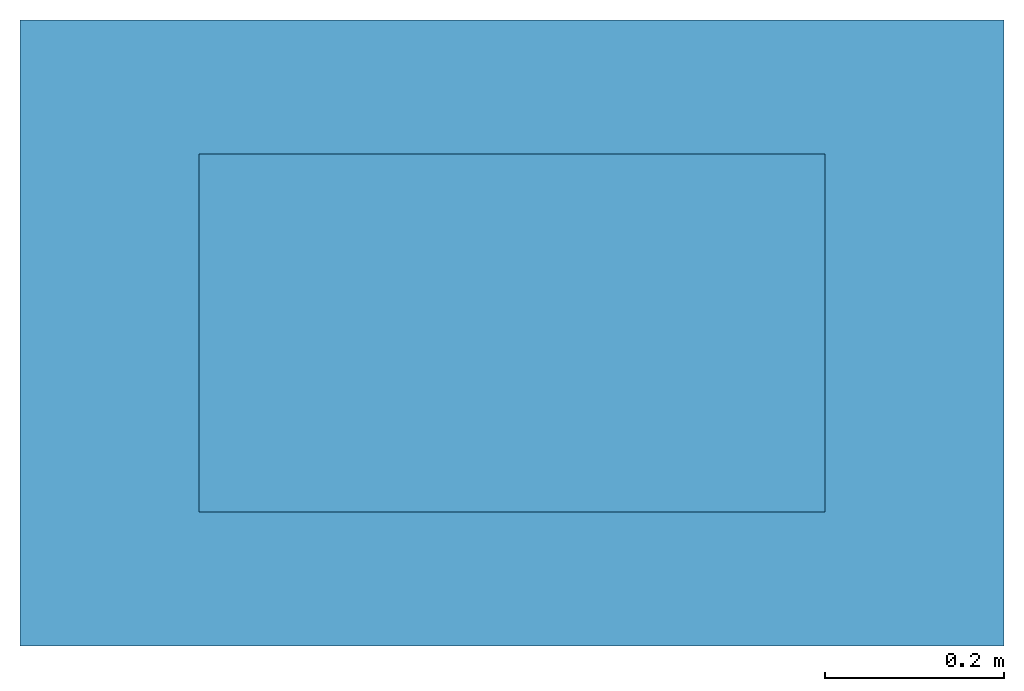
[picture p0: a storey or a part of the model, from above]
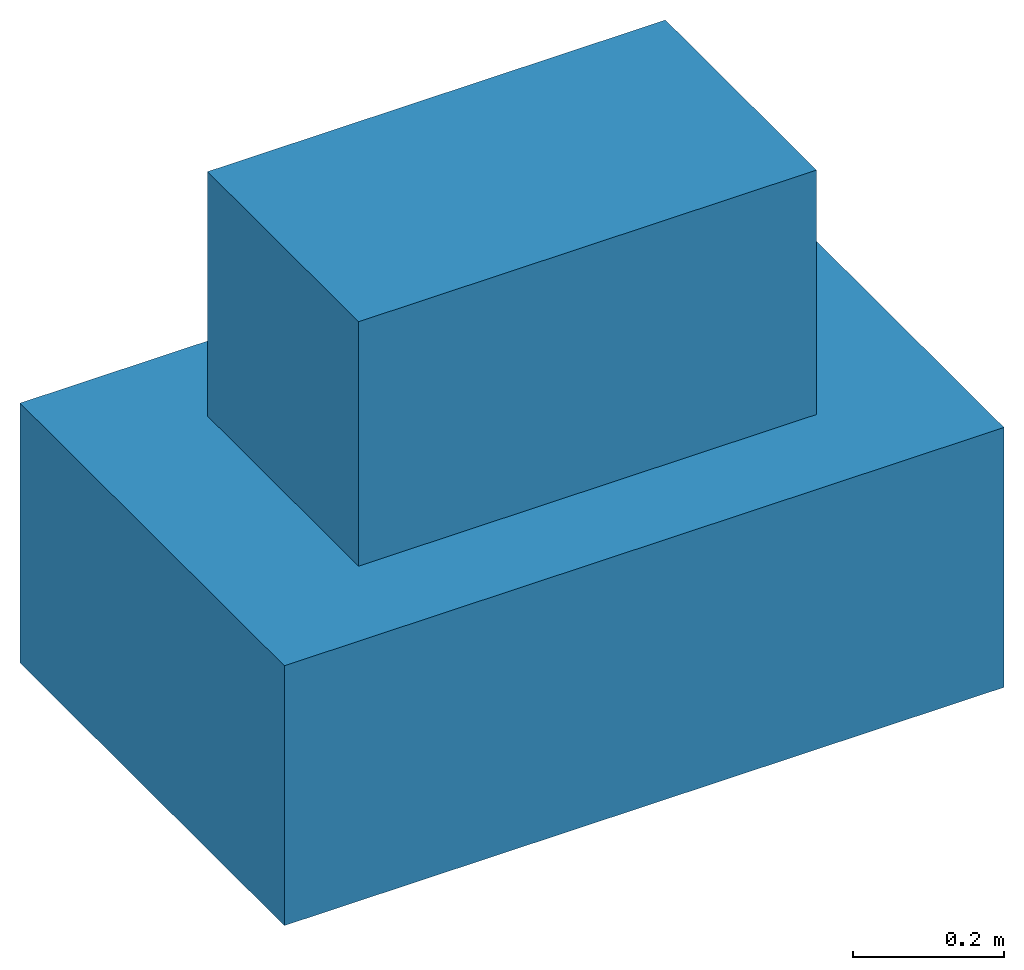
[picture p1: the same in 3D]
Properties of the parts of a building model (IFC2X3), part 1 of 5

# File
Description: ViewDefinition [CoordinationView]
File name: gmtso-a-200-1-0001.ifc (Edited by Naviate Simple BIM 2022 version 6)
Time: 2026-03-17T17:04:53+01:00
Written by: ODA SDAI 24.12
Made in: Autodesk Revit 25.4.20.11 (ENU) - IFC 25.4.0.27

# IfcProject, A181143
LongName: T2; Phase: Detaljprosjekt

# IfcSite (9)
Name | RefLatitude | RefLongitude | RefElevation (mm) | Reference latitude | Reference elevation | Reference longitude
ENGM | 33, 12, 51, 119999 | -97, -7, -51, -239999 | -4.85124e-10
 | 33, 12, 51, 119999 | -97, -7, -51, -239999 | 0
 | 33, 12, 51, 119999 | -97, -7, -51, -239999 | 0 | 33, 12, 51, 119999 | 0 | -97, -7, -51, -239999
4 x ENGM | 59, 54, 49, 759826 | 10, 44, 19, 467315 | 0 | 59, 54, 49, 759826 | 0 | 10, 44, 19, 467315 | MagiCAD Pset_Site - Name: ENGM
Gardermoen
Default | 59, 54, 49, 759826 | 10, 44, 19, 467315 | 0

# IfcBuilding (9)
Name
TS | LongName: TS; Pset_BuildingCommon - NumberOfStoreys: 16
2 x mc-building
4 x TS | MagiCAD Pset_Building - Building name: TS
TS
 | Pset_BuildingCommon - NumberOfStoreys: 13

# IfcBuildingStorey (16)
Name | In | Elevation (mm) | Name
Nivå C | mc-building | 200300
Nivå D | mc-building | 204000
Nivå D + 1,2 m | mc-building | 205200
Nivå C | mc-building | 200300 | Nivå C
Nivå D | mc-building | 204000 | Nivå D
Nivå D + 1,2 m | mc-building | 205200 | Nivå D + 1,2 m
4 x Nivå D | TS | 204000 | Nivå D
D | TS | 0
C | TS | 0
B | TS | 0
A | TS | 0
2 x Nivå C | TS | 200300 | Nivå C

# IfcBuildingStorey: Level:8mm Head (2)
Name | LongName | Elevation (mm)
Nivå C | Nivå C | 200300 | Pset_ProductRequirements - Name: Nivå C; sets with these values: 2
Nivå D | Nivå D | 204000 | Pset_AirSideSystemInformation - Name: Nivå D; sets with these values: 2

# IfcBuildingStorey: Level:T2 - Kote (4)
In: TS
Name | LongName | Elevation (mm) | Pset_AirSideSystemInformation, Name | Pset_AirSideSystemInformation, sets with these values
Nivå C + 2,03 m | Nivå C + 2,03 m | 202330 | Nivå C + 2,03 m | 2
Nivå D | Nivå D | 204000 | Nivå D | 2
Nivå D + 1,2 m | Nivå D + 1,2 m | 205200 | Pset_ProductRequirements - Name: Nivå D + 1,2 m; sets with these values: 2
Nivå E | Nivå E | 207370 | Nivå E | 2

# IfcBeam: 10*150 (3)
In: D
Description: 10*150
Pset_BeamCommon - LoadBearing: no
ePset_SimplebimBasicQuantities - Height (Simplebim): 10 mm; Width (Simplebim): 150 mm
ePset_Simplebim - Assembly Level: Leaf
AVINOR - 07_Fase: F90; 06_Omrade: TS; 01_Lufthavnkode: ENGM
Tekla Common - Grade: S355; Name: STÅLBJELKE; Profile: 10*150; Class: 330; Bottom elevation: +206.915; Top elevation: +206.925
Name | Reference = Part mark | Area, sides, net (Simplebim) (m2) | Weight, as steel (Simplebim) (kg) | Volume, net (Simplebim) (m3) | Length (Simplebim) (mm) | 02_Prosjekt | 04_Kontrakt | 03_Ansvar | 08_Status | Splitting | Assembly mark
STÅLBJELKE | DSB-8061(?) | 1.53612 | 56.4142 | 0.00718652 | 4791.01 | T1 | FDV | FDV | S2 | ORIGINAL | SB-3691(?) | Material: STEEL/S355; Tekla Quantity - VOLUME_GROSS: 0.00718 m3; VOLUME_NET: 0.00718 m3; AREA_NET: 1.53612 m2; AREA_GROSS: 1.53612 m2; WEIGTH_GROSS: 56.4142 kg; Heigth: 10 mm; Width: 150 mm; Length: 4791.01 mm; WEIGTH_NET: 56.4142 kg
STÅLBJELKE | DSB-8066(?) | 0.492661 | 18.018 | 0.00229529 | 1530 | T1 | FDV | FDV | S2 | RESULT | SB-3707(?)
STÅLBJELKE | DSB-8058(?) | 2.05458 | 75.4918 | 0.00961679 | 6411 | T20100 | 72274 | 72101 | S4 | RESULT | SB-3703(?) | AVINOR - 05_ID-nummer: +TS=223.001

# IfcBeam: 10*180, STÅLBJELKE
In: D
Description: 10*180; Material: STEEL/S355
Pset_BeamCommon - Reference: DSB-21700(?); LoadBearing: no
ePset_LocationTool - Splitting: ORIGINAL
ePset_Simplebim - Assembly Level: Leaf
Tekla Common - Assembly mark: SB-12634(?); Grade: S355; Bottom elevation: +206.790; Name: STÅLBJELKE; Part mark: DSB-21700(?); Profile: 10*180; Top elevation: +206.800; Class: 330
Tekla Quantity - VOLUME_GROSS: 0.01076 m3; VOLUME_NET: 0.01076 m3; WEIGTH_GROSS: 84.4974 kg; WEIGTH_NET: 84.4974 kg; AREA_GROSS: 2.276 m2; AREA_NET: 2.276 m2; Heigth: 10 mm; Width: 180 mm; Length: 5980 mm
AVINOR - 08_Status: S4; 07_Fase: F90; 05_ID-nummer: +TS=223.008; 02_Prosjekt: T20100; 04_Kontrakt: 72233; 03_Ansvar: 72101; 06_Omrade: TS; 01_Lufthavnkode: ENGM
ePset_SimplebimBasicQuantities - Volume, net (Simplebim): 0.010764 m3; Weight, as steel (Simplebim): 84.4974 kg; Area, sides, net (Simplebim): 2.276 m2; Height (Simplebim): 10 mm; Width (Simplebim): 180 mm; Length (Simplebim): 5980 mm

# IfcBeam: 10*220 (3)
In: D
Description: 10*220
AVINOR - 08_Status: S4; 07_Fase: F90; 04_Kontrakt: 72274; 05_ID-nummer: +TS=223.001; 02_Prosjekt: T20100; 03_Ansvar: 72101; 06_Omrade: TS; 01_Lufthavnkode: ENGM
Tekla Common - Grade: S355; Profile: 10*220; Name: STÅLBJELKE; Class: 330; Bottom elevation: +206.915; Top elevation: +206.925
Pset_BeamCommon - LoadBearing: no
ePset_Simplebim - Assembly Level: Leaf
ePset_LocationTool - Splitting: RESULT
ePset_SimplebimBasicQuantities - Height (Simplebim): 10 mm; Width (Simplebim): 220 mm
Name | Part mark = Reference | Assembly mark | Area, sides, net (Simplebim) (m2) | Weight, as steel (Simplebim) (kg) | Volume, net (Simplebim) (m3) | Length (Simplebim) (mm)
2 x STÅLBJELKE | DSB-8060(?) | SB-3690(?) | 2.94895 | 110.549 | 0.0140826 | 6401
STÅLBJELKE | DSB-8059(?) | SB-3695(?) | 2.79255 | 104.677 | 0.0133346 | 6061

# IfcBeam: 4*595 (5)
In: D
Description: 4*595
AVINOR - 08_Status: S4; 07_Fase: F90; 04_Kontrakt: 72717; 02_Prosjekt: T20100; 05_ID-nummer: +TS=221.014; 03_Ansvar: 72101; 06_Omrade: TS; 01_Lufthavnkode: ENGM
Tekla Common - Grade: S355; Name: STÅLBJELKE; Bottom elevation: +206.505; Class: 330; Top elevation: +207.100; Profile: 4*595
ePset_Simplebim - Assembly Level: Leaf
Pset_BeamCommon - LoadBearing: no
Name | Material | Part mark = Reference | Assembly mark | Volume, net (Simplebim) (m3) | Area, sides, net (Simplebim) (m2) | Length (Simplebim) (mm) | Width (Simplebim) (mm) | Height (Simplebim) (mm) | Weight, as steel (Simplebim) (kg) | Splitting | VOLUME_GROSS (m3) | AREA_NET (m2) | WEIGTH_GROSS (kg) | AREA_GROSS (m2) | VOLUME_NET (m3) | Length (mm) | Heigth (mm) | Width (mm) | WEIGTH_NET (kg)
STÅLBJELKE | STEEL/S355 | DSB-24371(?) | SB-7501(?) | 0.00986281 | 4.9715 | 4232.91 | 74.3506 | 595 | 77.423 | ORIGINAL | 0.01008 | 4.9715 | 79.1282 | 5.07865 | 0.00986 | 4235.31 | 4 | 595 | 77.423
STÅLBJELKE | STEEL/S355 | DSB-24372(?) | SB-7500(?) | 0.00832178 | 4.19363 | 3495.28 | 50.3079 | 595 | 65.326 | ORIGINAL | 0.00831 | 4.19363 | 65.3262 | 4.19363 | 0.00833 | 3496.56 | 4 | 595 | 65.326
STÅLBJELKE | STEEL/S355 | DSB-24373(?) | SB-7499(?) | 0.00864702 | 4.35733 | 3632.5 | 39.8393 | 595 | 67.8791 | ORIGINAL | 0.00865 | 4.35733 | 67.8791 | 4.35733 | 0.00865 | 3633.2 | 4 | 595 | 67.8791
STÅLBJELKE | STEEL/S355 | DSB-24375(?) | SB-7498(?) | 0.00901992 | 4.54504 | 3788.23 | 55.5964 | 595 | 70.8064 | ORIGINAL | 0.00902 | 4.54504 | 70.8065 | 4.54504 | 0.00902 | 3789.89 | 4 | 595 | 70.8064
STÅLBJELKE |  | DSB-24374(?) | SB-7497(?) | 0.00682394 | 3.4403 | 2868 | 51 | 596 | 53.5679 | RESULT

# IfcBeam: A255 - beslag mellom glassvegg&dekke - brannskille - nivåD SBØ bagasjehall-ensidig:A255 - Beslag_112.5 (3)
In: Nivå E
Type - PredefinedType: BEAM
Type - Pset_BeamCommon - LoadBearing: yes
ePset_SimplebimBasicQuantities - Height (Simplebim): 112 mm; Width (Simplebim): 65 mm
ePset_LocationTool - Splitting: RESULT
Pset_QuantityTakeOff - Reference: A255 - Beslag_112.5; sets with these values: 2
Pset_BeamCommon - IsExternal: no; Reference: A255 - Beslag_112.5
ePset_Simplebim - Assembly Level: Leaf
AVINOR - 07_Fase: F90; 03_Ansvar: FDV; 08_Status: S2; 04_Kontrakt: 72274; 06_Omrade: TS; 01_Lufthavnkode: ENGM
Name (A255 - beslag mellom glassvegg&dekke - brannskille - nivåD SBØ bagasjehall-ensidig:A255 - Beslag_112.5:...) | Weight, as steel (Simplebim) (kg) | Length (Simplebim) (mm) | Area, sides, net (Simplebim) (m2) | Volume, net (Simplebim) (m3)
25088858 | 6.79764 | 4546 | 1.74135 | 0.000865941
25066476 | 18.147 | 12135 | 4.64809 | 0.00231172
26879168 | 18.147 | 12135 | 4.64809 | 0.00231172

# IfcBeam: D12 (6)
In: D
Description: D12; Material: STEEL/S355
ePset_SimplebimBasicQuantities - Volume, net (Simplebim): 0.0000112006 m3; Weight, as steel (Simplebim): 0.0879245 kg; Width (Simplebim): 12 mm; Height (Simplebim): 12 mm; Length (Simplebim): 110 mm; Area, sides, net (Simplebim): 0.00424478 m2
AVINOR - 08_Status: S4; 07_Fase: F90; 02_Prosjekt: T20100; 05_ID-nummer: +TS=223.013; 04_Kontrakt: 72233; 03_Ansvar: 72101; 06_Omrade: TS; 01_Lufthavnkode: ENGM
ePset_LocationTool - Splitting: ORIGINAL
ePset_Simplebim - Assembly Level: Leaf
Pset_BeamCommon - LoadBearing: no; Reference: DSB-22016(?)
Tekla Quantity - VOLUME_NET: 0.00001 m3; VOLUME_GROSS: 0.00001 m3; WEIGTH_NET: 0.08792 kg; WEIGTH_GROSS: 0.08792 kg; Heigth: 12 mm; Width: 12 mm; Length: 110 mm; AREA_GROSS: 0.00424 m2; AREA_NET: 0.00424 m2
Tekla Common - Grade: S355; Profile: D12; Name: STÅLBJELKE; Top elevation: +203.846; Bottom elevation: +203.834; Part mark: DSB-22016(?); Class: 330; Assembly mark: SB-13164(?)

# IfcBeam: D16 (2)
In: D
Description: D16; Material: STEEL/S355
ePset_SimplebimBasicQuantities - Width (Simplebim): 16 mm; Length (Simplebim): 16 mm; Height (Simplebim): 660 mm; Area, sides, net (Simplebim): 0.0326911 m2; Weight, as steel (Simplebim): 0.937861 kg; Volume, net (Simplebim): 0.000119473 m3
AVINOR - 08_Status: S4; 07_Fase: F90; 02_Prosjekt: T20100; 05_ID-nummer: +TS=223.013; 04_Kontrakt: 72233; 03_Ansvar: 72101; 06_Omrade: TS; 01_Lufthavnkode: ENGM
ePset_Simplebim - Assembly Level: Leaf
Pset_BeamCommon - Reference: DSM-555(?); LoadBearing: no
ePset_LocationTool - Splitting: ORIGINAL
Tekla Quantity - WEIGTH_GROSS: 0.93786 kg; WEIGTH_NET: 0.93786 kg; Heigth: 16 mm; Width: 16 mm; Length: 660 mm; AREA_NET: 0.03269 m2; AREA_GROSS: 0.03269 m2; VOLUME_GROSS: 0.00012 m3; VOLUME_NET: 0.00012 m3
Tekla Common - Grade: S355; Profile: D16; Part mark: DSM-555(?); Name: STÅLMONTASJE; Bottom elevation: +203.310; Class: 370; Assembly mark: SM-499(?); Top elevation: +203.970

# IfcBeam: D26.75 (4)
In: D
Description: D26.75; Material: STEEL/Steel_Undefined
ePset_SimplebimBasicQuantities - Weight, as steel (Simplebim): 0.0623505 kg; Height (Simplebim): 14.8 mm; Area, sides, net (Simplebim): 0.00230294 m2; Width (Simplebim): 26.75 mm; Length (Simplebim): 26.75 mm; Volume, net (Simplebim): 0.00000794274 m3
AVINOR - 08_Status: S4; 07_Fase: F90; 02_Prosjekt: T20100; 05_ID-nummer: +TS=223.013; 04_Kontrakt: 72233; 03_Ansvar: 72101; 06_Omrade: TS; 01_Lufthavnkode: ENGM
ePset_Simplebim - Assembly Level: Leaf
Tekla Common - Profile: D26.75; Part mark: DSSP-0(?); Class: 380; Name: MUTTER; Assembly mark: SSP-0(?); Grade: Steel_Undefined
Tekla Quantity - VOLUME_NET: 0.00001 m3; VOLUME_GROSS: 0.00001 m3; Length: 14.8 mm; WEIGTH_NET: 0.06235 kg; WEIGTH_GROSS: 0.06235 kg; AREA_GROSS: 0.0023 m2; AREA_NET: 0.0023 m2; Heigth: 26.75 mm; Width: 26.75 mm
Pset_BeamCommon - Reference: DSSP-0(?); LoadBearing: no
ePset_LocationTool - Splitting: ORIGINAL
Name | Bottom elevation | Top elevation
2 x MUTTER | +203.343 | +203.358
2 x MUTTER | +203.945 | +203.960

# IfcBeam: DLB400*815-700*420 (6)
In: D
Description: DLB400*815-700*420
Pset_BeamCommon - LoadBearing: no
ePset_SimplebimBasicQuantities - Width (Simplebim): 700 mm
Tekla Common - Name: PREFABBJELKE; Top elevation: +203.795; Grade: C45/55; Bottom elevation: +202.980; Class: 130; Profile: DLB400*815-700*420
ePset_Simplebim - Assembly Level: Leaf
AVINOR - 07_Fase: F90; 02_Prosjekt: T1; 04_Kontrakt: FDV; 03_Ansvar: FDV; 08_Status: S2; 06_Omrade: TS; 01_Lufthavnkode: ENGM
Name | Reference = Part mark | Volume, net (Simplebim) (m3) | Area, sides, net (Simplebim) (m2) | Height (Simplebim) (mm) | Length (Simplebim) (mm) | Weight, as steel (Simplebim) (kg) | Assembly mark | Splitting
PREFABBJELKE | Concrete-9026(?) | 3.76884 | 26.2761 | 815 | 8470 | 29585.4 | PB-322(?) | ORIGINAL | Material: CONCRETE/C45/55; Tekla Quantity - WEIGTH_GROSS: 9188.26 kg; VOLUME_NET: 3.76884 m3; WEIGTH_NET: 9045.22 kg; AREA_NET: 26.2761 m2; AREA_GROSS: 26.5681 m2; Heigth: 815 mm; Width: 700 mm; Length: 8470 mm; VOLUME_GROSS: 3.82844 m3
PREFABBJELKE | Concrete-4942(?) | 3.83664 | 26.7306 | 815 | 8620 | 30117.6 | PB-171(?) | ORIGINAL | Material: CONCRETE/C45/55; Tekla Quantity - WEIGTH_GROSS: 9350.98 kg; VOLUME_NET: 3.83664 m3; WEIGTH_NET: 9207.94 kg; AREA_NET: 26.7306 m2; AREA_GROSS: 27.0226 m2; Heigth: 815 mm; Width: 700 mm; Length: 8620 mm; VOLUME_GROSS: 3.89624 m3
PREFABBJELKE | Concrete-4942(?) | 2.76737 | 19.4552 | 816 | 6123 | 21723.9 | PB-171(?) | RESULT
PREFABBJELKE | Concrete-4942(?) | 1.17436 | 8.8839 | 816 | 2730 | 9218.73 | PB-171(?) | RESULT
PREFABBJELKE | Concrete-9026(?) | 2.69957 | 19.0007 | 816 | 5973 | 21191.6 | PB-322(?) | RESULT
PREFABBJELKE | Concrete-9031(?) | 1.17436 | 8.8839 | 816 | 2730 | 9218.73 | PB-327(?) | RESULT

# IfcBeam: HE180A, STÅLBJELKE
In: D
Description: HE180A; Material: STEEL/S355
Tekla Common - Grade: S355; Name: STÅLBJELKE; Bottom elevation: +206.929; Assembly mark: SB-3300(?); Part mark: DSB-7520(?); Profile: HE180A; Class: 330; Top elevation: +207.100
AVINOR - 08_Status: S4; 07_Fase: F90; 04_Kontrakt: 72717; 02_Prosjekt: T20100; 05_ID-nummer: +TS=221.014; 03_Ansvar: 72101; 06_Omrade: TS; 01_Lufthavnkode: ENGM
ePset_SimplebimBasicQuantities - Weight, as steel (Simplebim): 64.561 kg; Length (Simplebim): 2017.32 mm; Volume, net (Simplebim): 0.00822433 m3; Area, sides, net (Simplebim): 2.00413 m2; Width (Simplebim): 180 mm; Height (Simplebim): 171 mm
Tekla Quantity - Length: 2017.32 mm; VOLUME_NET: 0.00822 m3; WEIGTH_NET: 64.561 kg; VOLUME_GROSS: 0.00913 m3; AREA_GROSS: 2.06574 m2; AREA_NET: 2.00413 m2; Width: 180 mm; Heigth: 171 mm; WEIGTH_GROSS: 71.6577 kg
Pset_BeamCommon - LoadBearing: no; Reference: DSB-7520(?)
ePset_Simplebim - Assembly Level: Leaf
ePset_LocationTool - Splitting: ORIGINAL

# IfcBeam: HEA240, STÅLBJELKE
In: D
Description: HEA240
AVINOR - 08_Status: S4; 07_Fase: F90; 02_Prosjekt: T20100; 05_ID-nummer: +TS=223.013; 04_Kontrakt: 72233; 03_Ansvar: 72101; 06_Omrade: TS; 01_Lufthavnkode: ENGM
ePset_Simplebim - Assembly Level: Leaf
ePset_LocationTool - Splitting: RESULT
ePset_SimplebimBasicQuantities - Weight, as steel (Simplebim): 211.457 kg; Area, sides, net (Simplebim): 5.19555 m2; Volume, net (Simplebim): 0.0269372 m3; Height (Simplebim): 230 mm; Width (Simplebim): 240 mm; Length (Simplebim): 3687 mm
Tekla Common - Grade: S355; Name: STÅLBJELKE; Profile: HEA240; Assembly mark: SB-9965(?); Bottom elevation: +203.155; Top elevation: +203.385; Part mark: DSB-20486(?); Class: 330
Pset_BeamCommon - LoadBearing: no; Reference: DSB-20486(?)

# IfcBeam: HSQ150*5-20*200-12*400, STÅLBJELKE
In: D
Description: HSQ150*5-20*200-12*400; Material: STEEL/S355
Tekla Quantity - AREA_NET: 9.08332 m2; AREA_GROSS: 9.08332 m2; WEIGTH_GROSS: 410.743 kg; WEIGTH_NET: 410.743 kg; VOLUME_NET: 0.05232 m3; VOLUME_GROSS: 0.05232 m3; Heigth: 162 mm; Width: 400 mm; Length: 5080 mm
ePset_SimplebimBasicQuantities - Area, sides, net (Simplebim): 9.08332 m2; Weight, as steel (Simplebim): 410.743 kg; Length (Simplebim): 5080 mm; Volume, net (Simplebim): 0.052324 m3; Height (Simplebim): 162 mm; Width (Simplebim): 400 mm
Tekla Common - Profile: HSQ150*5-20*200-12*400; Grade: S355; Top elevation: +207.530; Name: STÅLBJELKE; Part mark: DSB-0(?); Assembly mark: SB-0(?); Class: 330; Bottom elevation: +207.368
ePset_Simplebim - Assembly Level: Leaf
AVINOR - 08_Status: S2; 07_Fase: F20; 02_Prosjekt: A181143; 03_Ansvar: 187259; 06_Omrade: TS; 01_Lufthavnkode: ENGM
Pset_BeamCommon - LoadBearing: no; Reference: DSB-0(?)
ePset_LocationTool - Splitting: ORIGINAL

# IfcBeam: IPE240, STÅLBJELKE
In: D
Description: IPE240
ePset_LocationTool - Splitting: RESULT
ePset_SimplebimBasicQuantities - Weight, as steel (Simplebim): 135.86 kg; Area, sides, net (Simplebim): 4.41787 m2; Width (Simplebim): 120 mm; Height (Simplebim): 240 mm; Length (Simplebim): 4654 mm; Volume, net (Simplebim): 0.017307 m3
Tekla Common - Grade: S355; Assembly mark: SB-3244(?); Name: STÅLBJELKE; Top elevation: +207.040; Profile: IPE240; Bottom elevation: +206.800; Part mark: DSB-7536(?); Class: 330
ePset_Simplebim - Assembly Level: Leaf
AVINOR - 07_Fase: F90; 02_Prosjekt: T1; 04_Kontrakt: FDV; 03_Ansvar: FDV; 08_Status: S2; 06_Omrade: TS; 01_Lufthavnkode: ENGM
Pset_BeamCommon - LoadBearing: no; Reference: DSB-7536(?)

# IfcBeam: L100*75*10, STÅLBJELKE
In: D
Description: L100*75*10; Material: STEEL/S355
ePset_SimplebimBasicQuantities - Width (Simplebim): 300.021 mm; Weight, as steel (Simplebim): 10.9997 kg; Area, sides, net (Simplebim): 0.30223 m2; Volume, net (Simplebim): 0.00140124 m3; Length (Simplebim): 732.931 mm; Height (Simplebim): 100 mm
Pset_BeamCommon - LoadBearing: no; Reference: DSB-9035(?)
AVINOR - 08_Status: S4; 07_Fase: F90; 04_Kontrakt: 72274; 05_ID-nummer: +TS=223.001; 02_Prosjekt: T20100; 03_Ansvar: 72101; 06_Omrade: TS; 01_Lufthavnkode: ENGM
ePset_Simplebim - Assembly Level: Leaf
Tekla Common - Grade: S355; Profile: L100*75*10; Name: STÅLBJELKE; Top elevation: +207.005; Assembly mark: SB-4427(?); Part mark: DSB-9035(?); Class: 330; Bottom elevation: +206.905
Tekla Quantity - VOLUME_NET: 0.0014 m3; WEIGTH_NET: 10.9997 kg; AREA_GROSS: 0.35517 m2; Length: 924.03 mm; VOLUME_GROSS: 0.00165 m3; Width: 10 mm; Heigth: 100 mm; AREA_NET: 0.30223 m2; WEIGTH_GROSS: 12.9587 kg
ePset_LocationTool - Splitting: ORIGINAL

# IfcBeam: L120*80*10, STÅLBJELKE
In: D
Description: L120*80*10
AVINOR - 08_Status: S4; 07_Fase: F90; 02_Prosjekt: T1; 04_Kontrakt: FDV; 03_Ansvar: FDV; 06_Omrade: TS; 01_Lufthavnkode: ENGM
ePset_LocationTool - Splitting: RESULT
Pset_BeamCommon - Reference: DSB-11255(?); LoadBearing: no
ePset_Simplebim - Assembly Level: Leaf
ePset_SimplebimBasicQuantities - Weight, as steel (Simplebim): 47.0027 kg; Volume, net (Simplebim): 0.0059876 m3; Height (Simplebim): 120 mm; Width (Simplebim): 80 mm; Length (Simplebim): 3185 mm; Area, sides, net (Simplebim): 1.26645 m2
Tekla Common - Grade: S355; Bottom elevation: +206.780; Part mark: DSB-11255(?); Top elevation: +206.900; Name: STÅLBJELKE; Profile: L120*80*10; Assembly mark: SB-6293(?); Class: 330

# IfcBeam: L40*5 (4)
In: D
Description: L40*5; Material: STEEL/S355
AVINOR - 08_Status: S4; 07_Fase: F90; 02_Prosjekt: T20100; 05_ID-nummer: +TS=222.012; 04_Kontrakt: 72233; 03_Ansvar: 72101; 06_Omrade: TS; 01_Lufthavnkode: ENGM
ePset_Simplebim - Assembly Level: Leaf
Pset_BeamCommon - LoadBearing: no
ePset_SimplebimBasicQuantities - Width (Simplebim): 40 mm; Height (Simplebim): 40 mm
ePset_LocationTool - Splitting: ORIGINAL
Tekla Common - Grade: S355; Top elevation: +207.315; Profile: L40*5; Name: STÅLBJELKE; Assembly mark: SB-12652(?); Bottom elevation: +207.275; Class: 330
Tekla Quantity - Heigth: 40 mm; Width: 40 mm
Name | Reference = Part mark | Length (Simplebim) (mm) = Length (mm) | Weight, as steel (Simplebim) (kg) = WEIGTH_NET (kg) | Area, sides, net (Simplebim) (m2) | Volume, net (Simplebim) (m3) | VOLUME_GROSS (m3) | VOLUME_NET (m3) | AREA_GROSS (m2) | AREA_NET (m2) | WEIGTH_GROSS (kg)
STÅLBJELKE | DSB-24535(?) | 1848.34 | 5.35295 | 0.291955 | 0.000681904 | 0.0007 | 0.00068 | 0.28649 | 0.29195 | 5.4991
STÅLBJELKE | DSB-24534(?) | 2369.08 | 6.89792 | 0.375874 | 0.000878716 | 0.0009 | 0.00088 | 0.36721 | 0.37587 | 7.04837
STÅLBJELKE | DSB-24533(?) | 897.95 | 2.58574 | 0.141384 | 0.000329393 | 0.00034 | 0.00034 | 0.13918 | 0.14138 | 2.67154
STÅLBJELKE | DSB-24532(?) | 2170 | 6.31827 | 0.344311 | 0.000804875 | 0.00082 | 0.0008 | 0.33635 | 0.34431 | 6.45608

# IfcBeam: L80*10 (3)
In: D
Description: L80*10
ePset_SimplebimBasicQuantities - Height (Simplebim): 80 mm
ePset_Simplebim - Assembly Level: Leaf
AVINOR - 07_Fase: F90; 02_Prosjekt: T1; 04_Kontrakt: FDV; 03_Ansvar: FDV; 08_Status: S2; 06_Omrade: TS; 01_Lufthavnkode: ENGM
Pset_BeamCommon - LoadBearing: no
Tekla Common - Grade: S355; Name: STÅLBJELKE; Profile: L80*10; Bottom elevation: +207.020; Class: 330; Top elevation: +207.100
Name | Weight, as steel (Simplebim) (kg) | Width (Simplebim) (mm) | Length (Simplebim) (mm) | Area, sides, net (Simplebim) (m2) | Volume, net (Simplebim) (m3) | Reference = Part mark | Assembly mark | Splitting
STÅLBJELKE | 169.207 | 80.0002 | 14610 | 4.6044 | 0.021555 | DSB-7521(?) | SB-3301(?) | ORIGINAL | Material: STEEL/S355; Tekla Quantity - AREA_NET: 4.6044 m2; Heigth: 80.0002 mm; VOLUME_GROSS: 0.02206 m3; WEIGTH_NET: 169.207 kg; Length: 14610 mm; AREA_GROSS: 4.54371 m2; VOLUME_NET: 0.02155 m3; Width: 80 mm; WEIGTH_GROSS: 173.18 kg
STÅLBJELKE | 32.9111 | 80 | 2795 | 0.8974 | 0.0041925 | DSB-7523(?) | SB-3303(?) | RESULT
STÅLBJELKE | 32.9111 | 80 | 2795 | 0.897401 | 0.0041925 | DSB-7522(?) | SB-3302(?) | RESULT

# IfcBeam: L90*9 (78)
In: D
Description: L90*9; Material: STEEL/S355
ePset_SimplebimBasicQuantities - Weight, as steel (Simplebim): 1.81216 kg; Area, sides, net (Simplebim): 0.0570776 m2; Width (Simplebim): 90 mm; Height (Simplebim): 90 mm; Length (Simplebim): 149.999 mm; Volume, net (Simplebim): 0.000230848 m3
AVINOR - 08_Status: S4; 07_Fase: F90; 04_Kontrakt: 72717; 02_Prosjekt: T20100; 05_ID-nummer: +TS=221.014; 03_Ansvar: 72101; 06_Omrade: TS; 01_Lufthavnkode: ENGM
ePset_LocationTool - Splitting: ORIGINAL
Tekla Common - Profile: L90*9; Grade: S355; Name: STÅLBJELKE; Part mark: DSB-19624(?); Class: 330
ePset_Simplebim - Assembly Level: Leaf
Tekla Quantity - VOLUME_NET: 0.00022 m3; VOLUME_GROSS: 0.00022 m3; Heigth: 90 mm; Width: 90 mm
Pset_BeamCommon - Reference: DSB-19624(?); LoadBearing: no
Name | Assembly mark | Bottom elevation | Top elevation | WEIGTH_NET (kg) | Length (mm) | AREA_NET (m2) | AREA_GROSS (m2) | WEIGTH_GROSS (kg)
STÅLBJELKE | SB-7501(?) | +207.010 | +207.100 | 1.81431 | 150.177 | 0.05714 | 0.05271 | 1.82727
STÅLBJELKE | SB-7501(?) | +206.505 | +206.595 | 1.81431 | 150.177 | 0.05714 | 0.05271 | 1.82727
STÅLBJELKE | SB-7501(?) | +207.010 | +207.100 | 1.81579 | 150.299 | 0.05719 | 0.05276 | 1.82877
STÅLBJELKE | SB-7501(?) | +206.505 | +206.595 | 1.81579 | 150.299 | 0.05719 | 0.05276 | 1.82877
STÅLBJELKE | SB-7501(?) | +207.010 | +207.100 | 1.81516 | 150.247 | 0.05717 | 0.05274 | 1.82813
STÅLBJELKE | SB-7501(?) | +206.505 | +206.595 | 1.81516 | 150.247 | 0.05717 | 0.05274 | 1.82813
STÅLBJELKE | SB-7501(?) | +207.010 | +207.100 | 1.81069 | 149.877 | 0.05703 | 0.05261 | 1.82363
STÅLBJELKE | SB-7501(?) | +206.505 | +206.595 | 1.81069 | 149.877 | 0.05703 | 0.05261 | 1.82363
STÅLBJELKE | SB-7501(?) | +207.010 | +207.100 | 1.81294 | 150.063 | 0.0571 | 0.05267 | 1.82589
STÅLBJELKE | SB-7501(?) | +206.505 | +206.595 | 1.81294 | 150.063 | 0.0571 | 0.05267 | 1.82589
STÅLBJELKE | SB-7501(?) | +207.010 | +207.100 | 1.81236 | 150.016 | 0.05708 | 0.05267 | 1.82532
STÅLBJELKE | SB-7501(?) | +206.505 | +206.595 | 1.81236 | 150.016 | 0.05708 | 0.05267 | 1.82532
STÅLBJELKE | SB-7497(?) | +207.010 | +207.100 | 1.81228 | 150.009 | 0.05708 | 0.05265 | 1.82524
STÅLBJELKE | SB-7497(?) | +206.505 | +206.595 | 1.81228 | 150.009 | 0.05708 | 0.05265 | 1.82524
STÅLBJELKE | SB-7500(?) | +207.010 | +207.100 | 1.8119 | 149.978 | 0.05707 | 0.05265 | 1.82485
STÅLBJELKE | SB-7500(?) | +206.505 | +206.595 | 1.8119 | 149.978 | 0.05707 | 0.05265 | 1.82485
STÅLBJELKE | SB-7499(?) | +207.010 | +207.100 | 1.81206 | 149.991 | 0.05707 | 0.05265 | 1.82501
STÅLBJELKE | SB-7499(?) | +206.505 | +206.595 | 1.81206 | 149.991 | 0.05707 | 0.05265 | 1.82501
STÅLBJELKE | SB-7500(?) | +207.010 | +207.100 | 1.81182 | 149.97 | 0.05707 | 0.05265 | 1.82477
STÅLBJELKE | SB-7500(?) | +206.505 | +206.595 | 1.81182 | 149.97 | 0.05707 | 0.05265 | 1.82477
STÅLBJELKE | SB-7500(?) | +207.010 | +207.100 | 1.81213 | 149.997 | 0.05708 | 0.05265 | 1.82509
STÅLBJELKE | SB-7500(?) | +207.010 | +207.100 | 1.81211 | 149.995 | 0.05708 | 0.05265 | 1.82506
STÅLBJELKE | SB-7500(?) | +207.010 | +207.100 | 1.8121 | 149.994 | 0.05708 | 0.05265 | 1.82505
STÅLBJELKE | SB-7500(?) | +207.010 | +207.100 | 1.80857 | 149.702 | 0.05697 | 0.05255 | 1.82149
STÅLBJELKE | SB-7500(?) | +207.010 | +207.100 | 1.81203 | 149.988 | 0.05707 | 0.05265 | 1.82498
STÅLBJELKE | SB-7500(?) | +207.010 | +207.100 | 1.8088 | 149.721 | 0.05697 | 0.05255 | 1.82173
STÅLBJELKE | SB-7500(?) | +206.505 | +206.595 | 1.81213 | 149.997 | 0.05708 | 0.05265 | 1.82509
STÅLBJELKE | SB-7500(?) | +206.505 | +206.595 | 1.81211 | 149.995 | 0.05708 | 0.05265 | 1.82506
STÅLBJELKE | SB-7500(?) | +206.505 | +206.595 | 1.8121 | 149.994 | 0.05708 | 0.05265 | 1.82505
STÅLBJELKE | SB-7500(?) | +206.505 | +206.595 | 1.80857 | 149.702 | 0.05697 | 0.05255 | 1.82149
STÅLBJELKE | SB-7500(?) | +206.505 | +206.595 | 1.81203 | 149.988 | 0.05707 | 0.05265 | 1.82498
STÅLBJELKE | SB-7500(?) | +206.505 | +206.595 | 1.8088 | 149.721 | 0.05697 | 0.05255 | 1.82173
STÅLBJELKE | SB-7501(?) | +207.010 | +207.100 | 1.81216 | 150 | 0.05708 | 0.05265 | 1.82513
STÅLBJELKE | SB-7501(?) | +206.505 | +206.595 | 1.81216 | 150 | 0.05708 | 0.05265 | 1.82513
2 x STÅLBJELKE | SB-7499(?) | +207.010 | +207.100 | 1.81216 | 150 | 0.05708 | 0.05265 | 1.82513
2 x STÅLBJELKE | SB-7499(?) | +207.010 | +207.100 | 1.81216 | 149.999 | 0.05708 | 0.05265 | 1.82511
2 x STÅLBJELKE | SB-7499(?) | +207.010 | +207.100 | 1.81216 | 150 | 0.05708 | 0.05265 | 1.82511
STÅLBJELKE | SB-7498(?) | +207.010 | +207.100 | 1.81243 | 150.022 | 0.05708 | 0.05267 | 1.82539
STÅLBJELKE | SB-7498(?) | +207.010 | +207.100 | 1.81148 | 149.943 | 0.05707 | 0.05263 | 1.82443
2 x STÅLBJELKE | SB-7498(?) | +207.010 | +207.100 | 1.81218 | 150 | 0.05708 | 0.05265 | 1.82513
STÅLBJELKE | SB-7498(?) | +207.010 | +207.100 | 1.81311 | 150.077 | 0.05711 | 0.05268 | 1.82606
STÅLBJELKE | SB-7498(?) | +207.010 | +207.100 | 1.81216 | 150 | 0.05708 | 0.05265 | 1.82513
STÅLBJELKE | SB-7498(?) | +207.010 | +207.100 | 1.81351 | 150.111 | 0.05711 | 0.05269 | 1.82648
STÅLBJELKE | SB-7498(?) | +207.010 | +207.100 | 1.81216 | 149.999 | 0.05708 | 0.05265 | 1.82511
STÅLBJELKE | SB-7499(?) | +207.010 | +207.100 | 1.81213 | 149.997 | 0.05708 | 0.05265 | 1.82509
STÅLBJELKE | SB-7501(?) | +207.010 | +207.100 | 1.8126 | 150.035 | 0.05708 | 0.05267 | 1.82555
STÅLBJELKE | SB-7501(?) | +207.010 | +207.100 | 1.81223 | 150.005 | 0.05708 | 0.05265 | 1.82518
STÅLBJELKE | SB-7497(?) | +207.010 | +207.100 | 1.8111 | 149.911 | 0.05705 | 0.05263 | 1.82404
STÅLBJELKE | SB-7497(?) | +207.010 | +207.100 | 1.81216 | 150 | 0.05708 | 0.05265 | 1.82513
3 x STÅLBJELKE | SB-7497(?) | +207.010 | +207.100 | 1.81216 | 150 | 0.05708 | 0.05265 | 1.82511
STÅLBJELKE | SB-7497(?) | +206.505 | +206.595 | 1.8111 | 149.911 | 0.05705 | 0.05263 | 1.82404
STÅLBJELKE | SB-7497(?) | +206.505 | +206.595 | 1.81216 | 150 | 0.05708 | 0.05265 | 1.82513
3 x STÅLBJELKE | SB-7497(?) | +206.505 | +206.595 | 1.81216 | 150 | 0.05708 | 0.05265 | 1.82511
STÅLBJELKE | SB-7501(?) | +206.505 | +206.595 | 1.8126 | 150.035 | 0.05708 | 0.05267 | 1.82555
STÅLBJELKE | SB-7501(?) | +206.505 | +206.595 | 1.81223 | 150.005 | 0.05708 | 0.05265 | 1.82518
STÅLBJELKE | SB-7498(?) | +206.505 | +206.595 | 1.81243 | 150.022 | 0.05708 | 0.05267 | 1.82539
STÅLBJELKE | SB-7498(?) | +206.505 | +206.595 | 1.81148 | 149.943 | 0.05707 | 0.05263 | 1.82443
2 x STÅLBJELKE | SB-7498(?) | +206.505 | +206.595 | 1.81218 | 150 | 0.05708 | 0.05265 | 1.82513
STÅLBJELKE | SB-7498(?) | +206.505 | +206.595 | 1.81311 | 150.077 | 0.05711 | 0.05268 | 1.82606
STÅLBJELKE | SB-7498(?) | +206.505 | +206.595 | 1.81216 | 150 | 0.05708 | 0.05265 | 1.82513
STÅLBJELKE | SB-7499(?) | +206.505 | +206.595 | 1.81213 | 149.997 | 0.05708 | 0.05265 | 1.82509
2 x STÅLBJELKE | SB-7499(?) | +206.505 | +206.595 | 1.81216 | 150 | 0.05708 | 0.05265 | 1.82513
2 x STÅLBJELKE | SB-7499(?) | +206.505 | +206.595 | 1.81216 | 149.999 | 0.05708 | 0.05265 | 1.82511
2 x STÅLBJELKE | SB-7499(?) | +206.505 | +206.595 | 1.81216 | 150 | 0.05708 | 0.05265 | 1.82511
STÅLBJELKE | SB-7498(?) | +206.505 | +206.595 | 1.81351 | 150.111 | 0.05711 | 0.05269 | 1.82648
STÅLBJELKE | SB-7498(?) | +206.505 | +206.595 | 1.81216 | 149.999 | 0.05708 | 0.05265 | 1.82511

# IfcBeam: PL10*150 (12)
In: D
Description: PL10*150; Material: STEEL/S355
Tekla Quantity - VOLUME_NET: 0.00022 m3; VOLUME_GROSS: 0.00022 m3; Width: 10 mm; Heigth: 150 mm
AVINOR - 08_Status: S4; 07_Fase: F90; 04_Kontrakt: 72717; 02_Prosjekt: T20100; 05_ID-nummer: +TS=221.014; 03_Ansvar: 72101; 06_Omrade: TS; 01_Lufthavnkode: ENGM
Pset_BeamCommon - Reference: DSB-17433(?); LoadBearing: no
ePset_SimplebimBasicQuantities - Length (Simplebim): 195.946 mm; Weight, as steel (Simplebim): 1.71852 kg; Volume, net (Simplebim): 0.00021892 m3; Width (Simplebim): 10 mm; Height (Simplebim): 150 mm; Area, sides, net (Simplebim): 0.0500056 m2
ePset_Simplebim - Assembly Level: Leaf
ePset_LocationTool - Splitting: ORIGINAL
Tekla Common - Grade: S355; Bottom elevation: +206.833; Top elevation: +206.983; Name: STÅLBJELKE; Part mark: DSB-17433(?); Profile: PL10*150; Class: 330
Name | AREA_NET (m2) | WEIGTH_GROSS (kg) | AREA_GROSS (m2) | Length (mm) | WEIGTH_NET (kg) | Assembly mark
STÅLBJELKE | 0.05002 | 2.30727 | 0.02939 | 195.946 | 1.71852 | SB-7501(?)
STÅLBJELKE | 0.05002 | 2.30727 | 0.02939 | 195.946 | 1.71852 | SB-7498(?)
STÅLBJELKE | 0.05002 | 2.30727 | 0.02939 | 195.946 | 1.71852 | SB-7500(?)
2 x STÅLBJELKE | 0.05002 | 2.30727 | 0.02939 | 195.946 | 1.71852 | SB-7499(?)
STÅLBJELKE | 0.05002 | 2.30748 | 0.02939 | 195.965 | 1.71873 | SB-7499(?)
STÅLBJELKE | 0.04995 | 2.30535 | 0.02937 | 195.784 | 1.7166 | SB-7497(?)
STÅLBJELKE | 0.04999 | 2.30667 | 0.02937 | 195.896 | 1.71792 | SB-7500(?)
STÅLBJELKE | 0.04999 | 2.30698 | 0.02939 | 195.922 | 1.71823 | SB-7498(?)
STÅLBJELKE | 0.04999 | 2.30683 | 0.02939 | 195.909 | 1.71808 | SB-7498(?)
STÅLBJELKE | 0.05013 | 2.3119 | 0.02945 | 196.34 | 1.72315 | SB-7501(?)
STÅLBJELKE | 0.05003 | 2.30819 | 0.02939 | 196.024 | 1.71944 | SB-7500(?)

# IfcBeam: PL10*160 (7)
In: D
Description: PL10*160; Material: STEEL/S355
AVINOR - 08_Status: S4; 07_Fase: F90; 04_Kontrakt: 72717; 02_Prosjekt: T20100; 05_ID-nummer: +TS=221.014; 03_Ansvar: 72101; 06_Omrade: TS; 01_Lufthavnkode: ENGM
ePset_SimplebimBasicQuantities - Height (Simplebim): 10 mm; Width (Simplebim): 160 mm
ePset_Simplebim - Assembly Level: Leaf
Pset_BeamCommon - LoadBearing: no
ePset_LocationTool - Splitting: ORIGINAL
Tekla Common - Grade: S355; Bottom elevation: +206.823; Top elevation: +206.833; Name: STÅLBJELKE; Profile: PL10*160; Class: 330
Tekla Quantity - Width: 10 mm
Name | Length (Simplebim) (mm) = Length (mm) | Weight, as steel (Simplebim) (kg) | Area, sides, net (Simplebim) (m2) | Volume, net (Simplebim) (m3) | Reference = Part mark | Assembly mark | AREA_NET (m2) | WEIGTH_NET (kg) | Heigth (mm) | AREA_GROSS (m2) | WEIGTH_GROSS (kg) | VOLUME_NET (m3) = VOLUME_GROSS (m3)
4 x STÅLBJELKE | 260.001 | 3.26559 | 0.0915997 | 0.000415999 | DSB-18078(?) | SB-7496(?) | 0.0916 | 3.26559 | 160 | 0.0416 | 3.26561 | 0.00042
STÅLBJELKE | 260.001 | 3.26559 | 0.0915997 | 0.000415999 | DSB-18078(?) | SB-10861(?) | 0.0916 | 3.2654 | 159.991 | 0.0416 | 3.26542 | 0.00042
STÅLBJELKE | 330.002 | 4.14481 | 0.1154 | 0.000528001 | DSB-18079(?) | SB-7497(?) | 0.1154 | 4.14481 | 160 | 0.0528 | 4.14482 | 0.00053
STÅLBJELKE | 260.001 | 3.26559 | 0.0915997 | 0.000415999 | DSB-18078(?) | SB-7497(?) | 0.0916 | 3.26559 | 160 | 0.0416 | 3.26561 | 0.00042

# IfcBeam: PL10*180, STÅLBJELKE
In: D
Description: PL10*180; Material: STEEL/S355
AVINOR - 08_Status: S4; 07_Fase: F90; 04_Kontrakt: 72717; 02_Prosjekt: T20100; 05_ID-nummer: +TS=221.014; 03_Ansvar: 72101; 06_Omrade: TS; 01_Lufthavnkode: ENGM
Tekla Quantity - AREA_GROSS: 0.1176 m2; AREA_NET: 0.1176 m2; Length: 299.985 mm; WEIGTH_GROSS: 4.23879 kg; WEIGTH_NET: 4.23879 kg; Width: 10 mm; Heigth: 180 mm; VOLUME_GROSS: 0.00053 m3; VOLUME_NET: 0.00053 m3
Tekla Common - Grade: S355; Bottom elevation: +206.920; Name: STÅLBJELKE; Assembly mark: SB-7501(?); Part mark: DSB-17760(?); Profile: PL10*180; Class: 330; Top elevation: +207.100
ePset_Simplebim - Assembly Level: Leaf
Pset_BeamCommon - LoadBearing: no; Reference: DSB-17760(?)
ePset_SimplebimBasicQuantities - Area, sides, net (Simplebim): 0.1176 m2; Volume, net (Simplebim): 0.00054 m3; Weight, as steel (Simplebim): 4.239 kg; Height (Simplebim): 10 mm; Width (Simplebim): 180 mm; Length (Simplebim): 300 mm
ePset_LocationTool - Splitting: ORIGINAL

# IfcBeam: PL10*200 (13)
In: D
Description: PL10*200; Material: STEEL/S355
AVINOR - 08_Status: S4; 07_Fase: F90; 04_Kontrakt: 72717; 02_Prosjekt: T20100; 05_ID-nummer: +TS=221.014; 03_Ansvar: 72101; 06_Omrade: TS; 01_Lufthavnkode: ENGM
Tekla Common - Grade: S355; Name: STÅLBJELKE; Profile: PL10*200; Class: 330
Tekla Quantity - Width: 10 mm; Heigth: 200 mm
Pset_BeamCommon - LoadBearing: no
ePset_Simplebim - Assembly Level: Leaf
ePset_LocationTool - Splitting: ORIGINAL
Name | Volume, net (Simplebim) (m3) | Length (Simplebim) (mm) | Width (Simplebim) (mm) | Weight, as steel (Simplebim) (kg) = WEIGTH_NET (kg) | Height (Simplebim) (mm) | Area, sides, net (Simplebim) (m2) | Top elevation | Part mark = Reference | Assembly mark | Bottom elevation | Length (mm) | AREA_GROSS (m2) | AREA_NET (m2) | WEIGTH_GROSS (kg) | VOLUME_NET (m3) = VOLUME_GROSS (m3)
STÅLBJELKE | 0.000645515 | 313.486 | 51.1735 | 5.06729 | 200 | 0.13974 | +207.115 | DSB-18050(?) | SB-10854(?) | +206.915 | 323.363 | 0.13974 | 0.13974 | 5.07679 | 0.00065
STÅLBJELKE | 0.000419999 | 210.433 | 200.454 | 3.29699 | 10 | 0.0921998 | +206.833 | DSB-18080(?) | SB-7501(?) | +206.823 | 210.433 | 0.04209 | 0.0922 | 3.3038 | 0.00042
STÅLBJELKE | 0.000419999 | 210.433 | 200.454 | 3.29699 | 10 | 0.0921998 | +206.833 | DSB-18080(?) | SB-7498(?) | +206.823 | 210.433 | 0.04209 | 0.0922 | 3.3038 | 0.00042
3 x STÅLBJELKE | 0.000419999 | 210.433 | 200.454 | 3.29699 | 10 | 0.0921998 | +206.833 | DSB-18081(?) | SB-7500(?) | +206.823 | 210.433 | 0.04209 | 0.0922 | 3.3038 | 0.00042
2 x STÅLBJELKE | 0.000419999 | 210.433 | 200.454 | 3.29699 | 10 | 0.0921998 | +206.833 | DSB-18081(?) | SB-7499(?) | +206.823 | 210.433 | 0.04209 | 0.0922 | 3.3038 | 0.00042
STÅLBJELKE | 0.000419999 | 210.433 | 200.454 | 3.29699 | 10 | 0.0921998 | +206.833 | DSB-18080(?) | SB-7499(?) | +206.823 | 210.433 | 0.04209 | 0.0922 | 3.3038 | 0.00042
STÅLBJELKE | 0.000419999 | 210.433 | 200.454 | 3.29699 | 10 | 0.0921998 | +206.833 | DSB-18081(?) | SB-7497(?) | +206.823 | 210.433 | 0.04209 | 0.0922 | 3.3038 | 0.00042
STÅLBJELKE | 0.000419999 | 210.433 | 200.454 | 3.29699 | 10 | 0.0921998 | +206.833 | DSB-18081(?) | SB-7498(?) | +206.823 | 210.433 | 0.04209 | 0.0922 | 3.3038 | 0.00042
STÅLBJELKE | 0.000420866 | 210.866 | 200.455 | 3.30379 | 10 | 0.0923818 | +206.833 | DSB-18080(?) | SB-7498(?) | +206.823 | 210.867 | 0.04217 | 0.09238 | 3.3106 | 0.00042
STÅLBJELKE | 0.000419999 | 210.433 | 200.454 | 3.29699 | 10 | 0.0921998 | +206.833 | DSB-18081(?) | SB-7501(?) | +206.823 | 210.433 | 0.04209 | 0.0922 | 3.3038 | 0.00042

# IfcBeam: PL10*70 (15)
In: D
Description: PL10*70; Material: STEEL/S355
AVINOR - 08_Status: S4; 07_Fase: F90; 04_Kontrakt: 72274; 05_ID-nummer: +TS=223.001; 02_Prosjekt: T20100; 03_Ansvar: 72101; 06_Omrade: TS; 01_Lufthavnkode: ENGM
ePset_LocationTool - Splitting: ORIGINAL
Tekla Quantity - Width: 10 mm; Heigth: 70 mm
ePset_Simplebim - Assembly Level: Leaf
Pset_BeamCommon - LoadBearing: no
Tekla Common - Grade: S355; Name: STÅLBJELKE; Profile: PL10*70; Class: 330
Name | Height (Simplebim) (mm) | Area, sides, net (Simplebim) (m2) | Volume, net (Simplebim) (m3) | Weight, as steel (Simplebim) (kg) | Width (Simplebim) (mm) | Length (Simplebim) (mm) | AREA_NET (m2) = AREA_GROSS (m2) | VOLUME_GROSS (m3) = VOLUME_NET (m3) | Length (mm) | WEIGTH_NET (kg) = WEIGTH_GROSS (kg) | Reference = Part mark | Top elevation | Bottom elevation | Assembly mark
4 x STÅLBJELKE | 140 | 0.0238 | 0.0000979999 | 0.769299 | 10 | 70 | 0.0238 | 0.0001 | 140 | 0.7693 | DSB-8954(?) | +207.155 | +207.015 | SB-4367(?)
2 x STÅLBJELKE | 10 | 0.0381999 | 0.000161 | 1.26385 | 70 | 229.999 | 0.0382 | 0.00016 | 229.999 | 1.26385 | DSB-8957(?) | +207.015 | +207.005 | SB-4367(?)
6 x STÅLBJELKE | 140 | 0.0238 | 0.0000979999 | 0.769299 | 10 | 70 | 0.0238 | 0.0001 | 140 | 0.7693 | DSB-9647(?) | +207.175 | +207.035 | SB-4841(?)
3 x STÅLBJELKE | 10 | 0.0381999 | 0.000161 | 1.26385 | 70 | 229.999 | 0.0382 | 0.00016 | 229.999 | 1.26385 | DSB-8957(?) | +207.035 | +207.025 | SB-4841(?)

# IfcBeam: PL10*96, STÅLBJELKE
In: D
Description: PL10*96; Material: STEEL/S355
AVINOR - 08_Status: S4; 07_Fase: F90; 04_Kontrakt: 72717; 02_Prosjekt: T20100; 05_ID-nummer: +TS=221.014; 03_Ansvar: 72101; 06_Omrade: TS; 01_Lufthavnkode: ENGM
Tekla Quantity - WEIGTH_GROSS: 0.7536 kg; WEIGTH_NET: 0.7536 kg; AREA_NET: 0.02312 m2; VOLUME_GROSS: 0.0001 m3; VOLUME_NET: 0.0001 m3; AREA_GROSS: 0.0096 m2; Width: 10 mm; Heigth: 96 mm; Length: 100 mm
ePset_Simplebim - Assembly Level: Leaf
Tekla Common - Grade: S355; Bottom elevation: +206.833; Name: STÅLBJELKE; Profile: PL10*96; Assembly mark: SB-7501(?); Top elevation: +206.929; Class: 330; Part mark: DSB-17759(?)
ePset_SimplebimBasicQuantities - Area, sides, net (Simplebim): 0.02312 m2; Weight, as steel (Simplebim): 0.7536 kg; Width (Simplebim): 10 mm; Length (Simplebim): 100 mm; Volume, net (Simplebim): 0.000096 m3; Height (Simplebim): 96 mm
Pset_BeamCommon - LoadBearing: no; Reference: DSB-17759(?)
ePset_LocationTool - Splitting: ORIGINAL

# IfcBeam: PL100*14 (5)
In: D
Description: PL100*14; Material: STEEL/S355
Pset_BeamCommon - Reference: DSB-23437(?); LoadBearing: no
AVINOR - 08_Status: S4; 07_Fase: F90; 02_Prosjekt: T20100; 05_ID-nummer: +TS=223.013; 04_Kontrakt: 72233; 03_Ansvar: 72101; 06_Omrade: TS; 01_Lufthavnkode: ENGM
Tekla Common - Grade: S355; Assembly mark: SB-13991(?); Name: STÅLBJELKE; Profile: PL100*14; Part mark: DSB-23437(?); Bottom elevation: +203.385; Class: 330; Top elevation: +203.399
Tekla Quantity - VOLUME_GROSS: 0.0001 m3; VOLUME_NET: 0.0001 m3; AREA_GROSS: 0.00224 m2; AREA_NET: 0.0357 m2; WEIGTH_GROSS: 1.7584 kg; WEIGTH_NET: 0.8792 kg; Heigth: 14 mm; Width: 100 mm; Length: 160 mm
ePset_SimplebimBasicQuantities - Area, sides, net (Simplebim): 0.0357011 m2; Weight, as steel (Simplebim): 0.8792 kg; Height (Simplebim): 14 mm; Width (Simplebim): 100 mm; Length (Simplebim): 160 mm; Volume, net (Simplebim): 0.000112 m3
ePset_Simplebim - Assembly Level: Leaf
ePset_LocationTool - Splitting: ORIGINAL

# IfcBeam: PL106.25*10 (8)
In: D
Description: PL106.25*10; Material: STEEL/S355
Tekla Common - Grade: S355; Bottom elevation: +203.167; Name: STÅLBJELKE; Top elevation: +203.373; Assembly mark: SB-9965(?); Profile: PL106.25*10; Class: 330; Part mark: DSB-17559(?)
AVINOR - 08_Status: S4; 07_Fase: F90; 02_Prosjekt: T20100; 05_ID-nummer: +TS=223.013; 04_Kontrakt: 72233; 03_Ansvar: 72101; 06_Omrade: TS; 01_Lufthavnkode: ENGM
ePset_Simplebim - Assembly Level: Leaf
Tekla Quantity - AREA_GROSS: 0.05002 m2; AREA_NET: 0.05002 m2; VOLUME_NET: 0.00022 m3; VOLUME_GROSS: 0.00022 m3; WEIGTH_NET: 1.71817 kg; WEIGTH_GROSS: 1.71817 kg; Width: 10 mm; Heigth: 106.25 mm; Length: 206 mm
ePset_SimplebimBasicQuantities - Area, sides, net (Simplebim): 0.05002 m2; Weight, as steel (Simplebim): 1.71817 kg; Volume, net (Simplebim): 0.000218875 m3; Width (Simplebim): 10 mm; Length (Simplebim): 106.25 mm; Height (Simplebim): 206 mm
Pset_BeamCommon - LoadBearing: no; Reference: DSB-17559(?)
ePset_LocationTool - Splitting: ORIGINAL

# IfcBeam: PL130*10, STÅLBJELKE
In: D
Description: PL130*10; Material: STEEL/S355
AVINOR - 08_Status: S4; 07_Fase: F90; 02_Prosjekt: T1; 04_Kontrakt: FDV; 03_Ansvar: FDV; 06_Omrade: TS; 01_Lufthavnkode: ENGM
Tekla Common - Grade: S355; Bottom elevation: +206.790; Top elevation: +206.920; Name: STÅLBJELKE; Assembly mark: SB-6279(?); Part mark: DSB-11240(?); Profile: PL130*10; Class: 330
ePset_Simplebim - Assembly Level: Leaf
Pset_BeamCommon - LoadBearing: no; Reference: DSB-11240(?)
Tekla Quantity - VOLUME_NET: 0.00029 m3; VOLUME_GROSS: 0.00029 m3; WEIGTH_NET: 2.2451 kg; WEIGTH_GROSS: 2.2451 kg; Width: 10 mm; Length: 220 mm; Heigth: 130 mm; AREA_NET: 0.0642 m2; AREA_GROSS: 0.0642 m2
ePset_SimplebimBasicQuantities - Volume, net (Simplebim): 0.000286 m3; Weight, as steel (Simplebim): 2.2451 kg; Width (Simplebim): 10 mm; Length (Simplebim): 220 mm; Height (Simplebim): 130 mm; Area, sides, net (Simplebim): 0.0642 m2
ePset_LocationTool - Splitting: ORIGINAL

# IfcBeam: PL130*15 (2)
In: D
Description: PL130*15; Material: STEEL/S355
AVINOR - 08_Status: S4; 07_Fase: F90; 02_Prosjekt: T20100; 05_ID-nummer: +TS=223.013; 04_Kontrakt: 72233; 03_Ansvar: 72101; 06_Omrade: TS; 01_Lufthavnkode: ENGM
Pset_BeamCommon - LoadBearing: no; Reference: DSSP-6810(?)
Tekla Quantity - WEIGTH_NET: 4.59225 kg; WEIGTH_GROSS: 4.59225 kg; AREA_GROSS: 0.0909 m2; AREA_NET: 0.0909 m2; Width: 15 mm; Heigth: 130 mm; Length: 300 mm; VOLUME_GROSS: 0.00059 m3; VOLUME_NET: 0.00059 m3
ePset_Simplebim - Assembly Level: Leaf
Tekla Common - Assembly mark: SSP-170(?); Grade: S355; Class: 380; Profile: PL130*15; Bottom elevation: +203.930; Part mark: DSSP-6810(?); Top elevation: +203.945; Name: STÅLSPESIAL
ePset_LocationTool - Splitting: ORIGINAL
ePset_SimplebimBasicQuantities - Weight, as steel (Simplebim): 4.59225 kg; Volume, net (Simplebim): 0.000585 m3; Area, sides, net (Simplebim): 0.0909 m2; Height (Simplebim): 15 mm; Width (Simplebim): 130 mm; Length (Simplebim): 300 mm

# IfcBeam: PL200*10, STÅLBJELKE
In: D
Description: PL200*10; Material: STEEL/S355
Tekla Common - Grade: S355; Bottom elevation: +206.790; Name: STÅLBJELKE; Assembly mark: SB-3257(?); Top elevation: +206.800; Profile: PL200*10; Class: 330; Part mark: DSB-7460(?)
Pset_BeamCommon - LoadBearing: no; Reference: DSB-7460(?)
ePset_SimplebimBasicQuantities - Volume, net (Simplebim): 0.03618 m3; Area, sides, net (Simplebim): 7.6018 m2; Weight, as steel (Simplebim): 284.013 kg; Height (Simplebim): 10 mm; Width (Simplebim): 200 mm; Length (Simplebim): 18090 mm
ePset_Simplebim - Assembly Level: Leaf
AVINOR - 07_Fase: F90; 02_Prosjekt: T1; 04_Kontrakt: FDV; 03_Ansvar: FDV; 08_Status: S2; 06_Omrade: TS; 01_Lufthavnkode: ENGM
ePset_LocationTool - Splitting: ORIGINAL
Tekla Quantity - VOLUME_GROSS: 0.03619 m3; AREA_GROSS: 7.6018 m2; AREA_NET: 7.6018 m2; WEIGTH_GROSS: 284.013 kg; WEIGTH_NET: 284.013 kg; Width: 10 mm; Heigth: 200 mm; VOLUME_NET: 0.03618 m3; Length: 18090 mm

# IfcBeam: PL200*15, STÅLBJELKE
In: D
Description: PL200*15; Material: STEEL/S355
Tekla Common - Grade: S355; Part mark: DSB-16889(?); Name: STÅLBJELKE; Assembly mark: SB-9965(?); Bottom elevation: +203.385; Top elevation: +203.400; Class: 330; Profile: PL200*15
AVINOR - 08_Status: S4; 07_Fase: F90; 02_Prosjekt: T20100; 05_ID-nummer: +TS=223.013; 04_Kontrakt: 72233; 03_Ansvar: 72101; 06_Omrade: TS; 01_Lufthavnkode: ENGM
ePset_LocationTool - Splitting: ORIGINAL
ePset_SimplebimBasicQuantities - Area, sides, net (Simplebim): 0.0748 m2; Height (Simplebim): 15 mm; Length (Simplebim): 200 mm; Width (Simplebim): 160 mm; Weight, as steel (Simplebim): 3.768 kg; Volume, net (Simplebim): 0.00048 m3
ePset_Simplebim - Assembly Level: Leaf
Pset_BeamCommon - Reference: DSB-16889(?); LoadBearing: no
Tekla Quantity - AREA_GROSS: 0.0748 m2; AREA_NET: 0.0748 m2; Width: 15 mm; Heigth: 200 mm; Length: 160 mm; WEIGTH_GROSS: 3.768 kg; WEIGTH_NET: 3.768 kg; VOLUME_GROSS: 0.00048 m3; VOLUME_NET: 0.00048 m3

# IfcBeam: PL30*5 (22)
In: D
Description: PL30*5; Material: STEEL/S355
Pset_BeamCommon - Reference: DSB-21167(?); LoadBearing: no
AVINOR - 08_Status: S4; 07_Fase: F90; 02_Prosjekt: T20100; 05_ID-nummer: +TS=222.012; 04_Kontrakt: 72233; 03_Ansvar: 72101; 06_Omrade: TS; 01_Lufthavnkode: ENGM
ePset_LocationTool - Splitting: ORIGINAL
Tekla Quantity - VOLUME_NET: 0.00001 m3; VOLUME_GROSS: 0.00001 m3; AREA_NET: 0.0031 m2; AREA_GROSS: 0.0031 m2; Width: 5 mm; Heigth: 30 mm
ePset_Simplebim - Assembly Level: Leaf
ePset_SimplebimBasicQuantities - Width (Simplebim): 5 mm; Height (Simplebim): 30 mm
Tekla Common - Grade: S355; Profile: PL30*5; Name: STÅLBJELKE; Assembly mark: SB-12652(?); Top elevation: +207.275; Bottom elevation: +207.245; Part mark: DSB-21167(?); Class: 330
Name | WEIGTH_GROSS (kg) = WEIGTH_NET (kg) | Length (mm) = Length (Simplebim) (mm) | Weight, as steel (Simplebim) (kg) | Area, sides, net (Simplebim) (m2) | Volume, net (Simplebim) (m3)
15 x STÅLBJELKE | 0.0471 | 40 | 0.0471 | 0.0031 | 0.000006
7 x STÅLBJELKE | 0.04711 | 40.0092 | 0.0471108 | 0.00310064 | 0.00000600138

# IfcBeam: PL305*1 (3)
In: D
Description: PL305*1
AVINOR - 08_Status: S4; 07_Fase: F90; 02_Prosjekt: T20100; 05_ID-nummer: +TS=223.013; 04_Kontrakt: 72233; 03_Ansvar: 72101; 06_Omrade: TS; 01_Lufthavnkode: ENGM
ePset_Simplebim - Assembly Level: Leaf
Pset_BeamCommon - LoadBearing: no
Tekla Common - Grade: S355; Profile: PL305*1; Name: STÅLBJELKE; Top elevation: +203.400; Bottom elevation: +203.095; Class: 330
Name | Length (Simplebim) (mm) | Area, sides, net (Simplebim) (m2) | Width (Simplebim) (mm) | Height (Simplebim) (mm) | Weight, as steel (Simplebim) (kg) | Volume, net (Simplebim) (m3) | Reference = Part mark | Splitting | Assembly mark
STÅLBJELKE | 362 | 0.222154 | 1 | 305 | 0.866718 | 0.00011041 | DSB-24734(?) | ORIGINAL | SB-14697(?) | Material: STEEL/S355; Tekla Quantity - WEIGTH_NET: 0.86672 kg; WEIGTH_GROSS: 0.86672 kg; VOLUME_GROSS: 0.0001 m3; VOLUME_NET: 0.0001 m3; Width: 1 mm; Heigth: 305 mm; Length: 362 mm; AREA_NET: 0.22215 m2; AREA_GROSS: 0.22215 m2
STÅLBJELKE | 3747 | 2.29408 | 2 | 305 | 8.97245 | 0.00114299 | DSB-24733(?) | RESULT | SB-14696(?)
STÅLBJELKE | 3747 | 2.29408 | 0 | 304 | 8.97245 | 0.00114299 | DSB-24733(?) | RESULT | SB-14696(?)

# IfcBeam: PL35*80 (5)
In: D
Description: PL35*80; Material: STEEL/S355
Pset_BeamCommon - LoadBearing: no
ePset_SimplebimBasicQuantities - Height (Simplebim): 35 mm; Width (Simplebim): 80 mm
Tekla Common - Grade: S355; Name: STÅLBJELKE; Profile: PL35*80; Bottom elevation: +206.880; Class: 330; Top elevation: +206.915
ePset_Simplebim - Assembly Level: Leaf
AVINOR - 07_Fase: F90; 06_Omrade: TS; 01_Lufthavnkode: ENGM
ePset_LocationTool - Splitting: ORIGINAL
Tekla Quantity - Width: 35 mm; Heigth: 80 mm
Name | Reference = Part mark | Area, sides, net (Simplebim) (m2) = AREA_NET (m2) | Length (Simplebim) (mm) = Length (mm) | Weight, as steel (Simplebim) (kg) = WEIGTH_NET (kg) = WEIGTH_GROSS (kg) | Volume, net (Simplebim) (m3) | Assembly mark | 02_Prosjekt | 04_Kontrakt | 03_Ansvar | 08_Status | AREA_GROSS (m2) | VOLUME_GROSS (m3) | VOLUME_NET (m3) | 05_ID-nummer
STÅLBJELKE | DSB-8876(?) | 0.0424 | 160 | 3.5168 | 0.000448 | SB-4274(?) | T1 | FDV | FDV | S2 | 0.0128 | 0.00045 | 0.00045
STÅLBJELKE | DSB-7467(?) | 0.0378 | 140 | 3.0772 | 0.000392 | SB-3506(?) | T20100 | 72274 | 72101 | S4 | 0.0112 | 0.00039 | 0.00039 | +TS=223.001
2 x STÅLBJELKE | DSB-8574(?) | 0.0516 | 200 | 4.396 | 0.00056 | SB-4063(?) | T20100 | 72274 | 72101 | S4 | 0.016 | 0.00056 | 0.00056 | +TS=223.001
STÅLBJELKE | DSB-9670(?) | 0.0355 | 130 | 2.8574 | 0.000364 | SB-4934(?) | T20100 | 72274 | 72101 | S4 | 0.0104 | 0.00036 | 0.00035 | +TS=223.001

# IfcBeam: PL362*1, STÅLBJELKE
In: D
Description: PL362*1
AVINOR - 08_Status: S4; 07_Fase: F90; 02_Prosjekt: T20100; 05_ID-nummer: +TS=223.013; 04_Kontrakt: 72233; 03_Ansvar: 72101; 06_Omrade: TS; 01_Lufthavnkode: ENGM
ePset_LocationTool - Splitting: RESULT
Pset_BeamCommon - Reference: DSB-24735(?); LoadBearing: no
ePset_Simplebim - Assembly Level: Leaf
ePset_SimplebimBasicQuantities - Weight, as steel (Simplebim): 10.6521 kg; Area, sides, net (Simplebim): 2.72213 m2; Height (Simplebim): 0 mm; Width (Simplebim): 362 mm; Length (Simplebim): 3748 mm; Volume, net (Simplebim): 0.00135696 m3
Tekla Common - Grade: S355; Name: STÅLBJELKE; Assembly mark: SB-14698(?); Part mark: DSB-24735(?); Bottom elevation: +203.094; Top elevation: +203.095; Class: 330; Profile: PL362*1

# IfcBeam: PL5*75 (2)
In: D
Description: PL5*75; Material: STEEL/S355
ePset_LocationTool - Splitting: ORIGINAL
Pset_BeamCommon - Reference: DSB-21121(?); LoadBearing: no
ePset_Simplebim - Assembly Level: Leaf
Tekla Common - Assembly mark: SB-12634(?); Grade: S355; Part mark: DSB-21121(?); Profile: PL5*75; Name: STÅLBJELKE; Bottom elevation: +206.802; Top elevation: +206.877; Class: 330
ePset_SimplebimBasicQuantities - Length (Simplebim): 75 mm; Area, sides, net (Simplebim): 0.01275 m2; Width (Simplebim): 5 mm; Height (Simplebim): 75 mm; Weight, as steel (Simplebim): 0.220781 kg; Volume, net (Simplebim): 0.000028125 m3
AVINOR - 08_Status: S4; 07_Fase: F90; 05_ID-nummer: +TS=223.008; 02_Prosjekt: T20100; 04_Kontrakt: 72233; 03_Ansvar: 72101; 06_Omrade: TS; 01_Lufthavnkode: ENGM
Tekla Quantity - VOLUME_NET: 0.00004 m3; WEIGTH_GROSS: 0.22078 kg; WEIGTH_NET: 0.22078 kg; AREA_NET: 0.01274 m2; AREA_GROSS: 0.01274 m2; Width: 5 mm; Heigth: 75 mm; Length: 75 mm; VOLUME_GROSS: 0.00003 m3

# IfcBeam: PL73*198 (12)
In: D
Description: PL73*198; Material: TIMBER/GL36c
ePset_SimplebimBasicQuantities - Width (Simplebim): 198 mm; Height (Simplebim): 73 mm
Tekla Common - Bottom elevation: +206.750; Top elevation: +206.823; Grade: GL36c; Name: TREBJELKE; Class: 430; Profile: PL73*198
AVINOR - 08_Status: S4; 07_Fase: F90; 04_Kontrakt: 72717; 02_Prosjekt: T20100; 05_ID-nummer: +TS=221.014; 03_Ansvar: 72101; 06_Omrade: TS; 01_Lufthavnkode: ENGM
Pset_BeamCommon - LoadBearing: no
ePset_Simplebim - Assembly Level: Leaf
Tekla Quantity - Width: 73 mm; Heigth: 198 mm
ePset_LocationTool - Splitting: ORIGINAL
Name | Weight, as steel (Simplebim) (kg) | Length (Simplebim) (mm) = Length (mm) | Volume, net (Simplebim) (m3) | Area, sides, net (Simplebim) (m2) | Part mark = Reference | Assembly mark | WEIGTH_GROSS (kg) | WEIGTH_NET (kg) | AREA_NET (m2) = AREA_GROSS (m2) | VOLUME_GROSS (m3) = VOLUME_NET (m3)
TREBJELKE | 144.35 | 1272.21 | 0.0183885 | 0.718446 | DTB-446 | TB-371 | 7.90707 | 7.90707 | 0.71845 | 0.01839
TREBJELKE | 237.152 | 2090.11 | 0.0302105 | 1.16175 | DTB-445 | TB-370 | 12.9905 | 12.9905 | 1.16175 | 0.03021
TREBJELKE | 219.614 | 1935.54 | 0.0279762 | 1.07797 | DTB-444 | TB-369 | 12.0298 | 12.0298 | 1.07797 | 0.02798
TREBJELKE | 202.963 | 1788.79 | 0.0258552 | 0.998434 | DTB-443 | TB-368 | 11.1177 | 11.1177 | 0.99843 | 0.02586
TREBJELKE | 203.051 | 1789.56 | 0.0258663 | 0.998851 | DTB-443 | TB-368 | 11.1225 | 11.1225 | 0.99885 | 0.02586
TREBJELKE | 210.349 | 1853.88 | 0.026796 | 1.03371 | DTB-442 | TB-367 | 11.5223 | 11.5223 | 1.03371 | 0.0268
TREBJELKE | 91.1824 | 883.826 | 0.0116156 | 0.46862 | DTB-441 | TB-366 | 5.49317 | 4.9947 | 0.46862 | 0.01162
TREBJELKE | 334.719 | 2950 | 0.0426393 | 1.62781 | DTB-447 | TB-372 | 18.3349 | 18.3349 | 1.62781 | 0.04264
TREBJELKE | 253.03 | 2230.05 | 0.0322331 | 1.2376 | DTB-448 | TB-373 | 13.8603 | 13.8603 | 1.2376 | 0.03223
TREBJELKE | 308.235 | 2716.59 | 0.0392656 | 1.5013 | DTB-449 | TB-374 | 16.8842 | 16.8842 | 1.5013 | 0.03927
TREBJELKE | 216.106 | 1904.62 | 0.0275294 | 1.06121 | DTB-440(?) | TB-365(?) | 11.8376 | 11.8376 | 1.06121 | 0.02753
TREBJELKE | 219.796 | 1937.15 | 0.0279995 | 1.07884 | DTB-450 | TB-375 | 12.0398 | 12.0398 | 1.07884 | 0.028

# IfcBeam: PL80*10 (4)
In: D
Description: PL80*10; Material: STEEL/S355
Tekla Quantity - Length: 280 mm; VOLUME_NET: 0.00022 m3; VOLUME_GROSS: 0.00022 m3; WEIGTH_NET: 1.7584 kg; WEIGTH_GROSS: 1.7584 kg; Width: 10 mm; Heigth: 80 mm; AREA_GROSS: 0.052 m2; AREA_NET: 0.052 m2
ePset_LocationTool - Splitting: ORIGINAL
Pset_BeamCommon - LoadBearing: no; Reference: DSB-8042(?)
ePset_Simplebim - Assembly Level: Leaf
AVINOR - 07_Fase: F90; 06_Omrade: TS; 01_Lufthavnkode: ENGM
ePset_SimplebimBasicQuantities - Length (Simplebim): 280 mm; Weight, as steel (Simplebim): 1.7584 kg; Volume, net (Simplebim): 0.000224 m3; Width (Simplebim): 10 mm; Height (Simplebim): 80 mm; Area, sides, net (Simplebim): 0.052 m2
Tekla Common - Grade: S355; Profile: PL80*10; Name: STÅLBJELKE; Part mark: DSB-8042(?); Class: 330
Name | 02_Prosjekt | 04_Kontrakt | 03_Ansvar | 08_Status | Bottom elevation | Top elevation | Assembly mark | 05_ID-nummer
STÅLBJELKE | T1 | FDV | FDV | S2 | +206.920 | +207.000 | SB-3691(?)
2 x STÅLBJELKE | T20100 | 72274 | 72101 | S4 | +206.930 | +207.010 | SB-3690(?) | +TS=223.001
STÅLBJELKE | T20100 | 72274 | 72101 | S4 | +206.920 | +207.000 | SB-3694(?) | +TS=223.001

# IfcBeam: PL80*14 (5)
In: D
Description: PL80*14; Material: STEEL/S355
ePset_LocationTool - Splitting: ORIGINAL
AVINOR - 08_Status: S4; 07_Fase: F90; 02_Prosjekt: T20100; 05_ID-nummer: +TS=223.013; 04_Kontrakt: 72233; 03_Ansvar: 72101; 06_Omrade: TS; 01_Lufthavnkode: ENGM
Tekla Quantity - VOLUME_NET: 0.00008 m3; VOLUME_GROSS: 0.00008 m3; AREA_GROSS: 0.00224 m2; WEIGTH_NET: 0.70336 kg; WEIGTH_GROSS: 1.40672 kg; AREA_NET: 0.02901 m2; Heigth: 14 mm; Width: 80 mm; Length: 160 mm
ePset_SimplebimBasicQuantities - Weight, as steel (Simplebim): 0.70336 kg; Area, sides, net (Simplebim): 0.0290089 m2; Length (Simplebim): 160.611 mm; Volume, net (Simplebim): 0.0000896 m3; Height (Simplebim): 13.9467 mm; Width (Simplebim): 80 mm
ePset_Simplebim - Assembly Level: Leaf
Pset_BeamCommon - Reference: DSB-20191(?); LoadBearing: no
Tekla Common - Grade: S355; Bottom elevation: +203.386; Profile: PL80*14; Name: STÅLBJELKE; Part mark: DSB-20191(?); Top elevation: +203.400; Class: 330; Assembly mark: SB-12155(?)

# IfcBeam: PL80*15 (2)
In: D
Description: PL80*15; Material: STEEL/S355
Tekla Quantity - VOLUME_NET: 0.00008 m3; VOLUME_GROSS: 0.00008 m3; AREA_GROSS: 0.0157 m2; AREA_NET: 0.0157 m2; WEIGTH_NET: 0.6594 kg; WEIGTH_GROSS: 0.6594 kg; Width: 15 mm; Length: 70 mm; Heigth: 80 mm
AVINOR - 08_Status: S4; 07_Fase: F90; 02_Prosjekt: T20100; 05_ID-nummer: +TS=223.013; 04_Kontrakt: 72233; 03_Ansvar: 72101; 06_Omrade: TS; 01_Lufthavnkode: ENGM
ePset_SimplebimBasicQuantities - Area, sides, net (Simplebim): 0.0157 m2; Weight, as steel (Simplebim): 0.6594 kg; Volume, net (Simplebim): 0.000084 m3; Height (Simplebim): 15 mm; Length (Simplebim): 80 mm; Width (Simplebim): 70 mm
Tekla Common - Grade: S355; Profile: PL80*15; Name: STÅLBJELKE; Top elevation: +203.373; Bottom elevation: +203.358; Assembly mark: SB-9965(?); Part mark: DSB-17060(?); Class: 330
ePset_Simplebim - Assembly Level: Leaf
Pset_BeamCommon - LoadBearing: no; Reference: DSB-17060(?)
ePset_LocationTool - Splitting: ORIGINAL

# IfcBeam: RHS100*100*8 (2)
In: D
Description: RHS100*100*8
ePset_SimplebimBasicQuantities - Area, sides, net (Simplebim): 4.71717 m2; Volume, net (Simplebim): 0.0188451 m3; Weight, as steel (Simplebim): 147.934 kg; Width (Simplebim): 100 mm; Height (Simplebim): 100 mm; Length (Simplebim): 6401 mm
AVINOR - 08_Status: S4; 07_Fase: F90; 04_Kontrakt: 72274; 05_ID-nummer: +TS=223.001; 02_Prosjekt: T20100; 03_Ansvar: 72101; 06_Omrade: TS; 01_Lufthavnkode: ENGM
Pset_BeamCommon - LoadBearing: no; Reference: DSB-9667(?)
ePset_Simplebim - Assembly Level: Leaf
Tekla Common - Grade: S355; Name: STÅLBJELKE; Top elevation: +207.025; Profile: RHS100*100*8; Part mark: DSB-9667(?); Assembly mark: SB-3690(?); Class: 330; Bottom elevation: +206.925
ePset_LocationTool - Splitting: RESULT

# IfcBeam: RHS100*6.3 (24)
In: D
Description: RHS100*6.3
AVINOR - 08_Status: S4; 07_Fase: F90; 04_Kontrakt: 72717; 02_Prosjekt: T20100; 05_ID-nummer: +TS=221.014; 03_Ansvar: 72101; 06_Omrade: TS; 01_Lufthavnkode: ENGM
Pset_BeamCommon - LoadBearing: no
ePset_Simplebim - Assembly Level: Leaf
Tekla Common - Grade: S355; Name: STÅLBJELKE; Profile: RHS100*6.3; Class: 330
Name | Material | Reference = Part mark | Weight, as steel (Simplebim) (kg) | Length (Simplebim) (mm) | Width (Simplebim) (mm) | Height (Simplebim) (mm) | Volume, net (Simplebim) (m3) | Area, sides, net (Simplebim) (m2) | WEIGTH_NET (kg) | WEIGTH_GROSS (kg) | VOLUME_GROSS (m3) | VOLUME_NET (m3) | AREA_GROSS (m2) | Heigth (mm) | Width (mm) | Length (mm) | AREA_NET (m2) | Splitting | Assembly mark | Top elevation | Bottom elevation
3 x STÅLBJELKE | STEEL/S355 | DSB-19495(?) | 5.89142 | 100 | 100 | 395 | 0.0007505 | 0.304 | 7.32162 | 7.25576 | 0.00092 | 0.00093 | 0.15247 | 100 | 100 | 395 | 0.16052 | ORIGINAL | SB-7501(?) | +207.000 | +206.605
3 x STÅLBJELKE | STEEL/S355 | DSB-19495(?) | 5.89142 | 100 | 100 | 395 | 0.0007505 | 0.304 | 7.32162 | 7.25576 | 0.00092 | 0.00093 | 0.15247 | 100 | 100 | 395 | 0.16052 | ORIGINAL | SB-7500(?) | +207.000 | +206.605
3 x STÅLBJELKE | STEEL/S355 | DSB-19495(?) | 5.89142 | 100 | 100 | 395 | 0.0007505 | 0.304 | 7.32162 | 7.25576 | 0.00092 | 0.00093 | 0.15247 | 100 | 100 | 395 | 0.16052 | ORIGINAL | SB-7498(?) | +207.000 | +206.605
3 x STÅLBJELKE | STEEL/S355 | DSB-19495(?) | 5.89142 | 100 | 100 | 395 | 0.0007505 | 0.304 | 7.32162 | 7.25576 | 0.00092 | 0.00093 | 0.15247 | 100 | 100 | 395 | 0.16052 | ORIGINAL | SB-7499(?) | +207.000 | +206.605
2 x STÅLBJELKE | STEEL/S355 | DSB-19495(?) | 5.89142 | 100 | 100 | 395 | 0.0007505 | 0.304 | 7.32162 | 7.25576 | 0.00092 | 0.00093 | 0.15247 | 100 | 100 | 395 | 0.16052 | ORIGINAL | SB-7497(?) | +207.000 | +206.605
STÅLBJELKE | STEEL/S355 | DSB-19501(?) | 80.2415 | 4332.26 | 173.114 | 100 | 0.0102218 | 3.24976 | 80.2415 | 79.523 | 0.01012 | 0.01022 | 1.67107 | 100 | 6.3 | 4329.2 | 1.73413 | ORIGINAL | SB-7501(?) | +207.100 | +207.000
STÅLBJELKE | STEEL/S355 | DSB-19502(?) | 78.3873 | 4232.42 | 169.936 | 100 | 0.00998564 | 3.17477 | 78.3873 | 77.6857 | 0.0099 | 0.00999 | 1.63246 | 100 | 6.3 | 4229.17 | 1.69411 | ORIGINAL | SB-7501(?) | +206.605 | +206.505
STÅLBJELKE | STEEL/S355 | DSB-19503(?) | 66.5702 | 3594.64 | 148.682 | 100 | 0.00848028 | 2.69688 | 66.5702 | 65.9783 | 0.0084 | 0.00848 | 1.38645 | 100 | 6.3 | 3591.83 | 1.4391 | ORIGINAL | SB-7500(?) | +207.100 | +207.000
STÅLBJELKE | STEEL/S355 | DSB-19504(?) | 64.7105 | 3494.87 | 146.033 | 100 | 0.00824338 | 2.62167 | 64.7105 | 64.1321 | 0.00817 | 0.00823 | 1.34765 | 100 | 6.3 | 3491.32 | 1.39897 | ORIGINAL | SB-7500(?) | +206.605 | +206.505
STÅLBJELKE | STEEL/S355 | DSB-19505(?) | 68.1905 | 3682.13 | 135.688 | 100 | 0.00868668 | 2.7624 | 68.1905 | 67.5837 | 0.00862 | 0.0087 | 1.42018 | 100 | 6.3 | 3679.23 | 1.47407 | ORIGINAL | SB-7499(?) | +207.100 | +207.000
STÅLBJELKE | STEEL/S355 | DSB-19506(?) | 67.2715 | 3632.2 | 135.688 | 100 | 0.00856962 | 2.72524 | 67.2715 | 66.6676 | 0.00849 | 0.00857 | 1.40093 | 100 | 6.3 | 3629.35 | 1.45423 | ORIGINAL | SB-7499(?) | +206.605 | +206.505
STÅLBJELKE | STEEL/S355 | DSB-19507(?) | 72.0009 | 3888 | 154.029 | 100 | 0.00917209 | 2.9165 | 72.0009 | 71.3533 | 0.00909 | 0.00917 | 1.49939 | 100 | 6.3 | 3884.44 | 1.5563 | ORIGINAL | SB-7498(?) | +207.100 | +207.000
STÅLBJELKE | STEEL/S355 | DSB-19508(?) | 70.1424 | 3787.79 | 151.298 | 100 | 0.00893534 | 2.84134 | 70.1424 | 69.5123 | 0.00886 | 0.00894 | 1.46071 | 100 | 6.3 | 3784.22 | 1.51619 | ORIGINAL | SB-7498(?) | +206.605 | +206.505
STÅLBJELKE |  | DSB-19509(?) | 53.2757 | 2915 | 149 | 100 | 0.00678672 | 2.17509 |  |  |  |  |  |  |  |  |  | RESULT | SB-7497(?) | +207.100 | +207.000
STÅLBJELKE |  | DSB-19510(?) | 52.3498 | 2865 | 147 | 100 | 0.00666876 | 2.12242 |  |  |  |  |  |  |  |  |  | RESULT | SB-7497(?) | +206.605 | +206.505

# IfcBeam: RHS100*8, STÅLBJELKE
In: D
Description: RHS100*8
ePset_SimplebimBasicQuantities - Area, sides, net (Simplebim): 4.46692 m2; Width (Simplebim): 100 mm; Height (Simplebim): 100 mm; Length (Simplebim): 6061 mm; Volume, net (Simplebim): 0.0178441 m3; Weight, as steel (Simplebim): 140.077 kg
AVINOR - 08_Status: S4; 07_Fase: F90; 04_Kontrakt: 72274; 05_ID-nummer: +TS=223.001; 02_Prosjekt: T20100; 03_Ansvar: 72101; 06_Omrade: TS; 01_Lufthavnkode: ENGM
Pset_BeamCommon - Reference: DSB-8150(?); LoadBearing: no
ePset_LocationTool - Splitting: RESULT
Tekla Common - Grade: S355; Name: STÅLBJELKE; Part mark: DSB-8150(?); Profile: RHS100*8; Top elevation: +207.025; Assembly mark: SB-3695(?); Class: 330; Bottom elevation: +206.925
ePset_Simplebim - Assembly Level: Leaf

# IfcBeam: RHS150*100*6 (2)
In: D
Description: RHS150*100*6; Material: STEEL/S355
Tekla Quantity - Width: 100 mm; Heigth: 150 mm
ePset_LocationTool - Splitting: ORIGINAL
ePset_Simplebim - Assembly Level: Leaf
ePset_SimplebimBasicQuantities - Height (Simplebim): 150 mm; Width (Simplebim): 100 mm
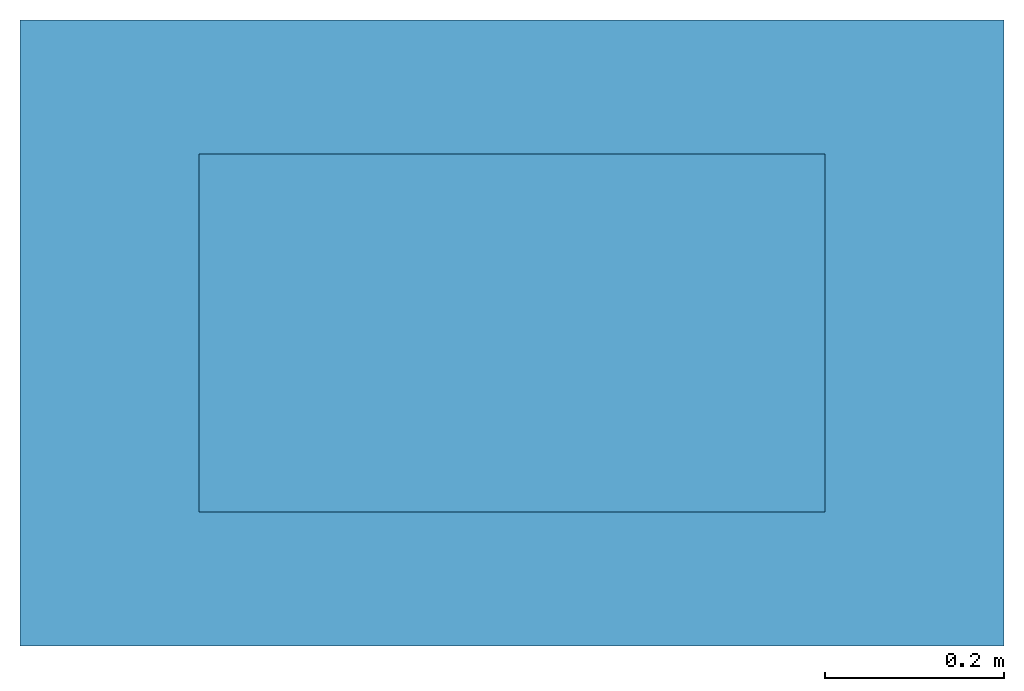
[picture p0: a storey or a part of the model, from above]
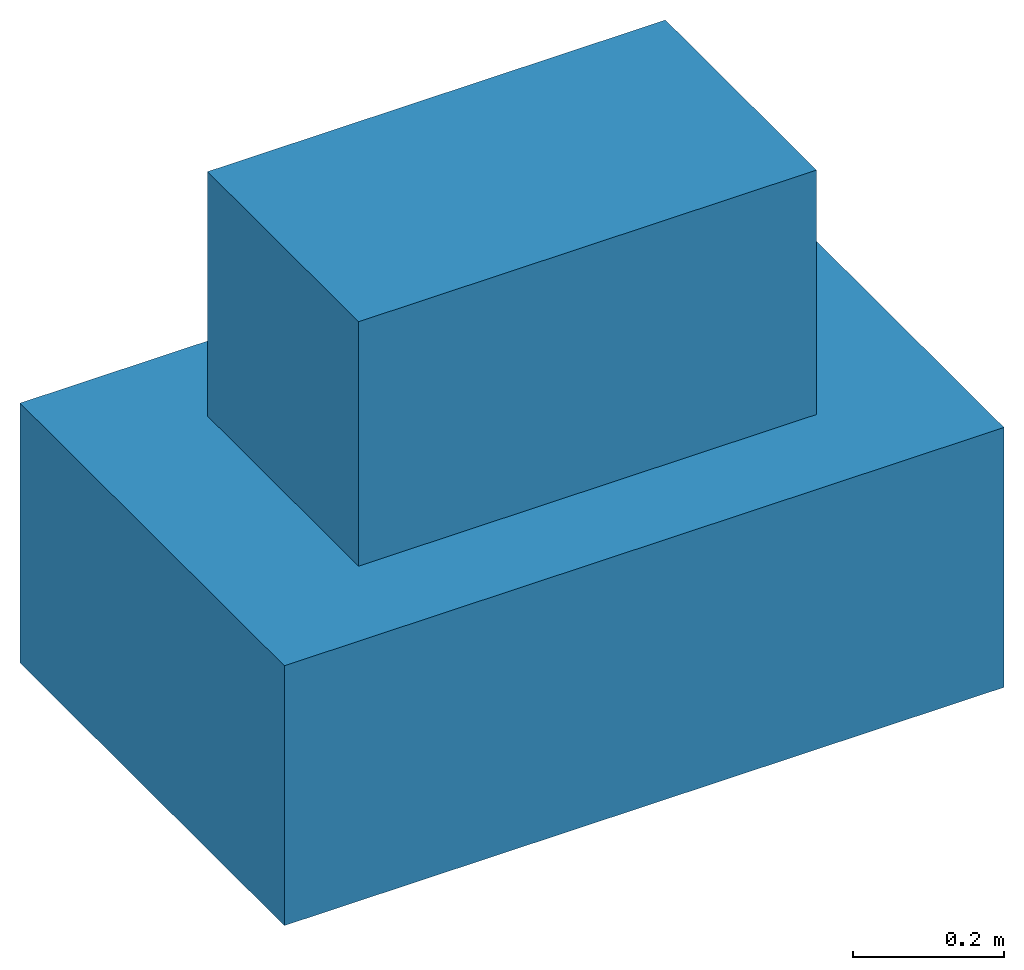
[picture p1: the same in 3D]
Properties of the parts of a building model (IFC2X3), part 2 of 5

# IfcBeam: RHS150*100*6 (2)
Tekla Common - Grade: S355; Bottom elevation: +206.950; Assembly mark: SB-14582(?); Name: STÅLBJELKE; Profile: RHS150*100*6; Class: 330; Top elevation: +207.100
Pset_BeamCommon - LoadBearing: no
AVINOR - 08_Status: S4; 07_Fase: F90; 05_ID-nummer: +TS=223.008; 02_Prosjekt: T20100; 04_Kontrakt: 72233; 03_Ansvar: 72101; 06_Omrade: TS; 01_Lufthavnkode: ENGM
Name | WEIGTH_GROSS (kg) = WEIGTH_NET (kg) = Weight, as steel (Simplebim) (kg) | AREA_GROSS (m2) = AREA_NET (m2) | VOLUME_NET (m3) | VOLUME_GROSS (m3) | Length (mm) = Length (Simplebim) (mm) | Volume, net (Simplebim) (m3) | Area, sides, net (Simplebim) (m2) | Part mark = Reference
STÅLBJELKE | 65.4795 | 1.45141 | 0.00833 | 0.00834 | 2955.18 | 0.00834133 | 2.78671 | DSB-24459(?)
STÅLBJELKE | 20.3695 | 0.45376 | 0.00259 | 0.00259 | 941.19 | 0.00259484 | 0.871214 | DSB-24457(?)

# IfcBeam: RHS40*4 (8)
In: D
Description: RHS40*4; Material: STEEL/S355
ePset_LocationTool - Splitting: ORIGINAL
AVINOR - 08_Status: S4; 07_Fase: F90; 02_Prosjekt: T20100; 05_ID-nummer: +TS=222.012; 04_Kontrakt: 72233; 03_Ansvar: 72101; 06_Omrade: TS; 01_Lufthavnkode: ENGM
Tekla Common - Grade: S355; Name: STÅLBJELKE; Profile: RHS40*4; Assembly mark: SB-12652(?); Top elevation: +207.275; Part mark: DSB-24616(?); Class: 330; Bottom elevation: +207.100
ePset_Simplebim - Assembly Level: Leaf
ePset_SimplebimBasicQuantities - Volume, net (Simplebim): 0.0001008 m3; Area, sides, net (Simplebim): 0.051552 m2; Length (Simplebim): 40 mm; Width (Simplebim): 40 mm; Height (Simplebim): 175 mm; Weight, as steel (Simplebim): 0.79128 kg
Tekla Quantity - WEIGTH_GROSS: 0.78029 kg; VOLUME_GROSS: 0.0001 m3; VOLUME_NET: 0.0001 m3; AREA_NET: 0.02864 m2; AREA_GROSS: 0.02642 m2; Heigth: 40 mm; Width: 40 mm; WEIGTH_NET: 0.79128 kg; Length: 175 mm
Pset_BeamCommon - LoadBearing: no; Reference: DSB-24616(?)

# IfcBeam: RHS60*5, STÅLBJELKE
In: D
Description: RHS60*5; Material: STEEL/S355
AVINOR - 08_Status: S4; 07_Fase: F90; 02_Prosjekt: T1; 04_Kontrakt: FDV; 03_Ansvar: FDV; 06_Omrade: TS; 01_Lufthavnkode: ENGM
Tekla Quantity - WEIGTH_NET: 16.6267 kg; Length: 1925.5 mm; WEIGTH_GROSS: 16.4755 kg; AREA_NET: 0.46332 m2; VOLUME_GROSS: 0.0021 m3; Heigth: 60 mm; Width: 60 mm; AREA_GROSS: 0.44094 m2; VOLUME_NET: 0.00212 m3
ePset_SimplebimBasicQuantities - Weight, as steel (Simplebim): 16.6267 kg; Length (Simplebim): 1925.5 mm; Area, sides, net (Simplebim): 0.84942 m2; Height (Simplebim): 60 mm; Width (Simplebim): 60 mm; Volume, net (Simplebim): 0.00211805 m3
Pset_BeamCommon - LoadBearing: no; Reference: DSB-9290(?)
ePset_Simplebim - Assembly Level: Leaf
Tekla Common - Grade: S355; Name: STÅLBJELKE; Top elevation: +207.090; Bottom elevation: +207.030; Assembly mark: SB-4620(?); Part mark: DSB-9290(?); Class: 330; Profile: RHS60*5
ePset_LocationTool - Splitting: ORIGINAL

# IfcBeam: RHS60*6, STÅLBJELKE
In: D
Description: RHS60*6
AVINOR - 08_Status: S4; 07_Fase: F90; 02_Prosjekt: T1; 04_Kontrakt: FDV; 03_Ansvar: FDV; 06_Omrade: TS; 01_Lufthavnkode: ENGM
ePset_SimplebimBasicQuantities - Volume, net (Simplebim): 0.00190612 m3; Weight, as steel (Simplebim): 14.9631 kg; Length (Simplebim): 60 mm; Width (Simplebim): 60 mm; Height (Simplebim): 1551 mm; Area, sides, net (Simplebim): 0.639705 m2
ePset_LocationTool - Splitting: RESULT
Tekla Common - Grade: S355; Name: STÅLBJELKE; Bottom elevation: +203.958; Top elevation: +206.897; Assembly mark: SB-6396(?); Class: 330; Part mark: DSB-11377(?); Profile: RHS60*6
ePset_Simplebim - Assembly Level: Leaf
Pset_BeamCommon - LoadBearing: no; Reference: DSB-11377(?)

# IfcBeam: RHS80*4, STÅLBJELKE
In: D
Description: RHS80*4; Material: STEEL/S355
ePset_SimplebimBasicQuantities - Area, sides, net (Simplebim): 11.0012 m2; Volume, net (Simplebim): 0.0219974 m3; Weight, as steel (Simplebim): 172.68 kg; Length (Simplebim): 18090 mm; Width (Simplebim): 80 mm; Height (Simplebim): 80 mm
ePset_LocationTool - Splitting: ORIGINAL
ePset_Simplebim - Assembly Level: Leaf
AVINOR - 07_Fase: F90; 02_Prosjekt: T1; 04_Kontrakt: FDV; 03_Ansvar: FDV; 08_Status: S2; 06_Omrade: TS; 01_Lufthavnkode: ENGM
Pset_BeamCommon - LoadBearing: no; Reference: DSB-7503(?)
Tekla Common - Grade: S355; Profile: RHS80*4; Name: STÅLBJELKE; Assembly mark: SB-3283(?); Part mark: DSB-7503(?); Top elevation: +206.880; Bottom elevation: +206.800; Class: 330
Tekla Quantity - AREA_NET: 5.79008 m2; AREA_GROSS: 5.79008 m2; WEIGTH_GROSS: 172.68 kg; WEIGTH_NET: 172.68 kg; Length: 18090 mm; VOLUME_GROSS: 0.022 m3; VOLUME_NET: 0.022 m3; Heigth: 80 mm; Width: 80 mm

# IfcBeam: RHS80*5 (6)
In: D
Description: RHS80*5
Pset_BeamCommon - LoadBearing: no
ePset_Simplebim - Assembly Level: Leaf
AVINOR - 07_Fase: F90; 06_Omrade: TS; 01_Lufthavnkode: ENGM
ePset_SimplebimBasicQuantities - Height (Simplebim): 80 mm; Width (Simplebim): 80 mm
Tekla Common - Grade: S355; Profile: RHS80*5; Name: STÅLBJELKE; Bottom elevation: +207.080; Class: 330; Top elevation: +207.160
Name | Material | Reference = Part mark | Splitting | 02_Prosjekt | 04_Kontrakt | 03_Ansvar | 08_Status | Weight, as steel (Simplebim) (kg) | Volume, net (Simplebim) (m3) | Length (Simplebim) (mm) | Area, sides, net (Simplebim) (m2) | WEIGTH_GROSS (kg) | VOLUME_NET (m3) | VOLUME_GROSS (m3) | AREA_GROSS (m2) | Length (mm) | Heigth (mm) = Width (mm) | WEIGTH_NET (kg) | AREA_NET (m2) | Assembly mark | 05_ID-nummer
STÅLBJELKE | STEEL/S355 | DSB-7999(?) | ORIGINAL | T1 | FDV | FDV | S2 | 34.2653 | 0.004365 | 2910 | 1.749 | 34.0368 | 0.00437 | 0.00434 | 0.89919 | 2910 | 80 | 34.2653 | 0.9328 | SB-3468(?)
3 x STÅLBJELKE | STEEL/S355 | DSB-8679(?) | ORIGINAL | T20100 | 72274 | 72101 | S4 | 34.2653 | 0.004365 | 2910 | 1.749 | 34.0368 | 0.00437 | 0.00434 | 0.89919 | 2910 | 80 | 34.2653 | 0.9328 | SB-4127(?) | +TS=223.001
STÅLBJELKE | STEEL/S355 | DSB-8675(?) | ORIGINAL | T20100 | 72274 | 72101 | S4 | 34.2653 | 0.004365 | 2910 | 1.749 | 34.0368 | 0.00437 | 0.00434 | 0.89919 | 2910 | 80 | 34.2653 | 0.9328 | SB-4123(?) | +TS=223.001
STÅLBJELKE |  | DSB-8682(?) | RESULT | T1 | FDV | FDV | S2 | 21.2636 | 0.00270874 | 1525 | 0.906465 |  |  |  |  |  |  |  |  | SB-4130(?)

# IfcBeam: RHS80*6 (10)
In: D
Description: RHS80*6; Material: STEEL/S355
ePset_SimplebimBasicQuantities - Width (Simplebim): 80 mm; Height (Simplebim): 80 mm
Tekla Quantity - Heigth: 80 mm; Width: 80 mm
ePset_LocationTool - Splitting: ORIGINAL
ePset_Simplebim - Assembly Level: Leaf
Pset_BeamCommon - LoadBearing: no
Tekla Common - Grade: S355; Profile: RHS80*6; Name: STÅLBJELKE; Class: 330
AVINOR - 08_Status: S4; 07_Fase: F90; 02_Prosjekt: T20100; 03_Ansvar: 72101; 06_Omrade: TS; 01_Lufthavnkode: ENGM
Name | Length (Simplebim) (mm) = Length (mm) | Area, sides, net (Simplebim) (m2) | Volume, net (Simplebim) (m3) | Weight, as steel (Simplebim) (kg) | AREA_NET (m2) | AREA_GROSS (m2) | WEIGTH_NET (kg) | WEIGTH_GROSS (kg) | VOLUME_GROSS (m3) | VOLUME_NET (m3) | Reference = Part mark | Assembly mark | Top elevation | Bottom elevation | 05_ID-nummer | 04_Kontrakt
2 x STÅLBJELKE | 3200.04 | 1.89798 | 0.00568328 | 44.6137 | 1.02593 | 1.02593 | 44.6138 | 44.6138 | 0.00567 | 0.00567 | DSB-24166(?) | SB-14447(?) | +206.880 | +206.800 | +TS=223.008 | 72233
4 x STÅLBJELKE | 401.899 | 0.241476 | 0.000713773 | 5.60312 | 0.13053 | 0.13053 | 5.60312 | 5.60312 | 0.0007 | 0.00071 | DSB-24165(?) | SB-7496(?) | +206.913 | +206.833 | +TS=221.014 | 72717
STÅLBJELKE | 1469.73 | 0.855451 | 0.00255424 | 20.0508 | 0.46241 | 0.46241 | 20.0508 | 20.0508 | 0.00255 | 0.00255 | DSB-24168(?) | SB-7497(?) | +206.913 | +206.833 | +TS=221.014 | 72717
STÅLBJELKE | 5980 | 3.54371 | 0.0106205 | 83.3708 | 1.91552 | 1.91552 | 83.3708 | 83.3708 | 0.01062 | 0.01062 | DSB-24167(?) | SB-12634(?) | +206.880 | +206.800 | +TS=223.008 | 72233
STÅLBJELKE | 4160 | 2.46627 | 0.00738816 | 57.9971 | 1.33312 | 1.33312 | 57.9971 | 57.9971 | 0.00739 | 0.00739 | DSB-24170(?) | SB-7496(?) | +206.913 | +206.833 | +TS=221.014 | 72717
STÅLBJELKE | 1786.38 | 1.05084 | 0.00314136 | 24.6596 | 0.56802 | 0.60289 | 24.6596 | 26.1827 | 0.00334 | 0.00314 | DSB-24172(?) | SB-14448(?) | +207.100 | +207.020 | +TS=223.008 | 72233

# IfcBeam: RHS80*80*5 (2)
In: D
Description: RHS80*80*5
Tekla Common - Grade: S355; Profile: RHS80*80*5; Name: STÅLBJELKE; Top elevation: +207.005; Class: 330; Bottom elevation: +206.925
ePset_Simplebim - Assembly Level: Leaf
AVINOR - 07_Fase: F90; 02_Prosjekt: T1; 04_Kontrakt: FDV; 03_Ansvar: FDV; 08_Status: S2; 06_Omrade: TS; 01_Lufthavnkode: ENGM
ePset_SimplebimBasicQuantities - Width (Simplebim): 80 mm; Height (Simplebim): 80 mm
Pset_BeamCommon - LoadBearing: no
Name | Assembly mark | Part mark = Reference | Splitting | Area, sides, net (Simplebim) (m2) | Volume, net (Simplebim) (m3) | Weight, as steel (Simplebim) (kg) | Length (Simplebim) (mm)
STÅLBJELKE | SB-3691(?) | DSB-8136(?) | ORIGINAL | 2.87761 | 0.00718652 | 56.4142 | 4791.01 | Material: STEEL/S355; Tekla Quantity - VOLUME_NET: 0.00718 m3; AREA_NET: 1.53472 m2; AREA_GROSS: 1.48042 m2; VOLUME_GROSS: 0.00713 m3; WEIGTH_GROSS: 56.0381 kg; Heigth: 80 mm; Width: 80 mm; Length: 4791.01 mm; WEIGTH_NET: 56.4142 kg
STÅLBJELKE | SB-3763(?) | DSB-8140(?) | RESULT | 0.921115 | 0.00229529 | 18.018 | 1530

# IfcBeam: RHS80*80*8, STÅLBJELKE
In: D
Description: RHS80*80*8
ePset_SimplebimBasicQuantities - Area, sides, net (Simplebim): 3.69171 m2; Volume, net (Simplebim): 0.0147484 m3; Width (Simplebim): 80 mm; Height (Simplebim): 80 mm; Length (Simplebim): 6401 mm; Weight, as steel (Simplebim): 115.775 kg
AVINOR - 08_Status: S4; 07_Fase: F90; 04_Kontrakt: 72274; 05_ID-nummer: +TS=223.001; 02_Prosjekt: T20100; 03_Ansvar: 72101; 06_Omrade: TS; 01_Lufthavnkode: ENGM
ePset_Simplebim - Assembly Level: Leaf
ePset_LocationTool - Splitting: RESULT
Pset_BeamCommon - Reference: DSB-8149(?); LoadBearing: no
Tekla Common - Grade: S355; Profile: RHS80*80*8; Name: STÅLBJELKE; Top elevation: +207.005; Part mark: DSB-8149(?); Assembly mark: SB-3694(?); Class: 330; Bottom elevation: +206.925

# IfcBeam: UNP400 (3)
In: D
Description: UNP400
ePset_SimplebimBasicQuantities - Width (Simplebim): 110 mm; Height (Simplebim): 400 mm
ePset_Simplebim - Assembly Level: Leaf
AVINOR - 07_Fase: F90; 02_Prosjekt: T1; 04_Kontrakt: FDV; 03_Ansvar: FDV; 08_Status: S2; 06_Omrade: TS; 01_Lufthavnkode: ENGM
Tekla Common - Grade: S355; Name: STÅLBJELKE; Profile: UNP400; Class: 330
Pset_BeamCommon - LoadBearing: no
Name | Volume, net (Simplebim) (m3) | Area, sides, net (Simplebim) (m2) | Length (Simplebim) (mm) | Weight, as steel (Simplebim) (kg) | Splitting | Bottom elevation | Part mark = Reference | Top elevation | Assembly mark
STÅLBJELKE | 0.132585 | 17.7569 | 14750 | 1040.79 | ORIGINAL | +206.760 | DSB-8108(?) | +207.160 | SB-3739(?) | Material: STEEL/S355; Tekla Quantity - VOLUME_NET: 0.13258 m3; VOLUME_GROSS: 0.13496 m3; Length: 14750 mm; WEIGTH_GROSS: 1059.46 kg; WEIGTH_NET: 1040.79 kg; Width: 110 mm; Heigth: 400 mm; AREA_GROSS: 17.4345 m2; AREA_NET: 17.7569 m2
STÅLBJELKE | 0.0251237 | 3.37936 | 2795 | 197.221 | RESULT | +206.760 | DSB-7519(?) | +207.160 | SB-3299(?)
STÅLBJELKE | 0.0251237 | 3.37935 | 2795 | 197.221 | RESULT | +206.700 | DSB-7400(?) | +207.100 | SB-3205(?)

# IfcBuildingElementProxy (2)
In: Nivå D
ePset_Simplebim - Assembly Level: Leaf
ePset_LocationTool - Splitting: ORIGINAL
Group: +TS=360.010 A
Name | Area, largest surface, net (Simplebim) (m2) | Thickness (Simplebim) (mm) | Length (Simplebim) (mm) | Volume, net (Simplebim) (m3) | Height (Simplebim) (mm)
hette 1100-2000-550 2ø315 | 3 | 1500 | 2000 | 1.50009 | 509.515
hette 1200-1200-400 ø315 2 | 1.44 | 1200 | 1200 | 0.7216 | 510

# IfcBuildingElementProxy: 05.200.7eleven-skilt:05.200.7eleven-skilt, 05.200.7eleven-skilt:05.200.7eleven-skilt:41948400
In: Nivå D + 1,2 m
Type - Material: <Unnamed>, _NSW Stål
ePset_LocationTool - Splitting: ORIGINAL
ePset_Simplebim - Assembly Level: Leaf
AVINOR - 08_Status: S4; 07_Fase: F40; 03_Ansvar: LEIETAKER; 02_Prosjekt: 72101; 06_Omrade: TS; 01_Lufthavnkode: ENGM
Pset_QuantityTakeOff - Reference: 05.200.7eleven-skilt; sets with these values: 2
ePset_SimplebimBasicQuantities - Thickness (Simplebim): 507.976 mm; Length (Simplebim): 606.207 mm; Volume, net (Simplebim): 0.0963516 m3; Area, largest surface, net (Simplebim): 0.480011 m2; Height (Simplebim): 1300 mm

# IfcBuildingElementProxy: 05.200._nedhengt_skilt:05.200._nedhengt_skilt, 05.200._nedhengt_skilt:05.200._nedhengt_skilt:41948426
In: Nivå D + 1,2 m
Type - Material: <Unnamed>
ePset_SimplebimBasicQuantities - Thickness (Simplebim): 1813.75 mm; Volume, net (Simplebim): 0.120472 m3; Area, largest surface, net (Simplebim): 1.44756 m2; Height (Simplebim): 1100 mm; Length (Simplebim): 1858.16 mm
Pset_BuildingElementProxyCommon - Reference: 05.200._nedhengt_skilt; sets with these values: 2
ePset_LocationTool - Splitting: ORIGINAL
ePset_Simplebim - Assembly Level: Leaf
AVINOR - 08_Status: S4; 07_Fase: F40; 03_Ansvar: LEIETAKER; 02_Prosjekt: 72101; 06_Omrade: TS; 01_Lufthavnkode: ENGM

# IfcBuildingElementProxy: A275 - EL skap:A275 - EL skap, A275 - EL skap:A275 - EL skap:39991694
In: Nivå D
Type - Material: <Unnamed>
AVINOR - 08_Status: S4; 04_Kontrakt: 72717; 07_Fase: F50; 02_Prosjekt: 72101; 03_Ansvar: AE1; 06_Omrade: TS; 01_Lufthavnkode: ENGM
ePset_LocationTool - Splitting: ORIGINAL
ePset_Simplebim - Assembly Level: Leaf
ePset_SimplebimBasicQuantities - Area, largest surface, net (Simplebim): 2.145 m2; Volume, net (Simplebim): 0.79365 m3; Thickness (Simplebim): 370 mm; Height (Simplebim): 1950 mm; Length (Simplebim): 1100 mm
Pset_BuildingElementProxyCommon - Reference: A275 - EL skap; sets with these values: 2

# IfcBuildingElementProxy: A275 - Pylon - venstrehengslet:Pylon med topp brakett, A275 - Pylon - venstrehengslet:Pylon med topp brakett:43111139
In: Nivå D
Type - Material: <Unnamed>
ePset_LocationTool - Splitting: ORIGINAL
AVINOR - 08_Status: S1; 07_Fase: F50; 04_Kontrakt: 72587; 02_Prosjekt: 72101; 03_Ansvar: AE1; 06_Omrade: TS; 01_Lufthavnkode: ENGM
Pset_QuantityTakeOff - Reference: Pylon med topp brakett; sets with these values: 2
ePset_Simplebim - Assembly Level: Leaf
ePset_SimplebimBasicQuantities - Area, largest surface, net (Simplebim): 1.78713 m2; Volume, net (Simplebim): 0.0408924 m3; Thickness (Simplebim): 195 mm; Length (Simplebim): 752 mm; Height (Simplebim): 2500 mm

# IfcBuildingElementProxy: A278 - Vannfordelingsskap innfelt i vegg:V310 - Vannfordelingsskap innfelt i vegg, A278 - Vannfordelingsskap innfelt i vegg:V310 - Vannfordelingsskap innfelt i vegg:42350338
In: Nivå D
Type - Material: <Unnamed>
AVINOR - 08_Status: S4; 07_Fase: F90; 03_Ansvar: 72717; 02_Prosjekt: 72101; 06_Omrade: TS; 01_Lufthavnkode: ENGM
ePset_SimplebimBasicQuantities - Volume, net (Simplebim): 0.035625 m3; Area, largest surface, net (Simplebim): 0.375 m2; Thickness (Simplebim): 95 mm; Height (Simplebim): 500 mm; Length (Simplebim): 750 mm
Pset_QuantityTakeOff - Reference: V310 - Vannfordelingsskap innfelt i vegg; sets with these values: 2
ePset_Simplebim - Assembly Level: Leaf
ePset_LocationTool - Splitting: ORIGINAL

# IfcBuildingElementProxy: ProvisionForVoid (11)
ePset_LocationTool - Splitting: ORIGINAL
ePset_Simplebim - Assembly Level: Leaf
Name | In | Volume, net (Simplebim) (m3) | Length (Simplebim) (mm) = Thickness (Simplebim) (mm) | Height (Simplebim) (mm) | Area, largest surface, net (Simplebim) (m2)
3 x MagiCAD_ProvisionForVoid | Nivå C | 0.00328195 | 100 | 420 | 0.131779
MagiCAD_ProvisionForVoid | Nivå C | 0.00738439 | 150 | 420 | 0.197669
MagiCAD_ProvisionForVoid | Nivå C | 0.000820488 | 50 | 420 | 0.0658897
MagiCAD_ProvisionForVoid | Nivå C | 0.00180539 | 76 | 400 | 0.0953832
3 x MagiCAD_ProvisionForVoid | Nivå C | 0.00189565 | 76 | 420 | 0.100152
2 x Round Vertical | Nivå D | 0.00500107 | 100 | 640 | 0.200807

# IfcBuildingElementProxy: V333 - Sprinkelhode:V333 - Sprinkelhode (18)
In: Nivå D
Type - Material: <Unnamed>
ePset_LocationTool - Splitting: ORIGINAL
ePset_SimplebimBasicQuantities - Height (Simplebim): 30 mm; Volume, net (Simplebim): 0.000084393 m3; Area, largest surface, net (Simplebim): 0.00564769 m2; Length (Simplebim): 60 mm; Thickness (Simplebim): 60 mm
Pset_BuildingElementProxyCommon - Reference: V333 - Sprinkelhode; sets with these values: 2
ePset_Simplebim - Assembly Level: Leaf
AVINOR - 08_Status: S1; 04_Kontrakt: 72717; 07_Fase: F50; 03_Ansvar: AV1; 02_Prosjekt: 72101; 06_Omrade: TS; 01_Lufthavnkode: ENGM
Name (V333 - Sprinkelhode:V333 - Sprinkelhode:...)
40024612
40024615
40024616
40024637
40024638
40024639
40024641
40024642
40024644
41940235
41944472
41948483
42211070
42285979
42329920
42329921
42329922
42329923

# IfcColumn: 100*10 (8)
In: D
Description: 100*10; Material: STEEL/S355
AVINOR - 08_Status: S4; 07_Fase: F90; 04_Kontrakt: 72717; 02_Prosjekt: T20100; 05_ID-nummer: +TS=221.014; 03_Ansvar: 72101; 06_Omrade: TS; 01_Lufthavnkode: ENGM
ePset_Simplebim - Assembly Level: Leaf
ePset_SimplebimBasicQuantities - Height (Simplebim): 200 mm; Volume, net (Simplebim): 0.0002 m3; Area, sides, net (Simplebim): 0.006 m2; Width (Simplebim): 10 mm; Depth (Simplebim): 100 mm; Weight, as steel (Simplebim): 1.57 kg
Tekla Common - Grade: S355; Class: 320; Profile: 100*10; Name: STÅLSØYLE; Part mark: DSS-7184(?)
ePset_LocationTool - Splitting: ORIGINAL
Pset_ColumnCommon - Reference: DSS-7184(?); LoadBearing: no
Tekla Quantity - VOLUME_NET: 0.00019 m3; VOLUME_GROSS: 0.00019 m3; AREA_GROSS: 0.046 m2; AREA_NET: 0.046 m2; Width: 10 mm; Heigth: 100 mm; Length: 200 mm; WEIGTH_GROSS: 1.57 kg; WEIGTH_NET: 1.57 kg
Name | Assembly mark | Top elevation | Bottom elevation
STÅLSØYLE | SS-7494(?) | +206.515 | +206.505
STÅLSØYLE | SS-7494(?) | +207.000 | +206.990
STÅLSØYLE | SS-7496(?) | +206.515 | +206.505
STÅLSØYLE | SS-7496(?) | +207.000 | +206.990
2 x STÅLSØYLE | SS-7495(?) | +206.515 | +206.505
2 x STÅLSØYLE | SS-7495(?) | +207.000 | +206.990

# IfcColumn: 400*700 (2)
Description: 400*700; Material: CONCRETE/C45/55
ePset_SimplebimBasicQuantities - Volume, net (Simplebim): 0.1106 m3; Area, sides, net (Simplebim): 0.869 m2; Depth (Simplebim): 400 mm; Width (Simplebim): 395 mm; Height (Simplebim): 700 mm; Weight, as steel (Simplebim): 868.21 kg
Tekla Quantity - AREA_GROSS: 1.429 m2; AREA_NET: 1.429 m2; VOLUME_GROSS: 0.1106 m3; VOLUME_NET: 0.1106 m3; Length: 395 mm; Heigth: 400 mm; Width: 700 mm; WEIGTH_GROSS: 265.44 kg; WEIGTH_NET: 265.44 kg
ePset_Simplebim - Assembly Level: Leaf
AVINOR - 07_Fase: F90; 02_Prosjekt: T1; 04_Kontrakt: FDV; 03_Ansvar: FDV; 08_Status: S2; 06_Omrade: TS; 01_Lufthavnkode: ENGM
Pset_ColumnCommon - LoadBearing: no
Tekla Common - Name: PREFABSØYLE; Class: 120; Top elevation: +203.795; Grade: C45/55; Bottom elevation: +203.400; Profile: 400*700
ePset_LocationTool - Splitting: ORIGINAL
Name | In | Reference = Part mark | Assembly mark
PREFABSØYLE | B | Concrete-8770 | PS-249
PREFABSØYLE | C | Concrete-8769 | PS-221

# IfcColumn: 700*1100 (2)
Description: 700*1100; Material: CONCRETE/C45/55
Tekla Quantity - AREA_NET: 3.052 m2; AREA_GROSS: 3.052 m2; VOLUME_GROSS: 0.3234 m3; VOLUME_NET: 0.3234 m3; WEIGTH_GROSS: 776.16 kg; WEIGTH_NET: 776.16 kg; Length: 420 mm; Heigth: 700 mm; Width: 1100 mm
Pset_ColumnCommon - LoadBearing: no
Tekla Common - Name: PREFABSØYLE; Class: 120; Grade: C45/55; Bottom elevation: +202.980; Profile: 700*1100; Top elevation: +203.400
ePset_Simplebim - Assembly Level: Leaf
AVINOR - 07_Fase: F90; 02_Prosjekt: T1; 04_Kontrakt: FDV; 03_Ansvar: FDV; 08_Status: S2; 06_Omrade: TS; 01_Lufthavnkode: ENGM
ePset_LocationTool - Splitting: ORIGINAL
ePset_SimplebimBasicQuantities - Volume, net (Simplebim): 0.3234 m3; Area, sides, net (Simplebim): 1.512 m2; Weight, as steel (Simplebim): 2538.69 kg; Width (Simplebim): 420 mm; Depth (Simplebim): 700 mm; Height (Simplebim): 1100 mm
Name | In | Reference = Part mark | Assembly mark
PREFABSØYLE | B | Concrete-8722 | PS-249
PREFABSØYLE | C | Concrete-8717 | PS-221

# IfcColumn: 80*80 (4)
In: D
Description: 80*80; Material: STEEL/S355
ePset_SimplebimBasicQuantities - Area, sides, net (Simplebim): 0.00159974 m2; Width (Simplebim): 4.9992 mm; Weight, as steel (Simplebim): 0.25116 kg; Volume, net (Simplebim): 0.0000319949 m3; Height (Simplebim): 80 mm; Depth (Simplebim): 80 mm
AVINOR - 08_Status: S4; 07_Fase: F90; 04_Kontrakt: 72274; 05_ID-nummer: +TS=222.004; 02_Prosjekt: T20100; 03_Ansvar: 72101; 06_Omrade: TS; 01_Lufthavnkode: ENGM
Tekla Common - Grade: S355; Part mark: DSS-2341(?); Class: 320; Bottom elevation: +207.075; Name: STÅLSØYLE; Top elevation: +207.080; Profile: 80*80
Tekla Quantity - VOLUME_NET: 0.00004 m3; WEIGTH_GROSS: 0.25137 kg; WEIGTH_NET: 0.25137 kg; Heigth: 80 mm; Width: 80 mm; Length: 5.00338 mm; VOLUME_GROSS: 0.00003 m3; AREA_NET: 0.0144 m2; AREA_GROSS: 0.0144 m2
Pset_ColumnCommon - Reference: DSS-2341(?); LoadBearing: no
ePset_Simplebim - Assembly Level: Leaf
ePset_LocationTool - Splitting: ORIGINAL
Name | Assembly mark
STÅLSØYLE | SS-1562(?)
STÅLSØYLE | SS-1435(?)
STÅLSØYLE | SS-1434(?)
STÅLSØYLE | SS-1791(?)

# IfcColumn: D600 (2)
In: D
Description: D600; Material: CONCRETE/C45/55
ePset_LocationTool - Splitting: ORIGINAL
Tekla Common - Name: PREFABSØYLE; Bottom elevation: +203.845; Top elevation: +209.170; Class: 120; Grade: C45/55; Profile: D600
ePset_SimplebimBasicQuantities - Weight, as steel (Simplebim): 11770.5 kg; Area, sides, net (Simplebim): 10.0271 m2; Width (Simplebim): 600 mm; Depth (Simplebim): 600 mm; Height (Simplebim): 5325 mm; Volume, net (Simplebim): 1.49942 m3
ePset_Simplebim - Assembly Level: Leaf
AVINOR - 07_Fase: F90; 02_Prosjekt: T1; 04_Kontrakt: FDV; 03_Ansvar: FDV; 08_Status: S2; 06_Omrade: TS; 01_Lufthavnkode: ENGM
Tekla Quantity - AREA_GROSS: 10.5902 m2; AREA_NET: 10.5902 m2; WEIGTH_GROSS: 3598.62 kg; WEIGTH_NET: 3598.62 kg; VOLUME_GROSS: 1.49942 m3; VOLUME_NET: 1.49942 m3; Heigth: 600 mm; Width: 600 mm; Length: 5325 mm
Pset_ColumnCommon - LoadBearing: no
Name | Part mark = Reference | Assembly mark
PREFABSØYLE | Concrete-12200 | PS-290
PREFABSØYLE | Concrete-1423 | PS-104

# IfcColumn: PL10*110, STÅLSØYLE
In: D
Description: PL10*110; Material: STEEL/S355
AVINOR - 08_Status: S4; 07_Fase: F90; 02_Prosjekt: T1; 04_Kontrakt: FDV; 03_Ansvar: FDV; 06_Omrade: TS; 01_Lufthavnkode: ENGM
Pset_ColumnCommon - Reference: DSS-2368(?); LoadBearing: no
ePset_SimplebimBasicQuantities - Weight, as steel (Simplebim): 1.5543 kg; Volume, net (Simplebim): 0.000198 m3; Width (Simplebim): 10 mm; Depth (Simplebim): 110 mm; Height (Simplebim): 180 mm; Area, sides, net (Simplebim): 0.0418 m2
Tekla Quantity - WEIGTH_NET: 1.5543 kg; WEIGTH_GROSS: 1.5543 kg; AREA_NET: 0.04539 m2; VOLUME_NET: 0.00019 m3; VOLUME_GROSS: 0.00019 m3; AREA_GROSS: 0.0198 m2; Width: 10 mm; Length: 180 mm; Heigth: 110 mm
ePset_LocationTool - Splitting: ORIGINAL
ePset_Simplebim - Assembly Level: Leaf
Tekla Common - Grade: S355; Part mark: DSS-2368(?); Bottom elevation: +206.970; Class: 320; Name: STÅLSØYLE; Top elevation: +207.080; Profile: PL10*110; Assembly mark: SS-1672(?)

# IfcColumn: PL10*150 (5)
In: D
Description: PL10*150; Material: STEEL/S355
ePset_SimplebimBasicQuantities - Area, sides, net (Simplebim): 0.0457839 m2; Height (Simplebim): 195.946 mm; Weight, as steel (Simplebim): 1.71852 kg; Volume, net (Simplebim): 0.00021892 m3; Width (Simplebim): 10 mm; Depth (Simplebim): 150 mm
ePset_LocationTool - Splitting: ORIGINAL
AVINOR - 08_Status: S4; 07_Fase: F90; 02_Prosjekt: T20100; 03_Ansvar: 72101; 06_Omrade: TS; 01_Lufthavnkode: ENGM
Tekla Common - Grade: S355; Bottom elevation: +206.833; Top elevation: +206.983; Class: 320; Name: STÅLSØYLE; Part mark: DSS-5718(?); Profile: PL10*150
Tekla Quantity - AREA_NET: 0.05002 m2; VOLUME_GROSS: 0.00022 m3; VOLUME_NET: 0.00022 m3; WEIGTH_GROSS: 2.30727 kg; AREA_GROSS: 0.02939 m2; Length: 195.946 mm; WEIGTH_NET: 1.71852 kg; Width: 10 mm; Heigth: 150 mm
ePset_Simplebim - Assembly Level: Leaf
Pset_ColumnCommon - LoadBearing: no; Reference: DSS-5718(?)
Name | 04_Kontrakt | 05_ID-nummer | Assembly mark
STÅLSØYLE | 72717 | +TS=221.014 | SS-7494(?)
STÅLSØYLE | 72717 | +TS=221.014 | SS-7496(?)
2 x STÅLSØYLE | 72717 | +TS=221.014 | SS-7495(?)
STÅLSØYLE | 72233 | +TS=222.012 | SB-7502(?)

# IfcColumn: PL10*200 (5)
In: D
Description: PL10*200; Material: STEEL/S355
AVINOR - 08_Status: S4; 07_Fase: F90; 02_Prosjekt: T20100; 03_Ansvar: 72101; 06_Omrade: TS; 01_Lufthavnkode: ENGM
Tekla Quantity - Length: 210.433 mm; WEIGTH_GROSS: 3.3038 kg; WEIGTH_NET: 3.29699 kg; AREA_GROSS: 0.04209 m2; Width: 10 mm; Heigth: 200 mm; AREA_NET: 0.0922 m2; VOLUME_GROSS: 0.00042 m3; VOLUME_NET: 0.00042 m3
ePset_Simplebim - Assembly Level: Leaf
ePset_SimplebimBasicQuantities - Volume, net (Simplebim): 0.000419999 m3; Area, sides, net (Simplebim): 0.0082 m2; Depth (Simplebim): 200.454 mm; Weight, as steel (Simplebim): 3.29699 kg; Height (Simplebim): 210.433 mm; Width (Simplebim): 10 mm
Pset_ColumnCommon - LoadBearing: no
Tekla Common - Grade: S355; Top elevation: +206.833; Bottom elevation: +206.823; Profile: PL10*200; Class: 320; Name: STÅLSØYLE
ePset_LocationTool - Splitting: ORIGINAL
Name | 04_Kontrakt | 05_ID-nummer | Reference = Part mark | Assembly mark
STÅLSØYLE | 72717 | +TS=221.014 | DSS-5899(?) | SS-7494(?)
STÅLSØYLE | 72717 | +TS=221.014 | DSS-5900(?) | SS-7496(?)
2 x STÅLSØYLE | 72717 | +TS=221.014 | DSS-5899(?) | SS-7495(?)
STÅLSØYLE | 72233 | +TS=222.012 | DSS-5791(?) | SB-7502(?)

# IfcColumn: PL10*280, STÅLSØYLE
In: D
Description: PL10*280; Material: STEEL/S355
Pset_ColumnCommon - Reference: DSS-5796(?); LoadBearing: no
AVINOR - 08_Status: S4; 07_Fase: F90; 04_Kontrakt: 72717; 02_Prosjekt: T20100; 05_ID-nummer: +TS=221.014; 03_Ansvar: 72101; 06_Omrade: TS; 01_Lufthavnkode: ENGM
ePset_Simplebim - Assembly Level: Leaf
ePset_LocationTool - Splitting: ORIGINAL
ePset_SimplebimBasicQuantities - Volume, net (Simplebim): 0.00028 m3; Width (Simplebim): 10 mm; Depth (Simplebim): 100 mm; Height (Simplebim): 280 mm; Weight, as steel (Simplebim): 2.198 kg; Area, sides, net (Simplebim): 0.0076 m2
Tekla Quantity - VOLUME_GROSS: 0.00029 m3; VOLUME_NET: 0.00029 m3; AREA_NET: 0.0636 m2; AREA_GROSS: 0.0636 m2; Width: 10 mm; Length: 100 mm; Heigth: 280 mm; WEIGTH_GROSS: 2.198 kg; WEIGTH_NET: 2.198 kg
Tekla Common - Grade: S355; Profile: PL10*280; Class: 320; Assembly mark: SS-9000(?); Part mark: DSS-5796(?); Name: STÅLSØYLE; Top elevation: +203.940; Bottom elevation: +203.930

# IfcColumn: PL10*80 (7)
In: D
Description: PL10*80; Material: STEEL/S355
Tekla Quantity - Width: 10 mm; Heigth: 80 mm
ePset_SimplebimBasicQuantities - Width (Simplebim): 10 mm; Depth (Simplebim): 80 mm
ePset_Simplebim - Assembly Level: Leaf
ePset_LocationTool - Splitting: ORIGINAL
AVINOR - 07_Fase: F90; 06_Omrade: TS; 01_Lufthavnkode: ENGM
Pset_ColumnCommon - LoadBearing: no
Tekla Common - Grade: S355; Class: 320; Name: STÅLSØYLE; Bottom elevation: +207.080; Profile: PL10*80; Top elevation: +207.160
Name | AREA_NET (m2) | VOLUME_NET (m3) = VOLUME_GROSS (m3) | Length (mm) = Height (Simplebim) (mm) | WEIGTH_GROSS (kg) = WEIGTH_NET (kg) = Weight, as steel (Simplebim) (kg) | AREA_GROSS (m2) | Volume, net (Simplebim) (m3) | Area, sides, net (Simplebim) (m2) | 02_Prosjekt | 04_Kontrakt | 03_Ansvar | 08_Status | Reference = Part mark | Assembly mark | 05_ID-nummer
STÅLSØYLE | 0.034 | 0.00014 | 180 | 1.1304 | 0.0144 | 0.000144 | 0.0304 | T1 | FDV | FDV | S2 | DSS-2132(?) | SS-1805(?)
STÅLSØYLE | 0.0466 | 0.00019 | 250 | 1.57 | 0.02 | 0.0002 | 0.0416 | T1 | FDV | FDV | S2 | DSS-2136(?) | SS-1574(?)
STÅLSØYLE | 0.0484 | 0.00022 | 260 | 1.6328 | 0.0208 | 0.000208 | 0.0432 | T20100 | 72274 | 72101 | S4 | DSS-2135(?) | SS-1787(?) | +TS=222.004
STÅLSØYLE | 0.0484 | 0.00022 | 260 | 1.6328 | 0.0208 | 0.000208 | 0.0432 | T20100 | 72274 | 72101 | S4 | DSS-2135(?) | SS-1435(?) | +TS=222.004
STÅLSØYLE | 0.0484 | 0.00022 | 260 | 1.6328 | 0.0208 | 0.000208 | 0.0432 | T20100 | 72274 | 72101 | S4 | DSS-2135(?) | SS-1791(?) | +TS=222.004
STÅLSØYLE | 0.0484 | 0.00022 | 260 | 1.6328 | 0.0208 | 0.000208 | 0.0432 | T20100 | 72274 | 72101 | S4 | DSS-2135(?) | SS-1562(?) | +TS=222.004
STÅLSØYLE | 0.0169 | 0.00006 | 85 | 0.5338 | 0.0068 | 0.000068 | 0.0152 | T20100 | 72274 | 72101 | S4 | DSS-2703(?) | SS-1434(?) | +TS=222.004

# IfcColumn: PL15*260 (15)
In: D
Description: PL15*260
AVINOR - 07_Fase: F90; 02_Prosjekt: T1; 04_Kontrakt: FDV; 03_Ansvar: FDV; 06_Omrade: TS; 01_Lufthavnkode: ENGM
Tekla Common - Class: 320; Profile: PL15*260; Name: STÅLSØYLE; Bottom elevation: +203.930; Top elevation: +203.945
Pset_ColumnCommon - LoadBearing: no
ePset_SimplebimBasicQuantities - Volume, net (Simplebim): 0.000468 m3; Weight, as steel (Simplebim): 3.6738 kg; Area, sides, net (Simplebim): 0.0114 m2; Width (Simplebim): 15 mm; Depth (Simplebim): 120 mm; Height (Simplebim): 260 mm
ePset_Simplebim - Assembly Level: Leaf
ePset_LocationTool - Splitting: ORIGINAL
Tekla Quantity - VOLUME_GROSS: 0.00047 m3; VOLUME_NET: 0.00047 m3; AREA_NET: 0.0738 m2; AREA_GROSS: 0.0738 m2; WEIGTH_NET: 3.6738 kg; WEIGTH_GROSS: 3.6738 kg; Width: 15 mm; Length: 120 mm; Heigth: 260 mm
Name | Material | 08_Status | Part mark = Reference | Assembly mark | Grade
STÅLSØYLE | STEEL/S355J0 | S4 | DSS-1595(?) | SS-1537(?) | S355J0
STÅLSØYLE | STEEL/S355J0 | S4 | DSS-1595(?) | SS-1672(?) | S355J0
STÅLSØYLE | STEEL/S355 | S2 | DSS-3926(?) | SS-1574(?) | S355
STÅLSØYLE | STEEL/S355 | S2 | DSS-5570(?) | SS-1403(?) | S355
STÅLSØYLE | STEEL/S355J0 | S4 | DSS-1595(?) | SS-1328(?) | S355J0
2 x STÅLSØYLE | STEEL/S355 | S2 | DSS-5570(?) | SS-8096(?) | S355
7 x STÅLSØYLE | STEEL/S355 | S2 | DSS-5570(?) | SS-1398(?) | S355
STÅLSØYLE | STEEL/S355 | S2 | DSS-5570(?) | SS-1546(?) | S355

# IfcColumn: PL20*280 (3)
In: D
Description: PL20*280; Material: STEEL/S355
AVINOR - 08_Status: S4; 07_Fase: F90; 02_Prosjekt: T20100; 05_ID-nummer: +TS=222.012; 04_Kontrakt: 72233; 03_Ansvar: 72101; 06_Omrade: TS; 01_Lufthavnkode: ENGM
ePset_LocationTool - Splitting: ORIGINAL
Tekla Common - Grade: S355; Part mark: DSS-6029(?); Assembly mark: SS-9123(?); Profile: PL20*280; Class: 320; Name: STÅLSØYLE; Top elevation: +203.950; Bottom elevation: +203.930
ePset_Simplebim - Assembly Level: Leaf
Tekla Quantity - VOLUME_GROSS: 0.00157 m3; AREA_NET: 0.1792 m2; AREA_GROSS: 0.1792 m2; VOLUME_NET: 0.00158 m3; Width: 20 mm; Heigth: 280 mm; Length: 280 mm; WEIGTH_GROSS: 12.3088 kg; WEIGTH_NET: 12.3088 kg
Pset_ColumnCommon - Reference: DSS-6029(?); LoadBearing: no
ePset_SimplebimBasicQuantities - Area, sides, net (Simplebim): 0.0224 m2; Volume, net (Simplebim): 0.001568 m3; Width (Simplebim): 20 mm; Height (Simplebim): 280 mm; Depth (Simplebim): 280 mm; Weight, as steel (Simplebim): 12.3088 kg

# IfcColumn: PL20*350 (5)
In: D
Description: PL20*350; Material: STEEL/S355
AVINOR - 08_Status: S4; 07_Fase: F90; 02_Prosjekt: T20100; 03_Ansvar: 72101; 06_Omrade: TS; 01_Lufthavnkode: ENGM
ePset_SimplebimBasicQuantities - Volume, net (Simplebim): 0.00245 m3; Depth (Simplebim): 350 mm; Area, sides, net (Simplebim): 0.028 m2; Width (Simplebim): 20 mm; Height (Simplebim): 350 mm; Weight, as steel (Simplebim): 19.2325 kg
Pset_ColumnCommon - LoadBearing: no
ePset_LocationTool - Splitting: ORIGINAL
ePset_Simplebim - Assembly Level: Leaf
Tekla Common - Grade: S355; Class: 320; Name: STÅLSØYLE; Top elevation: +203.950; Bottom elevation: +203.930; Profile: PL20*350
Tekla Quantity - VOLUME_GROSS: 0.00245 m3; VOLUME_NET: 0.00245 m3; AREA_NET: 0.273 m2; Width: 20 mm; Heigth: 350 mm; Length: 350 mm; WEIGTH_NET: 19.2325 kg; WEIGTH_GROSS: 19.2325 kg
Name | 04_Kontrakt | 05_ID-nummer | Reference = Part mark | Assembly mark | AREA_GROSS (m2)
2 x STÅLSØYLE | 72717 | +TS=221.014 | DSS-6069(?) | SS-7495(?) | 0.273
STÅLSØYLE | 72717 | +TS=221.014 | DSS-6069(?) | SS-7494(?) | 0.273
STÅLSØYLE | 72233 | +TS=222.012 | DSS-6028(?) | SS-9122(?) | 0.1225
STÅLSØYLE | 72717 | +TS=221.014 | DSS-6069(?) | SS-7496(?) | 0.273

# IfcColumn: PL20*400, STÅLSØYLE
In: D
Description: PL20*400; Material: STEEL/S355
ePset_SimplebimBasicQuantities - Height (Simplebim): 500 mm; Volume, net (Simplebim): 0.004 m3; Weight, as steel (Simplebim): 31.4 kg; Area, sides, net (Simplebim): 0.036 m2; Width (Simplebim): 20 mm; Depth (Simplebim): 400 mm
AVINOR - 08_Status: S4; 07_Fase: F90; 02_Prosjekt: T20100; 05_ID-nummer: +TS=222.012; 04_Kontrakt: 72233; 03_Ansvar: 72101; 06_Omrade: TS; 01_Lufthavnkode: ENGM
Tekla Common - Grade: S355; Class: 320; Profile: PL20*400; Part mark: DSS-57(?); Assembly mark: SB-7502(?); Name: STÅLSØYLE; Top elevation: +203.950; Bottom elevation: +203.930
Tekla Quantity - AREA_NET: 0.436 m2; AREA_GROSS: 0.436 m2; VOLUME_NET: 0.004 m3; VOLUME_GROSS: 0.004 m3; WEIGTH_NET: 31.4 kg; WEIGTH_GROSS: 31.4 kg; Width: 20 mm; Heigth: 400 mm; Length: 500 mm
ePset_Simplebim - Assembly Level: Leaf
Pset_ColumnCommon - Reference: DSS-57(?); LoadBearing: no
ePset_LocationTool - Splitting: ORIGINAL

# IfcColumn: PL8*100, STÅLSØYLE
In: D
Description: PL8*100; Material: STEEL/S355
AVINOR - 08_Status: S4; 07_Fase: F90; 02_Prosjekt: T20100; 05_ID-nummer: +TS=222.012; 04_Kontrakt: 72233; 03_Ansvar: 72101; 06_Omrade: TS; 01_Lufthavnkode: ENGM
Tekla Common - Grade: S355; Part mark: DSS-6538(?); Class: 320; Bottom elevation: +207.322; Assembly mark: SB-7502(?); Name: STÅLSØYLE; Profile: PL8*100; Top elevation: +207.330
Pset_ColumnCommon - Reference: DSS-6538(?); LoadBearing: no
ePset_Simplebim - Assembly Level: Leaf
ePset_SimplebimBasicQuantities - Height (Simplebim): 200 mm; Depth (Simplebim): 100 mm; Width (Simplebim): 8 mm; Volume, net (Simplebim): 0.00016 m3; Weight, as steel (Simplebim): 1.256 kg; Area, sides, net (Simplebim): 0.0048 m2
Tekla Quantity - AREA_NET: 0.0448 m2; AREA_GROSS: 0.0448 m2; VOLUME_NET: 0.00016 m3; VOLUME_GROSS: 0.00016 m3; Width: 8 mm; Heigth: 100 mm; WEIGTH_GROSS: 1.256 kg; WEIGTH_NET: 1.256 kg; Length: 200 mm
ePset_LocationTool - Splitting: ORIGINAL

# IfcColumn: RHS100*5 (3)
In: D
Description: RHS100*5; Material: STEEL/S355
AVINOR - 07_Fase: F90; 02_Prosjekt: T1; 04_Kontrakt: FDV; 03_Ansvar: FDV; 06_Omrade: TS; 01_Lufthavnkode: ENGM
Tekla Common - Grade: S355; Profile: RHS100*5; Class: 320; Name: STÅLSØYLE; Part mark: DSS-1666(?); Bottom elevation: +203.945
ePset_Simplebim - Assembly Level: Leaf
Pset_ColumnCommon - LoadBearing: no; Reference: DSS-1666(?)
ePset_LocationTool - Splitting: ORIGINAL
ePset_SimplebimBasicQuantities - Width (Simplebim): 100 mm; Depth (Simplebim): 100 mm
Tekla Quantity - VOLUME_NET: 0.00536 m3; Heigth: 100 mm; Width: 100 mm; VOLUME_GROSS: 0.00531 m3
Name | 08_Status | Top elevation | Assembly mark | Area, sides, net (Simplebim) (m2) | Volume, net (Simplebim) (m3) | Height (Simplebim) (mm) = Length (mm) | Weight, as steel (Simplebim) (kg) = WEIGTH_NET (kg) | AREA_NET (m2) | AREA_GROSS (m2) | WEIGTH_GROSS (kg)
STÅLSØYLE | S4 | +206.760 | SS-1328(?) | 2.1394 | 0.0053485 | 2815 | 41.9857 | 1.128 | 1.09503 | 41.7647
STÅLSØYLE | S2 | +206.761 | SS-8096(?) | 2.13989 | 0.00534972 | 2815.64 | 41.9953 | 1.12826 | 1.09529 | 41.7743
STÅLSØYLE | S2 | +206.760 | SS-8096(?) | 2.1394 | 0.0053485 | 2815 | 41.9857 | 1.128 | 1.09503 | 41.7647

# IfcColumn: RHS100*6.3, STÅLSØYLE
In: D
Description: RHS100*6.3; Material: STEEL/S355
AVINOR - 08_Status: S4; 07_Fase: F90; 02_Prosjekt: T20100; 05_ID-nummer: +TS=222.012; 04_Kontrakt: 72233; 03_Ansvar: 72101; 06_Omrade: TS; 01_Lufthavnkode: ENGM
ePset_LocationTool - Splitting: ORIGINAL
Tekla Common - Grade: S355; Top elevation: +206.950; Assembly mark: SS-9122(?); Class: 320; Name: STÅLSØYLE; Part mark: DSS-6439(?); Bottom elevation: +203.950; Profile: RHS100*6.3
Pset_ColumnCommon - LoadBearing: no; Reference: DSS-6439(?)
Tekla Quantity - AREA_NET: 1.20252 m2; WEIGTH_NET: 55.6074 kg; VOLUME_GROSS: 0.00702 m3; VOLUME_NET: 0.00708 m3; AREA_GROSS: 1.158 m2; Heigth: 100 mm; Width: 100 mm; WEIGTH_GROSS: 55.1072 kg; Length: 3000.01 mm
ePset_Simplebim - Assembly Level: Leaf
ePset_SimplebimBasicQuantities - Area, sides, net (Simplebim): 2.24881 m2; Weight, as steel (Simplebim): 55.6074 kg; Volume, net (Simplebim): 0.00708374 m3; Width (Simplebim): 100 mm; Depth (Simplebim): 100 mm; Height (Simplebim): 3000.01 mm

# IfcColumn: RHS200*100*5, STÅLSØYLE
In: D
Description: RHS200*100*5; Material: STEEL/S355
AVINOR - 08_Status: S4; 07_Fase: F90; 02_Prosjekt: T20100; 05_ID-nummer: +TS=222.012; 04_Kontrakt: 72233; 03_Ansvar: 72101; 06_Omrade: TS; 01_Lufthavnkode: ENGM
Pset_ColumnCommon - LoadBearing: no; Reference: DSS-5303(?)
Tekla Quantity - WEIGTH_GROSS: 76.4989 kg; VOLUME_GROSS: 0.00975 m3; AREA_NET: 2.00888 m2; WEIGTH_NET: 76.7636 kg; Width: 100 mm; Heigth: 200 mm; Length: 3372 mm; VOLUME_NET: 0.00978 m3; AREA_GROSS: 1.98611 m2
ePset_Simplebim - Assembly Level: Leaf
Tekla Common - Grade: S355; Class: 320; Top elevation: +207.322; Profile: RHS200*100*5; Assembly mark: SB-7502(?); Name: STÅLSØYLE; Bottom elevation: +203.950; Part mark: DSS-5303(?)
ePset_LocationTool - Splitting: ORIGINAL
ePset_SimplebimBasicQuantities - Area, sides, net (Simplebim): 3.91152 m2; Height (Simplebim): 3372 mm; Depth (Simplebim): 200 mm; Weight, as steel (Simplebim): 76.7636 kg; Width (Simplebim): 100 mm; Volume, net (Simplebim): 0.0097788 m3

# IfcColumn: RHS200*100*6.3 (4)
In: D
Description: RHS200*100*6.3; Material: STEEL/S355
Tekla Common - Grade: S355; Top elevation: +206.990; Class: 320; Name: STÅLSØYLE; Part mark: DSS-6449(?); Bottom elevation: +206.515; Profile: RHS200*100*6.3
AVINOR - 08_Status: S4; 07_Fase: F90; 04_Kontrakt: 72717; 02_Prosjekt: T20100; 05_ID-nummer: +TS=221.014; 03_Ansvar: 72101; 06_Omrade: TS; 01_Lufthavnkode: ENGM
ePset_SimplebimBasicQuantities - Weight, as steel (Simplebim): 13.5027 kg; Volume, net (Simplebim): 0.00172009 m3; Area, sides, net (Simplebim): 0.54606 m2; Width (Simplebim): 100 mm; Depth (Simplebim): 200 mm; Height (Simplebim): 475 mm
ePset_Simplebim - Assembly Level: Leaf
Tekla Quantity - WEIGTH_NET: 13.5027 kg; AREA_GROSS: 0.27835 m2; VOLUME_GROSS: 0.00171 m3; WEIGTH_GROSS: 13.4235 kg; AREA_NET: 0.28565 m2; VOLUME_NET: 0.00172 m3; Width: 100 mm; Heigth: 200 mm; Length: 475 mm
ePset_LocationTool - Splitting: ORIGINAL
Pset_ColumnCommon - LoadBearing: no; Reference: DSS-6449(?)
Name | Assembly mark
STÅLSØYLE | SS-7494(?)
STÅLSØYLE | SS-7496(?)
2 x STÅLSØYLE | SS-7495(?)

# IfcColumn: RHS50*4, STÅLSØYLE
In: D
Description: RHS50*4; Material: STEEL/S355
AVINOR - 08_Status: S4; 07_Fase: F90; 02_Prosjekt: T20100; 05_ID-nummer: +TS=222.012; 04_Kontrakt: 72233; 03_Ansvar: 72101; 06_Omrade: TS; 01_Lufthavnkode: ENGM
Tekla Quantity - VOLUME_NET: 0.00211 m3; WEIGTH_GROSS: 16.4186 kg; WEIGTH_NET: 16.599 kg; VOLUME_GROSS: 0.00209 m3; AREA_GROSS: 0.54874 m2; Heigth: 50 mm; Width: 50 mm; Length: 2873 mm; AREA_NET: 0.5754 m2
ePset_Simplebim - Assembly Level: Leaf
ePset_LocationTool - Splitting: ORIGINAL
Tekla Common - Profile: RHS50*4; Grade: S355; Part mark: DSS-7852(?); Top elevation: +206.823; Class: 320; Assembly mark: SB-7502(?); Name: STÅLSØYLE; Bottom elevation: +203.950
ePset_SimplebimBasicQuantities - Area, sides, net (Simplebim): 1.05726 m2; Volume, net (Simplebim): 0.00211453 m3; Height (Simplebim): 2873 mm; Weight, as steel (Simplebim): 16.599 kg; Depth (Simplebim): 50 mm; Width (Simplebim): 50 mm
Pset_ColumnCommon - Reference: DSS-7852(?); LoadBearing: no

# IfcColumn: RHS70*5, STÅLSØYLE
In: D
Description: RHS70*5; Material: STEEL/S355
ePset_LocationTool - Splitting: ORIGINAL
ePset_Simplebim - Assembly Level: Leaf
AVINOR - 07_Fase: F90; 02_Prosjekt: T1; 04_Kontrakt: FDV; 03_Ansvar: FDV; 08_Status: S2; 06_Omrade: TS; 01_Lufthavnkode: ENGM
Tekla Quantity - WEIGTH_GROSS: 28.5061 kg; WEIGTH_NET: 28.7271 kg; VOLUME_NET: 0.00367 m3; AREA_NET: 0.7896 m2; Heigth: 70 mm; Width: 70 mm; Length: 2815 mm; VOLUME_GROSS: 0.00363 m3; AREA_GROSS: 0.75723 m2
Pset_ColumnCommon - LoadBearing: no; Reference: DSS-1720(?)
ePset_SimplebimBasicQuantities - Area, sides, net (Simplebim): 1.4638 m2; Weight, as steel (Simplebim): 28.7271 kg; Volume, net (Simplebim): 0.0036595 m3; Width (Simplebim): 70 mm; Depth (Simplebim): 70 mm; Height (Simplebim): 2815 mm
Tekla Common - Grade: S355; Top elevation: +206.760; Class: 320; Name: STÅLSØYLE; Profile: RHS70*5; Assembly mark: SS-1403(?); Bottom elevation: +203.945; Part mark: DSS-1720(?)

# IfcColumn: RHS80*5 (9)
In: D
Description: RHS80*5; Material: STEEL/S355
ePset_LocationTool - Splitting: ORIGINAL
Tekla Common - Grade: S355; Profile: RHS80*5; Class: 320; Name: STÅLSØYLE; Bottom elevation: +203.945
Pset_ColumnCommon - LoadBearing: no
Tekla Quantity - Heigth: 80 mm; Width: 80 mm
ePset_Simplebim - Assembly Level: Leaf
ePset_SimplebimBasicQuantities - Width (Simplebim): 80 mm; Depth (Simplebim): 80 mm
AVINOR - 07_Fase: F90; 02_Prosjekt: T1; 04_Kontrakt: FDV; 03_Ansvar: FDV; 08_Status: S2; 06_Omrade: TS; 01_Lufthavnkode: ENGM
Name | Part mark = Reference | Top elevation | Assembly mark | Length (mm) = Height (Simplebim) (mm) | AREA_GROSS (m2) | WEIGTH_GROSS (kg) | VOLUME_GROSS (m3) | AREA_NET (m2) | VOLUME_NET (m3) | WEIGTH_NET (kg) = Weight, as steel (Simplebim) (kg) | Area, sides, net (Simplebim) (m2) | Volume, net (Simplebim) (m3)
STÅLSØYLE | DSS-1936(?) | +210.535 | SS-1574(?) | 6590 | 2.03631 | 77.0799 | 0.00981 | 2.1104 | 0.00989 | 77.5972 | 3.954 | 0.009885
7 x STÅLSØYLE | DSS-1713(?) | +206.797 | SS-1398(?) | 2852 | 0.88127 | 33.3584 | 0.00424 | 0.91424 | 0.00428 | 33.5823 | 1.7112 | 0.004278
STÅLSØYLE | DSS-2084(?) | +206.790 | SS-1546(?) | 2845 | 0.8791 | 33.2765 | 0.00424 | 0.912 | 0.00426 | 33.4999 | 1.707 | 0.0042675

# IfcColumn: RHS80*6 (4)
In: D
Description: RHS80*6; Material: STEEL/S355
AVINOR - 08_Status: S4; 07_Fase: F90; 02_Prosjekt: T20100; 03_Ansvar: 72101; 06_Omrade: TS; 01_Lufthavnkode: ENGM
ePset_LocationTool - Splitting: ORIGINAL
ePset_Simplebim - Assembly Level: Leaf
Tekla Quantity - Heigth: 80 mm; Width: 80 mm
Pset_ColumnCommon - LoadBearing: no
ePset_SimplebimBasicQuantities - Width (Simplebim): 80 mm; Depth (Simplebim): 80 mm
Tekla Common - Grade: S355; Profile: RHS80*6; Class: 320; Name: STÅLSØYLE
Name | 05_ID-nummer | 04_Kontrakt | WEIGTH_GROSS (kg) = WEIGTH_NET (kg) | VOLUME_GROSS (m3) = VOLUME_NET (m3) | Length (mm) = Height (Simplebim) (mm) | AREA_NET (m2) = AREA_GROSS (m2) | Reference = Part mark | Weight, as steel (Simplebim) (kg) | Area, sides, net (Simplebim) (m2) | Volume, net (Simplebim) (m3) | Top elevation | Assembly mark | Bottom elevation
3 x STÅLSØYLE | +TS=222.012 | 72233 | 39.5941 | 0.00504 | 2840 | 0.91072 | DSS-8011(?) | 39.5941 | 1.68128 | 0.00504384 | +206.790 | SS-9123(?) | +203.950
STÅLSØYLE | +TS=221.014 | 72717 | 40.3331 | 0.00514 | 2893 | 0.92768 | DSS-8010(?) | 40.333 | 1.71266 | 0.00513797 | +206.833 | SS-9000(?) | +203.940

# IfcColumn: RHS80*6.3 (2)
In: D
Description: RHS80*6.3; Material: STEEL/S355
AVINOR - 08_Status: S4; 07_Fase: F90; 02_Prosjekt: T1; 04_Kontrakt: FDV; 03_Ansvar: FDV; 06_Omrade: TS; 01_Lufthavnkode: ENGM
ePset_LocationTool - Splitting: ORIGINAL
Tekla Quantity - Heigth: 80 mm; Width: 80 mm
ePset_Simplebim - Assembly Level: Leaf
Tekla Common - Grade: S355; Profile: RHS80*6.3; Class: 320; Name: STÅLSØYLE; Bottom elevation: +203.945
Pset_ColumnCommon - LoadBearing: no
ePset_SimplebimBasicQuantities - Width (Simplebim): 80 mm; Depth (Simplebim): 80 mm
Name | VOLUME_NET (m3) | AREA_GROSS (m2) | WEIGTH_GROSS (kg) | AREA_NET (m2) | VOLUME_GROSS (m3) | Length (mm) = Height (Simplebim) (mm) | WEIGTH_NET (kg) = Weight, as steel (Simplebim) (kg) | Assembly mark | Part mark = Reference | Top elevation | Volume, net (Simplebim) (m3) | Area, sides, net (Simplebim) (m2)
STÅLSØYLE | 0.00552 | 0.90882 | 42.8987 | 0.95242 | 0.00545 | 2970 | 43.3006 | SS-1537(?) | DSS-1924(?) | +206.915 | 0.005516 | 1.75111
STÅLSØYLE | 0.00584 | 0.96543 | 45.5709 | 1.0099 | 0.00581 | 3155 | 45.84 | SS-1672(?) | DSS-1922(?) | +207.100 | 0.00583949 | 1.85668

# IfcColumn: RØR114.3X5.0, STÅLSØYLE
In: D
Description: RØR114.3X5.0; Material: STEEL/S355
ePset_LocationTool - Splitting: ORIGINAL
AVINOR - 08_Status: S4; 07_Fase: F90; 04_Kontrakt: 72717; 02_Prosjekt: T20100; 05_ID-nummer: +TS=221.014; 03_Ansvar: 72101; 06_Omrade: TS; 01_Lufthavnkode: ENGM
ePset_Simplebim - Assembly Level: Leaf
Tekla Common - Grade: S355; Profile: RØR114.3X5.0; Class: 320; Name: STÅLSØYLE; Bottom elevation: +203.950; Part mark: DSS-8162(?); Assembly mark: SS-7494(?); Top elevation: +206.505
Pset_ColumnCommon - LoadBearing: no; Reference: DSS-8162(?)
Tekla Quantity - AREA_GROSS: 0.91725 m2; AREA_NET: 0.91546 m2; WEIGTH_GROSS: 35.5005 kg; VOLUME_NET: 0.00432 m3; Length: 2555 mm; WEIGTH_NET: 33.8714 kg; Heigth: 114.3 mm; Width: 114.3 mm; VOLUME_GROSS: 0.00452 m3
ePset_SimplebimBasicQuantities - Volume, net (Simplebim): 0.00431483 m3; Weight, as steel (Simplebim): 33.8714 kg; Area, sides, net (Simplebim): 1.74744 m2; Height (Simplebim): 2555 mm; Depth (Simplebim): 114.3 mm; Width (Simplebim): 114.3 mm

# IfcColumn: RØR114.3X6.0 (3)
In: D
Description: RØR114.3X6.0; Material: STEEL/S355
AVINOR - 08_Status: S4; 07_Fase: F90; 04_Kontrakt: 72717; 02_Prosjekt: T20100; 05_ID-nummer: +TS=221.014; 03_Ansvar: 72101; 06_Omrade: TS; 01_Lufthavnkode: ENGM
Tekla Common - Grade: S355; Class: 320; Part mark: DSS-8229(?); Name: STÅLSØYLE; Profile: RØR114.3X6.0; Bottom elevation: +203.950; Top elevation: +206.505
Pset_ColumnCommon - Reference: DSS-8229(?); LoadBearing: no
Tekla Quantity - VOLUME_GROSS: 0.00521 m3; AREA_GROSS: 0.91725 m2; WEIGTH_NET: 40.2738 kg; VOLUME_NET: 0.00512 m3; AREA_NET: 0.91581 m2; WEIGTH_GROSS: 40.9358 kg; Length: 2555 mm; Heigth: 114.3 mm; Width: 114.3 mm
ePset_Simplebim - Assembly Level: Leaf
ePset_SimplebimBasicQuantities - Area, sides, net (Simplebim): 1.73146 m2; Weight, as steel (Simplebim): 40.2738 kg; Volume, net (Simplebim): 0.00513042 m3; Height (Simplebim): 2555 mm; Depth (Simplebim): 114.3 mm; Width (Simplebim): 114.3 mm
ePset_LocationTool - Splitting: ORIGINAL
Name | Assembly mark
2 x STÅLSØYLE | SS-7495(?)
STÅLSØYLE | SS-7496(?)

# IfcCovering (18)
In: Nivå D
Description: EI60 Brannisolasjon 30 mm; PredefinedType: INSULATION
ePset_Simplebim - Assembly Level: Leaf
ePset_LocationTool - Splitting: ORIGINAL
Name | Area, largest surface, net (Simplebim) (m2) | Length (Simplebim) (mm) | Height (Simplebim) (mm) | Width (Simplebim) (mm) | Volume, net (Simplebim) (m3)
EI60-30 | 0.183541 | 188.7 | 310 | 310 | 0.00495443
EI60-30 | 1.58563 | 1630.2 | 310 | 310 | 0.0428019
8 x EI60-30 | 0.228128 | 310 | 305 | 305 | 0.017491
EI60-30 | 0.531558 | 546.5 | 310 | 310 | 0.0143487
EI60-30 | 1.57571 | 1620 | 310 | 310 | 0.0425341
EI60-30 | 3.94899 | 4060 | 310 | 310 | 0.106598
EI60-30 | 0.351519 | 361.4 | 310 | 310 | 0.00948878
2 x EI60-30 | 0.0525235 | 310 | 54 | 310 | 0.0014178
EI60-30 | 0.342765 | 352.4 | 310 | 310 | 0.00925248
EI60-30 | 4.93157 | 5070.2 | 310 | 310 | 0.133121

# IfcCovering: Compound Ceiling:A255 - Brannskille 30 mm brannisol (3)
In: Nivå D
Type - PredefinedType: CEILING
Type - Pset_CoveringCommon - TotalThickness: 30 mm
Material: Isolasjon 30 mm
Identity Data - CQFireRequirement: EI 30
Pset_CoveringCommon - Reference: A255 - Brannskille 30 mm brannisol; Finish: Isolasjon;
ePset_Simplebim - Assembly Level: Leaf
AVINOR - 08_Status: S4; 07_Fase: F90; 03_Ansvar: 72717; 05_ID-nummer: +TS=255.001-ID0038; 02_Prosjekt: 72101; 06_Omrade: TS; 01_Lufthavnkode: ENGM
ePset_SimplebimBasicQuantities - Height (Simplebim): 30 mm
ePset_LocationTool - Splitting: ORIGINAL
Pset_QuantityTakeOff - Reference: A255 - Brannskille 30 mm brannisol
Name (Compound Ceiling:A255 - Brannskille 30 mm brannisol:...) | Volume, net (Simplebim) (m3) | Area, largest surface, net (Simplebim) (m2) | Width (Simplebim) (mm) | Length (Simplebim) (mm)
42246400 | 0.669547 | 22.3182 | 4345 | 6137.69
42246422 | 0.125243 | 4.17475 | 1320 | 3162.69
42246488 | 0.245565 | 8.18549 | 2842.5 | 3890.5

# IfcCovering: Compound Ceiling:A255 - Brannskille NY - 2x25 mm brannisol., Compound Ceiling:A255 - Brannskille NY - 2x25 mm brannisol.:26329303
In: Nivå D
Type - PredefinedType: CEILING
Type - Pset_CoveringCommon - TotalThickness: 50 mm
ePset_LocationTool - Splitting: RESULT
Pset_QuantityTakeOff - Reference: A255 - Brannskille NY - 2x25 mm brannisol.
AVINOR - 07_Fase: F90; 03_Ansvar: FDV; 08_Status: S2; 06_Omrade: TS; 01_Lufthavnkode: ENGM
ePset_SimplebimBasicQuantities - Area, largest surface, net (Simplebim): 3.35187 m2; Volume, net (Simplebim): 0.167593 m3; Height (Simplebim): 50 mm; Width (Simplebim): 1050 mm; Length (Simplebim): 3538 mm
ePset_Simplebim - Assembly Level: Leaf
Pset_CoveringCommon - Reference: A255 - Brannskille NY - 2x25 mm brannisol.; Finish: Isolasjon;

# IfcCovering: Compound Ceiling:A255 - Brannskille NY - 3lag gips, Compound Ceiling:A255 - Brannskille NY - 3lag gips:24452354
In: Nivå D
Type - PredefinedType: CEILING
Type - Pset_CoveringCommon - TotalThickness: 37.5 mm
ePset_LocationTool - Splitting: RESULT
Pset_CoveringCommon - Reference: A255 - Brannskille NY - 3lag gips; sets with these values: 2
AVINOR - 07_Fase: F90; 03_Ansvar: FDV; 08_Status: S2; 04_Kontrakt: 72274; 06_Omrade: TS; 01_Lufthavnkode: ENGM
ePset_Simplebim - Assembly Level: Leaf
ePset_SimplebimBasicQuantities - Volume, net (Simplebim): 0.246983 m3; Height (Simplebim): 37 mm; Width (Simplebim): 1877 mm; Length (Simplebim): 3508 mm; Area, largest surface, net (Simplebim): 6.58627 m2

# IfcCovering: Compound Ceiling:A255 - Brannskille NY - 50 mm brannisol. + TRP 70 mm + 3lag gips (2)
In: Nivå D
Type - PredefinedType: CEILING
Type - Pset_CoveringCommon - TotalThickness: 157.5 mm
AVINOR - 07_Fase: F90; 03_Ansvar: FDV; 08_Status: S2; 04_Kontrakt: 72274; 06_Omrade: TS; 01_Lufthavnkode: ENGM
Pset_CoveringCommon - Reference: A255 - Brannskille NY - 50 mm brannisol. + TRP 70 mm + 3lag gips; Finish: Isolasjon;
ePset_Simplebim - Assembly Level: Leaf
Pset_QuantityTakeOff - Reference: A255 - Brannskille NY - 50 mm brannisol. + TRP 70 mm + 3lag gips
Name (Compound Ceiling:A255 - Brannskille NY - 50 mm brannisol. + TRP 70 mm + 3lag gips:...) | Splitting | Height (Simplebim) (mm) | Length (Simplebim) (mm) | Volume, net (Simplebim) (m3) | Area, largest surface, net (Simplebim) (m2) | Width (Simplebim) (mm)
64174651 | ORIGINAL | 157.5 | 3268.05 | 0.555897 | 3.52951 | 1080 | Material: NO_Gipsplate 12.5 mm, NO_Gipsplate 12.5 mm, NO_Gipsplate 12.5 mm, _NSW Stålstender, uisolert 70 mm, Isolasjon 25 mm, Isolasjon 25 mm
24437746 | RESULT | 158 | 12135 | 11.6196 | 73.7754 | 6411

# IfcCovering: Compound Ceiling:A255 - Eksisterende - TRP 70 mm, Compound Ceiling:A255 - Eksisterende - TRP 70 mm:24450971
In: Nivå D
Type - PredefinedType: CEILING
Type - Pset_CoveringCommon - TotalThickness: 70 mm
AVINOR - 07_Fase: F90; 03_Ansvar: FDV; 08_Status: S2; 06_Omrade: TS; 01_Lufthavnkode: ENGM
ePset_Simplebim - Assembly Level: Leaf
ePset_SimplebimBasicQuantities - Volume, net (Simplebim): 2.50508 m3; Area, largest surface, net (Simplebim): 35.7869 m2; Height (Simplebim): 70 mm; Width (Simplebim): 3001 mm; Length (Simplebim): 11925 mm
ePset_LocationTool - Splitting: RESULT
Pset_CoveringCommon - Reference: A255 - Eksisterende - TRP 70 mm; sets with these values: 2

# IfcCovering: Compound Ceiling:A255 - Eksisterende - X-finer 20 mm + TRP 70 mm (2)
In: Nivå D
Type - PredefinedType: CEILING
Type - Pset_CoveringCommon - TotalThickness: 90 mm
Material: _NSW X-finer 20 mm, _NSW Stålstender, uisolert 70 mm
AVINOR - 07_Fase: F90; 06_Omrade: TS; 01_Lufthavnkode: ENGM
Identity Data - CQFireRequirement: EI 30
ePset_LocationTool - Splitting: ORIGINAL
ePset_SimplebimBasicQuantities - Height (Simplebim): 90 mm; Length (Simplebim): 5922.5 mm
ePset_Simplebim - Assembly Level: Leaf
Pset_CoveringCommon - Reference: A255 - Eksisterende - X-finer 20 mm + TRP 70 mm; Finish: _NSW X-finer;
Pset_QuantityTakeOff - Reference: A255 - Eksisterende - X-finer 20 mm + TRP 70 mm
Name (Compound Ceiling:A255 - Eksisterende - X-finer 20 mm + TRP 70 mm:...) | 08_Status | 03_Ansvar | Volume, net (Simplebim) (m3) | Area, largest surface, net (Simplebim) (m2) | Width (Simplebim) (mm)
42142563 | S1 | FDV | 1.59961 | 17.7734 | 3001
42245763 | S4 | 72717 | 1.69246 | 18.805 | 3175.19 | AVINOR - 05_ID-nummer: +TS=254.041; 02_Prosjekt: 72101

# IfcCovering: Compound Ceiling:A255 - HI-F01, Compound Ceiling:A255 - HI-F01:39238198
In: Nivå D
Type - PredefinedType: CEILING
Type - Pset_CoveringCommon - TotalThickness: 30 mm
Material: T2 Himlingsplate 600x600 mm 30 mm
AVINOR - 08_Status: S4; 07_Fase: F90; 05_ID-nummer: +TS=255.001-ID0053; 03_Ansvar: 72717; 02_Prosjekt: 72101; 06_Omrade: TS; 01_Lufthavnkode: ENGM
ePset_LocationTool - Splitting: ORIGINAL
ePset_SimplebimBasicQuantities - Width (Simplebim): 11300 mm; Height (Simplebim): 30 mm; Area, largest surface, net (Simplebim): 68.8828 m2; Length (Simplebim): 14624.1 mm; Volume, net (Simplebim): 2.06649 m3
ePset_Simplebim - Assembly Level: Leaf
Pset_CoveringCommon - Reference: A255 - HI-F01; sets with these values: 2

# IfcCovering: Compound Ceiling:A255 - HI-F02 (5)
In: Nivå D
Type - PredefinedType: CEILING
Type - Pset_CoveringCommon - TotalThickness: 30 mm
Material: _NSW Himlingsplate 600x600 mm 30 mm
ePset_LocationTool - Splitting: ORIGINAL
AVINOR - 01_Lufthavnkode: ENGM
ePset_Simplebim - Assembly Level: Leaf
ePset_SimplebimBasicQuantities - Height (Simplebim): 30 mm
Pset_QuantityTakeOff - Reference: A255 - HI-F02; sets with these values: 2
Name (Compound Ceiling:A255 - HI-F02:...) | 08_Status | 07_Fase | 03_Ansvar | 06_Omrade | Volume, net (Simplebim) (m3) | Area, largest surface, net (Simplebim) (m2) | Width (Simplebim) (mm) | Length (Simplebim) (mm)
39951338 | S4 | F90 | 72717 | TS | 0.127852 | 4.26172 | 1347.5 | 3162.69 | AVINOR - 05_ID-nummer: +TS=255.001-ID0039; 02_Prosjekt: 72101
39970805 | S4 | F90 | 72717 | TS | 0.468414 | 15.6138 | 4182.5 | 6137.69 | AVINOR - 05_ID-nummer: +TS=255.001-ID0039; 02_Prosjekt: 72101
66617853 | S1 | F30 | 188111 | TH | 0.0504899 | 1.683 | 1568.57 | 2022.07
66665116 | S1 | F30 | 188111 | TH | 0.032715 | 1.0905 | 1772.5 | 1800
66665784 | S1 | F30 | 188111 | TH | 0.09 | 3 | 1500 | 2000

# IfcCovering: Compound Ceiling:A255 - HI-G01, Compound Ceiling:A255 - HI-G01:40054097
In: Nivå D
Type - PredefinedType: CEILING
Type - Pset_CoveringCommon - TotalThickness: 15 mm
Pset_CoveringCommon - Reference: A255 - HI-G01; sets with these values: 2
ePset_Simplebim - Assembly Level: Leaf
ePset_LocationTool - Splitting: RESULT
AVINOR - 08_Status: S4; 07_Fase: F90; 05_ID-nummer: +TS=255.001-ID0054; 03_Ansvar: 72717; 02_Prosjekt: 72101; 06_Omrade: TS; 01_Lufthavnkode: ENGM
ePset_SimplebimBasicQuantities - Area, largest surface, net (Simplebim): 5.12139 m2; Volume, net (Simplebim): 0.0768192 m3; Height (Simplebim): 15 mm; Length (Simplebim): 15773 mm; Width (Simplebim): 12130 mm

# IfcCovering: Compound Ceiling:A255 - Mineralull 600x600mm (2)
In: Nivå D
Type - PredefinedType: CEILING
Type - Pset_CoveringCommon - TotalThickness: 30 mm
ePset_SimplebimBasicQuantities - Height (Simplebim): 30 mm
AVINOR - 07_Fase: F90; 08_Status: S1; 03_Ansvar: FDV; 06_Omrade: TS; 01_Lufthavnkode: ENGM
ePset_Simplebim - Assembly Level: Leaf
Pset_CoveringCommon - Reference: A255 - Mineralull 600x600mm; sets with these values: 2
Name (Compound Ceiling:A255 - Mineralull 600x600mm:...) | Length (Simplebim) (mm) | Volume, net (Simplebim) (m3) | Area, largest surface, net (Simplebim) (m2) | Width (Simplebim) (mm) | Splitting
65072587 | 3268.05 | 0.108874 | 3.62918 | 1110.49 | ORIGINAL | Material: _NSW Himlingsplate 600x600 mm 30 mm
39270837 | 3300 | 0.0499134 | 1.48412 | 1537.49 | RESULT

# IfcCovering: Compound Ceiling:A255 - avtrekkshetta 770, Compound Ceiling:A255 - avtrekkshetta 770:41911783
In: Nivå D
Type - PredefinedType: CEILING
Type - Pset_CoveringCommon - TotalThickness: 770 mm
Material: _NSW Generell 770 mm
ePset_SimplebimBasicQuantities - Area, largest surface, net (Simplebim): 2.1 m2; Height (Simplebim): 770 mm; Width (Simplebim): 1400 mm; Length (Simplebim): 1500 mm; Volume, net (Simplebim): 1.617 m3
ePset_Simplebim - Assembly Level: Leaf
ePset_LocationTool - Splitting: ORIGINAL
AVINOR - 08_Status: S1; 07_Fase: F50; 03_Ansvar: AV1; 02_Prosjekt: 72101; 06_Omrade: TS; 01_Lufthavnkode: ENGM
Pset_CoveringCommon - Reference: A255 - avtrekkshetta 770; sets with these values: 2

# IfcCovering: Compound Ceiling:A255 - avtrekkshetta 800 (2)
In: Nivå D
Type - PredefinedType: CEILING
Type - Pset_CoveringCommon - TotalThickness: 800 mm
Material: _NSW Generell 800 mm
ePset_LocationTool - Splitting: ORIGINAL
ePset_Simplebim - Assembly Level: Leaf
ePset_SimplebimBasicQuantities - Height (Simplebim): 800 mm; Width (Simplebim): 1200 mm
AVINOR - 08_Status: S1; 01_Lufthavnkode: ENGM
Pset_CoveringCommon - Reference: A255 - avtrekkshetta 800; sets with these values: 2
Name (Compound Ceiling:A255 - avtrekkshetta 800:...) | Volume, net (Simplebim) (m3) | Length (Simplebim) (mm) | Area, largest surface, net (Simplebim) (m2) | 07_Fase | 03_Ansvar | 06_Omrade
41852911 | 1.152 | 1200 | 1.44 | F50 | AV1 | TS | AVINOR - 02_Prosjekt: 72101
66665777 | 1.92 | 2000 | 2.4 | F30 | 188111 | TH

# IfcCurtainWall: Curtain Wall:A245 - IGK - Glass Kledning (5)
In: Nivå D
Pset_CurtainWallCommon - Reference: A245 - IGK - Glass Kledning; IsExternal: no
Pset_QuantityTakeOff - Reference: A245 - IGK - Glass Kledning
ePset_Simplebim - Assembly Level: Topmost
AVINOR - 08_Status: S4; 07_Fase: F90; 05_ID-nummer: +TS=245.106; 03_Ansvar: 72717; 02_Prosjekt: 72101; 06_Omrade: TS; 01_Lufthavnkode: ENGM
ePset_SimplebimBasicQuantities - Height: 3320 mm
Name (Curtain Wall:A245 - IGK - Glass Kledning:...) | Volume, net (Simplebim) (m3) | Width (mm) | Length (mm)
39320016 | 0.249748 | 20 | 7500
39550657 | 0.0249 | 298.969 | 695.635
39550694 | 0.0249 | 310.198 | 690.946
39550698 | 0.0249 | 319.836 | 686.744
39550961 | 0.0249 | 330.996 | 681.669

# IfcDistributionControlElement: Addressable Luminaire (5)
In: Nivå D
Type - Description: Brannspjeld
Classification: XN1.31 Not defined (NS3420); Group: Brannalarm
MagiCAD Pset_Device - System code: 542; P1: -DI; User code: -DI; Length [mm]: 0 mm; Product code: Addressable Luminaire; Manufacturer: General; Height [mm]: 42 mm; Width [mm]: 100 mm; National code: XN1.31; IP_Code: IP41
ePset_LocationTool - Splitting: ORIGINAL
Pset_ElectricalDeviceCommon - IP_Code: IP41
ePset_Simplebim - Assembly Level: Leaf
Name | Circuit order no | Host
Addressable Luminaire | 2 | +TS=434.333
2 x Addressable Luminaire
Addressable Luminaire | 26 | +TS=434.333
Addressable Luminaire | 25 | +TS=434.333

# IfcDistributionControlElement: Brannalarm Multikriteriedetektor OT Blue
In: Nivå D
Type - Description: Brannalarm Multikriteriedetektor OT Blue
ePset_LocationTool - Splitting: ORIGINAL
ePset_Simplebim - Assembly Level: Leaf
MagiCAD Pset_Device - System code: 542; User code: -TY; Length [mm]: 0 mm; Width [mm]: 0 mm; Height [mm]: 0 mm; Installation Code: 2
Group: Brannalarm

# IfcDistributionControlElement: Nødåpner
In: Nivå D
Type - Description: Nødåpner KAC
AVINOR - 08_Status: S4; 07_Fase: F90; 05_ID-nummer: +TS=277.006-IK0001; 03_Ansvar: T20100; 04_Kontrakt: 72561; 02_Prosjekt: 72101; 01_Lufthavnkode: ENGM
Pset_ElectricalDeviceCommon - IP_Code: IP20
MagiCAD Pset_Device - System code: 543; User code: -IK; IP_Code: IP20; P1: -XS; Length [mm]: 0 mm; Width [mm]: 0 mm; Height [mm]: 0 mm; Manufacturer: General
ePset_LocationTool - Splitting: ORIGINAL
ePset_Simplebim - Assembly Level: Leaf
Group: Adgangskontroll, Innbruddsalarm

# IfcDistributionControlElement: Standard (21)
Type - Description: Brannalarm Røykdetektor
MagiCAD Pset_Device - Host: +TS=542.003; Length [mm]: 0 mm; Width [mm]: 0 mm; Height [mm]: 0 mm
ePset_Simplebim - Assembly Level: Leaf
ePset_LocationTool - Splitting: ORIGINAL
Name | In | Classification | System code | P1 | User code | National code | Installation Code | Circuit order no | Manufacturer | Group | Pset_ElectricalDeviceCommon, IP_Code = MagiCAD Pset_Device, IP_Code
3 x Standard | Nivå D | XJ1.1115 Not defined (NS3420) | 542 | -TY | -TY | XJ1.1115 | 2 | 25 | General | Brannalarm | Description: Brannalarm Multikriteriedetektor
2 x Standard | Nivå D | XJ1.1115 Not defined (NS3420) | 542 | -RY | -TY | XJ1.1115 | 2 | 25 | General | Brannalarm | IP20
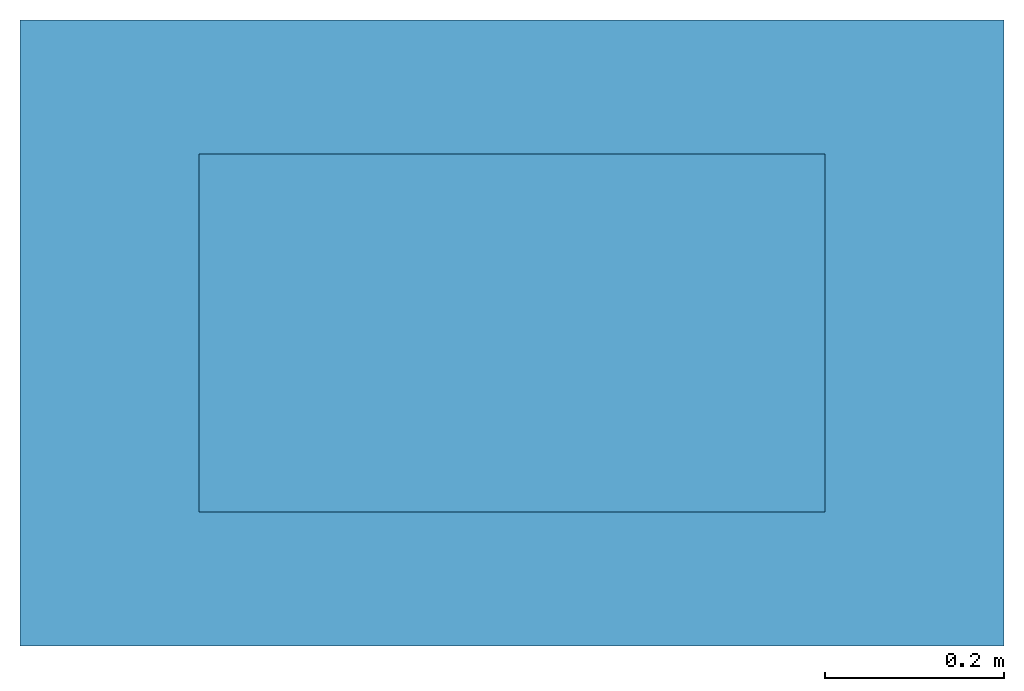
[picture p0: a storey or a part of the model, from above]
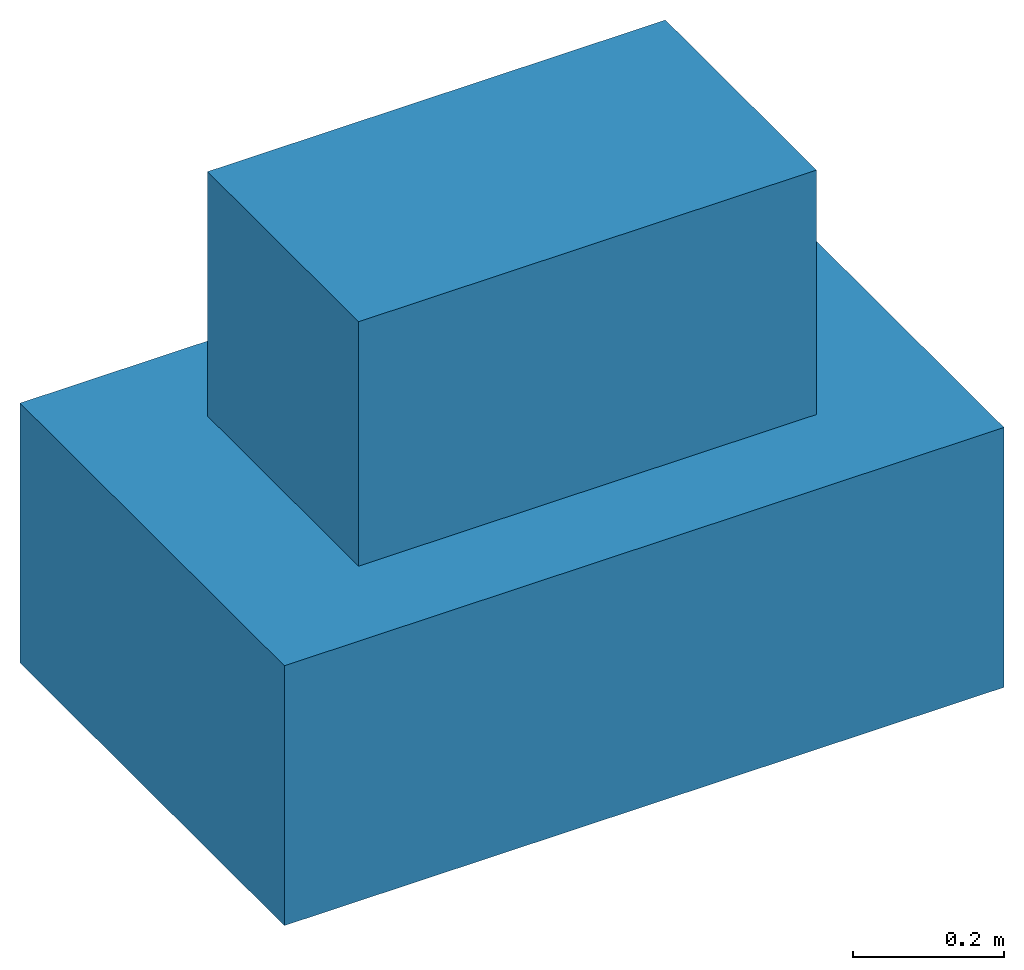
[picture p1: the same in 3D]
Properties of the parts of a building model (IFC2X3), part 3 of 5

# IfcDistributionControlElement: Standard (21)
Name | In | Classification | System code | P1 | User code | National code | Installation Code | Circuit order no | Manufacturer | Group | Pset_ElectricalDeviceCommon, IP_Code = MagiCAD Pset_Device, IP_Code
2 x Standard | Nivå D |  | 542 |  | -TY |  | 2 | 25 |  | Brannalarm | Description: Brannalarm Røykdetektor over himling
3 x Standard | Nivå D |  | 542 |  | -TY |  | 3 | 25 |  | Brannalarm | Description: Brannalarm Røykdetektor over himling
Standard | Nivå D | XJ1.1117 Not defined (NS3420) | 542 | -RY | -TW | XJ1.1117 |  | 25 | General | Brannalarm | Description: Brannalarm Varmedetektor
Standard | Nivå D | XJ4.1 Not defined (NS3420) |  | -QZ |  | XJ4.1 |  | 11 | General |  | IP54 | Description: Brannalarm Dørholdemagnet
4 x Standard | Nivå C | XJ1.1115 Not defined (NS3420) | 542 | -RY | -TY | XJ1.1115 | 2 | 21 | General | Brannalarm | IP20
5 x Standard | Nivå C | XJ1.1115 Not defined (NS3420) | 542 | -RY | -TY | XJ1.1115 | 2 | 20 | General | Brannalarm | IP20

# IfcDistributionControlElement: Switch with one push button
In: Nivå D
Type - Description: Åpneknapp
AVINOR - 08_Status: S4; 07_Fase: F90; 05_ID-nummer: +TS=543.006-QG0011; 03_Ansvar: T20100; 04_Kontrakt: 72561; 02_Prosjekt: 72101; 01_Lufthavnkode: ENGM
Pset_ElectricalDeviceCommon - IP_Code: IP21
ePset_Simplebim - Assembly Level: Leaf
ePset_LocationTool - Splitting: ORIGINAL
MagiCAD Pset_Device - Product code: Switch with one push button; System code: 543; P1: -QG; Length [mm]: 0 mm; Manufacturer: General; Width [mm]: 10 mm; Height [mm]: 60 mm; IP_Code: IP21
Group: Adgangskontroll, Innbruddsalarm

# IfcDistributionPort (13)
Description: Flow; FlowDirection: SOURCEANDSINK
ePset_Simplebim - Assembly Level: Leaf
Name
2 x Port_14878489_1
Port_14878491_1
2 x Port_15310786_1
Port_14878490_1
Port_14878492_1
2 x Port_15320519_1
Port_14878493_1
2 x Port_15320814_1
Port_18518734_1

# IfcDoor: A20 - Slagdør - Enkel5:A243 - DI_LTO - 0690 x 2090 mm, A20 - Slagdør - Enkel5:A243 - DI_LTO - 0690 x 2090 mm:41797002
In: Nivå D
Type - OperationType: SINGLE_SWING_RIGHT; ParameterTakesPrecedence: no; Sizeable: no; Material: N_Door - Handle, _NSW Stål - rustfritt, _NSW Dør - karm, hvit, N_Door - Threshold, N_Door - Panel
Type - IfcDoorPanelProperties - PanelOperation: SWINGING
OverallHeight: 2110 mm; OverallWidth: 710 mm
Pset_DoorCommon - IsExternal: no; Reference: A243 - DI_LTO - 0690 x 2090 mm
AVINOR - 08_Status: S4; 07_Fase: F40; 03_Ansvar: LEIETAKER; 02_Prosjekt: 72101; 06_Omrade: TS; 01_Lufthavnkode: ENGM
ePset_Simplebim - Assembly Level: Leaf
ePset_LocationTool - Splitting: ORIGINAL
Pset_QuantityTakeOff - Reference: A243 - DI_LTO - 0690 x 2090 mm
ePset_SimplebimBasicQuantities - Area, opening (Simplebim): 1.4981 m2; Height, opening (Simplebim): 2110 mm; Width, opening (Simplebim): 710 mm; Width (Simplebim): 690 mm; Height (Simplebim): 2090 mm; Length, frame (Simplebim): 4870 mm; Area (Simplebim): 1.4421 m2

# IfcDoor: A20 - Slagdør - Enkel:A243 - DI_LTO - 0990 x 2090 mm, A20 - Slagdør - Enkel:A243 - DI_LTO - 0990 x 2090 mm:40250339
In: Nivå D
Type - OperationType: SINGLE_SWING_RIGHT; ParameterTakesPrecedence: no; Sizeable: no; Material: N_Door - Handle, _NSW Stål - rustfritt, _NSW Dør - karm, hvit, N_Door - Threshold, N_Door - Panel
Type - IfcDoorPanelProperties - PanelOperation: SWINGING
OverallHeight: 2110 mm; OverallWidth: 1010 mm
Identity Data - CQFireRequirement: EI 30 Sa
Pset_QuantityTakeOff - Reference: A243 - DI_LTO - 0990 x 2090 mm
ePset_LocationTool - Splitting: ORIGINAL
AVINOR - 08_Status: S4; 07_Fase: F90; 03_Ansvar: 72717; 05_ID-nummer: +TS=243.001-IO2754; 02_Prosjekt: 72101; 06_Omrade: TS; 01_Lufthavnkode: ENGM
Pset_DoorCommon - Reference: A243 - DI_LTO - 0990 x 2090 mm; IsExternal: no
ePset_SimplebimBasicQuantities - Height, opening (Simplebim): 2110 mm; Area (Simplebim): 2.0691 m2; Width, opening (Simplebim): 1010 mm; Width (Simplebim): 990 mm; Height (Simplebim): 2090 mm; Length, frame (Simplebim): 5170 mm; Area, opening (Simplebim): 2.1311 m2
ePset_Simplebim - Assembly Level: Leaf

# IfcDoor: A20 - Slagdør - Enkel:A243 - DI_LTO - 1090 x 2090 mm, A20 - Slagdør - Enkel:A243 - DI_LTO - 1090 x 2090 mm:41787461
In: Nivå D
Type - OperationType: SINGLE_SWING_RIGHT; ParameterTakesPrecedence: no; Sizeable: no; Material: N_Door - Handle, _NSW Stål - rustfritt, _NSW Dør - karm, hvit, N_Door - Threshold, N_Door - Panel
Type - IfcDoorPanelProperties - PanelOperation: SWINGING
OverallHeight: 2110 mm; OverallWidth: 1110 mm
Identity Data - CQFireRequirement: EI 30 CSa
AVINOR - 08_Status: S4; 07_Fase: F90; 03_Ansvar: 72717; 05_ID-nummer: +TS=243.001-IO2756; 02_Prosjekt: 72101; 06_Omrade: TS; 01_Lufthavnkode: ENGM
ePset_SimplebimBasicQuantities - Area, opening (Simplebim): 2.3421 m2; Height, opening (Simplebim): 2110 mm; Width, opening (Simplebim): 1110 mm; Area (Simplebim): 2.2781 m2; Width (Simplebim): 1090 mm; Height (Simplebim): 2090 mm; Length, frame (Simplebim): 5270 mm
ePset_LocationTool - Splitting: ORIGINAL
Pset_DoorCommon - Reference: A243 - DI_LTO - 1090 x 2090 mm; IsExternal: no
ePset_Simplebim - Assembly Level: Leaf
Pset_QuantityTakeOff - Reference: A243 - DI_LTO - 1090 x 2090 mm

# IfcDoor: A20 - Slagdør - Enkel:A243 - DI_LTO - 890 x 2090 mm, A20 - Slagdør - Enkel:A243 - DI_LTO - 890 x 2090 mm:41787719
In: Nivå D
Type - OperationType: SINGLE_SWING_RIGHT; ParameterTakesPrecedence: no; Sizeable: no; Material: N_Door - Handle, _NSW Stål - rustfritt, _NSW Dør - karm, hvit, N_Door - Threshold, N_Door - Panel
Type - IfcDoorPanelProperties - PanelOperation: SWINGING
OverallHeight: 2110 mm; OverallWidth: 910 mm
Pset_QuantityTakeOff - Reference: A243 - DI_LTO - 890 x 2090 mm
Pset_DoorCommon - IsExternal: no; Reference: A243 - DI_LTO - 890 x 2090 mm
ePset_SimplebimBasicQuantities - Height, opening (Simplebim): 2110 mm; Width (Simplebim): 890 mm; Area, opening (Simplebim): 1.9201 m2; Area (Simplebim): 1.8601 m2; Width, opening (Simplebim): 910 mm; Height (Simplebim): 2090 mm; Length, frame (Simplebim): 5070 mm
ePset_Simplebim - Assembly Level: Leaf
ePset_LocationTool - Splitting: ORIGINAL
AVINOR - 08_Status: S4; 07_Fase: F90; 03_Ansvar: 72717; 02_Prosjekt: 72101; 05_ID-nummer: +TS=243.001-IP0269; 06_Omrade: TS; 01_Lufthavnkode: ENGM

# IfcDoor: A20 - Slagdør - Enkel:A243 - DI_SSO - 0590 x 2090 mm, A20 - Slagdør - Enkel:A243 - DI_SSO - 0590 x 2090 mm:39991380
In: Nivå D
Type - OperationType: SINGLE_SWING_RIGHT; ParameterTakesPrecedence: no; Sizeable: no; Material: N_Door - Handle, _NSW Stål - rustfritt, _NSW Stål, N_Door - Threshold, N_Door - Panel
Type - IfcDoorPanelProperties - PanelOperation: SWINGING
OverallHeight: 2110 mm; OverallWidth: 610 mm
Identity Data - CQFireRequirement: EI 30 Sa
ePset_SimplebimBasicQuantities - Height, opening (Simplebim): 2110 mm; Area, opening (Simplebim): 1.2871 m2; Area (Simplebim): 1.2331 m2; Width, opening (Simplebim): 610 mm; Width (Simplebim): 590 mm; Height (Simplebim): 2090 mm; Length, frame (Simplebim): 4770 mm
Pset_DoorCommon - IsExternal: no; Reference: A243 - DI_SSO - 0590 x 2090 mm
AVINOR - 08_Status: S4; 07_Fase: F90; 05_ID-nummer: +TS=243.001-IO2755; 03_Ansvar: 72717; 02_Prosjekt: 72101; 06_Omrade: TS; 01_Lufthavnkode: ENGM
ePset_Simplebim - Assembly Level: Leaf
ePset_LocationTool - Splitting: ORIGINAL
Pset_QuantityTakeOff - Reference: A243 - DI_SSO - 0590 x 2090 mm

# IfcDoor: A20 - Slagdør - Enkel:A243 - DI_SSO - 0890 x 2090 mm, A20 - Slagdør - Enkel:A243 - DI_SSO - 0890 x 2090 mm:39966273
In: Nivå D
Type - OperationType: SINGLE_SWING_RIGHT; ParameterTakesPrecedence: no; Sizeable: no; Material: N_Door - Handle, _NSW Stål - rustfritt, _NSW Stål, N_Door - Threshold, N_Door - Panel
Type - IfcDoorPanelProperties - PanelOperation: SWINGING
OverallHeight: 2110 mm; OverallWidth: 910 mm
Pset_QuantityTakeOff - Reference: A243 - DI_SSO - 0890 x 2090 mm
AVINOR - 08_Status: S4; 07_Fase: F90; 05_ID-nummer: +TS=243.001-IP0268; 03_Ansvar: 72717; 02_Prosjekt: 72101; 06_Omrade: TS; 01_Lufthavnkode: ENGM
ePset_SimplebimBasicQuantities - Height, opening (Simplebim): 2110 mm; Area, opening (Simplebim): 1.9201 m2; Area (Simplebim): 1.8601 m2; Width, opening (Simplebim): 910 mm; Width (Simplebim): 890 mm; Height (Simplebim): 2090 mm; Length, frame (Simplebim): 5070 mm
ePset_Simplebim - Assembly Level: Leaf
ePset_LocationTool - Splitting: ORIGINAL
Pset_DoorCommon - Reference: A243 - DI_SSO - 0890 x 2090 mm; IsExternal: no

# IfcDoor: A243 - InPlace - Foldegitter nivå D:A243 - InPlace - Foldegitter nivå D, A243 - InPlace - Foldegitter nivå D:A243 - InPlace - Foldegitter nivå D:45330869
In: Nivå D
Type - ParameterTakesPrecedence: no; Sizeable: no; Material: <Unnamed>
OverallHeight: 3287.79 mm; OverallWidth: 226.049 mm
ePset_LocationTool - Splitting: ORIGINAL
ePset_Simplebim - Assembly Level: Leaf
Pset_DoorCommon - Reference: A243 - InPlace - Foldegitter nivå D; IsExternal: no
Pset_QuantityTakeOff - Reference: A243 - InPlace - Foldegitter nivå D
ePset_SimplebimBasicQuantities - Area (Simplebim): 7.89068 m2; Height (Simplebim): 2400 mm; Length, frame (Simplebim): 8087.79 mm; Width (Simplebim): 3287.79 mm
AVINOR - 08_Status: S4; 07_Fase: F90; 05_ID-nummer: +TS=243.001-IR0063; 03_Ansvar: 72717; 02_Prosjekt: 72101; 06_Omrade: TS; 01_Lufthavnkode: ENGM

# IfcElectricalCircuit, PA Anlegg
Description: 555

# IfcFlowController: IGNIS-C-EI60-250 (4)
In: Nivå D
Type - Description: CIRCULAR FIRE DAMPER CLASS EI60; PredefinedType: FIREDAMPER
ePset_Simplebim - Assembly Level: Leaf
ePset_LocationTool - Splitting: ORIGINAL
Name | Group
2 x IGNIS-C-EI60-250 | +TS=360.060 T_2
2 x IGNIS-C-EI60-250 | +TS=360.010 A

# IfcFlowController: IRIS-315 (2)
In: Nivå D
Type - PredefinedType: BALANCINGDAMPER
ePset_Simplebim - Assembly Level: Leaf
ePset_LocationTool - Splitting: ORIGINAL
Name | Group
IRIS-315 | +TS=360.010 A
IRIS-315 | +TS=360.060 T_2

# IfcFlowController: IRIS-400
In: Nivå D
Type - Description: Balancing damper; PredefinedType: BALANCINGDAMPER
ePset_LocationTool - Splitting: ORIGINAL
ePset_Simplebim - Assembly Level: Leaf
Group: +TS=360.010 A

# IfcFlowController: PK-I-S-EI90S-1550x650-DV9
In: Nivå C
Type - Description: Fire damper for explosive areas rectangular; PredefinedType: FIREDAMPER
ePset_LocationTool - Splitting: ORIGINAL
ePset_Simplebim - Assembly Level: Leaf
Group: +JU=360.010 A

# IfcFlowController: TVT-EASY-400x250
In: Nivå D
Type - Description: VARYCONTROL VAV Controler; PredefinedType: FIREDAMPER
ePset_Simplebim - Assembly Level: Leaf
ePset_LocationTool - Splitting: ORIGINAL
Group: +TS=360.060 T_2

# IfcFlowController: TVT-EASY-500x250
In: Nivå D
Type - Description: VARYCONTROL VAV Controler; PredefinedType: FIREDAMPER
ePset_LocationTool - Splitting: ORIGINAL
ePset_Simplebim - Assembly Level: Leaf
Group: +TS=360.060 T_2

# IfcFlowController: TVT-EASY-700x250
In: Nivå D
Type - Description: VARYCONTROL VAV Controler; PredefinedType: FIREDAMPER
ePset_Simplebim - Assembly Level: Leaf
ePset_LocationTool - Splitting: ORIGINAL

# IfcFlowFitting: Junction box round1
In: Nivå D
Type - Description: Koblingsboks åpen tele-data
ePset_LocationTool - Splitting: ORIGINAL
MagiCAD Pset_Device - System code: 543; Length [mm]: 0 mm; Width [mm]: 0 mm; Height [mm]: 0 mm; Product code: Junction box round1; Manufacturer: General
ePset_Simplebim - Assembly Level: Leaf
AVINOR - 08_Status: S4; 07_Fase: F90; 03_Ansvar: T20100; 04_Kontrakt: 72561; 05_ID-nummer: +TS=543.006-QM0001; 02_Prosjekt: 72101; 01_Lufthavnkode: ENGM
Group: Adgangskontroll, Innbruddsalarm

# IfcFlowFitting: Koblingsboks åpen
In: Nivå D
Type - Description: Koblingsboks åpen
Pset_ElectricalDeviceCommon - ElectricalDeviceNominalPower: 0 W; NumberOfPoles: 1; NominalVoltage: 230
MagiCAD Pset_Device - User code: -QM; P1: -XD; Length [mm]: 0 mm; Width [mm]: 0 mm; Height [mm]: 0 mm; Number of Poles: 1; Active Power: 0 W; System code: 555; Manufacturer: General; Power Factor: 1; Voltage: 230
ePset_Simplebim - Assembly Level: Leaf
ePset_LocationTool - Splitting: ORIGINAL
AVINOR - 07_Fase: F90; 05_ID-nummer: +TS=555.003; 04_Kontrakt: FDV; 08_Status: S2; 02_Prosjekt: 72101; 01_Lufthavnkode: ENGM
Group: PA Anlegg

# IfcFlowFitting: Lindab LORU
In: Nivå D
Type - PredefinedType: TRANSITION
ePset_Simplebim - Assembly Level: Leaf
ePset_LocationTool - Splitting: ORIGINAL

# IfcFlowFitting: Standard (3)
In: Nivå D
Type - PredefinedType: BEND
MagiCAD Pset_Cabletray - Width [mm]: 0 mm; Height [mm]: 0 mm; Length [mm]: 0 mm; System code: 4112
ePset_Simplebim - Assembly Level: Leaf
ePset_LocationTool - Splitting: ORIGINAL
Group: Veggkanal for generelt

# IfcFlowFitting: Standard 10mm (2)
In: Nivå C
Type - PredefinedType: BEND
ePset_Simplebim - Assembly Level: Leaf
ePset_LocationTool - Splitting: ORIGINAL
MagiCAD Pset_Cabletray - Width [mm]: 0 mm; Height [mm]: 0 mm; Length [mm]: 0 mm
Name
Standard 10mm | MagiCAD Pset_Cabletray - System code: 410; Group: Bæresystem generelt
Standard 10mm

# IfcFlowFitting: WA (3)
In: Nivå D
Type - PredefinedType: BEND
ePset_LocationTool - Splitting: ORIGINAL
ePset_Simplebim - Assembly Level: Leaf
Name | Group
WA | 36= Avtrekk 53
WA | 36= Avtrekk 71
WA | 36= Avtrekk 77

# IfcFlowFitting: magi_pipe_fe_cross_centric_90_001 (9)
Type - PredefinedType: JUNCTION
MagiCAD Pset_XBranch - Insulation_thickness_mm: 0 mm; qv_SizingFlow_ls: 0 m3/s; pTot_SizingFlow_Pa: 0 Pa; dpTot_SizingFlow_Pa: 0 Pa; v_SizingFlow_ms: 0 m/s; ConnectionSize_mm: 0 mm
ePset_Simplebim - Assembly Level: Leaf
ePset_LocationTool - Splitting: ORIGINAL
Group: +TS=332.007 - 1 (10)
Name | In
8 x magi_pipe_fe_cross_centric_90_001 | Nivå D
magi_pipe_fe_cross_centric_90_001 | Nivå D + 1,2 m

# IfcFlowFitting: magi_pipe_fe_elbow_short_001 (168)
Type - PredefinedType: BEND
MagiCAD Pset_Elbow - Insulation_thickness_mm: 0 mm; qv_SizingFlow_ls: 0 m3/s; pTot_SizingFlow_Pa: 0 Pa; dpTot_SizingFlow_Pa: 0 Pa; v_SizingFlow_ms: 0 m/s; ConnectionSize_mm: 0 mm
ePset_Simplebim - Assembly Level: Leaf
ePset_LocationTool - Splitting: ORIGINAL
Name | In | Group
6 x magi_pipe_fe_elbow_short_001 | Nivå C | +TS=332.002
2 x magi_pipe_fe_elbow_short_001 | Nivå C | +TU=332.003-NZ0004
2 x magi_pipe_fe_elbow_short_001 | Nivå C
10 x magi_pipe_fe_elbow_short_001 | Nivå C | +TS=332.005
2 x magi_pipe_fe_elbow_short_001 | Nivå C | 33= Våt Kopi 39
2 x magi_pipe_fe_elbow_short_001 | Nivå D | +TS=332.008
122 x magi_pipe_fe_elbow_short_001 | Nivå D | +TS=332.007 - 1 (10)
magi_pipe_fe_elbow_short_001 | Nivå D
21 x magi_pipe_fe_elbow_short_001 | Nivå D + 1,2 m | +TS=332.007 - 1 (10)

# IfcFlowFitting: magi_pipe_fe_joint_001 (3)
In: Nivå D
Type - PredefinedType: CONNECTOR
MagiCAD Pset_Joint - Insulation_thickness_mm: 0 mm; qv_SizingFlow_ls: 0 m3/s; pTot_SizingFlow_Pa: 0 Pa; dpTot_SizingFlow_Pa: 0 Pa; v_SizingFlow_ms: 0 m/s; ConnectionSize_mm: 0 mm
ePset_Simplebim - Assembly Level: Leaf
ePset_LocationTool - Splitting: ORIGINAL
Group: +TS=332.007 - 1 (10)

# IfcFlowFitting: magi_pipe_fe_reducer_centric_short_NOR (145)
Type - PredefinedType: TRANSITION
MagiCAD Pset_Reduction - Insulation_thickness_mm: 0 mm; qv_SizingFlow_ls: 0 m3/s; pTot_SizingFlow_Pa: 0 Pa; dpTot_SizingFlow_Pa: 0 Pa; v_SizingFlow_ms: 0 m/s; ConnectionSize_mm: 0 mm
ePset_Simplebim - Assembly Level: Leaf
ePset_LocationTool - Splitting: ORIGINAL
Name | In | Group
8 x magi_pipe_fe_reducer_centric_short_NOR | Nivå C | +TS=332.002
37 x magi_pipe_fe_reducer_centric_short_NOR | Nivå C | +TS=332.005
magi_pipe_fe_reducer_centric_short_NOR | Nivå D | +TS=332.008
magi_pipe_fe_reducer_centric_short_NOR | Nivå D
93 x magi_pipe_fe_reducer_centric_short_NOR | Nivå D | +TS=332.007 - 1 (10)
magi_pipe_fe_reducer_centric_short_NOR | Nivå D | 33= tørr Kopi 1
magi_pipe_fe_reducer_centric_short_NOR | Nivå D | 33= tørr Kopi 4
magi_pipe_fe_reducer_centric_short_NOR | Nivå D | 33= tørr Kopi 2
2 x magi_pipe_fe_reducer_centric_short_NOR | Nivå D + 1,2 m | +TS=332.007 - 1 (10)

# IfcFlowFitting: magi_pipe_fe_tee_centric_90_NOR (120)
Type - PredefinedType: JUNCTION
MagiCAD Pset_TBranch - Insulation_thickness_mm: 0 mm; qv_SizingFlow_ls: 0 m3/s; pTot_SizingFlow_Pa: 0 Pa; dpTot_SizingFlow_Pa: 0 Pa; v_SizingFlow_ms: 0 m/s; ConnectionSize_mm: 0 mm
ePset_Simplebim - Assembly Level: Leaf
ePset_LocationTool - Splitting: ORIGINAL
Name | In | Group
4 x magi_pipe_fe_tee_centric_90_NOR | Nivå C | +TS=332.002
43 x magi_pipe_fe_tee_centric_90_NOR | Nivå C | +TS=332.005
2 x magi_pipe_fe_tee_centric_90_NOR | Nivå D | +TS=332.008
2 x magi_pipe_fe_tee_centric_90_NOR | Nivå D
63 x magi_pipe_fe_tee_centric_90_NOR | Nivå D | +TS=332.007 - 1 (10)
6 x magi_pipe_fe_tee_centric_90_NOR | Nivå D + 1,2 m | +TS=332.007 - 1 (10)

# IfcFlowFitting: magicirc_elbow_full_radius_001 (26)
Type - Description: Circular, smooth,R=D; PredefinedType: BEND
ePset_Simplebim - Assembly Level: Leaf
ePset_LocationTool - Splitting: ORIGINAL
Name | In | Group
magicirc_elbow_full_radius_001 | Nivå C | +TS=360.030 A | Description: Bend, Sirkulært
3 x magicirc_elbow_full_radius_001 | Nivå C | +TS=360.030 T | Description: Bend, Sirkulært
19 x magicirc_elbow_full_radius_001 | Nivå D | +TS=360.060 T_2
magicirc_elbow_full_radius_001 | Nivå D
magicirc_elbow_full_radius_001 | Nivå D | +TS=360.010 A
magicirc_elbow_full_radius_001 | Nivå D + 1,2 m | +TS=360.060 T_2

# IfcFlowFitting: magicirc_elbow_short_001 (17)
Type - PredefinedType: BEND
ePset_Simplebim - Assembly Level: Leaf
Name | In | Splitting | Group
magicirc_elbow_short_001 | Nivå C | ORIGINAL | +TS=360.030 A
2 x magicirc_elbow_short_001 | Nivå D | ORIGINAL | +TS=360.060 T_2
11 x magicirc_elbow_short_001 | Nivå D | ORIGINAL | +TS=360.010 A
3 x magicirc_elbow_short_001 | Nivå C | RESULT | +JU=360.011 T

# IfcFlowFitting: magicirc_joint_001
In: Nivå D
Type - PredefinedType: CONNECTOR
ePset_Simplebim - Assembly Level: Leaf
ePset_LocationTool - Splitting: ORIGINAL
Group: +TS=360.060 T_2

# IfcFlowFitting: magicirc_multi_shape_trans_001 (2)
In: Nivå D
Type - Description: Round to rectangular transition; PredefinedType: TRANSITION
ePset_Simplebim - Assembly Level: Leaf
ePset_LocationTool - Splitting: ORIGINAL
Name | Group
magicirc_multi_shape_trans_001 | +TS=360.060 T_2
magicirc_multi_shape_trans_001 | +TS=360.010 A

# IfcFlowFitting: magicirc_plug_001 (3)
In: Nivå D
Type - Description: Circular; PredefinedType: OBSTRUCTION
ePset_Simplebim - Assembly Level: Leaf
ePset_LocationTool - Splitting: ORIGINAL
Name | Group
magicirc_plug_001 | Mechanical 36 Avtrekk 2
2 x magicirc_plug_001 | +TS=360.060 T_2

# IfcFlowFitting: magicirc_reduction_001 (4)
Type - Description: Circular, concentric and eccentric, 60 deg (short); PredefinedType: TRANSITION
ePset_Simplebim - Assembly Level: Leaf
ePset_LocationTool - Splitting: ORIGINAL
Name | In | Group
magicirc_reduction_001 | Nivå D | +TS=360.010 A
magicirc_reduction_001 | Nivå D | +TS=360.060 T_2
2 x magicirc_reduction_001 | Nivå D + 1,2 m | +TS=360.060 T_2

# IfcFlowFitting: magicirc_tapoutlet_001 (16)
Type - Description: Rectangular/circular; PredefinedType: CONNECTOR
Description: Påstikk
ePset_LocationTool - Splitting: ORIGINAL
ePset_Simplebim - Assembly Level: Leaf
Name | In | Group
magicirc_tapoutlet_001 | Nivå C | +TS=360.030 T
10 x magicirc_tapoutlet_001 | Nivå D | +TS=360.060 T_2
magicirc_tapoutlet_001 | Nivå D
3 x magicirc_tapoutlet_001 | Nivå D | +TS=360.010 A
magicirc_tapoutlet_001 | Nivå D + 1,2 m | +TS=360.060 T_2

# IfcFlowFitting: magirect_outlet1_001 2
In: Nivå D
Type - PredefinedType: CONNECTOR
ePset_Simplebim - Assembly Level: Leaf
ePset_LocationTool - Splitting: ORIGINAL
Group: +TS=360.010 A

# IfcFlowFitting: magirect_plug1_001 (2)
Type - PredefinedType: OBSTRUCTION
ePset_LocationTool - Splitting: ORIGINAL
ePset_Simplebim - Assembly Level: Leaf
Group: +TS=360.010 A
Name | In
magirect_plug1_001 | Nivå C
magirect_plug1_001 | Nivå D

# IfcFlowSegment: 2 - Spiro kanaler, Forsinket stål (4)
In: Nivå D
Type - Description: Spiro kanaler, Forsinket stål; PredefinedType: RIGIDSEGMENT
ePset_SimplebimBasicQuantities - Height (Simplebim): 250 mm; Width (Simplebim): 250 mm
ePset_Simplebim - Assembly Level: Leaf
Name | Length (Simplebim) (mm) | Splitting
2 - Spiro kanaler, Forsinket stål | 5478.8 | ORIGINAL | Group: +TS=360.060 T_2
2 - Spiro kanaler, Forsinket stål | 1210 | ORIGINAL
2 - Spiro kanaler, Forsinket stål | 2752.8 | ORIGINAL | Group: +TS=360.060 T_2
2 - Spiro kanaler, Forsinket stål | 2491 | RESULT

# IfcFlowSegment: KK001T - Spiro kanaler, Forsinket stål (49)
Type - Description: Spiro kanaler, Forsinket stål; PredefinedType: RIGIDSEGMENT
Classification: VB2.121212 Not defined (NS3420)
ePset_Simplebim - Assembly Level: Leaf
Name | In | Splitting | Length (Simplebim) (mm) | Height (Simplebim) (mm) = Width (Simplebim) (mm) | Group
KK001T - Spiro kanaler, Forsinket stål | Nivå C | ORIGINAL | 2240.7 | 125 | +TS=360.030 A
KK001T - Spiro kanaler, Forsinket stål | Nivå C | ORIGINAL | 774.8 | 160 | +TS=360.030 T
KK001T - Spiro kanaler, Forsinket stål | Nivå C | ORIGINAL | 8.8 | 160 | +TS=360.030 T
5 x KK001T - Spiro kanaler, Forsinket stål | Nivå D | ORIGINAL | 728.8 | 125 | +TS=360.060 T_2
5 x KK001T - Spiro kanaler, Forsinket stål | Nivå D | ORIGINAL | 350.1 | 125 | +TS=360.060 T_2
4 x KK001T - Spiro kanaler, Forsinket stål | Nivå D | ORIGINAL | 915.7 | 125 | +TS=360.060 T_2
KK001T - Spiro kanaler, Forsinket stål | Nivå D | ORIGINAL | 300.4 | 125
KK001T - Spiro kanaler, Forsinket stål | Nivå D | ORIGINAL | 1625.3 | 200 | +TS=360.060 T_2
KK001T - Spiro kanaler, Forsinket stål | Nivå D | ORIGINAL | 1317.2 | 200 | +TS=360.060 T_2
KK001T - Spiro kanaler, Forsinket stål | Nivå D | ORIGINAL | 1475.7 | 200 | +TS=360.060 T_2
KK001T - Spiro kanaler, Forsinket stål | Nivå D | ORIGINAL | 181.5 | 200 | +TS=360.060 T_2
KK001T - Spiro kanaler, Forsinket stål | Nivå D | ORIGINAL | 8350.8 | 315 | +TS=360.060 T_2
KK001T - Spiro kanaler, Forsinket stål | Nivå D | ORIGINAL | 500 | 400
KK001T - Spiro kanaler, Forsinket stål | Nivå D | ORIGINAL | 4936.7 | 400 | +TS=360.010 A
KK001T - Spiro kanaler, Forsinket stål | Nivå D | ORIGINAL | 1829 | 315 | +TS=360.060 T_2
2 x KK001T - Spiro kanaler, Forsinket stål | Nivå D | ORIGINAL | 1143.5 | 200 | +TS=360.060 T_2
2 x KK001T - Spiro kanaler, Forsinket stål | Nivå D | ORIGINAL | 62.3 | 200 | +TS=360.060 T_2
KK001T - Spiro kanaler, Forsinket stål | Nivå D | ORIGINAL | 1634.3 | 400 | +TS=360.010 A
KK001T - Spiro kanaler, Forsinket stål | Nivå D | ORIGINAL | 475.7 | 125 | +TS=360.060 T_2
KK001T - Spiro kanaler, Forsinket stål | Nivå D | ORIGINAL | 23.1 | 315 | +TS=360.060 T_2
KK001T - Spiro kanaler, Forsinket stål | Nivå D | ORIGINAL | 324.8 | 250 | +TS=360.060 T_2
KK001T - Spiro kanaler, Forsinket stål | Nivå D | ORIGINAL | 1542.8 | 315 | +TS=360.060 T_2
KK001T - Spiro kanaler, Forsinket stål | Nivå D | ORIGINAL | 44.2 | 315 | +TS=360.060 T_2
KK001T - Spiro kanaler, Forsinket stål | Nivå D | ORIGINAL | 1141.9 | 315 | +TS=360.060 T_2
KK001T - Spiro kanaler, Forsinket stål | Nivå D | ORIGINAL | 112.1 | 250 | +TS=360.060 T_2
KK001T - Spiro kanaler, Forsinket stål | Nivå D | ORIGINAL | 322.6 | 250 | +TS=360.060 T_2
KK001T - Spiro kanaler, Forsinket stål | Nivå D | ORIGINAL | 491.3 | 250 | +TS=360.060 T_2
KK001T - Spiro kanaler, Forsinket stål | Nivå D | ORIGINAL | 728.3 | 250 | +TS=360.060 T_2
KK001T - Spiro kanaler, Forsinket stål | Nivå D | ORIGINAL | 725.9 | 250 | +TS=360.060 T_2
KK001T - Spiro kanaler, Forsinket stål | Nivå D | ORIGINAL | 388 | 315 | +TS=360.060 T_2
KK001T - Spiro kanaler, Forsinket stål | Nivå D + 1,2 m | ORIGINAL | 616 | 250 | +TS=360.060 T_2
KK001T - Spiro kanaler, Forsinket stål | Nivå D + 1,2 m | ORIGINAL | 1218.4 | 250 | +TS=360.060 T_2
KK001T - Spiro kanaler, Forsinket stål | Nivå D + 1,2 m | ORIGINAL | 1175 | 250 | +TS=360.060 T_2
KK001T - Spiro kanaler, Forsinket stål | Nivå D + 1,2 m | ORIGINAL | 409.4 | 250 | +TS=360.060 T_2
KK001T - Spiro kanaler, Forsinket stål | Nivå C | RESULT | 3856 | 160 | +TS=360.030 T
KK001T - Spiro kanaler, Forsinket stål | Nivå C | RESULT | 1190 | 124 | +TS=360.030 A

# IfcFlowSegment: KK002T - Rektangulære, Forsinket stål (14)
Type - Description: Rektangulære, Forsinket stål; PredefinedType: RIGIDSEGMENT
Classification: VB2.111212 Not defined (NS3420)
ePset_Simplebim - Assembly Level: Leaf
Name | In | Splitting | Width (Simplebim) (mm) | Height (Simplebim) (mm) | Length (Simplebim) (mm) | Group
KK002T - Rektangulære, Forsinket stål | Nivå C | ORIGINAL | 650 | 520 | 1550 | +JU=360.010 A
KK002T - Rektangulære, Forsinket stål | Nivå D | ORIGINAL | 150 | 188.4 | 500 | 36= Avtrekk 53
KK002T - Rektangulære, Forsinket stål | Nivå D | ORIGINAL | 73.5 | 150 | 500 | 36= Avtrekk 53
KK002T - Rektangulære, Forsinket stål | Nivå D | ORIGINAL | 150 | 188.4 | 500 | 36= Avtrekk 71
KK002T - Rektangulære, Forsinket stål | Nivå D | ORIGINAL | 73.5 | 150 | 500 | 36= Avtrekk 71
KK002T - Rektangulære, Forsinket stål | Nivå D | ORIGINAL | 150 | 188.4 | 500 | 36= Avtrekk 77
KK002T - Rektangulære, Forsinket stål | Nivå D | ORIGINAL | 73.5 | 150 | 500 | 36= Avtrekk 77
KK002T - Rektangulære, Forsinket stål | Nivå D | ORIGINAL | 400 | 250 | 6645 | +TS=360.060 T_2
KK002T - Rektangulære, Forsinket stål | Nivå D | ORIGINAL | 700 | 250 | 743.3
KK002T - Rektangulære, Forsinket stål | Nivå D | ORIGINAL | 379.2 | 250 | 500 | +TS=360.060 T_2
KK002T - Rektangulære, Forsinket stål | Nivå D | ORIGINAL | 500 | 250 | 1040 | +TS=360.060 T_2
KK002T - Rektangulære, Forsinket stål | Nivå D | ORIGINAL | 289.6 | 200 | 500 | +TS=360.010 A
KK002T - Rektangulære, Forsinket stål | Nivå D | ORIGINAL | 320 | 230 | 500 | +TS=360.010 A
KK002T - Rektangulære, Forsinket stål | Nivå D | RESULT | 355 | 250 | 700

# IfcFlowSegment: KK002T - Spiro kanaler, Forsinket stål, korte bend (18)
In: Nivå D
Type - Description: Spiro kanaler, Forsinket stål; PredefinedType: RIGIDSEGMENT
Classification: VB2.121212 Not defined (NS3420); Group: +TS=360.010 A
ePset_LocationTool - Splitting: ORIGINAL
ePset_Simplebim - Assembly Level: Leaf
Name | Length (Simplebim) (mm) | Height (Simplebim) (mm) = Width (Simplebim) (mm)
KK002T - Spiro kanaler, Forsinket stål, korte bend | 189.2 | 250
KK002T - Spiro kanaler, Forsinket stål, korte bend | 1630.2 | 250
KK002T - Spiro kanaler, Forsinket stål, korte bend | 546.5 | 250
KK002T - Spiro kanaler, Forsinket stål, korte bend | 1620 | 250
KK002T - Spiro kanaler, Forsinket stål, korte bend | 4060 | 250
KK002T - Spiro kanaler, Forsinket stål, korte bend | 361.4 | 250
2 x KK002T - Spiro kanaler, Forsinket stål, korte bend | 53.6 | 250
KK002T - Spiro kanaler, Forsinket stål, korte bend | 351.8 | 250
KK002T - Spiro kanaler, Forsinket stål, korte bend | 5070.2 | 250
KK002T - Spiro kanaler, Forsinket stål, korte bend | 1083.2 | 315
2 x KK002T - Spiro kanaler, Forsinket stål, korte bend | 432.8 | 250
2 x KK002T - Spiro kanaler, Forsinket stål, korte bend | 128 | 250
KK002T - Spiro kanaler, Forsinket stål, korte bend | 227.5 | 250
KK002T - Spiro kanaler, Forsinket stål, korte bend | 4488.2 | 315
KK002T - Spiro kanaler, Forsinket stål, korte bend | 1355.7 | 400

# IfcFlowSegment: KK003T - Spiro kanaler, Stålrør (6)
In: Nivå C
Type - Description: Spiro kanaler, Stålrør; PredefinedType: RIGIDSEGMENT
Classification: VB2.121212 Not defined (NS3420)
ePset_Simplebim - Assembly Level: Leaf
Name | Splitting | Length (Simplebim) (mm) | Width (Simplebim) (mm) | Height (Simplebim) (mm) | Group
KK003T - Spiro kanaler, Stålrør | ORIGINAL | 125 | 125 | 90 | +TS=360.030 T
KK003T - Spiro kanaler, Stålrør | RESULT | 3243 | 630 | 330 | +JU=360.011 T
KK003T - Spiro kanaler, Stålrør | RESULT | 1491 | 630 | 330 | +JU=360.011 T
KK003T - Spiro kanaler, Stålrør | RESULT | 5913 | 160 | 160 | +TS=360.030 T
KK003T - Spiro kanaler, Stålrør | RESULT | 7891 | 630 | 330 | +JU=360.011 T
KK003T - Spiro kanaler, Stålrør | RESULT | 3538 | 316 | 316 | +TS=360.030 A

# IfcFlowSegment: Kabelbro (8)
Type - PredefinedType: CABLELADDERSEGMENT
ePset_Simplebim - Assembly Level: Leaf
Name | In | Length [mm] (mm) = NominalLength (mm) | System code | Height [mm] (mm) = NominalHeight (mm) | Width [mm] (mm) = NominalWidth (mm) | Length (Simplebim) (mm) | Height (Simplebim) (mm) | Width (Simplebim) (mm) | Splitting | Group
Kabelbro | Nivå C | 9376.71 | 4111 | 60 | 600 | 9376.71 | 60 | 600 | ORIGINAL | Bæresystem for elkraft
Kabelbro | Nivå C | 490 | 4113-A | 60 | 300 | 460 | 300 | 60 | ORIGINAL | Armaturskinne
Kabelbro | Nivå D | 1127.02 | 410 | 60 | 300 | 1127.02 | 60 | 300 | ORIGINAL | Bæresystem generelt
Kabelbro | Nivå D | 540 | 410 | 60 | 300 | 540 | 300 | 60 | ORIGINAL | Bæresystem generelt
Kabelbro | Nivå D | 10126 | 410 | 60 | 300 | 10126 | 60 | 300 | ORIGINAL | Bæresystem generelt
Kabelbro | Nivå C |  | 4111 |  |  | 6329 | 30 | 600 | RESULT | Bæresystem for elkraft
Kabelbro | Nivå C |  | 410 |  |  | 3194 | 60 | 600 | RESULT | Bæresystem generelt
Kabelbro | Nivå C |  | 410 |  |  | 600 | 60 | 314 | RESULT | Bæresystem generelt

# IfcFlowSegment: Rektangulær kanal
In: Nivå C
Type - Description: Rektangulær kanal, forsinket stål; PredefinedType: RIGIDSEGMENT
ePset_SimplebimBasicQuantities - Height (Simplebim): 323.5 mm; Width (Simplebim): 650 mm; Length (Simplebim): 1550 mm
ePset_Simplebim - Assembly Level: Leaf
ePset_LocationTool - Splitting: ORIGINAL
Group: +JU=360.010 A

# IfcFlowSegment: SSt (2)
In: Nivå C
Type - PredefinedType: RIGIDSEGMENT
ePset_Simplebim - Assembly Level: Leaf
MagiCAD Pset_Pipe - SystemType: 33 Brannslokking våt; SystemClass: Fire Protection Wet; Material: Rustfritt stål - systemrør; SystemName: 33= Våt Kopi 39; User Code: SSt
ePset_SimplebimBasicQuantities - Height (Simplebim): 54 mm; Width (Simplebim): 54 mm
Group: 33= Våt Kopi 39
Name | Splitting | Length (Simplebim) (mm)
SSt | ORIGINAL | 993 | MagiCAD Pset_Heating - v_SizingFlow_ms: 0 m/s; pTot_SizingFlow_kPa: 0 Pa; dpTot_SizingFlow_kPa: 0 Pa; MagiCAD Pset_Water - dpTot_SizingFlow_kPa: 0 Pa; pTot_SizingFlow_kPa: 0 Pa; v_SizingFlow_ms: 0 m/s; MagiCAD Pset_Pipe - Insulation_thickness_mm: 0 mm; qv_SizingFlow_ls: 0 m3/s; Length_mm: 992.965 mm; ConnectionSize_mm: 54 mm
SSt | RESULT | 341

# IfcFlowSegment: Stålrør normaltykke (430)
Type - PredefinedType: RIGIDSEGMENT
Classification: UB3.144613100 Not defined (NS3420)
MagiCAD Pset_Pipe - NationalCode: UB3.144613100; Product variable 1: DN; User Code: DN; Material: Stålrør normaltykke
ePset_Simplebim - Assembly Level: Leaf
Name | In | Length_mm (mm) | SystemClass | SystemName = Group | SystemType | Insulation_thickness_mm (mm) = qv_SizingFlow_ls (m3/s) = MagiCAD Pset_Heating, v_SizingFlow_ms (m/s) = MagiCAD Pset_Heating, pTot_SizingFlow_kPa (Pa) = MagiCAD Pset_Heating, dpTot_SizingFlow_kPa (Pa) = MagiCAD Pset_Water, dpTot_SizingFlow_kPa (Pa) = MagiCAD Pset_Water, pTot_SizingFlow_kPa (Pa) = MagiCAD Pset_Water, v_SizingFlow_ms (m/s) | ConnectionSize_mm (mm) | Splitting | Length (Simplebim) (mm) | Height (Simplebim) (mm) | Width (Simplebim) (mm)
4 x Stålrør normaltykke | Nivå C | 37.298 | Fire Protection Wet | +TS=332.002 | SPRINKEL | 0 | 25 | ORIGINAL | 37.3 | 33.8 | 33.8
4 x Stålrør normaltykke | Nivå C | 2937.4 | Fire Protection Wet | +TS=332.002 | SPRINKEL | 0 | 25 | ORIGINAL | 2937.4 | 33.8 | 33.8
4 x Stålrør normaltykke | Nivå C | 28.848 | Fire Protection Wet | +TS=332.002 | SPRINKEL | 0 | 25 | ORIGINAL | 33.8 | 28.8 | 33.8
Stålrør normaltykke | Nivå C | 82 | Undefined |  | Undefined | 0 | 80 | ORIGINAL | 82.2 | 89 | 89
Stålrør normaltykke | Nivå C | 2376.26 | Fire Protection Wet | +TS=332.005 | SPRINKEL | 0 | 32 | ORIGINAL | 2376.3 | 42.4 | 42.4
Stålrør normaltykke | Nivå C | 625.8 | Fire Protection Wet | +TS=332.005 | SPRINKEL | 0 | 32 | ORIGINAL | 625.8 | 42.4 | 42.4
Stålrør normaltykke | Nivå C | 249.445 | Fire Protection Wet | +TS=332.005 | SPRINKEL | 0 | 40 | ORIGINAL | 248.9 | 48.2 | 48.2
Stålrør normaltykke | Nivå C | 603.2 | Fire Protection Wet | +TS=332.005 | SPRINKEL | 0 | 40 | ORIGINAL | 603.3 | 48.2 | 48.2
Stålrør normaltykke | Nivå C | 457.6 | Fire Protection Wet | +TS=332.005 | SPRINKEL | 0 | 25 | ORIGINAL | 458.3 | 33.8 | 33.8
Stålrør normaltykke | Nivå C | 9067.06 | Fire Protection Wet | +TS=332.002 | SPRINKEL | 0 | 100 | ORIGINAL | 9067.1 | 114.2 | 114.2
27 x Stålrør normaltykke | Nivå C | 80.848 | Fire Protection Wet | +TS=332.005 | SPRINKEL | 0 | 25 | ORIGINAL | 80.8 | 33.8 | 33.8
2 x Stålrør normaltykke | Nivå C | 2937.4 | Fire Protection Wet | +TS=332.005 | SPRINKEL | 0 | 32 | ORIGINAL | 2937.4 | 42.4 | 42.4
11 x Stålrør normaltykke | Nivå C | 2932.4 | Fire Protection Wet | +TS=332.005 | SPRINKEL | 0 | 32 | ORIGINAL | 2932.4 | 42.4 | 42.4
Stålrør normaltykke | Nivå C | 1130.12 | Fire Protection Wet | +TS=332.005 | SPRINKEL | 0 | 40 | ORIGINAL | 1130.4 | 48.2 | 48.2
Stålrør normaltykke | Nivå C | 209.615 | Fire Protection Wet | +TS=332.005 | SPRINKEL | 0 | 32 | ORIGINAL | 209.6 | 42.4 | 42.4
Stålrør normaltykke | Nivå C | 427.407 | Fire Protection Wet | +TS=332.005 | SPRINKEL | 0 | 32 | ORIGINAL | 426.7 | 42.4 | 42.4
Stålrør normaltykke | Nivå C | 1422.41 | Fire Protection Wet | +TS=332.005 | SPRINKEL | 0 | 32 | ORIGINAL | 1422.2 | 42.4 | 42.4
Stålrør normaltykke | Nivå C | 1427.41 | Fire Protection Wet | +TS=332.005 | SPRINKEL | 0 | 32 | ORIGINAL | 1427.4 | 42.4 | 42.4
Stålrør normaltykke | Nivå C | 2442.39 | Fire Protection Wet | +TS=332.005 | SPRINKEL | 0 | 32 | ORIGINAL | 2442.4 | 42.4 | 42.4
Stålrør normaltykke | Nivå C | 1437.39 | Fire Protection Wet | +TS=332.005 | SPRINKEL | 0 | 32 | ORIGINAL | 1437.4 | 42.4 | 42.4
Stålrør normaltykke | Nivå C | 1442.39 | Fire Protection Wet | +TS=332.005 | SPRINKEL | 0 | 32 | ORIGINAL | 1442.5 | 42.4 | 42.4
Stålrør normaltykke | Nivå C | 204.47 | Fire Protection Wet | +TS=332.005 | SPRINKEL | 0 | 32 | ORIGINAL | 204.5 | 42.4 | 42.4
Stålrør normaltykke | Nivå C | 2428.2 | Fire Protection Wet | +TS=332.005 | SPRINKEL | 0 | 32 | ORIGINAL | 2428.2 | 42.4 | 42.4
Stålrør normaltykke | Nivå C | 203.886 | Fire Protection Wet | +TS=332.005 | SPRINKEL | 0 | 32 | ORIGINAL | 204.5 | 42.4 | 42.4
Stålrør normaltykke | Nivå C | 218.179 | Fire Protection Wet | +TS=332.005 | SPRINKEL | 0 | 32 | ORIGINAL | 217.6 | 42.4 | 42.4
Stålrør normaltykke | Nivå C | 180.926 | Fire Protection Wet | +TS=332.005 | SPRINKEL | 0 | 32 | ORIGINAL | 180.9 | 42.4 | 42.4
Stålrør normaltykke | Nivå C | 2665.91 | Fire Protection Wet | +TS=332.005 | SPRINKEL | 0 | 32 | ORIGINAL | 2665.9 | 42.4 | 42.4
Stålrør normaltykke | Nivå C | 2641.62 | Fire Protection Wet | +TS=332.005 | SPRINKEL | 0 | 32 | ORIGINAL | 2642.2 | 42.4 | 42.4
Stålrør normaltykke | Nivå C | 2688.87 | Fire Protection Wet | +TS=332.005 | SPRINKEL | 0 | 32 | ORIGINAL | 2688.9 | 42.4 | 42.4
Stålrør normaltykke | Nivå C | 430 | Fire Protection Wet | +TS=332.005 | SPRINKEL | 0 | 32 | ORIGINAL | 430 | 42.4 | 42.4
Stålrør normaltykke | Nivå C | 2424.63 | Fire Protection Wet | +TS=332.005 | SPRINKEL | 0 | 32 | ORIGINAL | 2425 | 42.4 | 42.4
Stålrør normaltykke | Nivå C | 416.372 | Fire Protection Wet | +TS=332.005 | SPRINKEL | 0 | 32 | ORIGINAL | 416.4 | 42.4 | 42.4
Stålrør normaltykke | Nivå C | 2101.54 | Fire Protection Wet | +TS=332.005 | SPRINKEL | 0 | 32 | ORIGINAL | 2102.5 | 42.4 | 42.4
Stålrør normaltykke | Nivå C | 2602.25 | Fire Protection Wet | +TS=332.005 | SPRINKEL | 0 | 32 | ORIGINAL | 2602.3 | 42.4 | 42.4
Stålrør normaltykke | Nivå C | 415.2 | Fire Protection Wet | +TS=332.005 | SPRINKEL | 0 | 32 | ORIGINAL | 415.2 | 42.4 | 42.4
Stålrør normaltykke | Nivå C | 206.404 | Fire Protection Wet | +TS=332.005 | SPRINKEL | 0 | 32 | ORIGINAL | 206.4 | 42.4 | 42.4
Stålrør normaltykke | Nivå C | 317.6 | Fire Protection Wet | +TS=332.005 | SPRINKEL | 0 | 25 | ORIGINAL | 317.9 | 33.8 | 33.8
Stålrør normaltykke | Nivå C | 247.004 | Fire Protection Wet | +TS=332.005 | SPRINKEL | 0 | 32 | ORIGINAL | 246.8 | 42.4 | 42.4
Stålrør normaltykke | Nivå C | 431.411 | Fire Protection Wet | +TS=332.005 | SPRINKEL | 0 | 32 | ORIGINAL | 430.8 | 42.4 | 42.4
2 x Stålrør normaltykke | Nivå C | 78.848 | Fire Protection Wet | +TS=332.005 | SPRINKEL | 0 | 25 | ORIGINAL | 78.8 | 33.8 | 33.8
Stålrør normaltykke | Nivå C | 2448.36 | Fire Protection Wet | +TS=332.005 | SPRINKEL | 0 | 32 | ORIGINAL | 2448.4 | 42.4 | 42.4
Stålrør normaltykke | Nivå C | 312.4 | Fire Protection Wet | +TS=332.005 | SPRINKEL | 0 | 25 | ORIGINAL | 312.4 | 33.8 | 33.8
Stålrør normaltykke | Nivå C | 84.309 | Fire Protection Wet | +TS=332.005 | SPRINKEL | 0 | 25 | ORIGINAL | 83.9 | 33.8 | 33.8
Stålrør normaltykke | Nivå C | 248.848 | Fire Protection Wet | +TS=332.005 | SPRINKEL | 0 | 25 | ORIGINAL | 248.8 | 33.8 | 33.8
Stålrør normaltykke | Nivå C | 736.955 | Fire Protection Wet | +TS=332.005 | SPRINKEL | 0 | 40 | ORIGINAL | 737 | 48.2 | 48.2
Stålrør normaltykke | Nivå C | 95.8 | Fire Protection Wet | +TS=332.005 | SPRINKEL | 0 | 32 | ORIGINAL | 95.8 | 42.4 | 42.4
Stålrør normaltykke | Nivå C | 399.241 | Fire Protection Wet | +TS=332.005 | SPRINKEL | 0 | 32 | ORIGINAL | 398.8 | 42.4 | 42.4
Stålrør normaltykke | Nivå C | 204.47 | Fire Protection Wet | +TS=332.005 | SPRINKEL | 0 | 40 | ORIGINAL | 203.5 | 48.2 | 48.2
Stålrør normaltykke | Nivå C | 3197 | Fire Protection Wet | +TU=332.003-NZ0004 | SPRINKEL | 0 | 80 | ORIGINAL | 3197 | 89 | 89
Stålrør normaltykke | Nivå D | 346.2 | Fire Protection Wet | +TS=332.007 - 1 (10) | SPRINKEL | 0 | 65 | ORIGINAL | 345.7 | 76 | 76
Stålrør normaltykke | Nivå D | 304.538 | Fire Protection Wet | +TS=332.008 | SPRINKEL | 0 | 25 | ORIGINAL | 303.8 | 33.8 | 33.8
Stålrør normaltykke | Nivå D | 31.365 | Fire Protection Wet | +TS=332.008 | SPRINKEL | 0 | 25 | ORIGINAL | 33.8 | 31.2 | 33.8
Stålrør normaltykke | Nivå D | 98.928 | Fire Protection Wet | +TS=332.008 | SPRINKEL | 0 | 25 | ORIGINAL | 98.9 | 33.8 | 33.8
Stålrør normaltykke | Nivå D | 174.132 | Undefined |  | Undefined | 0 | 25 | ORIGINAL | 173.9 | 33.8 | 33.8
Stålrør normaltykke | Nivå D | 80.107 | Undefined |  | Undefined | 0 | 25 | ORIGINAL | 79.6 | 33.8 | 33.8
Stålrør normaltykke | Nivå D | 42.152 | Fire Protection Wet | +TS=332.007 - 1 (10) | SPRINKEL | 0 | 25 | ORIGINAL | 42.3 | 33.8 | 33.8
Stålrør normaltykke | Nivå D | 20.344 | Fire Protection Wet | +TS=332.008 | SPRINKEL | 0 | 25 | ORIGINAL | 33.8 | 19.9 | 33.8
Stålrør normaltykke | Nivå D | 51.77 | Fire Protection Wet | +TS=332.007 - 1 (10) | SPRINKEL | 0 | 25 | ORIGINAL | 52.3 | 33.8 | 33.8
Stålrør normaltykke | Nivå D | 99.045 | Undefined |  | Undefined | 0 | 25 | ORIGINAL | 98.9 | 33.8 | 33.8
2 x Stålrør normaltykke | Nivå D | 480.768 | Fire Protection Wet | +TS=332.007 - 1 (10) | SPRINKEL | 0 | 25 | ORIGINAL | 480.9 | 33.8 | 33.8
Stålrør normaltykke | Nivå D | 1712 | Fire Protection Wet | +TS=332.007 - 1 (10) | SPRINKEL | 0 | 25 | ORIGINAL | 1712 | 33.8 | 33.8
Stålrør normaltykke | Nivå D | 332.961 | Fire Protection Wet | +TS=332.007 - 1 (10) | SPRINKEL | 0 | 25 | ORIGINAL | 332.6 | 33.8 | 33.8
Stålrør normaltykke | Nivå D | 486.641 | Fire Protection Wet | +TS=332.007 - 1 (10) | SPRINKEL | 0 | 25 | ORIGINAL | 487.2 | 33.8 | 33.8
Stålrør normaltykke | Nivå D | 473.879 | Fire Protection Wet | +TS=332.007 - 1 (10) | SPRINKEL | 0 | 25 | ORIGINAL | 474.5 | 33.8 | 33.8
Stålrør normaltykke | Nivå D | 2521.72 | Fire Protection Wet | +TS=332.007 - 1 (10) | SPRINKEL | 0 | 25 | ORIGINAL | 2522.4 | 33.8 | 33.8
Stålrør normaltykke | Nivå D | 128.619 | Fire Protection Wet | +TS=332.007 - 1 (10) | SPRINKEL | 0 | 25 | ORIGINAL | 128.8 | 33.8 | 33.8
Stålrør normaltykke | Nivå D | 22.355 | Fire Protection Wet | +TS=332.007 - 1 (10) | SPRINKEL | 0 | 25 | ORIGINAL | 22.5 | 33.8 | 33.8
Stålrør normaltykke | Nivå D | 64.631 | Fire Protection Wet | +TS=332.007 - 1 (10) | SPRINKEL | 0 | 25 | ORIGINAL | 65.3 | 33.8 | 33.8
3 x Stålrør normaltykke | Nivå D | 146.848 | Fire Protection Wet | +TS=332.007 - 1 (10) | SPRINKEL | 0 | 25 | ORIGINAL | 147.2 | 33.8 | 33.8
Stålrør normaltykke | Nivå D | 91.557 | Fire Protection Wet | +TS=332.007 - 1 (10) | SPRINKEL | 0 | 25 | ORIGINAL | 92.4 | 33.8 | 33.8
Stålrør normaltykke | Nivå D | 13.905 | Fire Protection Wet | +TS=332.007 - 1 (10) | SPRINKEL | 0 | 25 | ORIGINAL | 33.8 | 14.4 | 33.8
Stålrør normaltykke | Nivå D | 90.84 | Fire Protection Wet | +TS=332.007 - 1 (10) | SPRINKEL | 0 | 25 | ORIGINAL | 91.4 | 33.8 | 33.8
Stålrør normaltykke | Nivå D | 14.009 | Fire Protection Wet | +TS=332.007 - 1 (10) | SPRINKEL | 0 | 25 | ORIGINAL | 33.8 | 14.4 | 33.8
Stålrør normaltykke | Nivå D | 146.838 | Fire Protection Wet | +TS=332.007 - 1 (10) | SPRINKEL | 0 | 25 | ORIGINAL | 147.2 | 33.8 | 33.8
Stålrør normaltykke | Nivå D | 58.255 | Fire Protection Wet | +TS=332.007 - 1 (10) | SPRINKEL | 0 | 25 | ORIGINAL | 58 | 33.8 | 33.8
Stålrør normaltykke | Nivå D | 22.399 | Fire Protection Wet | +TS=332.007 - 1 (10) | SPRINKEL | 0 | 25 | ORIGINAL | 22.5 | 33.8 | 33.8
Stålrør normaltykke | Nivå D | 154.995 | Fire Protection Wet | +TS=332.007 - 1 (10) | SPRINKEL | 0 | 25 | ORIGINAL | 154.7 | 33.8 | 33.8
Stålrør normaltykke | Nivå D | 146.804 | Fire Protection Wet | +TS=332.007 - 1 (10) | SPRINKEL | 0 | 25 | ORIGINAL | 147.2 | 33.8 | 33.8
Stålrør normaltykke | Nivå D | 135.854 | Fire Protection Wet | +TS=332.007 - 1 (10) | SPRINKEL | 0 | 25 | ORIGINAL | 135.9 | 33.8 | 33.8
Stålrør normaltykke | Nivå D | 171.198 | Fire Protection Wet | +TS=332.007 - 1 (10) | SPRINKEL | 0 | 25 | ORIGINAL | 171.3 | 33.8 | 33.8
Stålrør normaltykke | Nivå D | 479.511 | Fire Protection Wet | +TS=332.007 - 1 (10) | SPRINKEL | 0 | 25 | ORIGINAL | 480.3 | 33.8 | 33.8
5 x Stålrør normaltykke | Nivå D | 278.348 | Fire Protection Wet | +TS=332.007 - 1 (10) | SPRINKEL | 0 | 25 | ORIGINAL | 277.8 | 33.8 | 33.8
Stålrør normaltykke | Nivå D | 444.798 | Fire Protection Wet | +TS=332.007 - 1 (10) | SPRINKEL | 0 | 25 | ORIGINAL | 444.9 | 33.8 | 33.8
Stålrør normaltykke | Nivå D | 433.848 | Fire Protection Wet | +TS=332.007 - 1 (10) | SPRINKEL | 0 | 25 | ORIGINAL | 434.3 | 33.8 | 33.8
Stålrør normaltykke | Nivå D | 86.848 | Fire Protection Wet | +TS=332.007 - 1 (10) | SPRINKEL | 0 | 25 | ORIGINAL | 86.8 | 33.8 | 33.8
Stålrør normaltykke | Nivå D | 125.298 | Fire Protection Wet | +TS=332.007 - 1 (10) | SPRINKEL | 0 | 25 | ORIGINAL | 125.4 | 33.8 | 33.8
2 x Stålrør normaltykke | Nivå D | 65.298 | Fire Protection Wet | +TS=332.007 - 1 (10) | SPRINKEL | 0 | 25 | ORIGINAL | 65.3 | 33.8 | 33.8
Stålrør normaltykke | Nivå D | 56.848 | Fire Protection Wet | +TS=332.007 - 1 (10) | SPRINKEL | 0 | 25 | ORIGINAL | 56.8 | 33.8 | 33.8
Stålrør normaltykke | Nivå D | 514.333 | Fire Protection Wet | +TS=332.007 - 1 (10) | SPRINKEL | 0 | 25 | ORIGINAL | 513.5 | 33.8 | 33.8
Stålrør normaltykke | Nivå D | 247.348 | Fire Protection Wet | +TS=332.007 - 1 (10) | SPRINKEL | 0 | 25 | ORIGINAL | 247.3 | 33.8 | 33.8
2 x Stålrør normaltykke | Nivå D | 254.798 | Fire Protection Wet | +TS=332.007 - 1 (10) | SPRINKEL | 0 | 25 | ORIGINAL | 255 | 33.8 | 33.8
Stålrør normaltykke | Nivå D | 48.848 | Fire Protection Wet | +TS=332.007 - 1 (10) | SPRINKEL | 0 | 25 | ORIGINAL | 48.6 | 33.8 | 33.8
5 x Stålrør normaltykke | Nivå D | 88.348 | Fire Protection Wet | +TS=332.007 - 1 (10) | SPRINKEL | 0 | 25 | ORIGINAL | 87.6 | 33.8 | 33.8
Stålrør normaltykke | Nivå D | 187.4 | Fire Protection Wet | +TS=332.007 - 1 (10) | SPRINKEL | 0 | 25 | ORIGINAL | 187.1 | 33.8 | 33.8
2 x Stålrør normaltykke | Nivå D | 89.348 | Fire Protection Wet | +TS=332.007 - 1 (10) | SPRINKEL | 0 | 25 | ORIGINAL | 88.8 | 33.8 | 33.8
Stålrør normaltykke | Nivå D | 490.109 | Fire Protection Wet | +TS=332.007 - 1 (10) | SPRINKEL | 0 | 25 | ORIGINAL | 490.1 | 33.8 | 33.8
Stålrør normaltykke | Nivå D | 456.502 | Fire Protection Wet | +TS=332.007 - 1 (10) | SPRINKEL | 0 | 40 | ORIGINAL | 456.5 | 48.2 | 48.2
3 x Stålrør normaltykke | Nivå D | 246.348 | Fire Protection Wet | +TS=332.007 - 1 (10) | SPRINKEL | 0 | 25 | ORIGINAL | 245.7 | 33.8 | 33.8
Stålrør normaltykke | Nivå D | 14.852 | Fire Protection Wet | +TS=332.007 - 1 (10) | SPRINKEL | 0 | 40 | ORIGINAL | 48.2 | 14.6 | 48.2
Stålrør normaltykke | Nivå D | 422.609 | Fire Protection Wet | +TS=332.007 - 1 (10) | SPRINKEL | 0 | 25 | ORIGINAL | 422.7 | 33.8 | 33.8
12 x Stålrør normaltykke | Nivå D | 136.848 | Fire Protection Wet | +TS=332.007 - 1 (10) | SPRINKEL | 0 | 25 | ORIGINAL | 137.4 | 33.8 | 33.8
Stålrør normaltykke | Nivå D | 129.75 | Fire Protection Wet | +TS=332.007 - 1 (10) | SPRINKEL | 0 | 25 | ORIGINAL | 129.8 | 33.8 | 33.8
Stålrør normaltykke | Nivå D | 156.848 | Fire Protection Wet | +TS=332.007 - 1 (10) | SPRINKEL | 0 | 25 | ORIGINAL | 156.8 | 33.8 | 33.8
4 x Stålrør normaltykke | Nivå D | 246.848 | Fire Protection Wet | +TS=332.007 - 1 (10) | SPRINKEL | 0 | 25 | ORIGINAL | 247.3 | 33.8 | 33.8
2 x Stålrør normaltykke | Nivå D | 153.8 | Fire Protection Wet | +TS=332.007 - 1 (10) | SPRINKEL | 0 | 25 | ORIGINAL | 153.8 | 33.8 | 33.8
Stålrør normaltykke | Nivå D | 1132.96 | Fire Protection Wet | +TS=332.007 - 1 (10) | SPRINKEL | 0 | 25 | ORIGINAL | 1132.9 | 33.8 | 33.8
Stålrør normaltykke | Nivå D | 160.459 | Fire Protection Wet | +TS=332.007 - 1 (10) | SPRINKEL | 0 | 25 | ORIGINAL | 160.4 | 33.8 | 33.8
Stålrør normaltykke | Nivå D | 171.409 | Fire Protection Wet | +TS=332.007 - 1 (10) | SPRINKEL | 0 | 25 | ORIGINAL | 171.3 | 33.8 | 33.8
Stålrør normaltykke | Nivå D | 624.259 | Fire Protection Wet | +TS=332.007 - 1 (10) | SPRINKEL | 0 | 40 | ORIGINAL | 623.6 | 48.2 | 48.2
Stålrør normaltykke | Nivå D | 136.845 | Fire Protection Wet | +TS=332.007 - 1 (10) | SPRINKEL | 0 | 25 | ORIGINAL | 137.4 | 33.8 | 33.8
Stålrør normaltykke | Nivå D | 435.527 | Fire Protection Wet | +TS=332.007 - 1 (10) | SPRINKEL | 0 | 25 | ORIGINAL | 435.6 | 33.8 | 33.8
2 x Stålrør normaltykke | Nivå D | 179.136 | Fire Protection Wet | +TS=332.007 - 1 (10) | SPRINKEL | 0 | 25 | ORIGINAL | 178.6 | 33.8 | 33.8
Stålrør normaltykke | Nivå D | 67.75 | Fire Protection Wet | +TS=332.007 - 1 (10) | SPRINKEL | 0 | 25 | ORIGINAL | 67.5 | 33.8 | 33.8
Stålrør normaltykke | Nivå D | 243.8 | Fire Protection Wet | +TS=332.007 - 1 (10) | SPRINKEL | 0 | 25 | ORIGINAL | 243.8 | 33.8 | 33.8
Stålrør normaltykke | Nivå D | 49.054 | Fire Protection Wet | +TS=332.007 - 1 (10) | SPRINKEL | 0 | 32 | ORIGINAL | 49.1 | 42.4 | 42.4
Stålrør normaltykke | Nivå D | 421.566 | Fire Protection Wet | +TS=332.007 - 1 (10) | SPRINKEL | 0 | 25 | ORIGINAL | 422 | 33.8 | 33.8
Stålrør normaltykke | Nivå D | 730.75 | Fire Protection Wet | +TS=332.007 - 1 (10) | SPRINKEL | 0 | 40 | ORIGINAL | 730.7 | 48.2 | 48.2
Stålrør normaltykke | Nivå D | 135.298 | Fire Protection Wet | +TS=332.007 - 1 (10) | SPRINKEL | 0 | 25 | ORIGINAL | 134.9 | 33.8 | 33.8
Stålrør normaltykke | Nivå D | 96.848 | Fire Protection Wet | +TS=332.007 - 1 (10) | SPRINKEL | 0 | 25 | ORIGINAL | 96.9 | 33.8 | 33.8
Stålrør normaltykke | Nivå D | 2.581 | Fire Protection Wet | +TS=332.007 - 1 (10) | SPRINKEL | 0 | 25 | ORIGINAL | 3.3 | 33.8 | 33.8
Stålrør normaltykke | Nivå D | 81.223 | Fire Protection Wet | +TS=332.007 - 1 (10) | SPRINKEL | 0 | 25 | ORIGINAL | 80.8 | 33.8 | 33.8
Stålrør normaltykke | Nivå D | 188.136 | Fire Protection Wet | +TS=332.007 - 1 (10) | SPRINKEL | 0 | 25 | ORIGINAL | 187.6 | 33.8 | 33.8
Stålrør normaltykke | Nivå D | 404.544 | Fire Protection Wet | +TS=332.007 - 1 (10) | SPRINKEL | 0 | 25 | ORIGINAL | 403.9 | 33.8 | 33.8
Stålrør normaltykke | Nivå D | 136.2 | Fire Protection Wet | +TS=332.007 - 1 (10) | SPRINKEL | 0 | 25 | ORIGINAL | 135.9 | 33.8 | 33.8
Stålrør normaltykke | Nivå D | 329.975 | Fire Protection Wet | +TS=332.007 - 1 (10) | SPRINKEL | 0 | 25 | ORIGINAL | 329.8 | 33.8 | 33.8
Stålrør normaltykke | Nivå D | 438.786 | Fire Protection Wet | +TS=332.007 - 1 (10) | SPRINKEL | 0 | 25 | ORIGINAL | 438.8 | 33.8 | 33.8
2 x Stålrør normaltykke | Nivå D | 226.848 | Fire Protection Wet | +TS=332.007 - 1 (10) | SPRINKEL | 0 | 25 | ORIGINAL | 227.1 | 33.8 | 33.8
Stålrør normaltykke | Nivå D | 406.954 | Fire Protection Wet | +TS=332.007 - 1 (10) | SPRINKEL | 0 | 25 | ORIGINAL | 406.9 | 33.8 | 33.8
Stålrør normaltykke | Nivå D | 1062.03 | Fire Protection Wet | +TS=332.007 - 1 (10) | SPRINKEL | 0 | 25 | ORIGINAL | 1062.2 | 33.8 | 33.8
Stålrør normaltykke | Nivå D | 172.4 | Fire Protection Wet | +TS=332.007 - 1 (10) | SPRINKEL | 0 | 25 | ORIGINAL | 172.5 | 33.8 | 33.8
Stålrør normaltykke | Nivå D | 580.025 | Fire Protection Wet | +TS=332.007 - 1 (10) | SPRINKEL | 0 | 25 | ORIGINAL | 580.1 | 33.8 | 33.8
Stålrør normaltykke | Nivå D | 186.848 | Fire Protection Wet | +TS=332.007 - 1 (10) | SPRINKEL | 0 | 25 | ORIGINAL | 187.1 | 33.8 | 33.8
2 x Stålrør normaltykke | Nivå D | 126.825 | Fire Protection Wet | +TS=332.007 - 1 (10) | SPRINKEL | 0 | 25 | ORIGINAL | 127.4 | 33.8 | 33.8
Stålrør normaltykke | Nivå D | 385.727 | Fire Protection Wet | +TS=332.007 - 1 (10) | SPRINKEL | 0 | 25 | ORIGINAL | 385.7 | 33.8 | 33.8
Stålrør normaltykke | Nivå D | 116.25 | Fire Protection Wet | +TS=332.007 - 1 (10) | SPRINKEL | 0 | 25 | ORIGINAL | 116 | 33.8 | 33.8
2 x Stålrør normaltykke | Nivå D | 65.25 | Fire Protection Wet | +TS=332.007 - 1 (10) | SPRINKEL | 0 | 25 | ORIGINAL | 65.3 | 33.8 | 33.8
Stålrør normaltykke | Nivå D | 86.775 | Fire Protection Wet | +TS=332.007 - 1 (10) | SPRINKEL | 0 | 25 | ORIGINAL | 86.8 | 33.8 | 33.8
Stålrør normaltykke | Nivå D | 46.798 | Fire Protection Wet | +TS=332.007 - 1 (10) | SPRINKEL | 0 | 25 | ORIGINAL | 46.6 | 33.8 | 33.8
Stålrør normaltykke | Nivå D | 1899.24 | Fire Protection Wet | +TS=332.007 - 1 (10) | SPRINKEL | 0 | 40 | ORIGINAL | 1899.2 | 48.2 | 48.2
Stålrør normaltykke | Nivå D | 826.2 | Fire Protection Wet | +TS=332.007 - 1 (10) | SPRINKEL | 0 | 25 | ORIGINAL | 825.6 | 33.8 | 33.8
Stålrør normaltykke | Nivå D | 19.985 | Fire Protection Wet | +TS=332.007 - 1 (10) | SPRINKEL | 0 | 25 | ORIGINAL | 33.8 | 19.9 | 33.8
Stålrør normaltykke | Nivå D | 846.362 | Fire Protection Wet | +TS=332.007 - 1 (10) | SPRINKEL | 0 | 65 | ORIGINAL | 846 | 76 | 76
Stålrør normaltykke | Nivå D | 157.735 | Fire Protection Wet | +TS=332.007 - 1 (10) | SPRINKEL | 0 | 65 | ORIGINAL | 157.8 | 76 | 76
Stålrør normaltykke | Nivå D | 222.31 | Fire Protection Wet | +TS=332.007 - 1 (10) | SPRINKEL | 0 | 65 | ORIGINAL | 221.6 | 76 | 76
Stålrør normaltykke | Nivå D | 991.873 | Fire Protection Wet | +TS=332.007 - 1 (10) | SPRINKEL | 0 | 40 | ORIGINAL | 992.3 | 48.2 | 48.2
Stålrør normaltykke | Nivå D | 1232.47 | Fire Protection Wet | +TS=332.007 - 1 (10) | SPRINKEL | 0 | 65 | ORIGINAL | 1232.4 | 76 | 76
Stålrør normaltykke | Nivå D | 968.326 | Fire Protection Wet | +TS=332.007 - 1 (10) | SPRINKEL | 0 | 40 | ORIGINAL | 968.3 | 48.2 | 48.2
Stålrør normaltykke | Nivå D | 1000 | Fire Protection Wet | +TS=332.007 - 1 (10) | SPRINKEL | 0 | 40 | ORIGINAL | 1000 | 48.2 | 48.2
Stålrør normaltykke | Nivå D | 468.016 | Fire Protection Wet | +TS=332.007 - 1 (10) | SPRINKEL | 0 | 65 | ORIGINAL | 468 | 76 | 76
Stålrør normaltykke | Nivå D | 142.695 | Fire Protection Wet | +TS=332.007 - 1 (10) | SPRINKEL | 0 | 25 | ORIGINAL | 142.8 | 33.8 | 33.8
Stålrør normaltykke | Nivå D | 62.105 | Fire Protection Wet | +TS=332.007 - 1 (10) | SPRINKEL | 0 | 25 | ORIGINAL | 62.3 | 33.8 | 33.8
Stålrør normaltykke | Nivå D | 1820.47 | Fire Protection Wet | +TS=332.007 - 1 (10) | SPRINKEL | 0 | 25 | ORIGINAL | 1820.5 | 33.8 | 33.8
Stålrør normaltykke | Nivå D | 1017.68 | Fire Protection Wet | +TS=332.007 - 1 (10) | SPRINKEL | 0 | 40 | ORIGINAL | 1017.7 | 48.2 | 48.2
3 x Stålrør normaltykke | Nivå D | 22.4 | Fire Protection Wet | +TS=332.007 - 1 (10) | SPRINKEL | 0 | 25 | ORIGINAL | 22.5 | 33.8 | 33.8
Stålrør normaltykke | Nivå D | 170.302 | Fire Protection Wet | +TS=332.007 - 1 (10) | SPRINKEL | 0 | 25 | ORIGINAL | 169.6 | 33.8 | 33.8
Stålrør normaltykke | Nivå D | 162.851 | Fire Protection Wet | +TS=332.007 - 1 (10) | SPRINKEL | 0 | 40 | ORIGINAL | 163.2 | 48.2 | 48.2
Stålrør normaltykke | Nivå D | 2133.85 | Fire Protection Wet | +TS=332.007 - 1 (10) | SPRINKEL | 0 | 65 | ORIGINAL | 2134.5 | 76 | 76
Stålrør normaltykke | Nivå D | 468.611 | Fire Protection Wet | +TS=332.007 - 1 (10) | SPRINKEL | 0 | 25 | ORIGINAL | 469.4 | 33.8 | 33.8
Stålrør normaltykke | Nivå D | 449.217 | Fire Protection Wet | +TS=332.007 - 1 (10) | SPRINKEL | 0 | 65 | ORIGINAL | 449.2 | 76 | 76
Stålrør normaltykke | Nivå D | 375.43 | Fire Protection Wet | +TS=332.007 - 1 (10) | SPRINKEL | 0 | 25 | ORIGINAL | 374.9 | 33.8 | 33.8
2 x Stålrør normaltykke | Nivå D | 62.4 | Fire Protection Wet | +TS=332.007 - 1 (10) | SPRINKEL | 0 | 25 | ORIGINAL | 62.3 | 33.8 | 33.8
Stålrør normaltykke | Nivå D | 107.695 | Fire Protection Wet | +TS=332.007 - 1 (10) | SPRINKEL | 0 | 25 | ORIGINAL | 108.4 | 33.8 | 33.8
Stålrør normaltykke | Nivå D | 59.05 | Fire Protection Wet | +TS=332.007 - 1 (10) | SPRINKEL | 0 | 25 | ORIGINAL | 59 | 33.8 | 33.8
Stålrør normaltykke | Nivå D | 1001.09 | Fire Protection Wet | +TS=332.007 - 1 (10) | SPRINKEL | 0 | 65 | ORIGINAL | 1001.1 | 76 | 76
Stålrør normaltykke | Nivå D | 215.612 | Fire Protection Wet | +TS=332.007 - 1 (10) | SPRINKEL | 0 | 25 | ORIGINAL | 215.8 | 33.8 | 33.8
Stålrør normaltykke | Nivå D | 614.841 | Fire Protection Wet | +TS=332.007 - 1 (10) | SPRINKEL | 0 | 65 | ORIGINAL | 615 | 76 | 76
Stålrør normaltykke | Nivå D | 2249.96 | Fire Protection Wet | +TS=332.007 - 1 (10) | SPRINKEL | 0 | 25 | ORIGINAL | 2250 | 33.8 | 33.8
Stålrør normaltykke | Nivå D | 132.625 | Fire Protection Wet | +TS=332.007 - 1 (10) | SPRINKEL | 0 | 25 | ORIGINAL | 133.3 | 33.8 | 33.8
3 x Stålrør normaltykke | Nivå D | 52.4 | Fire Protection Wet | +TS=332.007 - 1 (10) | SPRINKEL | 0 | 25 | ORIGINAL | 52.3 | 33.8 | 33.8
Stålrør normaltykke | Nivå D | 79.073 | Fire Protection Wet | +TS=332.007 - 1 (10) | SPRINKEL | 0 | 25 | ORIGINAL | 78.8 | 33.8 | 33.8
Stålrør normaltykke | Nivå D | 235 | Fire Protection Wet | +TS=332.007 - 1 (10) | SPRINKEL | 0 | 25 | ORIGINAL | 235 | 33.8 | 33.8
Stålrør normaltykke | Nivå D | 473.175 | Fire Protection Wet | +TS=332.007 - 1 (10) | SPRINKEL | 0 | 50 | ORIGINAL | 473.2 | 60.2 | 60.2
Stålrør normaltykke | Nivå D | 1013.5 | Fire Protection Wet | +TS=332.007 - 1 (10) | SPRINKEL | 0 | 40 | ORIGINAL | 1014.5 | 48.2 | 48.2
Stålrør normaltykke | Nivå D | 58.446 | Fire Protection Wet | +TS=332.007 - 1 (10) | SPRINKEL | 0 | 40 | ORIGINAL | 58.5 | 48.2 | 48.2
Stålrør normaltykke | Nivå D | 123.8 | Fire Protection Wet | +TS=332.007 - 1 (10) | SPRINKEL | 0 | 25 | ORIGINAL | 124.4 | 33.8 | 33.8
2 x Stålrør normaltykke | Nivå D | 93.2 | Fire Protection Wet | +TS=332.007 - 1 (10) | SPRINKEL | 0 | 40 | ORIGINAL | 93.2 | 48.2 | 48.2
2 x Stålrør normaltykke | Nivå D | 1132.4 | Fire Protection Wet | +TS=332.007 - 1 (10) | SPRINKEL | 0 | 25 | ORIGINAL | 1132.4 | 33.8 | 33.8
Stålrør normaltykke | Nivå D | 196.348 | Fire Protection Wet | +TS=332.007 - 1 (10) | SPRINKEL | 0 | 25 | ORIGINAL | 195.5 | 33.8 | 33.8
Stålrør normaltykke | Nivå D | 245.6 | Fire Protection Wet | +TS=332.007 - 1 (10) | SPRINKEL | 0 | 40 | ORIGINAL | 245.5 | 48.2 | 48.2
Stålrør normaltykke | Nivå D | 377.154 | Fire Protection Wet | +TS=332.007 - 1 (10) | SPRINKEL | 0 | 40 | ORIGINAL | 377 | 48.2 | 48.2
Stålrør normaltykke | Nivå D | 2126.4 | Fire Protection Wet | +TS=332.007 - 1 (10) | SPRINKEL | 0 | 32 | ORIGINAL | 2126.2 | 42.4 | 42.4
Stålrør normaltykke | Nivå D | 739.4 | Fire Protection Wet | +TS=332.007 - 1 (10) | SPRINKEL | 0 | 25 | ORIGINAL | 739.2 | 33.8 | 33.8
Stålrør normaltykke | Nivå D | 50.918 | Fire Protection Wet | +TS=332.007 - 1 (10) | SPRINKEL | 0 | 50 | ORIGINAL | 60.2 | 51.3 | 60.2
2 x Stålrør normaltykke | Nivå D | 339.2 | Fire Protection Wet | +TS=332.007 - 1 (10) | SPRINKEL | 0 | 50 | ORIGINAL | 339.2 | 60.2 | 60.2
Stålrør normaltykke | Nivå D | 490.366 | Fire Protection Wet | +TS=332.007 - 1 (10) | SPRINKEL | 0 | 50 | ORIGINAL | 490.4 | 60.2 | 60.2
2 x Stålrør normaltykke | Nivå D | 149.2 | Fire Protection Wet | +TS=332.007 - 1 (10) | SPRINKEL | 0 | 50 | ORIGINAL | 149.2 | 60.2 | 60.2
Stålrør normaltykke | Nivå D | 54.718 | Fire Protection Wet | +TS=332.007 - 1 (10) | SPRINKEL | 0 | 25 | ORIGINAL | 54.9 | 33.8 | 33.8
2 x Stålrør normaltykke | Nivå D | 47.054 | Fire Protection Wet | +TS=332.007 - 1 (10) | SPRINKEL | 0 | 25 | ORIGINAL | 46.6 | 33.8 | 33.8
4 x Stålrør normaltykke | Nivå D | 436.348 | Fire Protection Wet | +TS=332.007 - 1 (10) | SPRINKEL | 0 | 25 | ORIGINAL | 435.6 | 33.8 | 33.8
Stålrør normaltykke | Nivå D | 957.4 | Fire Protection Wet | +TS=332.007 - 1 (10) | SPRINKEL | 0 | 50 | ORIGINAL | 956.8 | 60.2 | 60.2
Stålrør normaltykke | Nivå D | 107.4 | Fire Protection Wet | +TS=332.007 - 1 (10) | SPRINKEL | 0 | 25 | ORIGINAL | 106.7 | 33.8 | 33.8
Stålrør normaltykke | Nivå D | 114.9 | Fire Protection Wet | +TS=332.007 - 1 (10) | SPRINKEL | 0 | 50 | ORIGINAL | 114.9 | 60.2 | 60.2
Stålrør normaltykke | Nivå D | 43.954 | Fire Protection Wet | +TS=332.007 - 1 (10) | SPRINKEL | 0 | 40 | ORIGINAL | 48.2 | 44.5 | 48.2
4 x Stålrør normaltykke | Nivå D | 3.669 | Fire Protection Wet | +TS=332.007 - 1 (10) | SPRINKEL | 0 | 25 | ORIGINAL | 4.5 | 33.8 | 33.8
Stålrør normaltykke | Nivå D | 519.825 | Fire Protection Wet | +TS=332.007 - 1 (10) | SPRINKEL | 0 | 65 | ORIGINAL | 519.5 | 76 | 76
Stålrør normaltykke | Nivå D | 1137.4 | Fire Protection Wet | +TS=332.007 - 1 (10) | SPRINKEL | 0 | 25 | ORIGINAL | 1137.4 | 33.8 | 33.8
Stålrør normaltykke | Nivå D | 65.9 | Fire Protection Wet | +TS=332.007 - 1 (10) | SPRINKEL | 0 | 25 | ORIGINAL | 66.1 | 33.8 | 33.8
2 x Stålrør normaltykke | Nivå D | 2132.4 | Fire Protection Wet | +TS=332.007 - 1 (10) | SPRINKEL | 0 | 50 | ORIGINAL | 2132.2 | 60.2 | 60.2
2 x Stålrør normaltykke | Nivå D | 1131.83 | Fire Protection Wet | +TS=332.007 - 1 (10) | SPRINKEL | 0 | 25 | ORIGINAL | 1132.4 | 33.8 | 33.8
Stålrør normaltykke | Nivå D | 976.475 | Fire Protection Wet | +TS=332.007 - 1 (10) | SPRINKEL | 0 | 25 | ORIGINAL | 976.3 | 33.8 | 33.8
Stålrør normaltykke | Nivå D | 114.4 | Fire Protection Wet | +TS=332.007 - 1 (10) | SPRINKEL | 0 | 32 | ORIGINAL | 114.4 | 42.4 | 42.4
Stålrør normaltykke | Nivå D | 165.519 | Fire Protection Wet | +TS=332.007 - 1 (10) | SPRINKEL | 0 | 50 | ORIGINAL | 165.5 | 60.2 | 60.2
Stålrør normaltykke | Nivå D | 285.585 | Fire Protection Wet | +TS=332.007 - 1 (10) | SPRINKEL | 0 | 25 | ORIGINAL | 286.2 | 33.8 | 33.8
Stålrør normaltykke | Nivå D | 392.05 | Fire Protection Wet | +TS=332.007 - 1 (10) | SPRINKEL | 0 | 25 | ORIGINAL | 392.4 | 33.8 | 33.8
Stålrør normaltykke | Nivå D | 30.969 | Fire Protection Wet | +TS=332.007 - 1 (10) | SPRINKEL | 0 | 65 | ORIGINAL | 31.4 | 76 | 76
Stålrør normaltykke | Nivå D | 450.8 | Fire Protection Wet | +TS=332.007 - 1 (10) | SPRINKEL | 0 | 65 | ORIGINAL | 450.8 | 76 | 76
Stålrør normaltykke | Nivå D | 1132.4 | Fire Protection Wet | +TS=332.007 - 1 (10) | SPRINKEL | 0 | 65 | ORIGINAL | 1132.4 | 76 | 76
2 x Stålrør normaltykke | Nivå D | 132.4 | Fire Protection Wet | +TS=332.007 - 1 (10) | SPRINKEL | 0 | 25 | ORIGINAL | 132.4 | 33.8 | 33.8
Stålrør normaltykke | Nivå D | 407.4 | Fire Protection Wet | +TS=332.007 - 1 (10) | SPRINKEL | 0 | 25 | ORIGINAL | 406.9 | 33.8 | 33.8
Stålrør normaltykke | Nivå D | 41.762 | Fire Protection Wet | +TS=332.007 - 1 (10) | SPRINKEL | 0 | 25 | ORIGINAL | 42.3 | 33.8 | 33.8
Stålrør normaltykke | Nivå D | 77.119 | Fire Protection Wet | +TS=332.007 - 1 (10) | SPRINKEL | 0 | 25 | ORIGINAL | 76.8 | 33.8 | 33.8
Stålrør normaltykke | Nivå D | 232.2 | Fire Protection Wet | +TS=332.007 - 1 (10) | SPRINKEL | 0 | 25 | ORIGINAL | 232.3 | 33.8 | 33.8
Stålrør normaltykke | Nivå D | 224.642 | Fire Protection Wet | +TS=332.007 - 1 (10) | SPRINKEL | 0 | 25 | ORIGINAL | 225.2 | 33.8 | 33.8
Stålrør normaltykke | Nivå D | 1581.76 | Fire Protection Wet | +TS=332.007 - 1 (10) | SPRINKEL | 0 | 32 | ORIGINAL | 1582.2 | 42.4 | 42.4
Stålrør normaltykke | Nivå D | 792.243 | Fire Protection Wet | +TS=332.007 - 1 (10) | SPRINKEL | 0 | 25 | ORIGINAL | 792.4 | 33.8 | 33.8
Stålrør normaltykke | Nivå D | 40.889 | Fire Protection Wet | +TS=332.007 - 1 (10) | SPRINKEL | 0 | 50 | ORIGINAL | 40.7 | 60.2 | 60.2
Stålrør normaltykke | Nivå D | 485.111 | Fire Protection Wet | +TS=332.007 - 1 (10) | SPRINKEL | 0 | 50 | ORIGINAL | 485.1 | 60.2 | 60.2
Stålrør normaltykke | Nivå D | 151.6 | Fire Protection Wet | +TS=332.007 - 1 (10) | SPRINKEL | 0 | 40 | ORIGINAL | 151.9 | 48.2 | 48.2
Stålrør normaltykke | Nivå D | 180.804 | Fire Protection Wet | +TS=332.007 - 1 (10) | SPRINKEL | 0 | 50 | ORIGINAL | 180.8 | 60.2 | 60.2
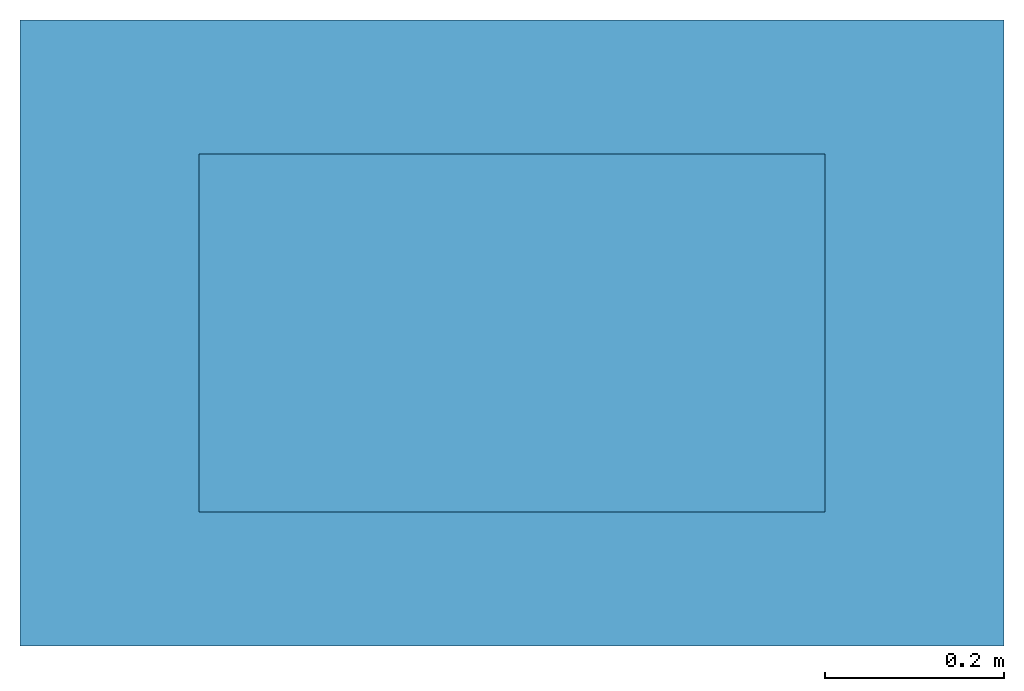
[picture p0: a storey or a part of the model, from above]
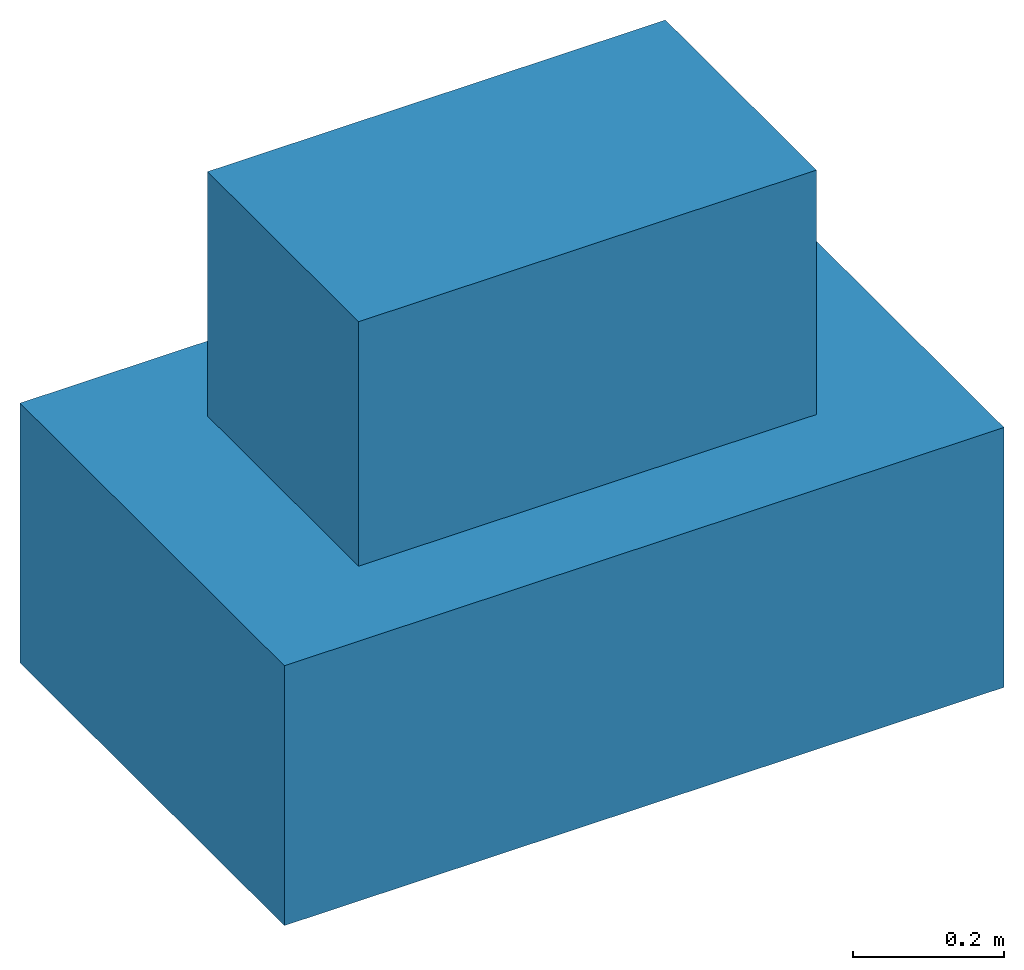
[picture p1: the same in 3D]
Properties of the parts of a building model (IFC2X3), part 4 of 5

# IfcFlowSegment: Stålrør normaltykke (430)
Name | In | Length_mm (mm) | SystemClass | SystemName = Group | SystemType | Insulation_thickness_mm (mm) = qv_SizingFlow_ls (m3/s) = MagiCAD Pset_Heating, v_SizingFlow_ms (m/s) = MagiCAD Pset_Heating, pTot_SizingFlow_kPa (Pa) = MagiCAD Pset_Heating, dpTot_SizingFlow_kPa (Pa) = MagiCAD Pset_Water, dpTot_SizingFlow_kPa (Pa) = MagiCAD Pset_Water, pTot_SizingFlow_kPa (Pa) = MagiCAD Pset_Water, v_SizingFlow_ms (m/s) | ConnectionSize_mm (mm) | Splitting | Length (Simplebim) (mm) | Height (Simplebim) (mm) | Width (Simplebim) (mm)
Stålrør normaltykke | Nivå D | 132.4 | Fire Protection Wet | +TS=332.007 - 1 (10) | SPRINKEL | 0 | 50 | ORIGINAL | 132.4 | 60.2 | 60.2
Stålrør normaltykke | Nivå D | 277.135 | Fire Protection Wet | +TS=332.007 - 1 (10) | SPRINKEL | 0 | 25 | ORIGINAL | 277.4 | 33.8 | 33.8
Stålrør normaltykke | Nivå D | 992.026 | Fire Protection Wet | +TS=332.007 - 1 (10) | SPRINKEL | 0 | 65 | ORIGINAL | 992.4 | 76 | 76
Stålrør normaltykke | Nivå D | 164.059 | Fire Protection Wet | +TS=332.007 - 1 (10) | SPRINKEL | 0 | 65 | ORIGINAL | 164.5 | 76 | 76
2 x Stålrør normaltykke | Nivå D | 173.2 | Fire Protection Wet | +TS=332.007 - 1 (10) | SPRINKEL | 0 | 40 | ORIGINAL | 173.2 | 48.2 | 48.2
Stålrør normaltykke | Nivå D | 441.55 | Fire Protection Wet | +TS=332.007 - 1 (10) | SPRINKEL | 0 | 40 | ORIGINAL | 442.3 | 48.2 | 48.2
Stålrør normaltykke | Nivå D | 1629.59 | Fire Protection Wet | +TS=332.007 - 1 (10) | SPRINKEL | 0 | 25 | ORIGINAL | 1629.7 | 33.8 | 33.8
Stålrør normaltykke | Nivå D | 2320.4 | Fire Protection Wet | +TS=332.007 - 1 (10) | SPRINKEL | 0 | 40 | ORIGINAL | 2319.6 | 48.2 | 48.2
Stålrør normaltykke | Nivå D | 255.798 | Fire Protection Wet | +TS=332.007 - 1 (10) | SPRINKEL | 0 | 25 | ORIGINAL | 256.3 | 33.8 | 33.8
Stålrør normaltykke | Nivå D | 913.719 | Fire Protection Wet | +TS=332.007 - 1 (10) | SPRINKEL | 0 | 25 | ORIGINAL | 913.9 | 33.8 | 33.8
Stålrør normaltykke | Nivå D | 820.537 | Fire Protection Wet | +TS=332.007 - 1 (10) | SPRINKEL | 0 | 25 | ORIGINAL | 819.5 | 33.8 | 33.8
Stålrør normaltykke | Nivå D | 121.5 | Fire Protection Wet | +TS=332.007 - 1 (10) | SPRINKEL | 0 | 40 | ORIGINAL | 121.5 | 48.2 | 48.2
Stålrør normaltykke | Nivå D | 408.404 | Fire Protection Wet | +TS=332.007 - 1 (10) | SPRINKEL | 0 | 25 | ORIGINAL | 407.7 | 33.8 | 33.8
Stålrør normaltykke | Nivå D | 987.914 | Fire Protection Wet | +TS=332.007 - 1 (10) | SPRINKEL | 0 | 65 | ORIGINAL | 987.6 | 76 | 76
Stålrør normaltykke | Nivå D | 576.854 | Fire Protection Wet | +TS=332.007 - 1 (10) | SPRINKEL | 0 | 65 | ORIGINAL | 576.9 | 76 | 76
Stålrør normaltykke | Nivå D | 394.259 | Fire Protection Wet | +TS=332.007 - 1 (10) | SPRINKEL | 0 | 40 | ORIGINAL | 394.3 | 48.2 | 48.2
Stålrør normaltykke | Nivå D | 96.798 | Fire Protection Wet | +TS=332.007 - 1 (10) | SPRINKEL | 0 | 25 | ORIGINAL | 96.9 | 33.8 | 33.8
Stålrør normaltykke | Nivå D | 1062.4 | Fire Protection Wet | +TS=332.007 - 1 (10) | SPRINKEL | 0 | 25 | ORIGINAL | 1062.2 | 33.8 | 33.8
Stålrør normaltykke | Nivå D | 2119.45 | Fire Protection Wet | +TS=332.007 - 1 (10) | SPRINKEL | 0 | 25 | ORIGINAL | 2120.3 | 33.8 | 33.8
Stålrør normaltykke | Nivå D | 99.05 | Fire Protection Wet | +TS=332.007 - 1 (10) | SPRINKEL | 0 | 25 | ORIGINAL | 98.9 | 33.8 | 33.8
Stålrør normaltykke | Nivå D | 1400.75 | Fire Protection Wet | +TS=332.007 - 1 (10) | SPRINKEL | 0 | 40 | ORIGINAL | 1400.7 | 48.2 | 48.2
Stålrør normaltykke | Nivå D | 279.348 | Fire Protection Wet | +TS=332.007 - 1 (10) | SPRINKEL | 0 | 25 | ORIGINAL | 279.1 | 33.8 | 33.8
Stålrør normaltykke | Nivå D | 470.239 | Fire Protection Wet | +TS=332.007 - 1 (10) | SPRINKEL | 0 | 25 | ORIGINAL | 470 | 33.8 | 33.8
Stålrør normaltykke | Nivå D | 20.748 | Fire Protection Wet | +TS=332.007 - 1 (10) | SPRINKEL | 0 | 40 | ORIGINAL | 48.2 | 20.8 | 48.2
Stålrør normaltykke | Nivå D | 66.037 | Fire Protection Wet | +TS=332.007 - 1 (10) | SPRINKEL | 0 | 25 | ORIGINAL | 66.1 | 33.8 | 33.8
Stålrør normaltykke | Nivå D | 2540.85 | Fire Protection Wet | +TS=332.007 - 1 (10) | SPRINKEL | 0 | 40 | ORIGINAL | 2540.9 | 48.2 | 48.2
Stålrør normaltykke | Nivå D | 437.348 | Fire Protection Wet | +TS=332.007 - 1 (10) | SPRINKEL | 0 | 25 | ORIGINAL | 437 | 33.8 | 33.8
2 x Stålrør normaltykke | Nivå D | 286.798 | Fire Protection Wet | +TS=332.007 - 1 (10) | SPRINKEL | 0 | 25 | ORIGINAL | 286.6 | 33.8 | 33.8
Stålrør normaltykke | Nivå D | 166.584 | Fire Protection Wet | +TS=332.007 - 1 (10) | SPRINKEL | 0 | 25 | ORIGINAL | 167.3 | 33.8 | 33.8
Stålrør normaltykke | Nivå D | 136.852 | Fire Protection Wet | +TS=332.007 - 1 (10) | SPRINKEL | 0 | 25 | ORIGINAL | 137.4 | 33.8 | 33.8
Stålrør normaltykke | Nivå D | 710.75 | Fire Protection Wet | +TS=332.007 - 1 (10) | SPRINKEL | 0 | 40 | ORIGINAL | 710.7 | 48.2 | 48.2
Stålrør normaltykke | Nivå D | 950.209 | Fire Protection Wet | +TS=332.007 - 1 (10) | SPRINKEL | 0 | 25 | ORIGINAL | 950.2 | 33.8 | 33.8
Stålrør normaltykke | Nivå D | 29.791 | Fire Protection Wet | +TS=332.007 - 1 (10) | SPRINKEL | 0 | 25 | ORIGINAL | 33.8 | 29.9 | 33.8
Stålrør normaltykke | Nivå D | 2529.3 | Fire Protection Wet | +TS=332.007 - 1 (10) | SPRINKEL | 0 | 50 | ORIGINAL | 2529.3 | 60.2 | 60.2
Stålrør normaltykke | Nivå D | 81.417 | Fire Protection Wet | +TS=332.007 - 1 (10) | SPRINKEL | 0 | 25 | ORIGINAL | 80.8 | 33.8 | 33.8
Stålrør normaltykke | Nivå D | 325.981 | Fire Protection Wet | +TS=332.007 - 1 (10) | SPRINKEL | 0 | 25 | ORIGINAL | 326.3 | 33.8 | 33.8
Stålrør normaltykke | Nivå D | 3295.41 | Fire Protection Wet | +TS=332.008 | SPRINKEL | 0 | 25 | ORIGINAL | 3295.4 | 33.8 | 33.8
Stålrør normaltykke | Nivå D | 63.848 | Fire Protection Wet | +TS=332.007 - 1 (10) | SPRINKEL | 0 | 25 | ORIGINAL | 63.8 | 33.8 | 33.8
Stålrør normaltykke | Nivå D | 26.048 | Fire Protection Wet | +TS=332.007 - 1 (10) | SPRINKEL | 0 | 25 | ORIGINAL | 33.8 | 25.8 | 33.8
Stålrør normaltykke | Nivå D | 37.8 | Fire Protection Wet | +TS=332.007 - 1 (10) | SPRINKEL | 0 | 15 | ORIGINAL | 37.8 | 21.4 | 21.4
Stålrør normaltykke | Nivå D | 87.019 | Fire Protection Wet | +TS=332.007 - 1 (10) | SPRINKEL | 0 | 25 | ORIGINAL | 86.8 | 33.8 | 33.8
2 x Stålrør normaltykke | Nivå D | 121.848 | Fire Protection Wet | +TS=332.007 - 1 (10) | SPRINKEL | 0 | 25 | ORIGINAL | 122.4 | 33.8 | 33.8
2 x Stålrør normaltykke | Nivå D | 126.848 | Fire Protection Wet | +TS=332.007 - 1 (10) | SPRINKEL | 0 | 25 | ORIGINAL | 127.4 | 33.8 | 33.8
Stålrør normaltykke | Nivå D | 121.074 | Fire Protection Wet | +TS=332.007 - 1 (10) | SPRINKEL | 0 | 25 | ORIGINAL | 120.7 | 33.8 | 33.8
2 x Stålrør normaltykke | Nivå D | 58.848 | Fire Protection Wet | +TS=332.007 - 1 (10) | SPRINKEL | 0 | 25 | ORIGINAL | 59 | 33.8 | 33.8
Stålrør normaltykke | Nivå D | 82.212 | Fire Protection Wet | +TS=332.007 - 1 (10) | SPRINKEL | 0 | 25 | ORIGINAL | 81.9 | 33.8 | 33.8
Stålrør normaltykke | Nivå D | 5.157 | Fire Protection Wet | +TS=332.007 - 1 (10) | SPRINKEL | 0 | 50 | ORIGINAL | 5.2 | 60.2 | 60.2
Stålrør normaltykke | Nivå D | 586.848 | Fire Protection Wet | +TS=332.007 - 1 (10) | SPRINKEL | 0 | 25 | ORIGINAL | 587.2 | 33.8 | 33.8
Stålrør normaltykke | Nivå D | 1542.89 | Fire Protection Wet | +TS=332.007 - 1 (10) | SPRINKEL | 0 | 25 | ORIGINAL | 1542.9 | 33.8 | 33.8
Stålrør normaltykke | Nivå D | 122.465 | Fire Protection Wet | +TS=332.007 - 1 (10) | SPRINKEL | 0 | 25 | ORIGINAL | 122.4 | 33.8 | 33.8
Stålrør normaltykke | Nivå D | 512.628 | Fire Protection Wet | +TS=332.007 - 1 (10) | SPRINKEL | 0 | 50 | ORIGINAL | 512.6 | 60.2 | 60.2
Stålrør normaltykke | Nivå D | 550.082 | Fire Protection Wet | +TS=332.007 - 1 (10) | SPRINKEL | 0 | 65 | ORIGINAL | 549.5 | 76 | 76
Stålrør normaltykke | Nivå D | 220.442 | Fire Protection Wet | +TS=332.007 - 1 (10) | SPRINKEL | 0 | 65 | ORIGINAL | 220.5 | 76 | 76
Stålrør normaltykke | Nivå D | 658.317 | Fire Protection Wet | +TS=332.007 - 1 (10) | SPRINKEL | 0 | 65 | ORIGINAL | 658.3 | 76 | 76
Stålrør normaltykke | Nivå D + 1,2 m | 342.253 | Fire Protection Wet | +TS=332.007 - 1 (10) | SPRINKEL | 0 | 32 | ORIGINAL | 342.4 | 42.4 | 42.4
Stålrør normaltykke | Nivå D + 1,2 m | 509.805 | Fire Protection Wet | +TS=332.007 - 1 (10) | SPRINKEL | 0 | 25 | ORIGINAL | 510.5 | 33.8 | 33.8
Stålrør normaltykke | Nivå D + 1,2 m | 459.014 | Fire Protection Wet | +TS=332.007 - 1 (10) | SPRINKEL | 0 | 25 | ORIGINAL | 458.6 | 33.8 | 33.8
Stålrør normaltykke | Nivå D + 1,2 m | 175.494 | Fire Protection Wet | +TS=332.007 - 1 (10) | SPRINKEL | 0 | 50 | ORIGINAL | 176.2 | 60.2 | 60.2
Stålrør normaltykke | Nivå D + 1,2 m | 29.355 | Fire Protection Wet | +TS=332.007 - 1 (10) | SPRINKEL | 0 | 25 | ORIGINAL | 33.8 | 28.8 | 33.8
Stålrør normaltykke | Nivå D + 1,2 m | 822.822 | Fire Protection Wet | +TS=332.007 - 1 (10) | SPRINKEL | 0 | 50 | ORIGINAL | 822.9 | 60.2 | 60.2
Stålrør normaltykke | Nivå D + 1,2 m | 612.4 | Fire Protection Wet | +TS=332.007 - 1 (10) | SPRINKEL | 0 | 25 | ORIGINAL | 612.1 | 33.8 | 33.8
Stålrør normaltykke | Nivå D + 1,2 m | 216.386 | Fire Protection Wet | +TS=332.007 - 1 (10) | SPRINKEL | 0 | 25 | ORIGINAL | 215.8 | 33.8 | 33.8
Stålrør normaltykke | Nivå D + 1,2 m | 1709.7 | Fire Protection Wet | +TS=332.007 - 1 (10) | SPRINKEL | 0 | 25 | ORIGINAL | 1710 | 33.8 | 33.8
Stålrør normaltykke | Nivå D + 1,2 m | 256.656 | Fire Protection Wet | +TS=332.007 - 1 (10) | SPRINKEL | 0 | 50 | ORIGINAL | 257 | 60.2 | 60.2
Stålrør normaltykke | Nivå D + 1,2 m | 1072.91 | Fire Protection Wet | +TS=332.007 - 1 (10) | SPRINKEL | 0 | 50 | ORIGINAL | 1073.3 | 60.2 | 60.2
Stålrør normaltykke | Nivå D + 1,2 m | 714.101 | Fire Protection Wet | +TS=332.007 - 1 (10) | SPRINKEL | 0 | 25 | ORIGINAL | 713.5 | 33.8 | 33.8
Stålrør normaltykke | Nivå D + 1,2 m | 104.243 | Fire Protection Wet | +TS=332.007 - 1 (10) | SPRINKEL | 0 | 25 | ORIGINAL | 104.3 | 33.8 | 33.8
Stålrør normaltykke | Nivå D + 1,2 m | 887.401 | Fire Protection Wet | +TS=332.007 - 1 (10) | SPRINKEL | 0 | 50 | ORIGINAL | 887.4 | 60.2 | 60.2
Stålrør normaltykke | Nivå D + 1,2 m | 748.259 | Fire Protection Wet | +TS=332.007 - 1 (10) | SPRINKEL | 0 | 40 | ORIGINAL | 747.5 | 48.2 | 48.2
Stålrør normaltykke | Nivå D + 1,2 m | 759.631 | Fire Protection Wet | +TS=332.007 - 1 (10) | SPRINKEL | 0 | 50 | ORIGINAL | 759.6 | 60.2 | 60.2
Stålrør normaltykke | Nivå D + 1,2 m | 1136.34 | Fire Protection Wet | +TS=332.007 - 1 (10) | SPRINKEL | 0 | 40 | ORIGINAL | 1136.3 | 48.2 | 48.2
Stålrør normaltykke | Nivå D + 1,2 m | 309.963 | Fire Protection Wet | +TS=332.007 - 1 (10) | SPRINKEL | 0 | 40 | ORIGINAL | 309.9 | 48.2 | 48.2
Stålrør normaltykke | Nivå D + 1,2 m | 1513.49 | Fire Protection Wet | +TS=332.007 - 1 (10) | SPRINKEL | 0 | 32 | ORIGINAL | 1513.8 | 42.4 | 42.4
Stålrør normaltykke | Nivå D + 1,2 m | 2121.23 | Fire Protection Wet | +TS=332.007 - 1 (10) | SPRINKEL | 0 | 25 | ORIGINAL | 2121.2 | 33.8 | 33.8
Stålrør normaltykke | Nivå D + 1,2 m | 898.698 | Fire Protection Wet | +TS=332.007 - 1 (10) | SPRINKEL | 0 | 25 | ORIGINAL | 898.7 | 33.8 | 33.8
Stålrør normaltykke | Nivå D + 1,2 m | 1429.67 | Fire Protection Wet | +TS=332.007 - 1 (10) | SPRINKEL | 0 | 25 | ORIGINAL | 1429.9 | 33.8 | 33.8
Stålrør normaltykke | Nivå D + 1,2 m | 497.7 | Fire Protection Wet | +TS=332.007 - 1 (10) | SPRINKEL | 0 | 25 | ORIGINAL | 497.5 | 33.8 | 33.8
Stålrør normaltykke | Nivå D + 1,2 m | 272.4 | Fire Protection Wet | +TS=332.007 - 1 (10) | SPRINKEL | 0 | 25 | ORIGINAL | 271.5 | 33.8 | 33.8
Stålrør normaltykke | Nivå D + 1,2 m | 72.4 | Fire Protection Wet | +TS=332.007 - 1 (10) | SPRINKEL | 0 | 25 | ORIGINAL | 72.3 | 33.8 | 33.8
Stålrør normaltykke | Nivå D + 1,2 m | 38.628 | Fire Protection Wet | +TS=332.007 - 1 (10) | SPRINKEL | 0 | 25 | ORIGINAL | 38.8 | 33.8 | 33.8
Stålrør normaltykke | Nivå D + 1,2 m | 42.4 | Fire Protection Wet | +TS=332.007 - 1 (10) | SPRINKEL | 0 | 25 | ORIGINAL | 42.3 | 33.8 | 33.8
Stålrør normaltykke | Nivå D + 1,2 m | 433.2 | Fire Protection Wet | +TS=332.007 - 1 (10) | SPRINKEL | 0 | 40 | ORIGINAL | 432.9 | 48.2 | 48.2
Stålrør normaltykke | Nivå D + 1,2 m | 28.2 | Fire Protection Wet | +TS=332.007 - 1 (10) | SPRINKEL | 0 | 40 | ORIGINAL | 27.9 | 48.2 | 48.2
Stålrør normaltykke | Nivå D + 1,2 m | 2073.2 | Fire Protection Wet | +TS=332.007 - 1 (10) | SPRINKEL | 0 | 40 | ORIGINAL | 2072.9 | 48.2 | 48.2
Stålrør normaltykke | Nivå D + 1,2 m | 49.066 | Fire Protection Wet | +TS=332.007 - 1 (10) | SPRINKEL | 0 | 50 | ORIGINAL | 60.2 | 49.3 | 60.2
Stålrør normaltykke | Nivå D + 1,2 m | 87.295 | Fire Protection Wet | +TS=332.007 - 1 (10) | SPRINKEL | 0 | 25 | ORIGINAL | 86.8 | 33.8 | 33.8
Stålrør normaltykke | Nivå D + 1,2 m | 385.579 | Fire Protection Wet | +TS=332.007 - 1 (10) | SPRINKEL | 0 | 25 | ORIGINAL | 385.7 | 33.8 | 33.8
Stålrør normaltykke | Nivå D + 1,2 m | 646.842 | Fire Protection Wet | +TS=332.007 - 1 (10) | SPRINKEL | 0 | 25 | ORIGINAL | 647.4 | 33.8 | 33.8
Stålrør normaltykke | Nivå D + 1,2 m | 146.848 | Fire Protection Wet | +TS=332.007 - 1 (10) | SPRINKEL | 0 | 25 | ORIGINAL | 147.2 | 33.8 | 33.8
2 x Stålrør normaltykke | Nivå D |  | Fire Protection Wet | +TS=332.007 - 1 (10) | SPRINKEL |  |  | RESULT | 1931 | 34 | 34
Stålrør normaltykke | Nivå D |  | Fire Protection Wet | +TS=332.007 - 1 (10) | SPRINKEL |  |  | RESULT | 1932 | 34 | 34
Stålrør normaltykke | Nivå D |  | Fire Protection Wet | +TS=332.007 - 1 (10) | SPRINKEL |  |  | RESULT | 1943 | 34 | 34
Stålrør normaltykke | Nivå D |  | Undefined |  | Undefined |  |  | RESULT | 3023 | 34 | 34
Stålrør normaltykke | Nivå C |  | Fire Protection Wet | +TS=332.005 | SPRINKEL |  |  | RESULT | 1597 | 42 | 42
2 x Stålrør normaltykke | Nivå C |  | Fire Protection Wet | +TS=332.005 | SPRINKEL |  |  | RESULT | 1601 | 42 | 42
Stålrør normaltykke | Nivå C |  | Fire Protection Wet | +TS=332.005 | SPRINKEL |  |  | RESULT | 1252 | 42 | 42
2 x Stålrør normaltykke | Nivå C |  | Fire Protection Wet | +TS=332.005 | SPRINKEL |  |  | RESULT | 1252 | 48 | 48
Stålrør normaltykke | Nivå C |  | Fire Protection Wet | +TS=332.005 | SPRINKEL |  |  | RESULT | 940 | 34 | 34
Stålrør normaltykke | Nivå C |  | Fire Protection Wet | +TU=332.003-NZ0004 | SPRINKEL |  |  | RESULT | 12395 | 88 | 88
Stålrør normaltykke | Nivå C |  | Fire Protection Wet | +TS=332.005 | SPRINKEL |  |  | RESULT | 1612 | 42 | 42
Stålrør normaltykke | Nivå C |  | Undefined |  | Undefined |  |  | RESULT | 2240 | 88 | 88
Stålrør normaltykke | Nivå C |  | Fire Protection Wet | +TS=332.005 | SPRINKEL |  |  | RESULT | 905 | 48 | 48

# IfcFlowSegment: Veggkanal (10)
In: Nivå D
Type - PredefinedType: CABLETRAYSEGMENT
ePset_Simplebim - Assembly Level: Leaf
ePset_SimplebimBasicQuantities - Width (Simplebim): 60 mm; Height (Simplebim): 160 mm
MagiCAD Pset_Cabletray - System code: 4112
Group: Veggkanal for generelt
Name | Splitting | Length (Simplebim) (mm) | Length [mm] (mm) = NominalLength (mm) | Width [mm] (mm) = NominalWidth (mm) | Height [mm] (mm) = NominalHeight (mm)
Veggkanal | ORIGINAL | 5536.6 | 5536.6 | 60 | 160
Veggkanal | ORIGINAL | 3985 | 3985 | 60 | 160
4 x Veggkanal | ORIGINAL | 1759.95 | 1760 | 60 | 160
2 x Veggkanal | RESULT | 3136
Veggkanal | RESULT | 3131
Veggkanal | RESULT | 2163

# IfcFlowTerminal: 68DGR-STD-STÅENDE (87)
Type - Description: Spray, Upright installation, STD, K=80
ePset_LocationTool - Splitting: ORIGINAL
ePset_Simplebim - Assembly Level: Leaf
MagiCAD Pset_Sprinkler - Manufacturer: General; Nominal Release Temperature [°C]: 68; KFactor: 80; Description: Spray, Upright installation, STD, K=80
Name | In | Group
8 x 68DGR-STD-STÅENDE | Nivå C | +TS=332.002
31 x 68DGR-STD-STÅENDE | Nivå C | +TS=332.005
68DGR-STD-STÅENDE | Nivå D | +TS=332.008
68DGR-STD-STÅENDE | Nivå D
46 x 68DGR-STD-STÅENDE | Nivå D | +TS=332.007 - 1 (10)

# IfcFlowTerminal: Bosch LH1-10
In: Nivå D
Type - Description: Høyttaler Bosch
MagiCAD Pset_Device - Circuit order no: <unnamed>; User code: -RM; Length [mm]: 0 mm; Width [mm]: 0 mm; Height [mm]: 0 mm; Manufacturer: Bosch
ePset_Simplebim - Assembly Level: Leaf
ePset_LocationTool - Splitting: ORIGINAL
AVINOR - 08_Status: S4; 07_Fase: F90; 04_Kontrakt: 72588; 02_Prosjekt: 72101; 01_Lufthavnkode: ENGM; 05_ID-nummer: +TS=555.003-RM0329

# IfcFlowTerminal: Datauttak dobbel Vegg - IKT (8)
In: Nivå D
Type - Description: Datauttak dobbel Vegg - IKT; PredefinedType: COMMUNICATIONSOUTLET
AVINOR - 08_Status: S4; 07_Fase: F90; 04_Kontrakt: 72512; 02_Prosjekt: 72101; 01_Lufthavnkode: ENGM
ePset_Simplebim - Assembly Level: Leaf
ePset_LocationTool - Splitting: ORIGINAL
Pset_OutletTypeCommon - IsPluggableOutlet: yes
MagiCAD Pset_Device - System code: 574; User code: -WD; Length [mm]: 0 mm; Width [mm]: 0 mm; Height [mm]: 0 mm
Group: -
Name | 05_ID-nummer
Datauttak dobbel Vegg - IKT | +TS=574.006-WD1042
Datauttak dobbel Vegg - IKT | +TS=574.006-WD1044
Datauttak dobbel Vegg - IKT | +TS=574.006-WD1046
Datauttak dobbel Vegg - IKT | +TS=574.006-WD1048
Datauttak dobbel Vegg - IKT | +TS=574.006-WD1050
Datauttak dobbel Vegg - IKT | +TS=574.006-WD1052
Datauttak dobbel Vegg - IKT | +TS=574.006-WD1040
Datauttak dobbel Vegg - IKT | +TS=574.006-WD1054

# IfcFlowTerminal: Datauttak enkelt Tak - TVO (3)
In: Nivå D
Type - Description: Datauttak enkelt Tak - TVO; PredefinedType: COMMUNICATIONSOUTLET
ePset_Simplebim - Assembly Level: Leaf
ePset_LocationTool - Splitting: ORIGINAL
AVINOR - 08_Status: S4; 07_Fase: F90; 04_Kontrakt: 72512; 02_Prosjekt: 72101; 01_Lufthavnkode: ENGM
Pset_OutletTypeCommon - IsPluggableOutlet: yes
MagiCAD Pset_Device - System code: 574; User code: -WD; Length [mm]: 0 mm; Width [mm]: 0 mm; Height [mm]: 0 mm
Group: -
Name | 05_ID-nummer
Datauttak enkelt Tak - TVO | +TS=574.006-WD1058
Datauttak enkelt Tak - TVO | +TS=574.006-WD1057
Datauttak enkelt Tak - TVO | +TS=574.006-WD1056

# IfcFlowTerminal: GRLc 200-100+TRGc 200-100-125-B
In: Nivå C
Type - Description: Rectangular grille for exhaust or transfer air
ePset_Simplebim - Assembly Level: Leaf
ePset_LocationTool - Splitting: ORIGINAL
Group: +TS=360.030 A

# IfcFlowTerminal: GRLc 500-150 (6)
In: Nivå D
ePset_Simplebim - Assembly Level: Leaf
ePset_LocationTool - Splitting: ORIGINAL
Name | Group
2 x GRLc 500-150 | 36= Avtrekk 53
2 x GRLc 500-150 | 36= Avtrekk 71
2 x GRLc 500-150 | 36= Avtrekk 77

# IfcFlowTerminal: IB7330 Markeringslys ensidig 30 meter leseavstand innfelt:IB7330 Zumtobel Puresign/Comsign 150 ED NDA (2)
In: Nivå D
Type - Material: <Unnamed>, Light Source Hvit, Light Source Grønn
Type - Pset_ManufacturerTypeInformation - Manufacturer: Zumtobel
AVINOR - 08_Status: S4; 07_Fase: F90; 05_ID-nummer: +TO=443.001-IB7330; 04_Kontrakt: 72585; 02_Prosjekt: 72101; 06_Omrade: TS; 01_Lufthavnkode: ENGM
ePset_Simplebim - Assembly Level: Leaf
ePset_LocationTool - Splitting: ORIGINAL
Pset_DistributionFlowElementCommon - Reference: IB7330 Zumtobel Puresign/Comsign 150 ED NDA; sets with these values: 2
Group: 10
Name (IB7330 Markeringslys ensidig 30 meter leseavstand innfelt:IB7330 Zumtobel Puresign/Comsign 150 ED NDA:...)
15320519
15320814

# IfcFlowTerminal: IB7333 Markeringslys ensidig 30 meter leseavstand vegg:IB7333 Zumtobel Puresign 150 AW NDA, IB7333 Markeringslys ensidig 30 meter leseavstand vegg:IB7333 Zumtobel Puresign 150 AW NDA:15310786
In: Nivå D
Type - Material: Light Source Hvit, Light Source Grønn, <Unnamed>
Type - Pset_ManufacturerTypeInformation - Manufacturer: Zumtobel
ePset_Simplebim - Assembly Level: Leaf
ePset_LocationTool - Splitting: ORIGINAL
Pset_QuantityTakeOff - Reference: IB7333 Zumtobel Puresign 150 AW NDA; sets with these values: 2
AVINOR - 08_Status: S4; 07_Fase: F90; 05_ID-nummer: +TO=443.001-IB7333; 04_Kontrakt: 72585; 02_Prosjekt: 72101; 06_Omrade: TS; 01_Lufthavnkode: ENGM
Group: 4

# IfcFlowTerminal: IB7404 Ledelys utenpåliggende:IB7404 Zumtobel Resclite C Antipanic AD NDA WH, IB7404 Ledelys utenpåliggende:IB7404 Zumtobel Resclite C Antipanic AD NDA WH:18518734
In: Nivå C
Type - Material: <Unnamed>
Type - Pset_ManufacturerTypeInformation - Manufacturer: ZUMTOBEL
ePset_LocationTool - Splitting: ORIGINAL
Pset_QuantityTakeOff - Reference: IB7404 Zumtobel Resclite C Antipanic AD NDA WH; sets with these values: 2
ePset_Simplebim - Assembly Level: Leaf
AVINOR - 08_Status: S4; 02_Prosjekt: A172140; 07_Fase: F50; 03_Ansvar: 181608; 04_Kontrakt: 184990; 05_ID-nummer: +TO=443.001-IB7404; 06_Omrade: TS; 01_Lufthavnkode: ENGM
Group: 3

# IfcFlowTerminal: IB7405 Ledelys innfelt i himling:IB7405 Zumtobel Resclite C Antipanic ED NDA WH (5)
In: Nivå D
Type - Material: <Unnamed>
Type - Pset_ManufacturerTypeInformation - Manufacturer: Zumtobel
AVINOR - 08_Status: S4; 07_Fase: F90; 05_ID-nummer: +TO=443.001-IB7405; 04_Kontrakt: 72585; 02_Prosjekt: 72101; 06_Omrade: TS; 01_Lufthavnkode: ENGM
ePset_Simplebim - Assembly Level: Leaf
ePset_LocationTool - Splitting: ORIGINAL
Pset_QuantityTakeOff - Reference: IB7405 Zumtobel Resclite C Antipanic ED NDA WH; sets with these values: 2
Name (IB7405 Ledelys innfelt i himling:IB7405 Zumtobel Resclite C Antipanic ED NDA WH:...) | Group
14878489 | 4
14878490 | 4
14878491 | 4
14878492 | 10
14878493 | 10

# IfcFlowTerminal: KBF-1-450-2400-A (5)
In: Nivå D
Type - Description: Active chilled beam
ePset_Simplebim - Assembly Level: Leaf
ePset_LocationTool - Splitting: ORIGINAL
Group: +TS=360.060 T_2

# IfcFlowTerminal: LC1UM06E8 (9)
In: Nivå D
Type - Description: Høyttaler innfelt
ePset_Simplebim - Assembly Level: Leaf
AVINOR - 08_Status: S4; 07_Fase: F90; 04_Kontrakt: 72588; 02_Prosjekt: 72101; 01_Lufthavnkode: ENGM
ePset_LocationTool - Splitting: ORIGINAL
MagiCAD Pset_Device - Product code: LC1UM06E8; Circuit order no: <unnamed>; User code: -RM; P1: -RQ; Length [mm]: 0 mm; Width [mm]: 0 mm; Height [mm]: 0 mm; Manufacturer: Bosch
Name | 05_ID-nummer
LC1UM06E8 | +TS=555.003-RM0324
LC1UM06E8 | +TS=555.003-RM0326
LC1UM06E8 | +TS=555.003-RM0327
LC1UM06E8 | +TS=555.003-RM0322
LC1UM06E8 | +TS=555.003-RM0321
LC1UM06E8 | +TS=555.003-RM0320
LC1UM06E8 | +TS=555.003-RM0323
LC1UM06E8 | +TS=555.003-RM0328
LC1UM06E8 | +TS=555.003-RM0325

# IfcFlowTerminal: Orion-LOV-TA-250+Luna-200-250 (7)
In: Nivå D
Type - Description: ATD for panneld ceiling
Classification: VE1.13332 Not defined (NS3420); Group: +TS=360.060 T_2
ePset_LocationTool - Splitting: ORIGINAL
ePset_Simplebim - Assembly Level: Leaf

# IfcFlowTerminal: SP-15-K80-68DGR-STD-HIMLING (31)
In: Nivå D
Type - Description: Spray, pendent installation, STD, K=80
ePset_Simplebim - Assembly Level: Leaf
ePset_LocationTool - Splitting: ORIGINAL
MagiCAD Pset_Sprinkler - Description: Spray, pendent installation, STD, K=80; Manufacturer: General; Nominal Release Temperature [°C]: 68; KFactor: 80
Group: +TS=332.007 - 1 (10)

# IfcFlowTerminal: SP-15-K80-68DGR-STD-NEDOVER-TØRR (3)
In: Nivå D
Type - Description: Spray, pendent installation, STD, K=80
ePset_Simplebim - Assembly Level: Leaf
ePset_LocationTool - Splitting: ORIGINAL
MagiCAD Pset_Sprinkler - Description: Spray, pendent installation, STD, K=80; Manufacturer: General; Nominal Release Temperature [°C]: 68; KFactor: 80
Name | Group
SP-15-K80-68DGR-STD-NEDOVER-TØRR | 33= tørr Kopi 1
SP-15-K80-68DGR-STD-NEDOVER-TØRR | 33= tørr Kopi 4
SP-15-K80-68DGR-STD-NEDOVER-TØRR | 33= tørr Kopi 2

# IfcFlowTerminal: SP-15-K80-68DGR-STD-STÅENDE (3)
In: Nivå D
Type - Description: Spray, pendent installation, STD, K=80
Classification: RS1.3000121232 Not defined (NS3420); Group: +TS=332.007 - 1 (10)
MagiCAD Pset_Sprinkler - User Code: UZ03T; NationalCode: RS1.3000121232; Product code: SP-15-K80-68DGR-STD; Description: Spray, pendent installation, STD, K=80; Manufacturer: General; Nominal Release Temperature [°C]: 68; KFactor: 80
ePset_Simplebim - Assembly Level: Leaf
ePset_LocationTool - Splitting: ORIGINAL

# IfcFlowTreatmentDevice: LKR-250-600 (2)
In: Nivå D
Type - Description: Circular sound attenuator.; PredefinedType: ROUND
Classification: VB2.143122 Not defined (NS3420); Group: +TS=360.060 T_2
ePset_LocationTool - Splitting: ORIGINAL
ePset_Simplebim - Assembly Level: Leaf

# IfcFlowTreatmentDevice: SLCU 250 900 50
In: Nivå D
Type - Description: Circular straight silencer; PredefinedType: ROUND
Classification: VB2.143122 Not defined (NS3420)
ePset_LocationTool - Splitting: ORIGINAL
ePset_Simplebim - Assembly Level: Leaf

# IfcMember: Rectangular Mullion:A241 - 10 mm fuge (10)
In: Nivå D
Type - PredefinedType: MULLION; Material: Fuge transparent
ePset_SimplebimBasicQuantities - Width (Simplebim): 20 mm; Height (Simplebim): 10 mm; Length (Simplebim): 750 mm
Pset_MemberCommon - Reference: A241 - 10 mm fuge; IsExternal: no; Span: 750 mm
ePset_Simplebim - Assembly Level: Leaf
ePset_LocationTool - Splitting: ORIGINAL
Pset_QuantityTakeOff - Reference: A241 - 10 mm fuge
AVINOR - 08_Status: S4; 07_Fase: F90; 05_ID-nummer: +TS=245.106; 03_Ansvar: 72717; 02_Prosjekt: 72101; 06_Omrade: TS; 01_Lufthavnkode: ENGM
Name (Rectangular Mullion:A241 - 10 mm fuge:...) | Weight, as steel (Simplebim) (kg) | Area, sides, net (Simplebim) (m2) | Volume, net (Simplebim) (m3)
39320048 | 1.1775 | 0.0454 | 0.00015
39320049 | 1.1775 | 0.0454 | 0.00015
39320050 | 1.1775 | 0.0454 | 0.00015
39320051 | 1.1775 | 0.0454 | 0.00015
39332893 | 1.1775 | 0.0454 | 0.00015
39380349 | 1.1775 | 0.0454 | 0.00015
39380381 | 1.1618 | 0.0448828 | 0.000148
39380407 | 1.1775 | 0.0454 | 0.00015
39380428 | 1.1775 | 0.0454 | 0.00015
39380450 | 1.1775 | 0.0454 | 0.00015

# IfcPlate: PL10*182 (8)
In: D
Description: PL10*182
Tekla Common - Grade: S355; Top elevation: +207.540; Profile: PL10*182; Bottom elevation: +207.358
Pset_PlateCommon - LoadBearing: no
ePset_Simplebim - Assembly Level: Leaf
AVINOR - 08_Status: S2; 07_Fase: F20; 02_Prosjekt: A181143; 03_Ansvar: 187259; 06_Omrade: TS; 01_Lufthavnkode: ENGM
Name | Assembly mark | Class | Name | Part mark = Reference | Area, largest surface, net (Simplebim) (m2) | Weight, as steel (Simplebim) (kg) | Volume, net (Simplebim) (m3) | Splitting
2 x STÅLSØYLE | SS-0(?) | 320 | STÅLSØYLE | DSS-0(?) | 0.06734 | 5.28619 | 0.0006734 | ORIGINAL | Material: STEEL/S355; Tekla Quantity - AREA_GROSS: 0.06734 m2; WEIGTH_NET: 5.28619 kg; WEIGTH_GROSS: 5.28619 kg; AREA_NET: 0.14572 m2; VOLUME_GROSS: 0.00067 m3; VOLUME_NET: 0.00067 m3; Width: 10 mm; Heigth: 182 mm; Length: 370 mm
2 x STÅLBJELKE | SB-0(?) | 330 | STÅLBJELKE | DSB-0(?) | 0.06734 | 5.28619 | 0.0006734 | ORIGINAL | Material: STEEL/S355; Tekla Quantity - AREA_GROSS: 0.06734 m2; WEIGTH_NET: 5.28619 kg; WEIGTH_GROSS: 5.28619 kg; AREA_NET: 0.14572 m2; VOLUME_GROSS: 0.00067 m3; VOLUME_NET: 0.00067 m3; Width: 10 mm; Heigth: 182 mm; Length: 370 mm
STÅLSØYLE | SS-0(?) | 320 | STÅLSØYLE | DSS-0(?) | 0.0397597 | 3.12113 | 0.000397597 | RESULT
STÅLBJELKE | SB-0(?) | 330 | STÅLBJELKE | DSB-0(?) | 0.0397597 | 3.12113 | 0.000397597 | RESULT
STÅLSØYLE | SS-0(?) | 320 | STÅLSØYLE | DSS-0(?) | 0.0397575 | 3.12097 | 0.000397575 | RESULT
STÅLBJELKE | SB-0(?) | 330 | STÅLBJELKE | DSB-0(?) | 0.0397575 | 3.12097 | 0.000397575 | RESULT

# IfcPlate: PL20*10444 (2)
In: D
Description: PL20*10444
Pset_PlateCommon - LoadBearing: no; Reference: DTT-0(?)
Tekla Common - Profile: PL20*10444; Assembly mark: TT-0(?); Part mark: DTT-0(?)
ePset_Simplebim - Assembly Level: Leaf
ePset_SimplebimBasicQuantities - Volume, net (Simplebim): 0.646469 m3; Area, largest surface, net (Simplebim): 32.3234 m2; Weight, as steel (Simplebim): 5074.78 kg
ePset_LocationTool - Splitting: RESULT
AVINOR - 08_Status: S4; 02_Prosjekt: A181143; 03_Ansvar: 187259; 07_Fase: F50; 06_Omrade: TS; 01_Lufthavnkode: ENGM
Name | Grade | Name | Top elevation | Class | Bottom elevation
TRINNLYDPLATE | Misc_Undefined | TRINNLYDPLATE | +207.357 | 460 | +207.338
TRETAK | Timber_Undefined | TRETAK | +207.377 | 461 | +207.357

# IfcPlate: System Panel:A245 - KL-G01 - Veggkledning glasspanel (14)
In: Nivå D
Type - PredefinedType: CURTAIN_PANEL; Material: KL-G01
ePset_LocationTool - Splitting: ORIGINAL
Pset_QuantityTakeOff - Reference: A245 - KL-G01 - Veggkledning glasspanel
ePset_SimplebimBasicQuantities - Area, largest surface, net (Simplebim): 2.37 m2; Weight, as steel (Simplebim): 186.045 kg; Volume, net (Simplebim): 0.0237 m3
ePset_Simplebim - Assembly Level: Leaf
AVINOR - 08_Status: S4; 07_Fase: F90; 05_ID-nummer: +TS=245.106; 03_Ansvar: 72717; 02_Prosjekt: 72101; 06_Omrade: TS; 01_Lufthavnkode: ENGM
Pset_PlateCommon - IsExternal: no; Reference: A245 - KL-G01 - Veggkledning glasspanel
Name (System Panel:A245 - KL-G01 - Veggkledning glasspanel:...)
39320035
39380444
39320040
39380423
39320041
39380402
39320042
39380343
39320043
39380374
39550666
39550697
39550701
39550964

# IfcPlate: System Panel:A245 - KL-S01 - Veggkledning metallplate sokkel - IGK - 10mm (9)
In: Nivå D
Type - PredefinedType: CURTAIN_PANEL; Material: _NSW Stål, rustfritt
Pset_QuantityTakeOff - Reference: A245 - KL-S01 - Veggkledning metallplate sokkel - IGK - 10mm
ePset_Simplebim - Assembly Level: Leaf
Pset_PlateCommon - IsExternal: no; Reference: A245 - KL-S01 - Veggkledning metallplate sokkel - IGK - 10mm
ePset_LocationTool - Splitting: ORIGINAL
AVINOR - 08_Status: S4; 07_Fase: F90; 05_ID-nummer: +TS=245.101; 03_Ansvar: 72717; 02_Prosjekt: 72101; 06_Omrade: TS; 01_Lufthavnkode: ENGM
Name (System Panel:A245 - KL-S01 - Veggkledning metallplate sokkel - IGK - 10mm:...) | Weight, as steel (Simplebim) (kg) | Area, largest surface, net (Simplebim) (m2) | Volume, net (Simplebim) (m3)
39320017 | 88.3125 | 1.125 | 0.01125
39550658 | 8.83125 | 0.1125 | 0.001125
39968216 | 0.58875 | 0.0075 | 0.000075
39550695 | 8.83125 | 0.1125 | 0.001125
39968302 | 0.58875 | 0.0075 | 0.000075
39550699 | 8.83125 | 0.1125 | 0.001125
39968388 | 0.58875 | 0.0075 | 0.000075
39550962 | 8.83125 | 0.1125 | 0.001125
39968404 | 0.58875 | 0.0075 | 0.000075

# IfcRailing: Railing:A247 Fendring - FE-S01 - Avviser, montert m. brakett mot dekke, 1 rør Ø=49 mm, Railing:A247 Fendring - FE-S01 - Avviser, montert m. brakett mot dekke, 1 rør Ø=49 mm:39390884
In: Nivå D
Material: <Unnamed>
ePset_Simplebim - Assembly Level: Leaf
ePset_SimplebimBasicQuantities - Height: 49.7441 mm; Width: 3150 mm; Length: 9008.14 mm
Pset_QuantityTakeOff - Reference: A247 Fendring - FE-S01 - Avviser, montert m. brakett mot dekke, 1 rør Ø=49 mm
ePset_LocationTool - Splitting: ORIGINAL
Pset_RailingCommon - Height: 1219.2 mm; Reference: A247 Fendring - FE-S01 - Avviser, montert m. brakett mot dekke, 1 rør Ø=49 mm; IsExternal: no
AVINOR - 08_Status: S4; 07_Fase: F90; 05_ID-nummer: +TS=251.010-IY0005; 03_Ansvar: 72717; 02_Prosjekt: 72101; 06_Omrade: TS; 01_Lufthavnkode: ENGM

# IfcSlab: 130*32640, PÅSTØP
In: D
Description: 130*32640; PredefinedType: FLOOR
ePset_SimplebimBasicQuantities - Perimeter (Simplebim): 82174.7 mm; Area, sides, net (Simplebim): 10.6827 m2; Volume, net (Simplebim): 47.2114 m3; Thickness (Simplebim): 130 mm; Area, top, net (Simplebim): 363.165 m2; Area, largest surface, net (Simplebim): 363.165 m2
ePset_LocationTool - Splitting: RESULT
ePset_Simplebim - Assembly Level: Leaf
AVINOR - 07_Fase: F90; 02_Prosjekt: T1; 03_Ansvar: FDV; 04_Kontrakt: FDV; 08_Status: S2; 06_Omrade: TS; 01_Lufthavnkode: ENGM
Tekla Common - Name: PÅSTØP; Bottom elevation: +203.800; Assembly mark: PST-753(?); Grade: C30/37; Top elevation: +203.930; Profile: 130*32640; Class: 262; Part mark: DSS-6201(?)
Pset_SlabCommon - LoadBearing: no; Reference: DSS-6201(?)

# IfcSlab: 60*245 (3)
In: D
Description: 60*245; PredefinedType: FLOOR
Tekla Common - Class: 699; Grade: MINERALULL; Profile: 60*245; Bottom elevation: +203.155; Name: ISOLASJON; Top elevation: +203.400
Pset_SlabCommon - LoadBearing: no
ePset_SimplebimBasicQuantities - Thickness (Simplebim): 245 mm
ePset_Simplebim - Assembly Level: Leaf
AVINOR - 08_Status: S4; 07_Fase: F90; 02_Prosjekt: T20100; 05_ID-nummer: +TS=223.013; 04_Kontrakt: 72233; 03_Ansvar: 72101; 06_Omrade: TS; 01_Lufthavnkode: ENGM
Name | Part mark = Reference | Assembly mark | Area, sides, net (Simplebim) (m2) | Perimeter (Simplebim) (mm) | Area, top, net (Simplebim) (m2) | Area, largest surface, net (Simplebim) (m2) | Volume, net (Simplebim) (m3) | Splitting
ISOLASJON | Concrete-19684(?) | IMU-9(?) | 0.2058 | 840 | 0.0216 | 0.0882 | 0.005292 | ORIGINAL | Material: MISCELLANEOUS/MINERALULL; Tekla Quantity - WEIGTH_GROSS: 0.10584 kg; WEIGTH_NET: 0.10584 kg; VOLUME_GROSS: 0.0053 m3; VOLUME_NET: 0.00528 m3; Width: 60 mm; Heigth: 245 mm; Length: 360 mm; AREA_GROSS: 0.0882 m2; AREA_NET: 0.249 m2
2 x ISOLASJON | Concrete-19685(?) | IMU-10(?) | 1.83627 | 7495 | 0.22125 | 0.903437 | 0.0542062 | RESULT

# IfcSlab: Floor:A250 - Metalplate 5mm, Floor:A250 - Metalplate 5mm:39956500
In: Nivå D
Type - PredefinedType: FLOOR; Material: _NSW Stål 5 mm
ePset_LocationTool - Splitting: RESULT
Pset_SlabCommon - IsExternal: no; LoadBearing: no; Reference: A250 - Metalplate 5mm
ePset_Simplebim - Assembly Level: Leaf
Pset_ReinforcementBarPitchOfSlab - Reference: A250 - Metalplate 5mm; sets with these values: 2
ePset_SimplebimBasicQuantities - Area, sides, net (Simplebim): 0.186319 m2; Volume, net (Simplebim): 0.0183766 m3; Area, top, net (Simplebim): 3.67525 m2; Area, largest surface, net (Simplebim): 3.67525 m2; Thickness (Simplebim): 5 mm; Perimeter (Simplebim): 37263.8 mm
AVINOR - 08_Status: S4; 07_Fase: F90; 05_ID-nummer: +TS=245.103; 03_Ansvar: 72717; 02_Prosjekt: 72101; 06_Omrade: TS; 01_Lufthavnkode: ENGM

# IfcSlab: Floor:A251 - Standard - 80 mm, Floor:A251 - Standard - 80 mm:39956833
In: Nivå D
Type - PredefinedType: FLOOR; Material: <Unnamed> 80 mm
ePset_SimplebimBasicQuantities - Area, largest surface, net (Simplebim): 5.291 m2; Area, top, net (Simplebim): 5.291 m2; Volume, net (Simplebim): 0.423275 m3; Perimeter (Simplebim): 46910.5 mm; Thickness (Simplebim): 80 mm; Area, sides, net (Simplebim): 3.75284 m2
ePset_Simplebim - Assembly Level: Leaf
Pset_SlabCommon - IsExternal: no; LoadBearing: no; PitchAngle: 0 deg; Reference: A251 - Standard - 80 mm
Pset_QuantityTakeOff - Reference: A251 - Standard - 80 mm; sets with these values: 2
AVINOR - 08_Status: S4; 07_Fase: F90; 05_ID-nummer: +TS=243.001-IR0063; 03_Ansvar: 72717; 02_Prosjekt: 72101; 06_Omrade: TS; 01_Lufthavnkode: ENGM
ePset_LocationTool - Splitting: ORIGINAL

# IfcSlab: Floor:A251 - Trykkfast isolasjon - 80 mm (4)
In: Nivå D
Type - PredefinedType: FLOOR; Material: _NSW Isolasjon trykkfast 80 mm
ePset_LocationTool - Splitting: ORIGINAL
ePset_Simplebim - Assembly Level: Leaf
AVINOR - 08_Status: S4; 07_Fase: F40; 03_Ansvar: LEIETAKER; 02_Prosjekt: 72101; 06_Omrade: TS; 01_Lufthavnkode: ENGM
Pset_QuantityTakeOff - Reference: A251 - Trykkfast isolasjon - 80 mm; sets with these values: 2
ePset_SimplebimBasicQuantities - Thickness (Simplebim): 80 mm
Pset_SlabCommon - IsExternal: yes; LoadBearing: no; PitchAngle: 0 deg; Reference: A251 - Trykkfast isolasjon - 80 mm
Name (Floor:A251 - Trykkfast isolasjon - 80 mm:...) | Volume, net (Simplebim) (m3) | Area, largest surface, net (Simplebim) (m2) = Area, top, net (Simplebim) (m2) | Perimeter (Simplebim) (mm) | Area, sides, net (Simplebim) (m2)
41795442 | 1.2392 | 15.4902 | 19554.6 | 1.56437
41807281 | 1.2392 | 15.4898 | 19565 | 1.5652
66442812 | 0.286682 | 3.5834 | 9640.8 | 0.771264
66442882 | 0.278159 | 3.47697 | 9399.98 | 0.751998

# IfcSlab: Floor:A251 - stålplate - 5mm, Floor:A251 - stålplate - 5mm:40046920
In: Nivå D
Type - PredefinedType: FLOOR; Material: T2 Steel 5 mm
ePset_SimplebimBasicQuantities - Area, sides, net (Simplebim): 0.186325 m2; Thickness (Simplebim): 5 mm; Area, top, net (Simplebim): 3.67459 m2; Area, largest surface, net (Simplebim): 3.67459 m2; Volume, net (Simplebim): 0.0183734 m3; Perimeter (Simplebim): 37264.9 mm
ePset_Simplebim - Assembly Level: Leaf
Pset_SlabCommon - IsExternal: no; LoadBearing: no; Reference: A251 - stålplate - 5mm
AVINOR - 08_Status: S4; 07_Fase: F90; 05_ID-nummer: +TS=245.103; 03_Ansvar: 72717; 02_Prosjekt: 72101; 06_Omrade: TS; 01_Lufthavnkode: ENGM
Pset_QuantityTakeOff - Reference: A251 - stålplate - 5mm; sets with these values: 2
ePset_LocationTool - Splitting: RESULT

# IfcSlab: Floor:A254 - Gulvgips - 13 mm, Floor:A254 - Gulvgips - 13 mm:42246709
In: Nivå D
Type - PredefinedType: FLOOR; Material: T2 - Gulvgips 13 mm
Pset_ReinforcementBarPitchOfSlab - Reference: A254 - Gulvgips - 13 mm; sets with these values: 2
ePset_LocationTool - Splitting: ORIGINAL
Pset_SlabCommon - IsExternal: no; LoadBearing: no; PitchAngle: 0 deg; Reference: A254 - Gulvgips - 13 mm
ePset_SimplebimBasicQuantities - Volume, net (Simplebim): 0.476881 m3; Area, sides, net (Simplebim): 0.315652 m2; Perimeter (Simplebim): 24280.9 mm; Thickness (Simplebim): 13 mm; Area, top, net (Simplebim): 36.6831 m2; Area, largest surface, net (Simplebim): 36.6831 m2
ePset_Simplebim - Assembly Level: Leaf
AVINOR - 08_Status: S4; 07_Fase: F90; 03_Ansvar: 72717; 05_ID-nummer: +TS=254.041; 02_Prosjekt: 72101; 06_Omrade: TS; 01_Lufthavnkode: ENGM

# IfcSlab: Floor:A254 - Gulvoppbygging m_f.o - 70 mm (9)
In: Nivå D
Type - PredefinedType: FLOOR; Material: _NSW Gulv (Generell) 70 mm
AVINOR - 07_Fase: F90; 08_Status: S1; 03_Ansvar: FDV; 06_Omrade: TS; 01_Lufthavnkode: ENGM
ePset_Simplebim - Assembly Level: Leaf
ePset_SimplebimBasicQuantities - Thickness (Simplebim): 70 mm
Pset_QuantityTakeOff - Reference: A254 - Gulvoppbygging m_f.o - 70 mm; sets with these values: 2
Pset_SlabCommon - IsExternal: no; LoadBearing: no; Reference: A254 - Gulvoppbygging m_f.o - 70 mm
Name (Floor:A254 - Gulvoppbygging m_f.o - 70 mm:...) | Area, sides, net (Simplebim) (m2) | Area, top, net (Simplebim) (m2) | Area, largest surface, net (Simplebim) (m2) | Volume, net (Simplebim) (m3) | Perimeter (Simplebim) (mm) | PitchAngle (deg) | Splitting
42244770 | 0.0096649 | 0.000950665 | 0.00350489 | 0.0000665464 | 138.07 | 0 | ORIGINAL
42244770:2 | 0.370187 | 0.0498762 | 0.183799 | 0.00349136 | 5288.38 | 0 | ORIGINAL
42244770:3 | 0.414161 | 0.0558454 | 0.2058 | 0.00390917 | 5916.59 | 0 | ORIGINAL
42244770:4 | 0.378912 | 0.0510591 | 0.188177 | 0.00357411 | 5413.03 | 0 | ORIGINAL
42244770:5 | 0.460623 | 0.0621449 | 0.229043 | 0.00435013 | 6580.32 | 0 | ORIGINAL
42244770:6 | 0.426493 | 0.0575144 | 0.211974 | 0.004026 | 6092.75 | 0 | ORIGINAL
42244770:7 | 0.424897 | 0.0573026 | 0.211158 | 0.0040112 | 6069.95 | 0 | ORIGINAL
42244770:8 | 0.770529 | 0.104154 | 0.382294 | 0.0072908 | 11007.6 | 0 | ORIGINAL
34265622 | 9.84994 | 333.103 | 333.103 | 23.3172 | 140713 |  | RESULT

# IfcSlab: Floor:A254 - Gulvoppbygging m_f.o - 70mm - stein, Floor:A254 - Gulvoppbygging m_f.o - 70mm - stein:42262852
In: Nivå D
Type - PredefinedType: FLOOR; Material: T2 - Dekke uten skravur 70 mm
Type - Pset_ReinforcementBarPitchOfSlab - Description: eksisterende steingulv
ePset_SimplebimBasicQuantities - Thickness (Simplebim): 70 mm; Area, sides, net (Simplebim): 1.67412 m2; Perimeter (Simplebim): 23916 mm; Volume, net (Simplebim): 1.96177 m3; Area, largest surface, net (Simplebim): 28.0252 m2; Area, top, net (Simplebim): 28.0252 m2
Pset_ReinforcementBarPitchOfSlab - Reference: A254 - Gulvoppbygging m_f.o - 70mm - stein; sets with these values: 2
ePset_Simplebim - Assembly Level: Leaf
ePset_LocationTool - Splitting: ORIGINAL
Pset_SlabCommon - Reference: A254 - Gulvoppbygging m_f.o - 70mm - stein; IsExternal: no; LoadBearing: no; PitchAngle: 0 deg
AVINOR - 05_ID-nummer: +TS=254.062; 08_Status: S4; 07_Fase: F90; 03_Ansvar: 72717; 02_Prosjekt: 72101; 06_Omrade: TS; 01_Lufthavnkode: ENGM

# IfcSlab: Floor:A254 - Kryssfiner - 15 mm (2)
In: Nivå D
Type - PredefinedType: FLOOR; Material: T2_X-finer 15 mm
ePset_SimplebimBasicQuantities - Thickness (Simplebim): 15 mm
Pset_ReinforcementBarPitchOfSlab - Reference: A254 - Kryssfiner - 15 mm; sets with these values: 2
Pset_SlabCommon - Reference: A254 - Kryssfiner - 15 mm; IsExternal: no; LoadBearing: no
ePset_LocationTool - Splitting: RESULT
ePset_Simplebim - Assembly Level: Leaf
AVINOR - 08_Status: S4; 07_Fase: F90; 03_Ansvar: 72717; 02_Prosjekt: 72101; 06_Omrade: TS; 01_Lufthavnkode: ENGM
Name (Floor:A254 - Kryssfiner - 15 mm:...) | Volume, net (Simplebim) (m3) | Area, top, net (Simplebim) (m2) = Area, largest surface, net (Simplebim) (m2) | Perimeter (Simplebim) (mm) | Area, sides, net (Simplebim) (m2) | 05_ID-nummer
40047065 | 0.0551201 | 3.67459 | 37243.8 | 0.558657 | +TS=245.103
39119323 | 0.21983 | 14.6553 | 17401.4 | 0.261022 | +TS=254.063

# IfcSlab: Floor:A254 - Kryssfiner - 20 mm, Floor:A254 - Kryssfiner - 20 mm:23930687:3
In: Nivå D
Type - PredefinedType: FLOOR; Material: T2_X-finer 20 mm
AVINOR - 07_Fase: F90; 08_Status: S1; 03_Ansvar: FDV; 06_Omrade: TS; 01_Lufthavnkode: ENGM
ePset_SimplebimBasicQuantities - Perimeter (Simplebim): 45157.7 mm; Area, top, net (Simplebim): 93.0497 m2; Area, largest surface, net (Simplebim): 93.0497 m2; Thickness (Simplebim): 20 mm; Area, sides, net (Simplebim): 0.903154 m2; Volume, net (Simplebim): 1.86099 m3
ePset_LocationTool - Splitting: RESULT
ePset_Simplebim - Assembly Level: Leaf
Pset_QuantityTakeOff - Reference: A254 - Kryssfiner - 20 mm; sets with these values: 2
Pset_SlabCommon - IsExternal: no; LoadBearing: no; Reference: A254 - Kryssfiner - 20 mm

# IfcSlab: Floor:A254 - Sveiset våtromsgulv - 3mm + 3mm skum, Floor:A254 - Sveiset våtromsgulv - 3mm + 3mm skum:42119879
In: Nivå D
Type - PredefinedType: FLOOR; Material: _NSW Gulv (Generell) 3 mm, _NSW Generell Gulv (Floor) 3 mm
Pset_SlabCommon - IsExternal: no; LoadBearing: no; PitchAngle: 0 deg; Reference: A254 - Sveiset våtromsgulv - 3mm + 3mm skum
ePset_SimplebimBasicQuantities - Perimeter (Simplebim): 22659.7 mm; Area, top, net (Simplebim): 22.2043 m2; Area, largest surface, net (Simplebim): 22.2043 m2; Volume, net (Simplebim): 0.133226 m3; Area, sides, net (Simplebim): 0.135958 m2; Thickness (Simplebim): 6 mm
ePset_Simplebim - Assembly Level: Leaf
ePset_LocationTool - Splitting: ORIGINAL
Pset_QuantityTakeOff - Reference: A254 - Sveiset våtromsgulv - 3mm + 3mm skum; sets with these values: 2
AVINOR - 08_Status: S4; 07_Fase: F90; 03_Ansvar: 72717; 05_ID-nummer: +TS=254.042; 02_Prosjekt: 72101; 06_Omrade: TS; 01_Lufthavnkode: ENGM

# IfcSlab: Floor:A275 - Gitterrist, Floor:A275 - Gitterrist:37703256
In: Nivå D
Type - PredefinedType: FLOOR; Material: A254 - Metall rist 40 mm
Pset_ReinforcementBarPitchOfSlab - Reference: A275 - Gitterrist; sets with these values: 2
ePset_LocationTool - Splitting: ORIGINAL
Pset_SlabCommon - IsExternal: no; LoadBearing: no; PitchAngle: 0 deg; Reference: A275 - Gitterrist
ePset_Simplebim - Assembly Level: Leaf
ePset_SimplebimBasicQuantities - Perimeter (Simplebim): 7164.65 mm; Volume, net (Simplebim): 0.115009 m3; Area, top, net (Simplebim): 2.87523 m2; Area, largest surface, net (Simplebim): 2.87523 m2; Area, sides, net (Simplebim): 0.286586 m2; Thickness (Simplebim): 40 mm
AVINOR - 08_Status: S4; 07_Fase: F90; 05_ID-nummer: +TS=251.008; 03_Ansvar: 72717; 02_Prosjekt: 72101; 06_Omrade: TS; 01_Lufthavnkode: ENGM

# IfcSlab: Floor:B251 - TRP 200 mm, Floor:B251 - TRP 200 mm:39240953
In: Nivå D
Type - PredefinedType: FLOOR; Material: _NSW Generell Gulv (Floor) 200 mm
Pset_ReinforcementBarPitchOfSlab - Reference: B251 - TRP 200 mm; sets with these values: 2
AVINOR - 07_Fase: F90; 03_Ansvar: FDV; 08_Status: S2; 06_Omrade: TS; 01_Lufthavnkode: ENGM
Pset_SlabCommon - IsExternal: no; LoadBearing: no; Reference: B251 - TRP 200 mm
ePset_Simplebim - Assembly Level: Leaf
ePset_LocationTool - Splitting: RESULT
ePset_SimplebimBasicQuantities - Area, top, net (Simplebim): 101.033 m2; Area, largest surface, net (Simplebim): 101.033 m2; Area, sides, net (Simplebim): 9.0321 m2; Perimeter (Simplebim): 45160.5 mm; Thickness (Simplebim): 200 mm; Volume, net (Simplebim): 20.2067 m3

# IfcSlab: HD400 (49)
In: D
Description: HD400; PredefinedType: FLOOR
ePset_SimplebimBasicQuantities - Thickness (Simplebim): 400 mm
Pset_SlabCommon - LoadBearing: no
Tekla Common - Top elevation: +203.800; Profile: HD400; Grade: C45/55; Name: HULLDEKKE; Bottom elevation: +203.400; Class: 162
ePset_Simplebim - Assembly Level: Leaf
AVINOR - 07_Fase: F90; 02_Prosjekt: T1; 03_Ansvar: FDV; 04_Kontrakt: FDV; 08_Status: S2; 06_Omrade: TS; 01_Lufthavnkode: ENGM
Name | Area, largest surface, net (Simplebim) (m2) | Perimeter (Simplebim) (mm) | Volume, net (Simplebim) (m3) | Area, top, net (Simplebim) (m2) | Area, sides, net (Simplebim) (m2) | Splitting | Reference = Part mark | Assembly mark
HULLDEKKE | 9.8966 | 86512.2 | 1.79155 | 14.0001 | 34.6049 | ORIGINAL | Concrete-8975 | HD-1607 | Material: CONCRETE/C45/55; Tekla Quantity - WEIGTH_GROSS: 4322.75 kg; WEIGTH_NET: 4299.73 kg; AREA_GROSS: 0 m2; AREA_NET: 58.8321 m2; VOLUME_GROSS: 1.80114 m3; Heigth: 400 mm; Width: 1200 mm; Length: 8520.01 mm; VOLUME_NET: 1.79155 m3
11 x HULLDEKKE | 9.94079 | 86741.7 | 1.79849 | 14.067 | 34.6967 | ORIGINAL | Concrete-323 | HD-981 | Material: CONCRETE/C45/55; Tekla Quantity - WEIGTH_GROSS: 4322.75 kg; WEIGTH_NET: 4316.38 kg; AREA_GROSS: 0 m2; AREA_NET: 59.035 m2; VOLUME_GROSS: 1.80114 m3; Heigth: 400 mm; Width: 1200 mm; Length: 8520.01 mm; VOLUME_NET: 1.79849 m3
HULLDEKKE | 9.69715 | 84420.8 | 1.75405 | 13.6978 | 33.7683 | ORIGINAL | Concrete-18388 | HD-3016 | Material: CONCRETE/C45/55; Tekla Quantity - WEIGTH_GROSS: 4322.75 kg; WEIGTH_NET: 4209.73 kg; AREA_GROSS: 0 m2; AREA_NET: 57.4693 m2; VOLUME_GROSS: 1.80114 m3; Heigth: 400 mm; Width: 1200 mm; Length: 8520.01 mm; VOLUME_NET: 1.75405 m3
HULLDEKKE | 8.47067 | 74069.7 | 1.53251 | 11.9866 | 29.6279 | ORIGINAL | Concrete-18404 | HD-3032 | Material: CONCRETE/C45/55; Tekla Quantity - WEIGTH_GROSS: 3683.46 kg; WEIGTH_NET: 3678.03 kg; AREA_GROSS: 0 m2; AREA_NET: 50.3668 m2; VOLUME_GROSS: 1.53478 m3; Heigth: 400 mm; Width: 1200 mm; Length: 7260 mm; VOLUME_NET: 1.53251 m3
HULLDEKKE | 4.41913 | 32843.3 | 0.924178 | 6.24071 | 13.1373 | RESULT | Concrete-323 | HD-981
11 x HULLDEKKE | 7.15247 | 52447.4 | 1.29402 | 10.1213 | 20.979 | RESULT | Concrete-323 | HD-981
HULLDEKKE | 7.15247 | 52447.4 | 1.29403 | 10.1213 | 20.979 | RESULT | Concrete-323 | HD-981
HULLDEKKE | 5.82256 | 43012.6 | 1.05141 | 8.19405 | 17.205 | RESULT | Concrete-18387 | HD-3015
HULLDEKKE | 7.15248 | 52447.5 | 1.29403 | 10.1213 | 20.979 | RESULT | Concrete-8971 | HD-1603
HULLDEKKE | 7.15246 | 52447.3 | 1.29402 | 10.1213 | 20.9789 | RESULT | Concrete-8955 | HD-1587
HULLDEKKE | 4.1586 | 32968.1 | 0.902469 | 5.71965 | 13.1872 | RESULT | Concrete-323 | HD-981
HULLDEKKE | 5.7798 | 45133.3 | 1.07389 | 7.9494 | 18.0533 | RESULT | Concrete-323 | HD-981
HULLDEKKE | 3.18219 | 23920.5 | 0.665495 | 4.4939 | 9.56821 | RESULT | Concrete-323 | HD-981
13 x HULLDEKKE | 5.15045 | 38062.5 | 0.93182 | 7.28829 | 15.225 | RESULT | Concrete-323 | HD-981
2 x HULLDEKKE | 1.69236 | 16380.4 | 0.336206 | 2.25363 | 6.55216 | RESULT | Concrete-8979 | HD-1611
HULLDEKKE | 2.99459 | 24005.4 | 0.649863 | 4.11868 | 9.60217 | RESULT | Concrete-323 | HD-981

# IfcSlab: PL40*530, STÅLRIST
In: D
Description: PL40*530; PredefinedType: FLOOR; Material: STEEL/Steel_Undefined
ePset_SimplebimBasicQuantities - Area, top, net (Simplebim): 0.898094 m2; Area, largest surface, net (Simplebim): 0.898094 m2; Area, sides, net (Simplebim): 0.17991 m2; Perimeter (Simplebim): 4497.76 mm; Volume, net (Simplebim): 0.0359238 m3; Thickness (Simplebim): 40 mm
Tekla Common - Class: 382; Name: STÅLRIST; Bottom elevation: +207.280; Part mark: DSR-50(?); Assembly mark: SR-42(?); Grade: Steel_Undefined; Profile: PL40*530; Top elevation: +207.320
ePset_LocationTool - Splitting: ORIGINAL
ePset_Simplebim - Assembly Level: Leaf
AVINOR - 08_Status: S4; 07_Fase: F90; 02_Prosjekt: T20100; 05_ID-nummer: +TS=222.012; 04_Kontrakt: 72233; 03_Ansvar: 72101; 06_Omrade: TS; 01_Lufthavnkode: ENGM
Pset_SlabCommon - LoadBearing: no; Reference: DSR-50(?)
Tekla Quantity - Length: 1810.74 mm; WEIGTH_NET: 282.002 kg; AREA_GROSS: 0.95969 m2; Heigth: 530.002 mm; VOLUME_NET: 0.03592 m3; VOLUME_GROSS: 0.03592 m3; WEIGTH_GROSS: 301.344 kg; AREA_NET: 1.9761 m2; Width: 40 mm

# IfcSlab: PL40*790, STÅLRIST
In: D
Description: PL40*790; PredefinedType: FLOOR; Material: STEEL/Steel_Undefined
ePset_LocationTool - Splitting: ORIGINAL
Tekla Quantity - VOLUME_GROSS: 0.04427 m3; VOLUME_NET: 0.04427 m3; AREA_NET: 2.39167 m2; WEIGTH_GROSS: 390.437 kg; WEIGTH_NET: 347.519 kg; AREA_GROSS: 1.24343 m2; Length: 1573.96 mm; Width: 40 mm; Heigth: 790 mm
Pset_SlabCommon - LoadBearing: no; Reference: DSR-51(?)
Tekla Common - Profile: PL40*790; Class: 382; Name: STÅLRIST; Bottom elevation: +207.280; Part mark: DSR-51(?); Assembly mark: SR-43(?); Grade: Steel_Undefined; Top elevation: +207.320
ePset_Simplebim - Assembly Level: Leaf
AVINOR - 08_Status: S4; 07_Fase: F90; 02_Prosjekt: T20100; 05_ID-nummer: +TS=222.012; 04_Kontrakt: 72233; 03_Ansvar: 72101; 06_Omrade: TS; 01_Lufthavnkode: ENGM
ePset_SimplebimBasicQuantities - Area, sides, net (Simplebim): 0.178174 m2; Area, top, net (Simplebim): 1.10675 m2; Area, largest surface, net (Simplebim): 1.10675 m2; Volume, net (Simplebim): 0.0442699 m3; Thickness (Simplebim): 40 mm; Perimeter (Simplebim): 4454.35 mm

# IfcSlab: PL40*800, STÅLRIST
In: D
Description: PL40*800; PredefinedType: FLOOR; Material: STEEL/Steel_Undefined
ePset_LocationTool - Splitting: ORIGINAL
ePset_SimplebimBasicQuantities - Perimeter (Simplebim): 3769.92 mm; Volume, net (Simplebim): 0.0335448 m3; Area, top, net (Simplebim): 0.838621 m2; Area, largest surface, net (Simplebim): 0.838621 m2; Thickness (Simplebim): 40 mm; Area, sides, net (Simplebim): 0.150797 m2
Tekla Quantity - VOLUME_GROSS: 0.03354 m3; VOLUME_NET: 0.03354 m3; WEIGTH_NET: 263.327 kg; AREA_NET: 1.82804 m2; Heigth: 799.998 mm; Length: 1223.47 mm; Width: 40 mm; AREA_GROSS: 0.97878 m2; WEIGTH_GROSS: 307.336 kg
ePset_Simplebim - Assembly Level: Leaf
Pset_SlabCommon - Reference: DSR-52(?); LoadBearing: no
Tekla Common - Part mark: DSR-52(?); Class: 382; Name: STÅLRIST; Bottom elevation: +207.280; Assembly mark: SR-44(?); Profile: PL40*800; Grade: Steel_Undefined; Top elevation: +207.320
AVINOR - 08_Status: S4; 07_Fase: F90; 02_Prosjekt: T20100; 05_ID-nummer: +TS=222.012; 04_Kontrakt: 72233; 03_Ansvar: 72101; 06_Omrade: TS; 01_Lufthavnkode: ENGM

# IfcSlab: PLANJA70 (69)
In: D
Description: PLANJA70; PredefinedType: FLOOR; Material: STEEL/S355
Pset_SlabCommon - LoadBearing: no
Tekla Common - Grade: S355; Profile: PLANJA70; Name: STÅLTAK; Class: 361
Tekla Quantity - AREA_GROSS: 0 m2; Heigth: 68.3 mm
ePset_Simplebim - Assembly Level: Leaf
ePset_SimplebimBasicQuantities - Thickness (Simplebim): 68.3 mm
ePset_LocationTool - Splitting: ORIGINAL
AVINOR - 07_Fase: F90; 06_Omrade: TS; 01_Lufthavnkode: ENGM
Name | Reference = Part mark | Assembly mark | Bottom elevation | Top elevation | VOLUME_GROSS (m3) | WEIGTH_GROSS (kg) | VOLUME_NET (m3) | Length (mm) | WEIGTH_NET (kg) | AREA_NET (m2) | Width (mm) | Area, top, net (Simplebim) (m2) | Area, sides, net (Simplebim) (m2) | Volume, net (Simplebim) (m3) | Area, largest surface, net (Simplebim) (m2) | Perimeter (Simplebim) (mm) | 08_Status | 02_Prosjekt | 05_ID-nummer | 04_Kontrakt | 03_Ansvar
STÅLTAK | DST-328(?) | ST-380(?) | +206.800 | +206.868 | 0.00362 | 28.4274 | 0.00282 | 3190 | 22.0339 | 5.62187 | 590 | 1.4518 | 2.71827 | 0.00280687 | 0.253286 | 39799 | S4 | T20100 | +TS=222.012 | 72233 | 72101
7 x STÅLTAK | DST-306(?) | ST-364(?) | +206.800 | +206.868 | 0.00362 | 28.4274 | 0.00362 | 3190 | 28.4274 | 7.25129 | 750 | 1.82 | 3.61129 | 0.00362132 | 0.253286 | 52874 | S4 | T20100 | +TS=222.012 | 72233 | 72101
STÅLTAK | DST-65(?) | ST-130(?) | +206.800 | +206.868 | 0.0034 | 26.6956 | 0.00109 | 2995.66 | 8.56929 | 2.19642 | 239.996 | 0.546381 | 1.10582 | 0.00109163 | 0.237855 | 16190.6 | S2 | T1 |  | FDV | FDV
23 x STÅLTAK | DST-36(?) | ST-101(?) | +206.800 | +206.868 | 0.0034 | 26.6956 | 0.0034 | 2995.66 | 26.6956 | 6.80968 | 750 | 1.70912 | 3.39143 | 0.00340071 | 0.237855 | 49654.9 | S2 | T1 |  | FDV | FDV
4 x STÅLTAK | DST-71(?) | ST-136(?) | +206.925 | +206.993 | 0.00329 | 25.8431 | 0.00132 | 2900 | 10.4112 | 2.65925 | 312.78 | 0.711808 | 1.23563 | 0.00132627 | 0.23026 | 18091.2 | S4 | T20100 | +TS=255.010 | 72274 | 72101
32 x STÅLTAK | DST-56(?) | ST-121(?) | +206.925 | +206.993 | 0.00329 | 25.8431 | 0.00329 | 2900 | 25.8431 | 6.5923 | 750 | 1.65455 | 3.28321 | 0.00329211 | 0.23026 | 48070.4 | S4 | T20100 | +TS=255.010 | 72274 | 72101
STÅLTAK | DST-35(?) | ST-100(?) | +206.800 | +206.868 | 0.00363 | 28.4778 | 0.00363 | 3195.66 | 28.4778 | 7.26416 | 750 | 1.82323 | 3.6177 | 0.00362775 | 0.253735 | 52967.8 | S2 | T1 |  | FDV | FDV

# IfcSlab: PLANNJA200 (15)
In: D
Description: PLANNJA200; PredefinedType: FLOOR
Tekla Common - Grade: S355; Name: STÅLTAK; Profile: PLANNJA200; Class: 361; Top elevation: +207.299; Bottom elevation: +207.100
Pset_SlabCommon - LoadBearing: no
ePset_Simplebim - Assembly Level: Leaf
AVINOR - 07_Fase: F90; 06_Omrade: TS; 01_Lufthavnkode: ENGM
Name | Material | Assembly mark | Part mark = Reference | Thickness (Simplebim) (mm) | Volume, net (Simplebim) (m3) | Perimeter (Simplebim) (mm) | Area, largest surface, net (Simplebim) (m2) | Area, sides, net (Simplebim) (m2) | Area, top, net (Simplebim) (m2) | VOLUME_GROSS (m3) | AREA_GROSS (m2) | Width (mm) | WEIGTH_NET (kg) | AREA_NET (m2) | WEIGTH_GROSS (kg) | Heigth (mm) | Length (mm) | VOLUME_NET (m3) | Splitting | 02_Prosjekt | 03_Ansvar | 04_Kontrakt | 08_Status
STÅLTAK | STEEL/S355 | ST-497(?) | DST-510(?) | 1979.76 | 0.000887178 | 429.889 | 0.423135 | 0.851079 | 0.464062 | 0.00362 | 7.24052 | 310.352 | 6.96435 | 1.77923 | 28.3882 | 199 | 2037.16 | 0.00089 | ORIGINAL | T1 | FDV | FDV | S2
STÅLTAK | STEEL/S355 | ST-498(?) | DST-511(?) | 199 | 0.000769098 | 3217.02 | 0.382636 | 0.640188 | 0.451285 | 0.00233 | 4.66993 | 1059.72 | 6.03742 | 1.54281 | 18.3041 | 199 | 1059.72 | 0.00077 | ORIGINAL | T20100 | 72101 | 72717 | S4 | AVINOR - 05_ID-nummer: +TS=251.020
STÅLTAK | STEEL/S355 | ST-499(?) | DST-512(?) | 199 | 0.00395 | 15819.5 | 1.23671 | 3.14808 | 2.38058 | 0.00416 | 8.35856 | 1600 | 31.0075 | 7.90927 | 32.7711 | 199 | 2825.28 | 0.00396 | ORIGINAL | T20100 | 72101 | 72717 | S4 | AVINOR - 05_ID-nummer: +TS=251.020
STÅLTAK | STEEL/S355 | ST-500(?) | DST-513(?) | 199 | 0.00824299 | 32496.8 | 2.51816 | 6.46687 | 5.0164 | 0.00827 | 16.556 | 1600 | 64.7075 | 16.4995 | 64.9301 | 199 | 4839.04 | 0.00823 | ORIGINAL | T20100 | 72101 | 72717 | S4 | AVINOR - 05_ID-nummer: +TS=251.020
STÅLTAK | STEEL/S355 | ST-510(?) | DST-523(?) | 199 | 0.00523817 | 20707.7 | 1.53017 | 4.12083 | 3.18247 | 0.00524 | 10.4858 | 1600 | 41.1197 | 10.4858 | 41.1197 | 199 | 2841.92 | 0.00524 | ORIGINAL | T1 | FDV | FDV | S2
STÅLTAK | STEEL/S355 | ST-509(?) | DST-522(?) | 199 | 0.0070568 | 27889.4 | 2.03013 | 5.54998 | 4.28739 | 0.00706 | 14.1248 | 1600 | 55.3959 | 14.1248 | 55.3959 | 199 | 3720.65 | 0.00705 | ORIGINAL | T1 | FDV | FDV | S2
STÅLTAK | STEEL/S355 | ST-508(?) | DST-521(?) | 199 | 0.00904364 | 35735.4 | 2.57845 | 7.11134 | 5.4945 | 0.00904 | 18.1003 | 1600 | 70.9926 | 18.1003 | 70.9926 | 199 | 4688 | 0.00904 | ORIGINAL | T1 | FDV | FDV | S2
STÅLTAK | STEEL/S355 | ST-507(?) | DST-520(?) | 199 | 0.0112336 | 44383.8 | 3.18482 | 8.83237 | 6.82504 | 0.01123 | 22.4825 | 1600 | 88.1841 | 22.4825 | 88.1841 | 199 | 5761.07 | 0.01123 | ORIGINAL | T1 | FDV | FDV | S2
STÅLTAK | STEEL/S355 | ST-506(?) | DST-519(?) | 199 | 0.0137128 | 54174.2 | 3.87409 | 10.7807 | 8.33127 | 0.01371 | 27.4432 | 1600 | 107.646 | 27.4432 | 107.646 | 199 | 6985.65 | 0.01372 | ORIGINAL | T1 | FDV | FDV | S2
STÅLTAK | STEEL/S355 | ST-505(?) | DST-518(?) | 199 | 0.0165195 | 65258 | 4.65282 | 12.9863 | 10.0365 | 0.01652 | 33.0593 | 1600 | 129.678 | 33.0593 | 129.678 | 199 | 8366.44 | 0.01652 | ORIGINAL | T1 | FDV | FDV | S2
STÅLTAK | STEEL/S355 | ST-468(?) | DST-481(?) | 199 | 0.0189305 | 74604.4 | 5.15617 | 14.8463 | 11.5183 | 0.01912 | 38.2773 | 1600 | 148.604 | 37.8828 | 150.152 | 199 | 8889.95 | 0.01894 | ORIGINAL | T1 | FDV | FDV | S2
2 x STÅLTAK | STEEL/S355 | ST-111(?) | DST-46(?) | 199 | 0.0191278 | 75554.1 | 5.1562 | 15.0353 | 11.6211 | 0.01912 | 38.2775 | 1600 | 150.153 | 38.2775 | 150.153 | 199 | 8890 | 0.01912 | ORIGINAL | T1 | FDV | FDV | S2
STÅLTAK |  | ST-111(?) | DST-46(?) | 199 | 0.0148316 | 56688.5 | 5.1562 | 11.281 | 9.20169 |  |  |  |  |  |  |  |  |  | RESULT | T1 | FDV | FDV | S2
STÅLTAK |  | ST-501(?) | DST-514(?) | 199 | 0.00755232 | 30036.8 | 2.7314 | 5.97733 | 4.56996 |  |  |  |  |  |  |  |  |  | RESULT | T20100 | 72101 | 72717 | S4 | AVINOR - 05_ID-nummer: +TS=251.020

# IfcSystem (29)
Name | Description
+TS=360.060 T_2 | +TS=360.060 T_2
+JU=360.011 T | +JU=360.011 T
+TS=360.010 A | +TS=360.010 A
+JU=360.010 A | +JU=360.010 A
+TS=360.030 T | +TS=360.030 T
+TS=360.030 A | +TS=360.030 A
36= Avtrekk 53 | 36= Avtrekk 53
36= Avtrekk 71 | 36= Avtrekk 71
36= Avtrekk 77 | 36= Avtrekk 77
Mechanical 36 Avtrekk 2 | Mechanical 36 Avtrekk 2
+TS=332.002 | +TS=332.002
+TS=332.005 | +TS=332.005
+TS=332.008 | +TS=332.008
+TU=332.003-NZ0004 | +TU=332.003-NZ0004
+TS=332.007 - 1 (10) | +TS=332.007 - 1 (10)
33= Våt Kopi 39 | 33= Våt Kopi 39
33= tørr Kopi 1 | 33= tørr Kopi 1
33= tørr Kopi 4 | 33= tørr Kopi 4
33= tørr Kopi 2 | 33= tørr Kopi 2
- | 574 | MagiCAD Pset_System - Code: 574; AVINOR - 08_Status: S4; 07_Fase: F90; 04_Kontrakt: 72512; 02_Prosjekt: 72101; 01_Lufthavnkode: ENGM; 05_ID-nummer: +TS=574.006-WD0276
Brannalarm | 542 | MagiCAD Pset_System - Code: 542; Description: Brannalarm; AVINOR - 08_Status: S2; 07_Fase: F90; 04_Kontrakt: FDV; 02_Prosjekt: 72101; 01_Lufthavnkode: ENGM; 05_ID-nummer: +TO=542.024
3
4
10
Adgangskontroll, Innbruddsalarm | 543 | MagiCAD Pset_System - Code: 543; Description: Adgangskontroll, Innbruddsalarm; AVINOR - 08_Status: S4; 07_Fase: F90; 04_Kontrakt: 72561; 02_Prosjekt: 72101; 01_Lufthavnkode: ENGM; 05_ID-nummer: +TS=543.003-QG6301; 03_Ansvar: T20100
Bæresystem generelt | 4119 | MagiCAD Pset_System - Code: 4119; Description: Bæresystem generelt
Armaturskinne | 4116 | MagiCAD Pset_System - Code: 4116; Description: Armaturskinne
Bæresystem for elkraft | 4111 | MagiCAD Pset_System - Code: 4111; Description: Bæresystem for elkraft
Veggkanal for generelt | 4112 | MagiCAD Pset_System - Code: 4112; Description: Veggkanal for generelt

# IfcWall: 60*360, ISOLASJON
In: D
Description: 60*360
ePset_SimplebimBasicQuantities - Volume, net (Simplebim): 0.080946 m3; Area, side, gross, AABB (Simplebim): 1.34928 m2; Area, side, gross, smaller (Simplebim): 1.3491 m2; Area, side, net, larger (Simplebim): 1.3491 m2; Area, side, gross, larger (Simplebim): 1.3491 m2; Area, side, net, smaller (Simplebim): 1.3491 m2; Area, side, gross, average (Simplebim): 1.3491 m2; Area, side, net, average (Simplebim): 1.3491 m2; Area, largest surface, net (Simplebim): 1.3491 m2; Thickness (Simplebim): 60 mm; Length (Simplebim): 360 mm; Height (Simplebim): 3748 mm
Tekla Common - Class: 699; Grade: MINERALULL; Top elevation: +203.155; Name: ISOLASJON; Profile: 60*360; Assembly mark: IMU-8(?); Part mark: Concrete-19683(?); Bottom elevation: +203.095
AVINOR - 08_Status: S4; 07_Fase: F90; 02_Prosjekt: T20100; 05_ID-nummer: +TS=223.013; 04_Kontrakt: 72233; 03_Ansvar: 72101; 06_Omrade: TS; 01_Lufthavnkode: ENGM
ePset_LocationTool - Splitting: RESULT
ePset_Simplebim - Assembly Level: Leaf
Pset_WallCommon - LoadBearing: no; Reference: Concrete-19683(?)

# IfcWall: 810*300, PLASSTØPTVEGG
In: A
Description: 810*300; Material: CONCRETE/C35/45
Tekla Common - Name: PLASSTØPTVEGG; Top elevation: +203.780; Part mark: Concrete-18144; Bottom elevation: +202.970; Class: 250; Assembly mark: PLV-2677; Grade: C35/45; Profile: 810*300
ePset_LocationTool - Splitting: ORIGINAL
Tekla Quantity - AREA_GROSS: 2.04001 m2; AREA_NET: 2.04001 m2; WEIGTH_GROSS: 408.243 kg; WEIGTH_NET: 408.243 kg; VOLUME_GROSS: 0.1701 m3; VOLUME_NET: 0.1701 m3; Length: 700.005 mm; Width: 300 mm; Heigth: 810 mm
ePset_Simplebim - Assembly Level: Leaf
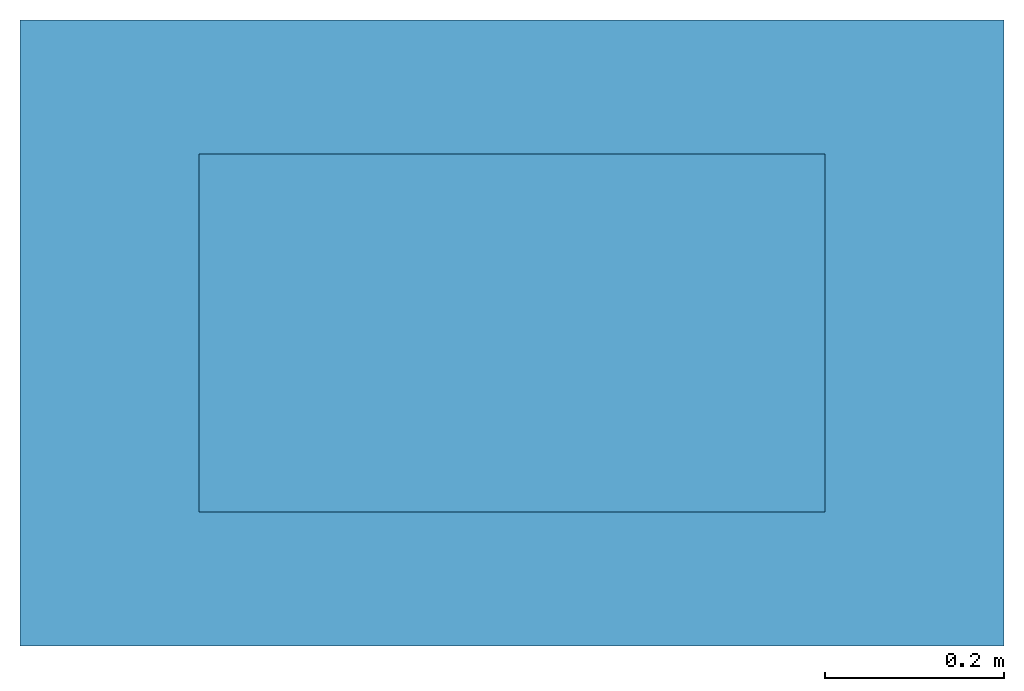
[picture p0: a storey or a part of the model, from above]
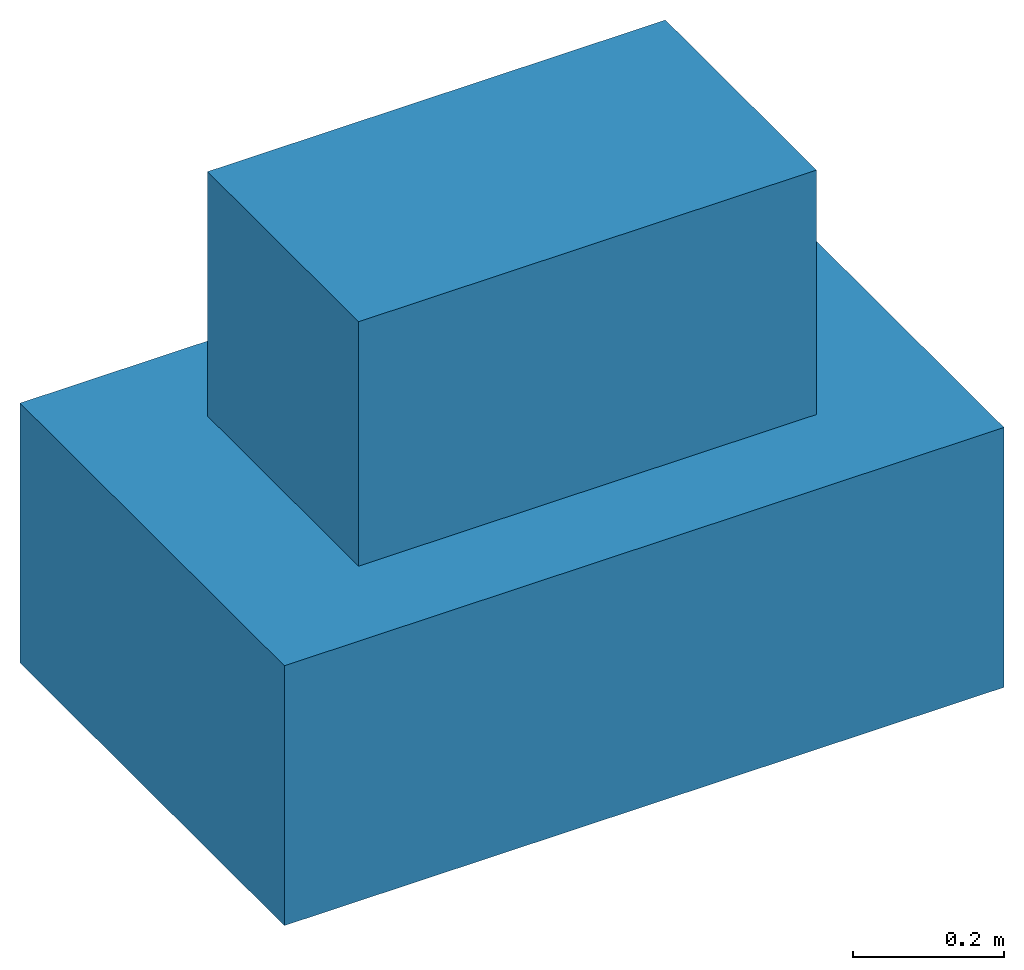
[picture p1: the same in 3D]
Properties of the parts of a building model (IFC2X3), part 5 of 5

# IfcWall: 810*300, PLASSTØPTVEGG
ePset_SimplebimBasicQuantities - Volume, net (Simplebim): 0.1701 m3; Area, side, gross, AABB (Simplebim): 0.567 m2; Area, side, net, smaller (Simplebim): 0.567 m2; Area, side, gross, average (Simplebim): 0.567 m2; Area, side, net, average (Simplebim): 0.567 m2; Area, largest surface, net (Simplebim): 0.567 m2; Area, side, gross, smaller (Simplebim): 0.567 m2; Area, side, net, larger (Simplebim): 0.567 m2; Area, side, gross, larger (Simplebim): 0.567 m2; Thickness (Simplebim): 300 mm; Height (Simplebim): 810 mm; Length (Simplebim): 700 mm
Pset_WallCommon - Reference: Concrete-18144; LoadBearing: no
AVINOR - 07_Fase: F90; 02_Prosjekt: T1; 04_Kontrakt: FDV; 03_Ansvar: FDV; 08_Status: S2; 06_Omrade: TS; 01_Lufthavnkode: ENGM

# IfcWall: 8880*300, PLASSTØPTVEGG
In: A
Description: 8880*300
ePset_SimplebimBasicQuantities - Area, side, gross, AABB (Simplebim): 3.35712 m2; Volume, net (Simplebim): 1.00721 m3; Thickness (Simplebim): 300 mm; Height (Simplebim): 780 mm; Length (Simplebim): 4304 mm; Area, side, gross, larger (Simplebim): 3.35737 m2; Area, side, gross, smaller (Simplebim): 3.35737 m2; Area, side, net, larger (Simplebim): 3.35737 m2; Area, side, net, smaller (Simplebim): 3.35737 m2; Area, side, net, average (Simplebim): 3.35737 m2; Area, largest surface, net (Simplebim): 3.35737 m2; Area, side, gross, average (Simplebim): 3.35737 m2
Pset_WallCommon - Reference: Concrete-7854; LoadBearing: no
Tekla Common - Bottom elevation: +194.900; Name: PLASSTØPTVEGG; Part mark: Concrete-7854; Profile: 8880*300; Top elevation: +203.780; Class: 250; Assembly mark: PLV-2677; Grade: C35/45
ePset_Simplebim - Assembly Level: Leaf
ePset_LocationTool - Splitting: RESULT
AVINOR - 07_Fase: F90; 02_Prosjekt: T1; 04_Kontrakt: FDV; 03_Ansvar: FDV; 08_Status: S2; 06_Omrade: TS; 01_Lufthavnkode: ENGM

# IfcWall: A245 - InPlace - kledning:A245 - InPlace - kledning, A245 - InPlace - kledning:A245 - InPlace - kledning:39324670
In: Nivå D + 1,2 m
Type - Material: _NSW INNDELING GENERISK SKILTING
Pset_WallCommon - Reference: A245 - InPlace - kledning; IsExternal: no
Pset_ReinforcementBarPitchOfWall - Reference: A245 - InPlace - kledning; sets with these values: 2
ePset_LocationTool - Splitting: RESULT
ePset_Simplebim - Assembly Level: Leaf
AVINOR - 08_Status: S4; 07_Fase: F90; 05_ID-nummer: +TS=245.103; 03_Ansvar: 72717; 02_Prosjekt: 72101; 06_Omrade: TS; 01_Lufthavnkode: ENGM
ePset_SimplebimBasicQuantities - Area, largest surface, net (Simplebim): 1.07977 m2; Volume, net (Simplebim): 0.862336 m3

# IfcWall: B250 - InPlace - stålkonstruksjon:B250 - InPlace - stålkonstruksjon, B250 - InPlace - stålkonstruksjon:B250 - InPlace - stålkonstruksjon:39324565
In: Nivå D + 1,2 m
Pset_WallCommon - Reference: B250 - InPlace - stålkonstruksjon; IsExternal: no
ePset_Simplebim - Assembly Level: Leaf
ePset_LocationTool - Splitting: RESULT
Pset_ReinforcementBarPitchOfWall - Reference: B250 - InPlace - stålkonstruksjon; sets with these values: 2
AVINOR - 08_Status: S4; 07_Fase: F90; 03_Ansvar: 72717; 02_Prosjekt: 72101; 06_Omrade: TS; 01_Lufthavnkode: ENGM
ePset_SimplebimBasicQuantities - Area, largest surface, net (Simplebim): 3.65515 m2; Volume, net (Simplebim): 2.19309 m3

# IfcWall: Basic Wall:A241 - F (p-0) (2)
Type - PredefinedType: STANDARD; Material: T2_Gips Protect F 15 mm
AVINOR - 07_Fase: F90; 03_Ansvar: FDV; 06_Omrade: TS; 01_Lufthavnkode: ENGM
Pset_QuantityTakeOff - Reference: A241 - F (p-0); sets with these values: 2
ePset_Simplebim - Assembly Level: Leaf
ePset_LocationTool - Splitting: RESULT
Pset_WallCommon - Reference: A241 - F (p-0); IsExternal: no; ExtendToStructure: no; LoadBearing: no
ePset_SimplebimBasicQuantities - Thickness (Simplebim): 14 mm
Name (Basic Wall:A241 - F (p-0):...) | In | 08_Status | Area, side, net, smaller (Simplebim) (m2) = Area, side, gross, average (Simplebim) (m2) = Area, largest surface, net (Simplebim) (m2) = Area, side, net, average (Simplebim) (m2) = Area, side, net, larger (Simplebim) (m2) = Area, side, gross, smaller (Simplebim) (m2) = Area, side, gross, larger (Simplebim) (m2) | Area, side, gross, AABB (Simplebim) (m2) | Volume, net (Simplebim) (m3) | Length (Simplebim) (mm) | Height (Simplebim) (mm)
27009504 | Nivå E | S2 | 0.0303875 | 0.030355 | 0.000455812 | 65 | 467 | AVINOR - 04_Kontrakt: 72274
42411617 | Nivå D | S1 | 0.508043 | 0.509376 | 0.00762064 | 4548 | 112

# IfcWall: Basic Wall:A241 - FVF-100 (100/100 p-p), Basic Wall:A241 - FVF-100 (100/100 p-p):27009079
In: Nivå E
Type - PredefinedType: STANDARD; Material: T2_Gips Protect F 15 mm, _NSW Stålstender, uisolert 100 mm, T2_Gips Protect F 15 mm
Type - Pset_ReinforcementBarPitchOfWall - Description: Tilsvarende: T2 - IVEGG-150 - Forprosjekt
AVINOR - 07_Fase: F90; 03_Ansvar: FDV; 08_Status: S2; 04_Kontrakt: 72274; 06_Omrade: TS; 01_Lufthavnkode: ENGM
Pset_ReinforcementBarPitchOfWall - Reference: A241 - FVF-100 (100/100 p-p); sets with these values: 2
ePset_SimplebimBasicQuantities - Area, side, gross, AABB (Simplebim): 0.129359 m2; Volume, net (Simplebim): 0.0168633 m3; Area, side, gross, larger (Simplebim): 0.129718 m2; Area, side, gross, smaller (Simplebim): 0.129718 m2; Area, side, net, larger (Simplebim): 0.129718 m2; Area, side, net, smaller (Simplebim): 0.129718 m2; Area, side, net, average (Simplebim): 0.129718 m2; Area, largest surface, net (Simplebim): 0.129718 m2; Area, side, gross, average (Simplebim): 0.129718 m2; Thickness (Simplebim): 130 mm; Height (Simplebim): 467 mm; Length (Simplebim): 277 mm
ePset_LocationTool - Splitting: RESULT
Pset_WallCommon - Reference: A241 - FVF-100 (100/100 p-p); IsExternal: no; ExtendToStructure: no; LoadBearing: no
ePset_Simplebim - Assembly Level: Leaf

# IfcWall: Basic Wall:A241 - IVG-30 (12)
In: Nivå E
Type - PredefinedType: STANDARD; Material: X Visualiseringbrannskille NO_strukturGlass EI60 6 mm, X brannsikre gel_brannskille NO_EI 60 6.5 mm, X Visualiseringbrannskille NO_strukturGlass EI60 6 mm, X brannsikre gel_brannskille NO_EI 60 6.5 mm, X Visualiseringbrannskille NO_strukturGlass EI60 6 mm
Type - Pset_ReinforcementBarPitchOfWall - Description: Strukturløst EI60 Glass
ePset_LocationTool - Splitting: RESULT
Pset_ReinforcementBarPitchOfWall - Reference: A241 - IVG-30; sets with these values: 2
Pset_WallCommon - IsExternal: no; ExtendToStructure: no; LoadBearing: no; Reference: A241 - IVG-30
ePset_SimplebimBasicQuantities - Height (Simplebim): 330 mm
ePset_Simplebim - Assembly Level: Leaf
Name (Basic Wall:A241 - IVG-30:...) | 07_Fase | 03_Ansvar | 08_Status | 04_Kontrakt | 06_Omrade | 01_Lufthavnkode | Area, side, net, smaller (Simplebim) (m2) = Area, side, gross, average (Simplebim) (m2) = Area, side, net, average (Simplebim) (m2) = Area, largest surface, net (Simplebim) (m2) = Area, side, gross, smaller (Simplebim) (m2) = Area, side, net, larger (Simplebim) (m2) = Area, side, gross, larger (Simplebim) (m2) | Area, side, gross, AABB (Simplebim) (m2) | Volume, net (Simplebim) (m3) | Thickness (Simplebim) (mm) | Length (Simplebim) (mm) | CQFireRequirement
25856773 | F90 | FDV | S2 | 72274 | TS | ENGM | 0.47982 | 0.47982 | 0.0148744 | 30 | 1454 | EI 60/ A2-s1,d0
25856781 | F90 | FDV | S2 | 72274 | TS | ENGM | 0.47982 | 0.47982 | 0.0148744 | 30 | 1454 | EI 60/ A2-s1,d0
24440734 | F90 | FDV | S2 | 72274 | TS | ENGM | 0.47982 | 0.47982 | 0.0148744 | 30 | 1454 | EI 60/ A2-s1,d0
25851208 | F90 | FDV | S2 | 72274 | TS | ENGM | 0.47982 | 0.47982 | 0.0148744 | 30 | 1454 | EI 60/ A2-s1,d0
25851318 | F90 | FDV | S2 | 72274 | TS | ENGM | 0.47982 | 0.47982 | 0.0148744 | 30 | 1454 | EI 60/ A2-s1,d0
25851461 | F90 | FDV | S2 | 72274 | TS | ENGM | 0.47982 | 0.47982 | 0.0148744 | 30 | 1454 | EI 60/ A2-s1,d0
25856780 | F90 | FDV | S2 | 72274 | TS | ENGM | 0.461497 | 0.46134 | 0.0143064 | 30 | 1398 | EI 60/ A2-s1,d0
25850842 | F90 | FDV | S2 | 72274 | TS | ENGM | 0.158725 | 0.15873 | 0.00492048 | 30 | 481 | EI 60/ A2-s1,d0
25850964 | F90 | FDV | S2 | 72274 | TS | ENGM | 0.63459 | 0.63459 | 0.0196723 | 30 | 1923 | EI 60/ A2-s1,d0
25851068 | F90 | FDV | S2 | 72274 | TS | ENGM | 0.47982 | 0.47982 | 0.0148744 | 31 | 1454 | EI 60/ A2-s1,d0
65072614 |  |  |  |  |  |  | 0.32109 | 0.32109 | 0.00995379 | 30 | 973
24440735 | F90 | FDV | S2 | 72274 | TS | ENGM | 0.47982 | 0.47982 | 0.0148744 | 30 | 1454 | EI 60/ A2-s1,d0

# IfcWall: Basic Wall:A241 - MH-142 (Multiblokk 142) (2)
In: Nivå C + 2,03 m
Type - PredefinedType: STANDARD; Material: Betong - Multiblokk 142 mm
Type - Pset_ReinforcementBarPitchOfWall - Description: Hulmur murblokk
ePset_LocationTool - Splitting: RESULT
AVINOR - 07_Fase: F90; 03_Ansvar: FDV; 08_Status: S2; 06_Omrade: TS; 01_Lufthavnkode: ENGM
Identity Data - CQFireRequirement: EI 60/ A2-s1,d0
Pset_WallCommon - IsExternal: no; ExtendToStructure: no; LoadBearing: no; Reference: A241 - MH-142 (Multiblokk 142)
ePset_Simplebim - Assembly Level: Leaf
Pset_QuantityTakeOff - Reference: A241 - MH-142 (Multiblokk 142); sets with these values: 2
ePset_SimplebimBasicQuantities - Thickness (Simplebim): 142 mm; Height (Simplebim): 400 mm
Name (Basic Wall:A241 - MH-142 (Multiblokk 142):...) | Area, side, gross, AABB (Simplebim) (m2) | Volume, net (Simplebim) (m3) | Area, side, gross, average (Simplebim) (m2) = Area, largest surface, net (Simplebim) (m2) = Area, side, net, average (Simplebim) (m2) = Area, side, net, smaller (Simplebim) (m2) = Area, side, net, larger (Simplebim) (m2) = Area, side, gross, smaller (Simplebim) (m2) = Area, side, gross, larger (Simplebim) (m2) | Length (Simplebim) (mm)
2419419 | 1.8332 | 0.260333 | 1.83333 | 4583
2419421 | 1.5864 | 0.225297 | 1.5866 | 3966

# IfcWall: Basic Wall:A241 - MK-142 (Multiblokk 142) (6)
In: Nivå C + 2,03 m
Type - PredefinedType: STANDARD; Material: Betong - Multiblokk 142 mm
Type - Pset_ReinforcementBarPitchOfWall - Description: Uisolert murblokk
Identity Data - CQFireRequirement: REI 120-M/ A2-s1,d0
ePset_SimplebimBasicQuantities - Thickness (Simplebim): 142 mm; Height (Simplebim): 400 mm
AVINOR - 07_Fase: F90; 03_Ansvar: FDV; 08_Status: S2; 06_Omrade: TS; 01_Lufthavnkode: ENGM
Pset_WallCommon - Reference: A241 - MK-142 (Multiblokk 142); IsExternal: no; ExtendToStructure: no; LoadBearing: no
Pset_QuantityTakeOff - Reference: A241 - MK-142 (Multiblokk 142); sets with these values: 2
ePset_LocationTool - Splitting: RESULT
ePset_Simplebim - Assembly Level: Leaf
Name (Basic Wall:A241 - MK-142 (Multiblokk 142):...) | Area, side, net, smaller (Simplebim) (m2) = Area, side, gross, average (Simplebim) (m2) = Area, largest surface, net (Simplebim) (m2) = Area, side, net, average (Simplebim) (m2) = Area, side, net, larger (Simplebim) (m2) = Area, side, gross, smaller (Simplebim) (m2) = Area, side, gross, larger (Simplebim) (m2) | Length (Simplebim) (mm) | Area, side, gross, AABB (Simplebim) (m2) | Volume, net (Simplebim) (m3)
2419424 | 0.98708 | 2468 | 0.9872 | 0.140165
2419425 | 0.7768 | 1942 | 0.7768 | 0.110306
2419422 | 0.98708 | 2468 | 0.9872 | 0.140165
2419420 | 2.315 | 5788 | 2.3152 | 0.32873
2418302 | 3.32 | 8300 | 3.32 | 0.47144
2418303 | 1.098 | 2745 | 1.098 | 0.155915

# IfcWall: Basic Wall:A241 - RVS-121 (2)
Type - PredefinedType: STANDARD; Material: T2_Gips Fibergips 12.5 mm, Plate - Gips 12.5 mm, _NSW Stålstender, uisolert 120 mm, Plate - Gips 12.5 mm, Plate - Gips 12.5 mm
Type - Pset_ReinforcementBarPitchOfWall - Description: Stendervegg: 2x12.5mm Gipsplater - 100mm Stålstender - 2x12.5mm Gipsplater
AVINOR - 07_Fase: F90; 03_Ansvar: FDV; 08_Status: S2; 04_Kontrakt: 72274; 06_Omrade: TS; 01_Lufthavnkode: ENGM
ePset_LocationTool - Splitting: RESULT
Pset_QuantityTakeOff - Reference: A241 - RVS-121; sets with these values: 2
Pset_WallCommon - Reference: A241 - RVS-121; IsExternal: no; ExtendToStructure: no; LoadBearing: no
ePset_Simplebim - Assembly Level: Leaf
ePset_SimplebimBasicQuantities - Thickness (Simplebim): 170 mm; Length (Simplebim): 3380 mm
Name (Basic Wall:A241 - RVS-121:...) | In | Volume, net (Simplebim) (m3) | Area, side, gross, larger (Simplebim) (m2) = Area, side, gross, smaller (Simplebim) (m2) = Area, side, net, larger (Simplebim) (m2) = Area, side, net, smaller (Simplebim) (m2) = Area, side, net, average (Simplebim) (m2) = Area, largest surface, net (Simplebim) (m2) = Area, side, gross, average (Simplebim) (m2) | Height (Simplebim) (mm) | Area, side, gross, AABB (Simplebim) (m2)
23909413 | Nivå D + 1,2 m | 1.03434 | 6.08434 | 1800 | 6.084
23909413 | Nivå D | 0.689559 | 4.05623 | 1200 | 4.056

# IfcWall: Basic Wall:A241 - S (g-0) (2)
Type - PredefinedType: STANDARD; Material: T2_Gips Standard 12.5 mm
Type - Pset_ReinforcementBarPitchOfWall - Description: 1 lag gips
ePset_SimplebimBasicQuantities - Length (Simplebim): 3196.59 mm; Thickness (Simplebim): 12.5 mm
Pset_WallCommon - IsExternal: no; ExtendToStructure: no; LoadBearing: no; Reference: A241 - S (g-0)
AVINOR - 08_Status: S4; 07_Fase: F40; 03_Ansvar: LEIETAKER; 02_Prosjekt: 72101; 06_Omrade: TS; 01_Lufthavnkode: ENGM
ePset_LocationTool - Splitting: ORIGINAL
ePset_Simplebim - Assembly Level: Leaf
Pset_ReinforcementBarPitchOfWall - Reference: A241 - S (g-0); sets with these values: 2
Name (Basic Wall:A241 - S (g-0):...) | In | Volume, net (Simplebim) (m3) | Area, largest surface, net (Simplebim) (m2) = Area, side, gross, larger (Simplebim) (m2) = Area, side, net, larger (Simplebim) (m2) | Area, side, gross, average (Simplebim) (m2) = Area, side, net, average (Simplebim) (m2) | Area, side, gross, AABB (Simplebim) (m2) | Height (Simplebim) (mm) | Area, side, gross, smaller (Simplebim) (m2) = Area, side, net, smaller (Simplebim) (m2)
42214591 | Nivå D | 0.0379687 | 3.04071 | 3.0375 | 3.83591 | 1200 | 3.03428
42214591 | Nivå D + 1,2 m | 0.0431148 | 3.45267 | 3.44919 | 4.15557 | 1300 | 3.4457

# IfcWall: Basic Wall:A241 - SVS-200 (T1) (200/100x2 gg-gg) (2)
Type - PredefinedType: STANDARD; Material: Plate - Gips 12.5 mm, Plate - Gips 12.5 mm, _NSW Stålstender, uisolert 200 mm, Plate - Gips 12.5 mm, Plate - Gips 12.5 mm
Type - Pset_ReinforcementBarPitchOfWall - Description: Stendervegg: 2x12.5mm Gipsplater - 200mm Svill, 100mm Stålstender - 2x12.5mm Gipsplater
ePset_SimplebimBasicQuantities - Thickness (Simplebim): 250 mm; Length (Simplebim): 6368 mm
AVINOR - 07_Fase: F90; 03_Ansvar: FDV; 08_Status: S2; 06_Omrade: TS; 01_Lufthavnkode: ENGM
ePset_LocationTool - Splitting: RESULT
Identity Data - CQFireRequirement: EI 60/ A2-s1,d0
ePset_Simplebim - Assembly Level: Leaf
Pset_QuantityTakeOff - Reference: A241 - SVS-200 (T1) (200/100x2 gg-gg); sets with these values: 2
Pset_WallCommon - IsExternal: no; ExtendToStructure: no; LoadBearing: no; Reference: A241 - SVS-200 (T1) (200/100x2 gg-gg)
Name (Basic Wall:A241 - SVS-200 (T1) (200/100x2 gg-gg):...) | In | Area, side, gross, average (Simplebim) (m2) = Area, largest surface, net (Simplebim) (m2) = Area, side, net, average (Simplebim) (m2) = Area, side, net, smaller (Simplebim) (m2) = Area, side, net, larger (Simplebim) (m2) = Area, side, gross, smaller (Simplebim) (m2) = Area, side, gross, larger (Simplebim) (m2) | Volume, net (Simplebim) (m3) | Height (Simplebim) (mm) | Area, side, gross, AABB (Simplebim) (m2)
24437332 | Nivå D + 1,2 m | 10.6158 | 2.65394 | 1667 | 10.6155
24437332 | Nivå D | 7.64183 | 1.91046 | 1200 | 7.6416

# IfcWall: Basic Wall:A241 - SVS-76 (2)
Type - PredefinedType: STANDARD; Material: Plate - Gips 12.5 mm, Plate - Gips 12.5 mm, _NSW Stålstender, uisolert 75 mm, Plate - Gips 12.5 mm, Plate - Gips 12.5 mm
Type - Pset_ReinforcementBarPitchOfWall - Description: Tilsvarende: T2 - IVEGG-100 - Forprosjekt
Pset_QuantityTakeOff - Reference: A241 - SVS-76; sets with these values: 2
Pset_WallCommon - Reference: A241 - SVS-76; IsExternal: no; ExtendToStructure: no; LoadBearing: no
AVINOR - 07_Fase: F90; 08_Status: S1; 03_Ansvar: FDV; 04_Kontrakt: 72274; 06_Omrade: TS; 01_Lufthavnkode: ENGM
ePset_Simplebim - Assembly Level: Leaf
ePset_LocationTool - Splitting: RESULT
ePset_SimplebimBasicQuantities - Thickness (Simplebim): 126 mm; Length (Simplebim): 3295 mm
Name (Basic Wall:A241 - SVS-76:...) | In | Volume, net (Simplebim) (m3) | Area, side, net, larger (Simplebim) (m2) = Area, side, net, average (Simplebim) (m2) = Area, side, net, smaller (Simplebim) (m2) | Area, largest surface, net (Simplebim) (m2) | Height (Simplebim) (mm) | Area, side, gross, average (Simplebim) (m2) = Area, side, gross, larger (Simplebim) (m2) = Area, side, gross, smaller (Simplebim) (m2) | Area, side, gross, AABB (Simplebim) (m2)
33212720 | Nivå D + 1,2 m | 0.59393 | 4.75144 | 4.75144 | 1715 | 6.85144 | 5.65092
33212720 | Nivå D | 0.344279 | 2.75423 | 2.1 | 1200 | 4.85423 | 3.954

# IfcWall: Basic Wall:A241 - SXVS-100 (5)
Type - PredefinedType: STANDARD; Material: Plate - Gips 12.5 mm, _NSW X-finer 15 mm, _NSW Stålstender, uisolert 100 mm, Plate - Gips 12.5 mm
Type - Pset_ReinforcementBarPitchOfWall - Description: 12,5mm Gipsplatter - 15mm X-finer - Stendervegg 100mm
AVINOR - 08_Status: S4; 07_Fase: F90; 03_Ansvar: 72717; 05_ID-nummer: +TS=241.039; 02_Prosjekt: 72101; 06_Omrade: TS; 01_Lufthavnkode: ENGM
ePset_SimplebimBasicQuantities - Thickness (Simplebim): 140 mm
Pset_WallCommon - Reference: A241 - SXVS-100; IsExternal: no; ExtendToStructure: no; LoadBearing: no
ePset_Simplebim - Assembly Level: Leaf
ePset_LocationTool - Splitting: ORIGINAL
Pset_QuantityTakeOff - Reference: A241 - SXVS-100; sets with these values: 2
Name (Basic Wall:A241 - SXVS-100:...) | In | Area, side, gross, AABB (Simplebim) (m2) | Area, side, net, smaller (Simplebim) (m2) | Area, side, net, average (Simplebim) (m2) | Area, largest surface, net (Simplebim) (m2) | Area, side, net, larger (Simplebim) (m2) | Volume, net (Simplebim) (m3) | Area, side, gross, average (Simplebim) (m2) | Area, side, gross, smaller (Simplebim) (m2) | Area, side, gross, larger (Simplebim) (m2) | Length (Simplebim) (mm) | Height (Simplebim) (mm)
39099408 | Nivå D | 2.47269 | 1.73964 | 1.73964 | 1.73964 | 1.73964 | 0.241435 | 3.02674 | 3.02674 | 3.02674 | 1947 | 1270 | Identity Data - CQFireRequirement: EI 30
39099408 | Nivå D + 1,2 m | 3.03732 | 2.48222 | 2.48222 | 2.48222 | 2.48222 | 0.344761 | 2.48222 | 2.48222 | 2.48222 | 1947 | 1560 | Identity Data - CQFireRequirement: EI 30
39101029 | Nivå D + 1,2 m | 3.75474 | 3.54881 | 3.61203 | 3.67524 | 3.67524 | 0.505684 | 3.61203 | 3.54881 | 3.67524 | 1976.18 | 1900
39552448 | Nivå D | 4.21818 | 3.12618 | 3.12911 | 3.0597 | 3.13203 | 0.429147 | 5.04921 | 5.04628 | 5.05213 | 3515.15 | 1200
39552448 | Nivå D + 1,2 m | 7.44845 | 6.57117 | 6.59049 | 6.6098 | 6.6098 | 0.886295 | 6.59049 | 6.57117 | 6.6098 | 3546.88 | 2100

# IfcWall: Basic Wall:A241 - SXVXS-100 (10)
Type - PredefinedType: STANDARD; Material: Plate - Gips 12.5 mm, _NSW X-finer 15 mm, _NSW Stålstender, isolert UTEN SKRAVUR 100 mm, _NSW X-finer 15 mm, Plate - Gips 12.5 mm
Type - Pset_ReinforcementBarPitchOfWall - Description: Tilsvarende: T2 - IVEGG-125 - Forprosjekt
AVINOR - 08_Status: S4; 07_Fase: F90; 03_Ansvar: 72717; 02_Prosjekt: 72101; 06_Omrade: TS; 01_Lufthavnkode: ENGM
Pset_ReinforcementBarPitchOfWall - Reference: A241 - SXVXS-100; sets with these values: 2
ePset_Simplebim - Assembly Level: Leaf
Pset_WallCommon - IsExternal: no; ExtendToStructure: no; LoadBearing: no; Reference: A241 - SXVXS-100
Name (Basic Wall:A241 - SXVXS-100:...) | In | Splitting | 05_ID-nummer | Area, side, gross, AABB (Simplebim) (m2) | Thickness (Simplebim) (mm) | Height (Simplebim) (mm) | Length (Simplebim) (mm) | Area, side, net, larger (Simplebim) (m2) = Area, side, net, smaller (Simplebim) (m2) = Area, side, net, average (Simplebim) (m2) | Area, largest surface, net (Simplebim) (m2) | Area, side, gross, average (Simplebim) (m2) = Area, side, gross, larger (Simplebim) (m2) = Area, side, gross, smaller (Simplebim) (m2) | Volume, net (Simplebim) (m3) | CQFireRequirement
39711188 | Nivå D | ORIGINAL | +TS=241.039 | 7.62318 | 155 | 1270 | 6002.5 | 6.41118 | 6.41118 | 8.54227 | 0.993732 | EI 30
39711188 | Nivå D + 1,2 m | ORIGINAL | +TS=241.039 | 12.7253 | 155 | 2120 | 6002.5 | 11.0712 | 11.0712 | 11.0712 | 1.71604 | EI 30
41786590 | Nivå D | ORIGINAL | +TS=241.025 | 3.264 | 155 | 1200 | 2720 | 1.932 | 1.86 | 4.2741 | 0.29946 | EI 30
41786590 | Nivå D + 1,2 m | ORIGINAL | +TS=241.025 | 4.352 | 155 | 1600 | 2720 | 3.26728 | 3.26728 | 3.26728 | 0.506429 | EI 30
41787076 | Nivå D | ORIGINAL | +TS=241.025 | 1.10871 | 155 | 1270 | 873 | 1.10871 | 1.10871 | 1.10871 | 0.17185 | EI 30
41787076 | Nivå D + 1,2 m | ORIGINAL | +TS=241.025 | 1.3968 | 155 | 1600 | 873 | 1.32218 | 1.32218 | 1.32218 | 0.204938 | EI 30
41787245 | Nivå D | ORIGINAL | +TS=241.025 | 3.79523 | 155 | 1200 | 3162.69 | 2.70323 | 1.38 | 4.62333 | 0.419001
41787245 | Nivå D + 1,2 m | ORIGINAL | +TS=241.025 | 5.06031 | 155 | 1600 | 3162.69 | 4.16372 | 4.16372 | 4.16372 | 0.645377
36792460 | Nivå D + 1,2 m | RESULT | +TS=241.039 | 8.8426 | 156 | 1900 | 4654 | 8.84305 | 8.84305 | 8.84305 | 1.37067
36792460 | Nivå D | RESULT | +TS=241.039 | 5.5848 | 155 | 1200 | 4654 | 5.58519 | 5.58519 | 5.58519 | 0.865704

# IfcWall: Basic Wall:A241 - skjørt (SVS-100 S), Basic Wall:A241 - skjørt (SVS-100 S):40386646
In: Nivå D
Type - PredefinedType: STANDARD; Material: Plate - Gips 12.5 mm, _NSW Stålstender, uisolert 100 mm, Plate - Gips 12.5 mm
Type - Pset_ReinforcementBarPitchOfWall - Description: 12.5mm Gipsplater - 100mm Stålstender - 12.5mm Gipsplater
ePset_LocationTool - Splitting: ORIGINAL
ePset_Simplebim - Assembly Level: Leaf
ePset_SimplebimBasicQuantities - Volume, net (Simplebim): 0.615772 m3; Area, side, gross, AABB (Simplebim): 4.94163 m2; Area, side, net, larger (Simplebim): 4.93823 m2; Area, side, gross, larger (Simplebim): 4.93823 m2; Area, largest surface, net (Simplebim): 4.93823 m2; Area, side, net, average (Simplebim): 4.92618 m2; Area, side, gross, average (Simplebim): 4.92618 m2; Area, side, net, smaller (Simplebim): 4.91412 m2; Area, side, gross, smaller (Simplebim): 4.91412 m2; Length (Simplebim): 10981.4 mm; Thickness (Simplebim): 125 mm; Height (Simplebim): 450 mm
Pset_WallCommon - Reference: A241 - skjørt (SVS-100 S); IsExternal: no; ExtendToStructure: no; LoadBearing: no
AVINOR - 08_Status: S4; 07_Fase: F90; 05_ID-nummer: +TS=241.025; 03_Ansvar: 72717; 02_Prosjekt: 72101; 06_Omrade: TS; 01_Lufthavnkode: ENGM
Pset_QuantityTakeOff - Reference: A241 - skjørt (SVS-100 S); sets with these values: 2

# IfcWall: Basic Wall:A241 - skjørt (V-75 S), Basic Wall:A241 - skjørt (V-75 S):42233866
In: Nivå D
Type - PredefinedType: STANDARD; Material: _NSW Stålstender, uisolert 50 mm
Type - Pset_ReinforcementBarPitchOfWall - Description: 75mm Stålstender
Pset_WallCommon - IsExternal: no; ExtendToStructure: no; LoadBearing: no; Reference: A241 - skjørt (V-75 S)
ePset_Simplebim - Assembly Level: Leaf
ePset_LocationTool - Splitting: ORIGINAL
Pset_QuantityTakeOff - Reference: A241 - skjørt (V-75 S); sets with these values: 2
ePset_SimplebimBasicQuantities - Area, side, net, larger (Simplebim): 0.842339 m2; Area, side, gross, larger (Simplebim): 0.842339 m2; Area, largest surface, net (Simplebim): 0.842339 m2; Area, side, gross, average (Simplebim): 0.842339 m2; Area, side, net, average (Simplebim): 0.842339 m2; Area, side, gross, smaller (Simplebim): 0.842339 m2; Area, side, net, smaller (Simplebim): 0.842339 m2; Volume, net (Simplebim): 0.0421169 m3; Length (Simplebim): 1302.34 mm; Thickness (Simplebim): 50 mm; Height (Simplebim): 700 mm; Area, side, gross, AABB (Simplebim): 0.911639 m2
AVINOR - 08_Status: S4; 07_Fase: F90; 05_ID-nummer: +TS=241.025; 03_Ansvar: 72717; 02_Prosjekt: 72101; 06_Omrade: TS; 01_Lufthavnkode: ENGM

# IfcWallStandardCase: Basic Wall:A231 - ISO-80 (15)
Type - PredefinedType: STANDARD; Material: _NSW Isolasjon trykkfast 80 mm
ePset_LocationTool - Splitting: ORIGINAL
AVINOR - 08_Status: S4; 07_Fase: F40; 03_Ansvar: LEIETAKER; 02_Prosjekt: 72101; 06_Omrade: TS; 01_Lufthavnkode: ENGM
Pset_QuantityTakeOff - Reference: A231 - ISO-80; sets with these values: 2
ePset_Simplebim - Assembly Level: Leaf
Pset_WallCommon - IsExternal: yes; ExtendToStructure: no; LoadBearing: no; Reference: A231 - ISO-80
ePset_SimplebimBasicQuantities - Thickness (Simplebim): 80 mm
Name (Basic Wall:A231 - ISO-80:...) | In | Length (Simplebim) (mm) | Area, side, net, larger (Simplebim) (m2) = Area, largest surface, net (Simplebim) (m2) | Volume, net (Simplebim) (m3) | Area, side, gross, AABB (Simplebim) (m2) | Area, side, net, smaller (Simplebim) (m2) | Area, side, net, average (Simplebim) (m2) | Height (Simplebim) (mm) | Area, side, gross, smaller (Simplebim) (m2) | Area, side, gross, average (Simplebim) (m2) | Area, side, gross, larger (Simplebim) (m2)
41788456 | Nivå D | 3205.77 | 3.05172 | 0.242492 | 3.84692 | 3.01058 | 3.03115 | 1200 | 4.50868 | 4.52925 | 4.54982
41788456 | Nivå D + 1,2 m | 3205.77 | 3.4646 | 0.275385 | 4.1675 | 3.42002 | 3.44231 | 1300 | 4.91812 | 4.94041 | 4.9627
41788654 | Nivå D | 1497.75 | 1.7973 | 0.142138 | 1.7973 | 1.75616 | 1.77673 | 1200 | 1.75616 | 1.77673 | 1.7973
41788654 | Nivå D + 1,2 m | 1497.75 | 1.94708 | 0.153983 | 1.94708 | 1.9025 | 1.92479 | 1300 | 1.9025 | 1.92479 | 1.94708
41788793 | Nivå D | 2345.35 | 2.81442 | 0.225154 | 2.81442 | 2.81442 | 2.81442 | 1200 | 2.81442 | 2.81442 | 2.81442
41788793 | Nivå D + 1,2 m | 2345.35 | 3.04896 | 0.243917 | 3.04896 | 3.04896 | 3.04896 | 1300 | 3.04896 | 3.04896 | 3.04896
41788924 | Nivå D | 7961.12 | 9.55334 | 0.764267 | 9.55334 | 9.55334 | 9.55334 | 1200 | 9.55334 | 9.55334 | 9.55334
41788924 | Nivå D + 1,2 m | 7961.12 | 10.3495 | 0.827956 | 10.3495 | 10.3495 | 10.3495 | 1300 | 10.3495 | 10.3495 | 10.3495
41789048 | Nivå D | 769.113 | 0.922935 | 0.072189 | 0.922935 | 0.88179 | 0.902362 | 1200 | 0.88179 | 0.902362 | 0.922935
41789048 | Nivå D + 1,2 m | 769.113 | 0.999847 | 0.0782047 | 0.999847 | 0.955272 | 0.977559 | 1300 | 0.955272 | 0.977559 | 0.999847
41789153 | Nivå D | 1118.91 | 1.34269 | 0.107415 | 1.34269 | 1.34269 | 1.34269 | 1200 | 1.34269 | 1.34269 | 1.34269
41789153 | Nivå D + 1,2 m | 1118.91 | 1.45458 | 0.116367 | 1.45458 | 1.45458 | 1.45458 | 1300 | 1.45458 | 1.45458 | 1.45458
41789231 | Nivå D | 1166.1 | 1.39932 | 0.1103 | 1.39932 | 1.35817 | 1.37875 | 1200 | 1.35817 | 1.37875 | 1.39932
41789231 | Nivå D + 1,2 m | 1166.1 | 1.51593 | 0.119491 | 1.51593 | 1.47135 | 1.49364 | 1300 | 1.47135 | 1.49364 | 1.51593
42213555 | Nivå D | 3759.95 | 1.72958 | 0.138366 | 1.72958 | 1.72958 | 1.72958 | 460 | 1.72958 | 1.72958 | 1.72958

# IfcWallStandardCase: Basic Wall:A241 - FXVF-100 (100/100 pp-p) (2)
Type - PredefinedType: STANDARD; Material: T2_Gips Protect F 15 mm, _NSW X-finer 15 mm, _NSW Stålstender, uisolert 100 mm, T2_Gips Protect F 15 mm
Type - Pset_ReinforcementBarPitchOfWall - Description: Tilsvarende: T2 - IVEGG-150 - Forprosjekt
Pset_WallCommon - IsExternal: no; ExtendToStructure: no; LoadBearing: no; Reference: A241 - FXVF-100 (100/100 pp-p)
AVINOR - 08_Status: S4; 07_Fase: F90; 03_Ansvar: 72717; 05_ID-nummer: +TS=241.039; 02_Prosjekt: 72101; 06_Omrade: TS; 01_Lufthavnkode: ENGM
ePset_SimplebimBasicQuantities - Thickness (Simplebim): 145 mm; Length (Simplebim): 1707.49 mm
ePset_Simplebim - Assembly Level: Leaf
Pset_QuantityTakeOff - Reference: A241 - FXVF-100 (100/100 pp-p); sets with these values: 2
ePset_LocationTool - Splitting: ORIGINAL
Name (Basic Wall:A241 - FXVF-100 (100/100 pp-p):...) | In | Volume, net (Simplebim) (m3) | Height (Simplebim) (mm) | Area, side, gross, AABB (Simplebim) (m2) = Area, side, net, larger (Simplebim) (m2) = Area, side, gross, smaller (Simplebim) (m2) = Area, side, gross, larger (Simplebim) (m2) = Area, side, gross, average (Simplebim) (m2) = Area, largest surface, net (Simplebim) (m2) = Area, side, net, average (Simplebim) (m2) = Area, side, net, smaller (Simplebim) (m2)
39208011 | Nivå D | 0.280783 | 1200 | 2.04899
39208011 | Nivå D + 1,2 m | 0.374377 | 1600 | 2.73198

# IfcWallStandardCase: Basic Wall:A241 - S (g-0) (4)
Type - PredefinedType: STANDARD; Material: T2_Gips Standard 12.5 mm
Type - Pset_ReinforcementBarPitchOfWall - Description: 1 lag gips
Pset_WallCommon - IsExternal: no; ExtendToStructure: no; LoadBearing: no; Reference: A241 - S (g-0)
ePset_LocationTool - Splitting: ORIGINAL
AVINOR - 08_Status: S4; 07_Fase: F40; 03_Ansvar: LEIETAKER; 02_Prosjekt: 72101; 06_Omrade: TS; 01_Lufthavnkode: ENGM
ePset_Simplebim - Assembly Level: Leaf
ePset_SimplebimBasicQuantities - Thickness (Simplebim): 12.5 mm
Pset_ReinforcementBarPitchOfWall - Reference: A241 - S (g-0); sets with these values: 2
Name (Basic Wall:A241 - S (g-0):...) | In | Length (Simplebim) (mm) | Area, side, net, larger (Simplebim) (m2) = Area, side, gross, larger (Simplebim) (m2) = Area, largest surface, net (Simplebim) (m2) = Area, side, gross, AABB (Simplebim) (m2) | Area, side, gross, smaller (Simplebim) (m2) = Area, side, net, smaller (Simplebim) (m2) | Area, side, gross, average (Simplebim) (m2) = Area, side, net, average (Simplebim) (m2) | Volume, net (Simplebim) (m3) | Height (Simplebim) (mm)
42213894 | Nivå D | 3939.95 | 1.41838 | 1.41838 | 1.41838 | 0.0177298 | 360
42214659 | Nivå D | 1502.01 | 1.80241 | 1.79598 | 1.7992 | 0.02249 | 1200
42214659 | Nivå D + 1,2 m | 1502.01 | 1.95261 | 1.94565 | 1.94913 | 0.0243641 | 1300
42215877 | Nivå D | 3601.24 | 0.360124 | 0.360124 | 0.360124 | 0.00450155 | 100

# IfcWallStandardCase: Basic Wall:A241 - SV-75 (6)
Type - PredefinedType: STANDARD; Material: Plate - Gips 12.5 mm, _NSW Stålstender, uisolert 75 mm
Type - Pset_ReinforcementBarPitchOfWall - Description: Tilsvarende: T2 - IVEGG-100 - Forprosjekt
Pset_ReinforcementBarPitchOfWall - Reference: A241 - SV-75; sets with these values: 2
ePset_Simplebim - Assembly Level: Leaf
Pset_WallCommon - IsExternal: no; ExtendToStructure: no; LoadBearing: no; Reference: A241 - SV-75
ePset_SimplebimBasicQuantities - Thickness (Simplebim): 87.5 mm
ePset_LocationTool - Splitting: ORIGINAL
AVINOR - 08_Status: S4; 07_Fase: F90; 05_ID-nummer: +TS=241.025; 03_Ansvar: 72717; 02_Prosjekt: 72101; 06_Omrade: TS; 01_Lufthavnkode: ENGM
Name (Basic Wall:A241 - SV-75:...) | In | Length (Simplebim) (mm) | Area, side, gross, AABB (Simplebim) (m2) = Area, side, gross, larger (Simplebim) (m2) = Area, side, net, larger (Simplebim) (m2) = Area, side, gross, smaller (Simplebim) (m2) = Area, side, net, smaller (Simplebim) (m2) = Area, largest surface, net (Simplebim) (m2) = Area, side, net, average (Simplebim) (m2) = Area, side, gross, average (Simplebim) (m2) | Volume, net (Simplebim) (m3) | Height (Simplebim) (mm)
41948450 | Nivå D | 1337.2 | 1.60465 | 0.140406 | 1200
41948450 | Nivå D + 1,2 m | 1337.2 | 2.07267 | 0.181358 | 1550
41948452 | Nivå D | 408.369 | 0.490042 | 0.0428787 | 1200
41948452 | Nivå D + 1,2 m | 408.369 | 0.632971 | 0.055385 | 1550
41948453 | Nivå D | 205.452 | 0.246543 | 0.0215725 | 1200
41948453 | Nivå D + 1,2 m | 205.452 | 0.318451 | 0.0278644 | 1550

# IfcWallStandardCase: Basic Wall:A241 - SVS-101 (100/100 gg-gg) (4)
Type - PredefinedType: STANDARD; Material: Plate - Gips 12.5 mm, Plate - Gips 12.5 mm, _NSW Stålstender, uisolert 100 mm, Plate - Gips 12.5 mm, Plate - Gips 12.5 mm
Type - Pset_ReinforcementBarPitchOfWall - Description: Stendervegg: 2x12.5mm Gipsplater - 100mm Stålstender - 2x12.5mm Gipsplater
Pset_ReinforcementBarPitchOfWall - Reference: A241 - SVS-101 (100/100 gg-gg); sets with these values: 2
AVINOR - 07_Fase: F90; 03_Ansvar: FDV; 08_Status: S2; 06_Omrade: TS; 01_Lufthavnkode: ENGM
ePset_Simplebim - Assembly Level: Leaf
ePset_LocationTool - Splitting: ORIGINAL
ePset_SimplebimBasicQuantities - Thickness (Simplebim): 150 mm
Pset_WallCommon - IsExternal: no; ExtendToStructure: no; LoadBearing: no; Reference: A241 - SVS-101 (100/100 gg-gg)
Name (Basic Wall:A241 - SVS-101 (100/100 gg-gg):...) | In | Length (Simplebim) (mm) | Area, side, gross, larger (Simplebim) (m2) = Area, side, gross, smaller (Simplebim) (m2) = Area, side, net, larger (Simplebim) (m2) = Area, side, net, average (Simplebim) (m2) = Area, largest surface, net (Simplebim) (m2) = Area, side, gross, average (Simplebim) (m2) = Area, side, net, smaller (Simplebim) (m2) = Area, side, gross, AABB (Simplebim) (m2) | Height (Simplebim) (mm) | Volume, net (Simplebim) (m3)
25596214 | Nivå D | 3370 | 4.044 | 1200 | 0.6066 | AVINOR - 04_Kontrakt: 72274; Identity Data - CQFireRequirement: EI 30
25596214 | Nivå D + 1,2 m | 3370 | 5.77974 | 1715.06 | 0.866961 | AVINOR - 04_Kontrakt: 72274; Identity Data - CQFireRequirement: EI 30
28038461 | Nivå D | 10142.5 | 12.171 | 1200 | 1.82565
28038461 | Nivå D + 1,2 m | 10142.5 | 16.1266 | 1590 | 2.41899

# IfcWallStandardCase: Basic Wall:A241 - SVS-121 (120/100x2 gg-gg S120 B=172mm) (2)
Type - PredefinedType: STANDARD; Material: Plate - Gips 12.5 mm, Plate - Gips 12.5 mm, _NSW Stålstender, uisolert 120 mm, Plate - Gips 12.5 mm, Plate - Gips 12.5 mm
Pset_QuantityTakeOff - Reference: A241 - SVS-121 (120/100x2 gg-gg S120 B=172mm); sets with these values: 2
AVINOR - 07_Fase: F90; 03_Ansvar: FDV; 08_Status: S2; 06_Omrade: TS; 01_Lufthavnkode: ENGM
ePset_Simplebim - Assembly Level: Leaf
Pset_WallCommon - IsExternal: no; ExtendToStructure: no; LoadBearing: no; Reference: A241 - SVS-121 (120/100x2 gg-gg S120 B=172mm)
ePset_LocationTool - Splitting: ORIGINAL
ePset_SimplebimBasicQuantities - Thickness (Simplebim): 170 mm; Length (Simplebim): 6864.5 mm
Name (Basic Wall:A241 - SVS-121 (120/100x2 gg-gg S120 B=172mm):...) | In | Volume, net (Simplebim) (m3) | Area, side, gross, AABB (Simplebim) (m2) = Area, side, gross, smaller (Simplebim) (m2) = Area, side, net, larger (Simplebim) (m2) = Area, side, gross, larger (Simplebim) (m2) = Area, side, gross, average (Simplebim) (m2) = Area, side, net, average (Simplebim) (m2) = Area, largest surface, net (Simplebim) (m2) = Area, side, net, smaller (Simplebim) (m2) | Height (Simplebim) (mm)
2375435 | Nivå D | 1.40036 | 8.2374 | 1200
2375435 | Nivå D + 1,2 m | 2.10054 | 12.3561 | 1800

# IfcWallStandardCase: Basic Wall:A241 - SVS-200 (T1) (200/100x2 gg-gg) (2)
Type - PredefinedType: STANDARD; Material: Plate - Gips 12.5 mm, Plate - Gips 12.5 mm, _NSW Stålstender, uisolert 200 mm, Plate - Gips 12.5 mm, Plate - Gips 12.5 mm
Type - Pset_ReinforcementBarPitchOfWall - Description: Stendervegg: 2x12.5mm Gipsplater - 200mm Svill, 100mm Stålstender - 2x12.5mm Gipsplater
ePset_LocationTool - Splitting: ORIGINAL
AVINOR - 07_Fase: F90; 03_Ansvar: FDV; 08_Status: S2; 06_Omrade: TS; 01_Lufthavnkode: ENGM
Identity Data - CQFireRequirement: EI 60/ A2-s1,d0
ePset_Simplebim - Assembly Level: Leaf
Pset_QuantityTakeOff - Reference: A241 - SVS-200 (T1) (200/100x2 gg-gg); sets with these values: 2
ePset_SimplebimBasicQuantities - Length (Simplebim): 1912.5 mm; Thickness (Simplebim): 250 mm
Pset_WallCommon - IsExternal: no; ExtendToStructure: no; LoadBearing: no; Reference: A241 - SVS-200 (T1) (200/100x2 gg-gg)
Name (Basic Wall:A241 - SVS-200 (T1) (200/100x2 gg-gg):...) | In | Area, largest surface, net (Simplebim) (m2) = Area, side, net, average (Simplebim) (m2) = Area, side, gross, average (Simplebim) (m2) = Area, side, net, smaller (Simplebim) (m2) = Area, side, gross, AABB (Simplebim) (m2) = Area, side, gross, larger (Simplebim) (m2) = Area, side, net, larger (Simplebim) (m2) = Area, side, gross, smaller (Simplebim) (m2) | Volume, net (Simplebim) (m3) | Height (Simplebim) (mm)
2375500 | Nivå D | 2.295 | 0.57375 | 1200
2375500 | Nivå D + 1,2 m | 4.0545 | 1.01362 | 2120

# IfcWallStandardCase: Basic Wall:A241 - SVS-75 (75/75 g-g) (4)
Type - PredefinedType: STANDARD; Material: Plate - Gips 12.5 mm, _NSW Stålstender, uisolert 75 mm, Plate - Gips 12.5 mm
Type - Pset_ReinforcementBarPitchOfWall - Description: Tilsvarende: T2 - IVEGG-100 - Forprosjekt
Pset_QuantityTakeOff - Reference: A241 - SVS-75 (75/75 g-g); sets with these values: 2
ePset_Simplebim - Assembly Level: Leaf
ePset_SimplebimBasicQuantities - Thickness (Simplebim): 100 mm
AVINOR - 08_Status: S4; 07_Fase: F90; 05_ID-nummer: +TS=241.025; 03_Ansvar: 72717; 02_Prosjekt: 72101; 06_Omrade: TS; 01_Lufthavnkode: ENGM
ePset_LocationTool - Splitting: ORIGINAL
Pset_WallCommon - Reference: A241 - SVS-75 (75/75 g-g); IsExternal: no; ExtendToStructure: no; LoadBearing: no
Name (Basic Wall:A241 - SVS-75 (75/75 g-g):...) | In | Length (Simplebim) (mm) | Volume, net (Simplebim) (m3) | Area, side, gross, AABB (Simplebim) (m2) = Area, largest surface, net (Simplebim) (m2) = Area, side, net, average (Simplebim) (m2) = Area, side, gross, average (Simplebim) (m2) = Area, side, net, smaller (Simplebim) (m2) = Area, side, gross, larger (Simplebim) (m2) = Area, side, net, larger (Simplebim) (m2) = Area, side, gross, smaller (Simplebim) (m2) | Height (Simplebim) (mm)
41948449 | Nivå D | 483.369 | 0.0580042 | 0.580042 | 1200
41948449 | Nivå D + 1,2 m | 483.369 | 0.0749221 | 0.749221 | 1550
41948451 | Nivå D | 197.993 | 0.0237592 | 0.237592 | 1200
41948451 | Nivå D + 1,2 m | 197.993 | 0.030689 | 0.30689 | 1550

# IfcWallStandardCase: Basic Wall:A241 - SX (4)
Type - PredefinedType: STANDARD; Material: _NSW X-finer 15 mm, Plate - Gips 12.5 mm
AVINOR - 08_Status: S4; 07_Fase: F90; 03_Ansvar: 72717; 05_ID-nummer: +TS=241.039; 02_Prosjekt: 72101; 06_Omrade: TS; 01_Lufthavnkode: ENGM
ePset_SimplebimBasicQuantities - Thickness (Simplebim): 27.5 mm
Pset_QuantityTakeOff - Reference: A241 - SX; sets with these values: 2
ePset_Simplebim - Assembly Level: Leaf
ePset_LocationTool - Splitting: ORIGINAL
Pset_WallCommon - IsExternal: no; ExtendToStructure: no; LoadBearing: no; Reference: A241 - SX
Name (Basic Wall:A241 - SX:...) | In | Volume, net (Simplebim) (m3) | Height (Simplebim) (mm) | Length (Simplebim) (mm) | Area, side, net, larger (Simplebim) (m2) = Area, side, gross, smaller (Simplebim) (m2) = Area, side, gross, larger (Simplebim) (m2) = Area, side, gross, average (Simplebim) (m2) = Area, largest surface, net (Simplebim) (m2) = Area, side, net, average (Simplebim) (m2) = Area, side, net, smaller (Simplebim) (m2) = Area, side, gross, AABB (Simplebim) (m2)
42142579 | Nivå D | 0.396907 | 1200 | 12027.5 | 14.433
42142579 | Nivå D + 1,2 m | 0.525902 | 1590 | 12027.5 | 19.1237
42152552 | Nivå D | 0.108576 | 1200 | 3290.19 | 3.94823
42152552 | Nivå D + 1,2 m | 0.143864 | 1590 | 3290.19 | 5.2314

# IfcWallStandardCase: Basic Wall:A241 - SXV-76 (8)
Type - PredefinedType: STANDARD; Material: Plate - Gips 12.5 mm, _NSW X-finer 15 mm, _NSW Stålstender, uisolert 75 mm
ePset_SimplebimBasicQuantities - Thickness (Simplebim): 102.5 mm
AVINOR - 08_Status: S4; 07_Fase: F90; 03_Ansvar: 72717; 05_ID-nummer: +TS=241.039; 02_Prosjekt: 72101; 06_Omrade: TS; 01_Lufthavnkode: ENGM
ePset_LocationTool - Splitting: ORIGINAL
Pset_ReinforcementBarPitchOfWall - Reference: A241 - SXV-76; sets with these values: 2
Pset_WallCommon - Reference: A241 - SXV-76; IsExternal: no; ExtendToStructure: no; LoadBearing: no
ePset_Simplebim - Assembly Level: Leaf
Name (Basic Wall:A241 - SXV-76:...) | In | Area, side, net, smaller (Simplebim) (m2) = Area, side, gross, smaller (Simplebim) (m2) | Area, side, gross, AABB (Simplebim) (m2) | Area, largest surface, net (Simplebim) (m2) = Area, side, gross, larger (Simplebim) (m2) = Area, side, net, larger (Simplebim) (m2) | Length (Simplebim) (mm) | Volume, net (Simplebim) (m3) | Height (Simplebim) (mm) | Area, side, gross, average (Simplebim) (m2) = Area, side, net, average (Simplebim) (m2)
40012767 | Nivå D | 0.9011 | 0.902978 | 0.902978 | 752.482 | 0.092459 | 1200 | 0.902039
40012767 | Nivå D + 1,2 m | 1.42674 | 1.42972 | 1.42972 | 752.482 | 0.146393 | 1900 | 1.42823
40012924 | Nivå D | 0.820362 | 0.878826 | 0.878826 | 732.355 | 0.0870834 | 1200 | 0.849594
40012924 | Nivå D + 1,2 m | 1.29891 | 1.39147 | 1.39147 | 732.355 | 0.137882 | 1900 | 1.34519
40015813 | Nivå D | 0.925601 | 0.981593 | 0.980722 | 817.994 | 0.0976991 | 1200 | 0.953162
40015813 | Nivå D + 1,2 m | 1.46553 | 1.55419 | 1.55281 | 817.994 | 0.15469 | 1900 | 1.50917
40015913 | Nivå D | 0.670545 | 0.723071 | 0.723071 | 602.559 | 0.0714228 | 1200 | 0.696808
40015913 | Nivå D + 1,2 m | 1.0617 | 1.14486 | 1.14486 | 602.559 | 0.113086 | 1900 | 1.10328

# IfcWallStandardCase: Basic Wall:A241 - SXVS-100 (5)
Type - PredefinedType: STANDARD; Material: Plate - Gips 12.5 mm, _NSW X-finer 15 mm, _NSW Stålstender, uisolert 100 mm, Plate - Gips 12.5 mm
Type - Pset_ReinforcementBarPitchOfWall - Description: 12,5mm Gipsplatter - 15mm X-finer - Stendervegg 100mm
AVINOR - 08_Status: S4; 07_Fase: F90; 03_Ansvar: 72717; 05_ID-nummer: +TS=241.039; 02_Prosjekt: 72101; 06_Omrade: TS; 01_Lufthavnkode: ENGM
Pset_WallCommon - Reference: A241 - SXVS-100; IsExternal: no; ExtendToStructure: no; LoadBearing: no
ePset_Simplebim - Assembly Level: Leaf
ePset_SimplebimBasicQuantities - Thickness (Simplebim): 140 mm
Pset_QuantityTakeOff - Reference: A241 - SXVS-100; sets with these values: 2
ePset_LocationTool - Splitting: ORIGINAL
Name (Basic Wall:A241 - SXVS-100:...) | In | Area, side, net, smaller (Simplebim) (m2) = Area, side, gross, smaller (Simplebim) (m2) | Area, side, gross, average (Simplebim) (m2) = Area, side, net, average (Simplebim) (m2) | Area, side, gross, larger (Simplebim) (m2) = Area, side, net, larger (Simplebim) (m2) = Area, largest surface, net (Simplebim) (m2) = Area, side, gross, AABB (Simplebim) (m2) | Height (Simplebim) (mm) | Length (Simplebim) (mm) | Volume, net (Simplebim) (m3)
39101029 | Nivå D | 2.29156 | 2.33149 | 2.37142 | 1200 | 1976.18 | 0.326409
39552449 | Nivå D | 0.537 | 0.537 | 0.537 | 1200 | 447.5 | 0.07518
39552449 | Nivå D + 1,2 m | 0.67125 | 0.67125 | 0.67125 | 1500 | 447.5 | 0.093975
40016324 | Nivå D | 1.18787 | 1.22305 | 1.25823 | 1200 | 1048.53 | 0.171227
40016324 | Nivå D + 1,2 m | 1.88079 | 1.9365 | 1.9922 | 1900 | 1048.53 | 0.271109

# IfcWallStandardCase: Basic Wall:A241 - SXVXS-100 (6)
Type - PredefinedType: STANDARD; Material: Plate - Gips 12.5 mm, _NSW X-finer 15 mm, _NSW Stålstender, isolert UTEN SKRAVUR 100 mm, _NSW X-finer 15 mm, Plate - Gips 12.5 mm
Type - Pset_ReinforcementBarPitchOfWall - Description: Tilsvarende: T2 - IVEGG-125 - Forprosjekt
AVINOR - 08_Status: S4; 07_Fase: F90; 03_Ansvar: 72717; 02_Prosjekt: 72101; 06_Omrade: TS; 01_Lufthavnkode: ENGM
ePset_LocationTool - Splitting: ORIGINAL
Pset_ReinforcementBarPitchOfWall - Reference: A241 - SXVXS-100; sets with these values: 2
ePset_Simplebim - Assembly Level: Leaf
Pset_WallCommon - IsExternal: no; ExtendToStructure: no; LoadBearing: no; Reference: A241 - SXVXS-100
ePset_SimplebimBasicQuantities - Thickness (Simplebim): 155 mm
Identity Data - CQFireRequirement: EI 30
Name (Basic Wall:A241 - SXVXS-100:...) | In | 05_ID-nummer | Volume, net (Simplebim) (m3) | Height (Simplebim) (mm) | Area, side, net, average (Simplebim) (m2) = Area, largest surface, net (Simplebim) (m2) = Area, side, net, smaller (Simplebim) (m2) = Area, side, net, larger (Simplebim) (m2) = Area, side, gross, AABB (Simplebim) (m2) | Area, side, gross, average (Simplebim) (m2) = Area, side, gross, larger (Simplebim) (m2) = Area, side, gross, smaller (Simplebim) (m2) | Length (Simplebim) (mm)
9822568 | Nivå D | +TS=241.039 | 1.23133 | 1270 | 7.94409 | 7.94409 | 6255.19
9822568 | Nivå D + 1,2 m | +TS=241.039 | 2.05546 | 2120 | 13.261 | 13.261 | 6255.19
41786404 | Nivå D | +TS=241.025 | 0.500652 | 1200 | 3.54 | 3.9404 | 2950
41786404 | Nivå D + 1,2 m | +TS=241.025 | 0.7316 | 1600 | 4.72 | 4.72 | 2950
41787155 | Nivå D | +TS=241.025 | 0.035433 | 1270 | 0.2286 | 0.2286 | 180
41787155 | Nivå D + 1,2 m | +TS=241.025 | 0.04464 | 1600 | 0.288 | 0.288 | 180

# IfcWallStandardCase: Basic Wall:A241 - V-75 (5)
In: Nivå D
Type - PredefinedType: STANDARD; Material: _NSW Stålstender, uisolert 75 mm
Type - Pset_ReinforcementBarPitchOfWall - Description: 75mm stenderverk
ePset_SimplebimBasicQuantities - Thickness (Simplebim): 75 mm; Height (Simplebim): 350 mm
Pset_QuantityTakeOff - Reference: A241 - V-75; sets with these values: 2
ePset_LocationTool - Splitting: ORIGINAL
ePset_Simplebim - Assembly Level: Leaf
AVINOR - 08_Status: S4; 07_Fase: F90; 05_ID-nummer: +TS=241.025; 03_Ansvar: 72717; 02_Prosjekt: 72101; 06_Omrade: TS; 01_Lufthavnkode: ENGM
Pset_WallCommon - IsExternal: no; ExtendToStructure: no; LoadBearing: no; Reference: A241 - V-75
Name (Basic Wall:A241 - V-75:...) | Length (Simplebim) (mm) | Area, side, net, larger (Simplebim) (m2) = Area, side, gross, smaller (Simplebim) (m2) = Area, side, gross, larger (Simplebim) (m2) = Area, side, net, smaller (Simplebim) (m2) = Area, side, gross, average (Simplebim) (m2) = Area, largest surface, net (Simplebim) (m2) = Area, side, net, average (Simplebim) (m2) | Area, side, gross, AABB (Simplebim) (m2) | Volume, net (Simplebim) (m3)
42217171 | 192.952 | 0.0675333 | 0.0675332 | 0.00506499
42340709 | 1349.7 | 0.472397 | 0.472397 | 0.0354297
42340710 | 420.869 | 0.147304 | 0.147304 | 0.0110478
42340711 | 495.869 | 0.173554 | 0.173554 | 0.0130165
42362781 | 185.493 | 0.0649227 | 0.0649227 | 0.0048692

# IfcWallStandardCase: Basic Wall:A241 - XV-75 (2)
Type - PredefinedType: STANDARD; Material: _NSW X-finer 15 mm, _NSW Stålstender, uisolert 75 mm
AVINOR - 08_Status: S4; 07_Fase: F90; 03_Ansvar: 72717; 05_ID-nummer: +TS=241.039; 02_Prosjekt: 72101; 06_Omrade: TS; 01_Lufthavnkode: ENGM
ePset_SimplebimBasicQuantities - Length (Simplebim): 599.31 mm; Thickness (Simplebim): 90 mm
ePset_LocationTool - Splitting: ORIGINAL
ePset_Simplebim - Assembly Level: Leaf
Pset_QuantityTakeOff - Reference: A241 - XV-75; sets with these values: 2
Pset_WallCommon - IsExternal: no; ExtendToStructure: no; LoadBearing: no; Reference: A241 - XV-75
Name (Basic Wall:A241 - XV-75:...) | In | Area, side, gross, average (Simplebim) (m2) = Area, side, net, average (Simplebim) (m2) | Volume, net (Simplebim) (m3) | Area, side, net, smaller (Simplebim) (m2) = Area, side, gross, smaller (Simplebim) (m2) | Area, side, gross, AABB (Simplebim) (m2) = Area, largest surface, net (Simplebim) (m2) = Area, side, gross, larger (Simplebim) (m2) = Area, side, net, larger (Simplebim) (m2) | Height (Simplebim) (mm)
40118505 | Nivå D | 0.693448 | 0.0624103 | 0.667724 | 0.719172 | 1200
40118505 | Nivå D + 1,2 m | 1.09796 | 0.0988163 | 1.05723 | 1.13869 | 1900

# IfcWallStandardCase: Basic Wall:A241 - skjørt (SV-75 S), Basic Wall:A241 - skjørt (SV-75 S):42217932
In: Nivå D
Type - PredefinedType: STANDARD; Material: _NSW Stålstender, uisolert 75 mm, Plate - Gips 12.5 mm
Type - Pset_ReinforcementBarPitchOfWall - Description: 12.5mm Gipsplater - 100mm Stålstender
ePset_SimplebimBasicQuantities - Height (Simplebim): 250 mm; Area, side, gross, AABB (Simplebim): 0.984987 m2; Area, side, gross, larger (Simplebim): 0.984987 m2; Area, side, net, larger (Simplebim): 0.984987 m2; Area, side, gross, smaller (Simplebim): 0.984987 m2; Area, largest surface, net (Simplebim): 0.984987 m2; Area, side, net, average (Simplebim): 0.984987 m2; Area, side, gross, average (Simplebim): 0.984987 m2; Area, side, net, smaller (Simplebim): 0.984987 m2; Volume, net (Simplebim): 0.0861863 m3; Length (Simplebim): 3939.95 mm; Thickness (Simplebim): 87.5 mm
ePset_LocationTool - Splitting: ORIGINAL
ePset_Simplebim - Assembly Level: Leaf
Pset_QuantityTakeOff - Reference: A241 - skjørt (SV-75 S); sets with these values: 2
Pset_WallCommon - Reference: A241 - skjørt (SV-75 S); IsExternal: no; ExtendToStructure: no; LoadBearing: no
AVINOR - 08_Status: S4; 07_Fase: F90; 05_ID-nummer: +TS=241.025; 03_Ansvar: 72717; 02_Prosjekt: 72101; 06_Omrade: TS; 01_Lufthavnkode: ENGM

# IfcWallStandardCase: Basic Wall:A241 - skjørt (SVS-75 S) (6)
In: Nivå D
Type - PredefinedType: STANDARD; Material: Plate - Gips 12.5 mm, _NSW Stålstender, uisolert 75 mm, Plate - Gips 12.5 mm
Type - Pset_ReinforcementBarPitchOfWall - Description: 12.5mm Gipsplater - 75mm Stålstender - 12.5mm Gipsplater
ePset_SimplebimBasicQuantities - Thickness (Simplebim): 100 mm
ePset_LocationTool - Splitting: ORIGINAL
ePset_Simplebim - Assembly Level: Leaf
Pset_ReinforcementBarPitchOfWall - Reference: A241 - skjørt (SVS-75 S); sets with these values: 2
Pset_WallCommon - Reference: A241 - skjørt (SVS-75 S); IsExternal: no; ExtendToStructure: no; LoadBearing: no
AVINOR - 08_Status: S4; 07_Fase: F90; 05_ID-nummer: +TS=241.025; 03_Ansvar: 72717; 02_Prosjekt: 72101; 06_Omrade: TS; 01_Lufthavnkode: ENGM
Name (Basic Wall:A241 - skjørt (SVS-75 S):...) | Length (Simplebim) (mm) | Height (Simplebim) (mm) | Volume, net (Simplebim) (m3) | Area, side, gross, AABB (Simplebim) (m2) = Area, side, net, larger (Simplebim) (m2) = Area, side, gross, larger (Simplebim) (m2) = Area, largest surface, net (Simplebim) (m2) | Area, side, gross, smaller (Simplebim) (m2) = Area, side, net, smaller (Simplebim) (m2) | Area, side, gross, average (Simplebim) (m2) = Area, side, net, average (Simplebim) (m2)
42197614 | 660.063 | 710 | 0.0468645 | 0.468645 | 0.468645 | 0.468645
42197769 | 308.709 | 710 | 0.0201869 | 0.219183 | 0.184554 | 0.201869
42197897 | 323.491 | 710 | 0.0212364 | 0.229679 | 0.19505 | 0.212364
42213929 | 3204.21 | 710 | 0.227499 | 2.27499 | 2.27499 | 2.27499
42214058 | 1249.7 | 710 | 0.088729 | 0.88729 | 0.88729 | 0.88729
42233865 | 1302.34 | 360 | 0.0468843 | 0.468843 | 0.468843 | 0.468843

# IfcWallStandardCase: Basic Wall:A241 - skjørt (V-100 S), Basic Wall:A241 - skjørt (V-100 S):42212686
In: Nivå D
Type - PredefinedType: STANDARD; Material: _NSW Stålstender, uisolert 100 mm
Type - Pset_ReinforcementBarPitchOfWall - Description: 100mm Stålstender
ePset_LocationTool - Splitting: ORIGINAL
Pset_WallCommon - Reference: A241 - skjørt (V-100 S); IsExternal: no; ExtendToStructure: no; LoadBearing: no
Pset_QuantityTakeOff - Reference: A241 - skjørt (V-100 S); sets with these values: 2
ePset_Simplebim - Assembly Level: Leaf
ePset_SimplebimBasicQuantities - Area, side, gross, AABB (Simplebim): 3.84599 m2; Area, side, gross, larger (Simplebim): 3.84599 m2; Area, side, net, larger (Simplebim): 3.84599 m2; Area, largest surface, net (Simplebim): 3.84599 m2; Area, side, net, smaller (Simplebim): 3.83099 m2; Area, side, gross, smaller (Simplebim): 3.83099 m2; Length (Simplebim): 10988.5 mm; Area, side, gross, average (Simplebim): 3.83849 m2; Area, side, net, average (Simplebim): 3.83849 m2; Thickness (Simplebim): 100 mm; Height (Simplebim): 350 mm; Volume, net (Simplebim): 0.383849 m3
AVINOR - 08_Status: S4; 07_Fase: F90; 05_ID-nummer: +TS=241.025; 03_Ansvar: 72717; 02_Prosjekt: 72101; 06_Omrade: TS; 01_Lufthavnkode: ENGM

# IfcWallStandardCase: Basic Wall:A241 - skjørt (V-75 S) (6)
In: Nivå D
Type - PredefinedType: STANDARD; Material: _NSW Stålstender, uisolert 50 mm
Type - Pset_ReinforcementBarPitchOfWall - Description: 75mm Stålstender
ePset_LocationTool - Splitting: ORIGINAL
Pset_WallCommon - IsExternal: no; ExtendToStructure: no; LoadBearing: no; Reference: A241 - skjørt (V-75 S)
ePset_Simplebim - Assembly Level: Leaf
ePset_SimplebimBasicQuantities - Thickness (Simplebim): 50 mm; Height (Simplebim): 350 mm
Pset_QuantityTakeOff - Reference: A241 - skjørt (V-75 S); sets with these values: 2
AVINOR - 08_Status: S4; 07_Fase: F90; 05_ID-nummer: +TS=241.025; 03_Ansvar: 72717; 02_Prosjekt: 72101; 06_Omrade: TS; 01_Lufthavnkode: ENGM
Name (Basic Wall:A241 - skjørt (V-75 S):...) | Area, largest surface, net (Simplebim) (m2) = Area, side, gross, larger (Simplebim) (m2) = Area, side, net, larger (Simplebim) (m2) = Area, side, gross, AABB (Simplebim) (m2) | Area, side, net, average (Simplebim) (m2) = Area, side, gross, average (Simplebim) (m2) | Area, side, net, smaller (Simplebim) (m2) = Area, side, gross, smaller (Simplebim) (m2) | Length (Simplebim) (mm) | Volume, net (Simplebim) (m3)
42233860 | 0.222272 | 0.222272 | 0.222272 | 635.063 | 0.0111136
42233861 | 0.0940451 | 0.0897774 | 0.0855098 | 268.7 | 0.00448887
42233862 | 0.12744 | 0.123172 | 0.118904 | 364.113 | 0.0061586
42362780 | 1.12147 | 1.12147 | 1.12147 | 3204.21 | 0.0560736
42362782 | 0.446147 | 0.446147 | 0.446147 | 1274.7 | 0.0223073
42401819 | 1.49828 | 1.49828 | 1.49828 | 4280.79 | 0.0749139
